VERSION 5.8 ;
BUSBITCHARS "[]" ;
DIVIDERCHAR "/" ;
UNITS
    DATABASE MICRONS 1000 ;
END UNITS

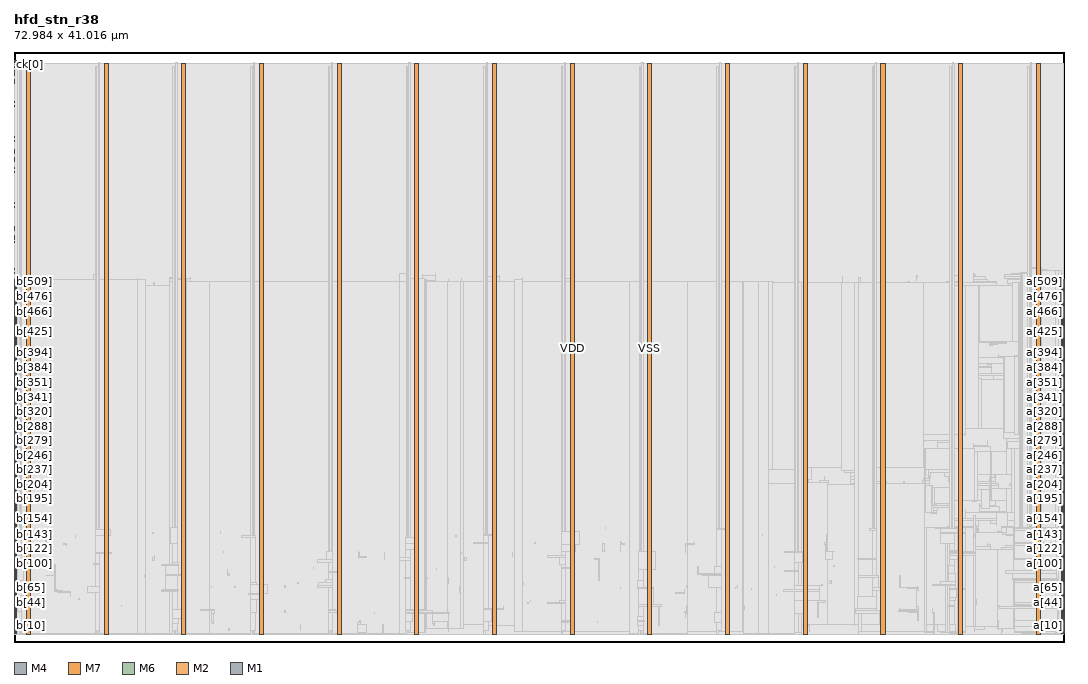
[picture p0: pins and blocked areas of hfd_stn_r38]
MACRO hfd_stn_r38
  FOREIGN hfd_stn_r38 0 0 ;
  CLASS BLOCK ;
  SIZE 72.984 BY 41.016 ;
  PIN a[0]
    DIRECTION INPUT ;
    USE SIGNAL ;
    PORT
      LAYER M4 ;
        RECT  72.792 0.624 72.984 0.648 ;
    END
  END a[0]
  PIN a[100]
    DIRECTION INPUT ;
    USE SIGNAL ;
    PORT
      LAYER M4 ;
        RECT  72.792 5.424 72.984 5.448 ;
    END
  END a[100]
  PIN a[101]
    DIRECTION INPUT ;
    USE SIGNAL ;
    PORT
      LAYER M4 ;
        RECT  72.792 5.472 72.984 5.496 ;
    END
  END a[101]
  PIN a[102]
    DIRECTION INPUT ;
    USE SIGNAL ;
    PORT
      LAYER M4 ;
        RECT  72.792 5.52 72.984 5.544 ;
    END
  END a[102]
  PIN a[103]
    DIRECTION INPUT ;
    USE SIGNAL ;
    PORT
      LAYER M4 ;
        RECT  72.792 5.568 72.984 5.592 ;
    END
  END a[103]
  PIN a[104]
    DIRECTION INPUT ;
    USE SIGNAL ;
    PORT
      LAYER M4 ;
        RECT  72.792 5.616 72.984 5.64 ;
    END
  END a[104]
  PIN a[105]
    DIRECTION INPUT ;
    USE SIGNAL ;
    PORT
      LAYER M4 ;
        RECT  72.792 5.664 72.984 5.688 ;
    END
  END a[105]
  PIN a[106]
    DIRECTION INPUT ;
    USE SIGNAL ;
    PORT
      LAYER M4 ;
        RECT  72.792 5.712 72.984 5.736 ;
    END
  END a[106]
  PIN a[107]
    DIRECTION INPUT ;
    USE SIGNAL ;
    PORT
      LAYER M4 ;
        RECT  72.792 5.76 72.984 5.784 ;
    END
  END a[107]
  PIN a[108]
    DIRECTION INPUT ;
    USE SIGNAL ;
    PORT
      LAYER M4 ;
        RECT  72.792 5.808 72.984 5.832 ;
    END
  END a[108]
  PIN a[109]
    DIRECTION INPUT ;
    USE SIGNAL ;
    PORT
      LAYER M4 ;
        RECT  72.792 5.856 72.984 5.88 ;
    END
  END a[109]
  PIN a[10]
    DIRECTION INPUT ;
    USE SIGNAL ;
    PORT
      LAYER M4 ;
        RECT  72.792 1.104 72.984 1.128 ;
    END
  END a[10]
  PIN a[110]
    DIRECTION INPUT ;
    USE SIGNAL ;
    PORT
      LAYER M4 ;
        RECT  72.792 5.904 72.984 5.928 ;
    END
  END a[110]
  PIN a[111]
    DIRECTION INPUT ;
    USE SIGNAL ;
    PORT
      LAYER M4 ;
        RECT  72.792 5.952 72.984 5.976 ;
    END
  END a[111]
  PIN a[112]
    DIRECTION INPUT ;
    USE SIGNAL ;
    PORT
      LAYER M4 ;
        RECT  72.792 6 72.984 6.024 ;
    END
  END a[112]
  PIN a[113]
    DIRECTION INPUT ;
    USE SIGNAL ;
    PORT
      LAYER M4 ;
        RECT  72.792 6.048 72.984 6.072 ;
    END
  END a[113]
  PIN a[114]
    DIRECTION INPUT ;
    USE SIGNAL ;
    PORT
      LAYER M4 ;
        RECT  72.792 6.096 72.984 6.12 ;
    END
  END a[114]
  PIN a[115]
    DIRECTION INPUT ;
    USE SIGNAL ;
    PORT
      LAYER M4 ;
        RECT  72.792 6.144 72.984 6.168 ;
    END
  END a[115]
  PIN a[116]
    DIRECTION INPUT ;
    USE SIGNAL ;
    PORT
      LAYER M4 ;
        RECT  72.792 6.192 72.984 6.216 ;
    END
  END a[116]
  PIN a[117]
    DIRECTION INPUT ;
    USE SIGNAL ;
    PORT
      LAYER M4 ;
        RECT  72.792 6.24 72.984 6.264 ;
    END
  END a[117]
  PIN a[118]
    DIRECTION INPUT ;
    USE SIGNAL ;
    PORT
      LAYER M4 ;
        RECT  72.792 6.288 72.984 6.312 ;
    END
  END a[118]
  PIN a[119]
    DIRECTION INPUT ;
    USE SIGNAL ;
    PORT
      LAYER M4 ;
        RECT  72.792 6.336 72.984 6.36 ;
    END
  END a[119]
  PIN a[11]
    DIRECTION INPUT ;
    USE SIGNAL ;
    PORT
      LAYER M4 ;
        RECT  72.792 1.152 72.984 1.176 ;
    END
  END a[11]
  PIN a[120]
    DIRECTION INPUT ;
    USE SIGNAL ;
    PORT
      LAYER M4 ;
        RECT  72.792 6.384 72.984 6.408 ;
    END
  END a[120]
  PIN a[121]
    DIRECTION INPUT ;
    USE SIGNAL ;
    PORT
      LAYER M4 ;
        RECT  72.792 6.432 72.984 6.456 ;
    END
  END a[121]
  PIN a[122]
    DIRECTION INPUT ;
    USE SIGNAL ;
    PORT
      LAYER M4 ;
        RECT  72.792 6.48 72.984 6.504 ;
    END
  END a[122]
  PIN a[123]
    DIRECTION INPUT ;
    USE SIGNAL ;
    PORT
      LAYER M4 ;
        RECT  72.792 6.528 72.984 6.552 ;
    END
  END a[123]
  PIN a[124]
    DIRECTION INPUT ;
    USE SIGNAL ;
    PORT
      LAYER M4 ;
        RECT  72.792 6.576 72.984 6.6 ;
    END
  END a[124]
  PIN a[125]
    DIRECTION INPUT ;
    USE SIGNAL ;
    PORT
      LAYER M4 ;
        RECT  72.792 6.624 72.984 6.648 ;
    END
  END a[125]
  PIN a[126]
    DIRECTION INPUT ;
    USE SIGNAL ;
    PORT
      LAYER M4 ;
        RECT  72.792 6.672 72.984 6.696 ;
    END
  END a[126]
  PIN a[127]
    DIRECTION INPUT ;
    USE SIGNAL ;
    PORT
      LAYER M4 ;
        RECT  72.792 6.72 72.984 6.744 ;
    END
  END a[127]
  PIN a[128]
    DIRECTION INPUT ;
    USE SIGNAL ;
    PORT
      LAYER M4 ;
        RECT  72.792 6.768 72.984 6.792 ;
    END
  END a[128]
  PIN a[129]
    DIRECTION INPUT ;
    USE SIGNAL ;
    PORT
      LAYER M4 ;
        RECT  72.792 6.816 72.984 6.84 ;
    END
  END a[129]
  PIN a[12]
    DIRECTION INPUT ;
    USE SIGNAL ;
    PORT
      LAYER M4 ;
        RECT  72.792 1.2 72.984 1.224 ;
    END
  END a[12]
  PIN a[130]
    DIRECTION INPUT ;
    USE SIGNAL ;
    PORT
      LAYER M4 ;
        RECT  72.792 6.864 72.984 6.888 ;
    END
  END a[130]
  PIN a[131]
    DIRECTION INPUT ;
    USE SIGNAL ;
    PORT
      LAYER M4 ;
        RECT  72.792 6.912 72.984 6.936 ;
    END
  END a[131]
  PIN a[132]
    DIRECTION INPUT ;
    USE SIGNAL ;
    PORT
      LAYER M4 ;
        RECT  72.792 6.96 72.984 6.984 ;
    END
  END a[132]
  PIN a[133]
    DIRECTION INPUT ;
    USE SIGNAL ;
    PORT
      LAYER M4 ;
        RECT  72.792 7.008 72.984 7.032 ;
    END
  END a[133]
  PIN a[134]
    DIRECTION INPUT ;
    USE SIGNAL ;
    PORT
      LAYER M4 ;
        RECT  72.792 7.056 72.984 7.08 ;
    END
  END a[134]
  PIN a[135]
    DIRECTION INPUT ;
    USE SIGNAL ;
    PORT
      LAYER M4 ;
        RECT  72.792 7.104 72.984 7.128 ;
    END
  END a[135]
  PIN a[136]
    DIRECTION INPUT ;
    USE SIGNAL ;
    PORT
      LAYER M4 ;
        RECT  72.792 7.152 72.984 7.176 ;
    END
  END a[136]
  PIN a[137]
    DIRECTION INPUT ;
    USE SIGNAL ;
    PORT
      LAYER M4 ;
        RECT  72.792 7.2 72.984 7.224 ;
    END
  END a[137]
  PIN a[138]
    DIRECTION INPUT ;
    USE SIGNAL ;
    PORT
      LAYER M4 ;
        RECT  72.792 7.248 72.984 7.272 ;
    END
  END a[138]
  PIN a[139]
    DIRECTION INPUT ;
    USE SIGNAL ;
    PORT
      LAYER M4 ;
        RECT  72.792 7.296 72.984 7.32 ;
    END
  END a[139]
  PIN a[13]
    DIRECTION INPUT ;
    USE SIGNAL ;
    PORT
      LAYER M4 ;
        RECT  72.792 1.248 72.984 1.272 ;
    END
  END a[13]
  PIN a[140]
    DIRECTION INPUT ;
    USE SIGNAL ;
    PORT
      LAYER M4 ;
        RECT  72.792 7.344 72.984 7.368 ;
    END
  END a[140]
  PIN a[141]
    DIRECTION INPUT ;
    USE SIGNAL ;
    PORT
      LAYER M4 ;
        RECT  72.792 7.392 72.984 7.416 ;
    END
  END a[141]
  PIN a[142]
    DIRECTION INPUT ;
    USE SIGNAL ;
    PORT
      LAYER M4 ;
        RECT  72.792 7.44 72.984 7.464 ;
    END
  END a[142]
  PIN a[143]
    DIRECTION INPUT ;
    USE SIGNAL ;
    PORT
      LAYER M4 ;
        RECT  72.792 7.488 72.984 7.512 ;
    END
  END a[143]
  PIN a[144]
    DIRECTION INPUT ;
    USE SIGNAL ;
    PORT
      LAYER M4 ;
        RECT  72.792 7.536 72.984 7.56 ;
    END
  END a[144]
  PIN a[145]
    DIRECTION INPUT ;
    USE SIGNAL ;
    PORT
      LAYER M4 ;
        RECT  72.792 7.584 72.984 7.608 ;
    END
  END a[145]
  PIN a[146]
    DIRECTION INPUT ;
    USE SIGNAL ;
    PORT
      LAYER M4 ;
        RECT  72.792 7.632 72.984 7.656 ;
    END
  END a[146]
  PIN a[147]
    DIRECTION INPUT ;
    USE SIGNAL ;
    PORT
      LAYER M4 ;
        RECT  72.792 7.68 72.984 7.704 ;
    END
  END a[147]
  PIN a[148]
    DIRECTION INPUT ;
    USE SIGNAL ;
    PORT
      LAYER M4 ;
        RECT  72.792 7.728 72.984 7.752 ;
    END
  END a[148]
  PIN a[149]
    DIRECTION INPUT ;
    USE SIGNAL ;
    PORT
      LAYER M4 ;
        RECT  72.792 7.776 72.984 7.8 ;
    END
  END a[149]
  PIN a[14]
    DIRECTION INPUT ;
    USE SIGNAL ;
    PORT
      LAYER M4 ;
        RECT  72.792 1.296 72.984 1.32 ;
    END
  END a[14]
  PIN a[150]
    DIRECTION INPUT ;
    USE SIGNAL ;
    PORT
      LAYER M4 ;
        RECT  72.792 7.824 72.984 7.848 ;
    END
  END a[150]
  PIN a[151]
    DIRECTION INPUT ;
    USE SIGNAL ;
    PORT
      LAYER M4 ;
        RECT  72.792 7.872 72.984 7.896 ;
    END
  END a[151]
  PIN a[152]
    DIRECTION INPUT ;
    USE SIGNAL ;
    PORT
      LAYER M4 ;
        RECT  72.792 7.92 72.984 7.944 ;
    END
  END a[152]
  PIN a[153]
    DIRECTION INPUT ;
    USE SIGNAL ;
    PORT
      LAYER M4 ;
        RECT  72.792 7.968 72.984 7.992 ;
    END
  END a[153]
  PIN a[154]
    DIRECTION INPUT ;
    USE SIGNAL ;
    PORT
      LAYER M4 ;
        RECT  72.792 8.016 72.984 8.04 ;
    END
  END a[154]
  PIN a[155]
    DIRECTION INPUT ;
    USE SIGNAL ;
    PORT
      LAYER M4 ;
        RECT  72.792 8.064 72.984 8.088 ;
    END
  END a[155]
  PIN a[156]
    DIRECTION INPUT ;
    USE SIGNAL ;
    PORT
      LAYER M4 ;
        RECT  72.792 8.112 72.984 8.136 ;
    END
  END a[156]
  PIN a[157]
    DIRECTION INPUT ;
    USE SIGNAL ;
    PORT
      LAYER M4 ;
        RECT  72.792 8.16 72.984 8.184 ;
    END
  END a[157]
  PIN a[158]
    DIRECTION INPUT ;
    USE SIGNAL ;
    PORT
      LAYER M4 ;
        RECT  72.792 8.208 72.984 8.232 ;
    END
  END a[158]
  PIN a[159]
    DIRECTION INPUT ;
    USE SIGNAL ;
    PORT
      LAYER M4 ;
        RECT  72.792 8.256 72.984 8.28 ;
    END
  END a[159]
  PIN a[15]
    DIRECTION INPUT ;
    USE SIGNAL ;
    PORT
      LAYER M4 ;
        RECT  72.792 1.344 72.984 1.368 ;
    END
  END a[15]
  PIN a[160]
    DIRECTION INPUT ;
    USE SIGNAL ;
    PORT
      LAYER M4 ;
        RECT  72.792 8.304 72.984 8.328 ;
    END
  END a[160]
  PIN a[161]
    DIRECTION INPUT ;
    USE SIGNAL ;
    PORT
      LAYER M4 ;
        RECT  72.792 8.352 72.984 8.376 ;
    END
  END a[161]
  PIN a[162]
    DIRECTION INPUT ;
    USE SIGNAL ;
    PORT
      LAYER M4 ;
        RECT  72.792 8.4 72.984 8.424 ;
    END
  END a[162]
  PIN a[163]
    DIRECTION INPUT ;
    USE SIGNAL ;
    PORT
      LAYER M4 ;
        RECT  72.792 8.448 72.984 8.472 ;
    END
  END a[163]
  PIN a[164]
    DIRECTION INPUT ;
    USE SIGNAL ;
    PORT
      LAYER M4 ;
        RECT  72.792 8.496 72.984 8.52 ;
    END
  END a[164]
  PIN a[165]
    DIRECTION INPUT ;
    USE SIGNAL ;
    PORT
      LAYER M4 ;
        RECT  72.792 8.544 72.984 8.568 ;
    END
  END a[165]
  PIN a[166]
    DIRECTION INPUT ;
    USE SIGNAL ;
    PORT
      LAYER M4 ;
        RECT  72.792 8.592 72.984 8.616 ;
    END
  END a[166]
  PIN a[167]
    DIRECTION INPUT ;
    USE SIGNAL ;
    PORT
      LAYER M4 ;
        RECT  72.792 8.64 72.984 8.664 ;
    END
  END a[167]
  PIN a[168]
    DIRECTION INPUT ;
    USE SIGNAL ;
    PORT
      LAYER M4 ;
        RECT  72.792 8.688 72.984 8.712 ;
    END
  END a[168]
  PIN a[169]
    DIRECTION INPUT ;
    USE SIGNAL ;
    PORT
      LAYER M4 ;
        RECT  72.792 8.736 72.984 8.76 ;
    END
  END a[169]
  PIN a[16]
    DIRECTION INPUT ;
    USE SIGNAL ;
    PORT
      LAYER M4 ;
        RECT  72.792 1.392 72.984 1.416 ;
    END
  END a[16]
  PIN a[170]
    DIRECTION INPUT ;
    USE SIGNAL ;
    PORT
      LAYER M4 ;
        RECT  72.792 8.784 72.984 8.808 ;
    END
  END a[170]
  PIN a[171]
    DIRECTION INPUT ;
    USE SIGNAL ;
    PORT
      LAYER M4 ;
        RECT  72.792 8.832 72.984 8.856 ;
    END
  END a[171]
  PIN a[172]
    DIRECTION INPUT ;
    USE SIGNAL ;
    PORT
      LAYER M4 ;
        RECT  72.792 8.88 72.984 8.904 ;
    END
  END a[172]
  PIN a[173]
    DIRECTION INPUT ;
    USE SIGNAL ;
    PORT
      LAYER M4 ;
        RECT  72.792 8.928 72.984 8.952 ;
    END
  END a[173]
  PIN a[174]
    DIRECTION INPUT ;
    USE SIGNAL ;
    PORT
      LAYER M4 ;
        RECT  72.792 8.976 72.984 9 ;
    END
  END a[174]
  PIN a[175]
    DIRECTION INPUT ;
    USE SIGNAL ;
    PORT
      LAYER M4 ;
        RECT  72.792 9.024 72.984 9.048 ;
    END
  END a[175]
  PIN a[176]
    DIRECTION INPUT ;
    USE SIGNAL ;
    PORT
      LAYER M4 ;
        RECT  72.792 9.072 72.984 9.096 ;
    END
  END a[176]
  PIN a[177]
    DIRECTION INPUT ;
    USE SIGNAL ;
    PORT
      LAYER M4 ;
        RECT  72.792 9.12 72.984 9.144 ;
    END
  END a[177]
  PIN a[178]
    DIRECTION INPUT ;
    USE SIGNAL ;
    PORT
      LAYER M4 ;
        RECT  72.792 9.168 72.984 9.192 ;
    END
  END a[178]
  PIN a[179]
    DIRECTION INPUT ;
    USE SIGNAL ;
    PORT
      LAYER M4 ;
        RECT  72.792 9.216 72.984 9.24 ;
    END
  END a[179]
  PIN a[17]
    DIRECTION INPUT ;
    USE SIGNAL ;
    PORT
      LAYER M4 ;
        RECT  72.792 1.44 72.984 1.464 ;
    END
  END a[17]
  PIN a[180]
    DIRECTION INPUT ;
    USE SIGNAL ;
    PORT
      LAYER M4 ;
        RECT  72.792 9.264 72.984 9.288 ;
    END
  END a[180]
  PIN a[181]
    DIRECTION INPUT ;
    USE SIGNAL ;
    PORT
      LAYER M4 ;
        RECT  72.792 9.312 72.984 9.336 ;
    END
  END a[181]
  PIN a[182]
    DIRECTION INPUT ;
    USE SIGNAL ;
    PORT
      LAYER M4 ;
        RECT  72.792 9.36 72.984 9.384 ;
    END
  END a[182]
  PIN a[183]
    DIRECTION INPUT ;
    USE SIGNAL ;
    PORT
      LAYER M4 ;
        RECT  72.792 9.408 72.984 9.432 ;
    END
  END a[183]
  PIN a[184]
    DIRECTION INPUT ;
    USE SIGNAL ;
    PORT
      LAYER M4 ;
        RECT  72.792 9.456 72.984 9.48 ;
    END
  END a[184]
  PIN a[185]
    DIRECTION INPUT ;
    USE SIGNAL ;
    PORT
      LAYER M4 ;
        RECT  72.792 9.504 72.984 9.528 ;
    END
  END a[185]
  PIN a[186]
    DIRECTION INPUT ;
    USE SIGNAL ;
    PORT
      LAYER M4 ;
        RECT  72.792 9.552 72.984 9.576 ;
    END
  END a[186]
  PIN a[187]
    DIRECTION INPUT ;
    USE SIGNAL ;
    PORT
      LAYER M4 ;
        RECT  72.792 9.6 72.984 9.624 ;
    END
  END a[187]
  PIN a[188]
    DIRECTION INPUT ;
    USE SIGNAL ;
    PORT
      LAYER M4 ;
        RECT  72.792 9.648 72.984 9.672 ;
    END
  END a[188]
  PIN a[189]
    DIRECTION INPUT ;
    USE SIGNAL ;
    PORT
      LAYER M4 ;
        RECT  72.792 9.696 72.984 9.72 ;
    END
  END a[189]
  PIN a[18]
    DIRECTION INPUT ;
    USE SIGNAL ;
    PORT
      LAYER M4 ;
        RECT  72.792 1.488 72.984 1.512 ;
    END
  END a[18]
  PIN a[190]
    DIRECTION INPUT ;
    USE SIGNAL ;
    PORT
      LAYER M4 ;
        RECT  72.792 9.744 72.984 9.768 ;
    END
  END a[190]
  PIN a[191]
    DIRECTION INPUT ;
    USE SIGNAL ;
    PORT
      LAYER M4 ;
        RECT  72.792 9.792 72.984 9.816 ;
    END
  END a[191]
  PIN a[192]
    DIRECTION INPUT ;
    USE SIGNAL ;
    PORT
      LAYER M4 ;
        RECT  72.792 9.84 72.984 9.864 ;
    END
  END a[192]
  PIN a[193]
    DIRECTION INPUT ;
    USE SIGNAL ;
    PORT
      LAYER M4 ;
        RECT  72.792 9.888 72.984 9.912 ;
    END
  END a[193]
  PIN a[194]
    DIRECTION INPUT ;
    USE SIGNAL ;
    PORT
      LAYER M4 ;
        RECT  72.792 9.936 72.984 9.96 ;
    END
  END a[194]
  PIN a[195]
    DIRECTION INPUT ;
    USE SIGNAL ;
    PORT
      LAYER M4 ;
        RECT  72.792 9.984 72.984 10.008 ;
    END
  END a[195]
  PIN a[196]
    DIRECTION INPUT ;
    USE SIGNAL ;
    PORT
      LAYER M4 ;
        RECT  72.792 10.032 72.984 10.056 ;
    END
  END a[196]
  PIN a[197]
    DIRECTION INPUT ;
    USE SIGNAL ;
    PORT
      LAYER M4 ;
        RECT  72.792 10.08 72.984 10.104 ;
    END
  END a[197]
  PIN a[198]
    DIRECTION INPUT ;
    USE SIGNAL ;
    PORT
      LAYER M4 ;
        RECT  72.792 10.128 72.984 10.152 ;
    END
  END a[198]
  PIN a[199]
    DIRECTION INPUT ;
    USE SIGNAL ;
    PORT
      LAYER M4 ;
        RECT  72.792 10.176 72.984 10.2 ;
    END
  END a[199]
  PIN a[19]
    DIRECTION INPUT ;
    USE SIGNAL ;
    PORT
      LAYER M4 ;
        RECT  72.792 1.536 72.984 1.56 ;
    END
  END a[19]
  PIN a[1]
    DIRECTION INPUT ;
    USE SIGNAL ;
    PORT
      LAYER M4 ;
        RECT  72.792 0.672 72.984 0.696 ;
    END
  END a[1]
  PIN a[200]
    DIRECTION INPUT ;
    USE SIGNAL ;
    PORT
      LAYER M4 ;
        RECT  72.792 10.224 72.984 10.248 ;
    END
  END a[200]
  PIN a[201]
    DIRECTION INPUT ;
    USE SIGNAL ;
    PORT
      LAYER M4 ;
        RECT  72.792 10.272 72.984 10.296 ;
    END
  END a[201]
  PIN a[202]
    DIRECTION INPUT ;
    USE SIGNAL ;
    PORT
      LAYER M4 ;
        RECT  72.792 10.32 72.984 10.344 ;
    END
  END a[202]
  PIN a[203]
    DIRECTION INPUT ;
    USE SIGNAL ;
    PORT
      LAYER M4 ;
        RECT  72.792 10.368 72.984 10.392 ;
    END
  END a[203]
  PIN a[204]
    DIRECTION INPUT ;
    USE SIGNAL ;
    PORT
      LAYER M4 ;
        RECT  72.792 10.416 72.984 10.44 ;
    END
  END a[204]
  PIN a[205]
    DIRECTION INPUT ;
    USE SIGNAL ;
    PORT
      LAYER M4 ;
        RECT  72.792 10.464 72.984 10.488 ;
    END
  END a[205]
  PIN a[206]
    DIRECTION INPUT ;
    USE SIGNAL ;
    PORT
      LAYER M4 ;
        RECT  72.792 10.512 72.984 10.536 ;
    END
  END a[206]
  PIN a[207]
    DIRECTION INPUT ;
    USE SIGNAL ;
    PORT
      LAYER M4 ;
        RECT  72.792 10.56 72.984 10.584 ;
    END
  END a[207]
  PIN a[208]
    DIRECTION INPUT ;
    USE SIGNAL ;
    PORT
      LAYER M4 ;
        RECT  72.792 10.608 72.984 10.632 ;
    END
  END a[208]
  PIN a[209]
    DIRECTION INPUT ;
    USE SIGNAL ;
    PORT
      LAYER M4 ;
        RECT  72.792 10.656 72.984 10.68 ;
    END
  END a[209]
  PIN a[20]
    DIRECTION INPUT ;
    USE SIGNAL ;
    PORT
      LAYER M4 ;
        RECT  72.792 1.584 72.984 1.608 ;
    END
  END a[20]
  PIN a[210]
    DIRECTION INPUT ;
    USE SIGNAL ;
    PORT
      LAYER M4 ;
        RECT  72.792 10.704 72.984 10.728 ;
    END
  END a[210]
  PIN a[211]
    DIRECTION INPUT ;
    USE SIGNAL ;
    PORT
      LAYER M4 ;
        RECT  72.792 10.752 72.984 10.776 ;
    END
  END a[211]
  PIN a[212]
    DIRECTION INPUT ;
    USE SIGNAL ;
    PORT
      LAYER M4 ;
        RECT  72.792 10.8 72.984 10.824 ;
    END
  END a[212]
  PIN a[213]
    DIRECTION INPUT ;
    USE SIGNAL ;
    PORT
      LAYER M4 ;
        RECT  72.792 10.848 72.984 10.872 ;
    END
  END a[213]
  PIN a[214]
    DIRECTION INPUT ;
    USE SIGNAL ;
    PORT
      LAYER M4 ;
        RECT  72.792 10.896 72.984 10.92 ;
    END
  END a[214]
  PIN a[215]
    DIRECTION INPUT ;
    USE SIGNAL ;
    PORT
      LAYER M4 ;
        RECT  72.792 10.944 72.984 10.968 ;
    END
  END a[215]
  PIN a[216]
    DIRECTION INPUT ;
    USE SIGNAL ;
    PORT
      LAYER M4 ;
        RECT  72.792 10.992 72.984 11.016 ;
    END
  END a[216]
  PIN a[217]
    DIRECTION INPUT ;
    USE SIGNAL ;
    PORT
      LAYER M4 ;
        RECT  72.792 11.04 72.984 11.064 ;
    END
  END a[217]
  PIN a[218]
    DIRECTION INPUT ;
    USE SIGNAL ;
    PORT
      LAYER M4 ;
        RECT  72.792 11.088 72.984 11.112 ;
    END
  END a[218]
  PIN a[219]
    DIRECTION INPUT ;
    USE SIGNAL ;
    PORT
      LAYER M4 ;
        RECT  72.792 11.136 72.984 11.16 ;
    END
  END a[219]
  PIN a[21]
    DIRECTION INPUT ;
    USE SIGNAL ;
    PORT
      LAYER M4 ;
        RECT  72.792 1.632 72.984 1.656 ;
    END
  END a[21]
  PIN a[220]
    DIRECTION INPUT ;
    USE SIGNAL ;
    PORT
      LAYER M4 ;
        RECT  72.792 11.184 72.984 11.208 ;
    END
  END a[220]
  PIN a[221]
    DIRECTION INPUT ;
    USE SIGNAL ;
    PORT
      LAYER M4 ;
        RECT  72.792 11.232 72.984 11.256 ;
    END
  END a[221]
  PIN a[222]
    DIRECTION INPUT ;
    USE SIGNAL ;
    PORT
      LAYER M4 ;
        RECT  72.792 11.28 72.984 11.304 ;
    END
  END a[222]
  PIN a[223]
    DIRECTION INPUT ;
    USE SIGNAL ;
    PORT
      LAYER M4 ;
        RECT  72.792 11.328 72.984 11.352 ;
    END
  END a[223]
  PIN a[224]
    DIRECTION INPUT ;
    USE SIGNAL ;
    PORT
      LAYER M4 ;
        RECT  72.792 11.376 72.984 11.4 ;
    END
  END a[224]
  PIN a[225]
    DIRECTION INPUT ;
    USE SIGNAL ;
    PORT
      LAYER M4 ;
        RECT  72.792 11.424 72.984 11.448 ;
    END
  END a[225]
  PIN a[226]
    DIRECTION INPUT ;
    USE SIGNAL ;
    PORT
      LAYER M4 ;
        RECT  72.792 11.472 72.984 11.496 ;
    END
  END a[226]
  PIN a[227]
    DIRECTION INPUT ;
    USE SIGNAL ;
    PORT
      LAYER M4 ;
        RECT  72.792 11.52 72.984 11.544 ;
    END
  END a[227]
  PIN a[228]
    DIRECTION INPUT ;
    USE SIGNAL ;
    PORT
      LAYER M4 ;
        RECT  72.792 11.568 72.984 11.592 ;
    END
  END a[228]
  PIN a[229]
    DIRECTION INPUT ;
    USE SIGNAL ;
    PORT
      LAYER M4 ;
        RECT  72.792 11.616 72.984 11.64 ;
    END
  END a[229]
  PIN a[22]
    DIRECTION INPUT ;
    USE SIGNAL ;
    PORT
      LAYER M4 ;
        RECT  72.792 1.68 72.984 1.704 ;
    END
  END a[22]
  PIN a[230]
    DIRECTION INPUT ;
    USE SIGNAL ;
    PORT
      LAYER M4 ;
        RECT  72.792 11.664 72.984 11.688 ;
    END
  END a[230]
  PIN a[231]
    DIRECTION INPUT ;
    USE SIGNAL ;
    PORT
      LAYER M4 ;
        RECT  72.792 11.712 72.984 11.736 ;
    END
  END a[231]
  PIN a[232]
    DIRECTION INPUT ;
    USE SIGNAL ;
    PORT
      LAYER M4 ;
        RECT  72.792 11.76 72.984 11.784 ;
    END
  END a[232]
  PIN a[233]
    DIRECTION INPUT ;
    USE SIGNAL ;
    PORT
      LAYER M4 ;
        RECT  72.792 11.808 72.984 11.832 ;
    END
  END a[233]
  PIN a[234]
    DIRECTION INPUT ;
    USE SIGNAL ;
    PORT
      LAYER M4 ;
        RECT  72.792 11.856 72.984 11.88 ;
    END
  END a[234]
  PIN a[235]
    DIRECTION INPUT ;
    USE SIGNAL ;
    PORT
      LAYER M4 ;
        RECT  72.792 11.904 72.984 11.928 ;
    END
  END a[235]
  PIN a[236]
    DIRECTION INPUT ;
    USE SIGNAL ;
    PORT
      LAYER M4 ;
        RECT  72.792 11.952 72.984 11.976 ;
    END
  END a[236]
  PIN a[237]
    DIRECTION INPUT ;
    USE SIGNAL ;
    PORT
      LAYER M4 ;
        RECT  72.792 12 72.984 12.024 ;
    END
  END a[237]
  PIN a[238]
    DIRECTION INPUT ;
    USE SIGNAL ;
    PORT
      LAYER M4 ;
        RECT  72.792 12.048 72.984 12.072 ;
    END
  END a[238]
  PIN a[239]
    DIRECTION INPUT ;
    USE SIGNAL ;
    PORT
      LAYER M4 ;
        RECT  72.792 12.096 72.984 12.12 ;
    END
  END a[239]
  PIN a[23]
    DIRECTION INPUT ;
    USE SIGNAL ;
    PORT
      LAYER M4 ;
        RECT  72.792 1.728 72.984 1.752 ;
    END
  END a[23]
  PIN a[240]
    DIRECTION INPUT ;
    USE SIGNAL ;
    PORT
      LAYER M4 ;
        RECT  72.792 12.144 72.984 12.168 ;
    END
  END a[240]
  PIN a[241]
    DIRECTION INPUT ;
    USE SIGNAL ;
    PORT
      LAYER M4 ;
        RECT  72.792 12.192 72.984 12.216 ;
    END
  END a[241]
  PIN a[242]
    DIRECTION INPUT ;
    USE SIGNAL ;
    PORT
      LAYER M4 ;
        RECT  72.792 12.24 72.984 12.264 ;
    END
  END a[242]
  PIN a[243]
    DIRECTION INPUT ;
    USE SIGNAL ;
    PORT
      LAYER M4 ;
        RECT  72.792 12.288 72.984 12.312 ;
    END
  END a[243]
  PIN a[244]
    DIRECTION INPUT ;
    USE SIGNAL ;
    PORT
      LAYER M4 ;
        RECT  72.792 12.336 72.984 12.36 ;
    END
  END a[244]
  PIN a[245]
    DIRECTION INPUT ;
    USE SIGNAL ;
    PORT
      LAYER M4 ;
        RECT  72.792 12.384 72.984 12.408 ;
    END
  END a[245]
  PIN a[246]
    DIRECTION INPUT ;
    USE SIGNAL ;
    PORT
      LAYER M4 ;
        RECT  72.792 12.432 72.984 12.456 ;
    END
  END a[246]
  PIN a[247]
    DIRECTION INPUT ;
    USE SIGNAL ;
    PORT
      LAYER M4 ;
        RECT  72.792 12.48 72.984 12.504 ;
    END
  END a[247]
  PIN a[248]
    DIRECTION INPUT ;
    USE SIGNAL ;
    PORT
      LAYER M4 ;
        RECT  72.792 12.528 72.984 12.552 ;
    END
  END a[248]
  PIN a[249]
    DIRECTION INPUT ;
    USE SIGNAL ;
    PORT
      LAYER M4 ;
        RECT  72.792 12.576 72.984 12.6 ;
    END
  END a[249]
  PIN a[24]
    DIRECTION INPUT ;
    USE SIGNAL ;
    PORT
      LAYER M4 ;
        RECT  72.792 1.776 72.984 1.8 ;
    END
  END a[24]
  PIN a[250]
    DIRECTION INPUT ;
    USE SIGNAL ;
    PORT
      LAYER M4 ;
        RECT  72.792 12.624 72.984 12.648 ;
    END
  END a[250]
  PIN a[251]
    DIRECTION INPUT ;
    USE SIGNAL ;
    PORT
      LAYER M4 ;
        RECT  72.792 12.672 72.984 12.696 ;
    END
  END a[251]
  PIN a[252]
    DIRECTION INPUT ;
    USE SIGNAL ;
    PORT
      LAYER M4 ;
        RECT  72.792 12.72 72.984 12.744 ;
    END
  END a[252]
  PIN a[253]
    DIRECTION INPUT ;
    USE SIGNAL ;
    PORT
      LAYER M4 ;
        RECT  72.792 12.768 72.984 12.792 ;
    END
  END a[253]
  PIN a[254]
    DIRECTION INPUT ;
    USE SIGNAL ;
    PORT
      LAYER M4 ;
        RECT  72.792 12.816 72.984 12.84 ;
    END
  END a[254]
  PIN a[255]
    DIRECTION INPUT ;
    USE SIGNAL ;
    PORT
      LAYER M4 ;
        RECT  72.792 12.864 72.984 12.888 ;
    END
  END a[255]
  PIN a[256]
    DIRECTION INPUT ;
    USE SIGNAL ;
    PORT
      LAYER M4 ;
        RECT  72.792 12.912 72.984 12.936 ;
    END
  END a[256]
  PIN a[257]
    DIRECTION INPUT ;
    USE SIGNAL ;
    PORT
      LAYER M4 ;
        RECT  72.792 12.96 72.984 12.984 ;
    END
  END a[257]
  PIN a[258]
    DIRECTION INPUT ;
    USE SIGNAL ;
    PORT
      LAYER M4 ;
        RECT  72.792 13.008 72.984 13.032 ;
    END
  END a[258]
  PIN a[259]
    DIRECTION INPUT ;
    USE SIGNAL ;
    PORT
      LAYER M4 ;
        RECT  72.792 13.056 72.984 13.08 ;
    END
  END a[259]
  PIN a[25]
    DIRECTION INPUT ;
    USE SIGNAL ;
    PORT
      LAYER M4 ;
        RECT  72.792 1.824 72.984 1.848 ;
    END
  END a[25]
  PIN a[260]
    DIRECTION INPUT ;
    USE SIGNAL ;
    PORT
      LAYER M4 ;
        RECT  72.792 13.104 72.984 13.128 ;
    END
  END a[260]
  PIN a[261]
    DIRECTION INPUT ;
    USE SIGNAL ;
    PORT
      LAYER M4 ;
        RECT  72.792 13.152 72.984 13.176 ;
    END
  END a[261]
  PIN a[262]
    DIRECTION INPUT ;
    USE SIGNAL ;
    PORT
      LAYER M4 ;
        RECT  72.792 13.2 72.984 13.224 ;
    END
  END a[262]
  PIN a[263]
    DIRECTION INPUT ;
    USE SIGNAL ;
    PORT
      LAYER M4 ;
        RECT  72.792 13.248 72.984 13.272 ;
    END
  END a[263]
  PIN a[264]
    DIRECTION INPUT ;
    USE SIGNAL ;
    PORT
      LAYER M4 ;
        RECT  72.792 13.296 72.984 13.32 ;
    END
  END a[264]
  PIN a[265]
    DIRECTION INPUT ;
    USE SIGNAL ;
    PORT
      LAYER M4 ;
        RECT  72.792 13.344 72.984 13.368 ;
    END
  END a[265]
  PIN a[266]
    DIRECTION INPUT ;
    USE SIGNAL ;
    PORT
      LAYER M4 ;
        RECT  72.792 13.392 72.984 13.416 ;
    END
  END a[266]
  PIN a[267]
    DIRECTION INPUT ;
    USE SIGNAL ;
    PORT
      LAYER M4 ;
        RECT  72.792 13.44 72.984 13.464 ;
    END
  END a[267]
  PIN a[268]
    DIRECTION INPUT ;
    USE SIGNAL ;
    PORT
      LAYER M4 ;
        RECT  72.792 13.488 72.984 13.512 ;
    END
  END a[268]
  PIN a[269]
    DIRECTION INPUT ;
    USE SIGNAL ;
    PORT
      LAYER M4 ;
        RECT  72.792 13.536 72.984 13.56 ;
    END
  END a[269]
  PIN a[26]
    DIRECTION INPUT ;
    USE SIGNAL ;
    PORT
      LAYER M4 ;
        RECT  72.792 1.872 72.984 1.896 ;
    END
  END a[26]
  PIN a[270]
    DIRECTION INPUT ;
    USE SIGNAL ;
    PORT
      LAYER M4 ;
        RECT  72.792 13.584 72.984 13.608 ;
    END
  END a[270]
  PIN a[271]
    DIRECTION INPUT ;
    USE SIGNAL ;
    PORT
      LAYER M4 ;
        RECT  72.792 13.632 72.984 13.656 ;
    END
  END a[271]
  PIN a[272]
    DIRECTION INPUT ;
    USE SIGNAL ;
    PORT
      LAYER M4 ;
        RECT  72.792 13.68 72.984 13.704 ;
    END
  END a[272]
  PIN a[273]
    DIRECTION INPUT ;
    USE SIGNAL ;
    PORT
      LAYER M4 ;
        RECT  72.792 13.728 72.984 13.752 ;
    END
  END a[273]
  PIN a[274]
    DIRECTION INPUT ;
    USE SIGNAL ;
    PORT
      LAYER M4 ;
        RECT  72.792 13.776 72.984 13.8 ;
    END
  END a[274]
  PIN a[275]
    DIRECTION INPUT ;
    USE SIGNAL ;
    PORT
      LAYER M4 ;
        RECT  72.792 13.824 72.984 13.848 ;
    END
  END a[275]
  PIN a[276]
    DIRECTION INPUT ;
    USE SIGNAL ;
    PORT
      LAYER M4 ;
        RECT  72.792 13.872 72.984 13.896 ;
    END
  END a[276]
  PIN a[277]
    DIRECTION INPUT ;
    USE SIGNAL ;
    PORT
      LAYER M4 ;
        RECT  72.792 13.92 72.984 13.944 ;
    END
  END a[277]
  PIN a[278]
    DIRECTION INPUT ;
    USE SIGNAL ;
    PORT
      LAYER M4 ;
        RECT  72.792 13.968 72.984 13.992 ;
    END
  END a[278]
  PIN a[279]
    DIRECTION INPUT ;
    USE SIGNAL ;
    PORT
      LAYER M4 ;
        RECT  72.792 14.016 72.984 14.04 ;
    END
  END a[279]
  PIN a[27]
    DIRECTION INPUT ;
    USE SIGNAL ;
    PORT
      LAYER M4 ;
        RECT  72.792 1.92 72.984 1.944 ;
    END
  END a[27]
  PIN a[280]
    DIRECTION INPUT ;
    USE SIGNAL ;
    PORT
      LAYER M4 ;
        RECT  72.792 14.064 72.984 14.088 ;
    END
  END a[280]
  PIN a[281]
    DIRECTION INPUT ;
    USE SIGNAL ;
    PORT
      LAYER M4 ;
        RECT  72.792 14.112 72.984 14.136 ;
    END
  END a[281]
  PIN a[282]
    DIRECTION INPUT ;
    USE SIGNAL ;
    PORT
      LAYER M4 ;
        RECT  72.792 14.16 72.984 14.184 ;
    END
  END a[282]
  PIN a[283]
    DIRECTION INPUT ;
    USE SIGNAL ;
    PORT
      LAYER M4 ;
        RECT  72.792 14.208 72.984 14.232 ;
    END
  END a[283]
  PIN a[284]
    DIRECTION INPUT ;
    USE SIGNAL ;
    PORT
      LAYER M4 ;
        RECT  72.792 14.256 72.984 14.28 ;
    END
  END a[284]
  PIN a[285]
    DIRECTION INPUT ;
    USE SIGNAL ;
    PORT
      LAYER M4 ;
        RECT  72.792 14.304 72.984 14.328 ;
    END
  END a[285]
  PIN a[286]
    DIRECTION INPUT ;
    USE SIGNAL ;
    PORT
      LAYER M4 ;
        RECT  72.792 14.352 72.984 14.376 ;
    END
  END a[286]
  PIN a[287]
    DIRECTION INPUT ;
    USE SIGNAL ;
    PORT
      LAYER M4 ;
        RECT  72.792 14.4 72.984 14.424 ;
    END
  END a[287]
  PIN a[288]
    DIRECTION INPUT ;
    USE SIGNAL ;
    PORT
      LAYER M4 ;
        RECT  72.792 14.448 72.984 14.472 ;
    END
  END a[288]
  PIN a[289]
    DIRECTION INPUT ;
    USE SIGNAL ;
    PORT
      LAYER M4 ;
        RECT  72.792 14.496 72.984 14.52 ;
    END
  END a[289]
  PIN a[28]
    DIRECTION INPUT ;
    USE SIGNAL ;
    PORT
      LAYER M4 ;
        RECT  72.792 1.968 72.984 1.992 ;
    END
  END a[28]
  PIN a[290]
    DIRECTION INPUT ;
    USE SIGNAL ;
    PORT
      LAYER M4 ;
        RECT  72.792 14.544 72.984 14.568 ;
    END
  END a[290]
  PIN a[291]
    DIRECTION INPUT ;
    USE SIGNAL ;
    PORT
      LAYER M4 ;
        RECT  72.792 14.592 72.984 14.616 ;
    END
  END a[291]
  PIN a[292]
    DIRECTION INPUT ;
    USE SIGNAL ;
    PORT
      LAYER M4 ;
        RECT  72.792 14.64 72.984 14.664 ;
    END
  END a[292]
  PIN a[293]
    DIRECTION INPUT ;
    USE SIGNAL ;
    PORT
      LAYER M4 ;
        RECT  72.792 14.688 72.984 14.712 ;
    END
  END a[293]
  PIN a[294]
    DIRECTION INPUT ;
    USE SIGNAL ;
    PORT
      LAYER M4 ;
        RECT  72.792 14.736 72.984 14.76 ;
    END
  END a[294]
  PIN a[295]
    DIRECTION INPUT ;
    USE SIGNAL ;
    PORT
      LAYER M4 ;
        RECT  72.792 14.784 72.984 14.808 ;
    END
  END a[295]
  PIN a[296]
    DIRECTION INPUT ;
    USE SIGNAL ;
    PORT
      LAYER M4 ;
        RECT  72.792 14.832 72.984 14.856 ;
    END
  END a[296]
  PIN a[297]
    DIRECTION INPUT ;
    USE SIGNAL ;
    PORT
      LAYER M4 ;
        RECT  72.792 14.88 72.984 14.904 ;
    END
  END a[297]
  PIN a[298]
    DIRECTION INPUT ;
    USE SIGNAL ;
    PORT
      LAYER M4 ;
        RECT  72.792 14.928 72.984 14.952 ;
    END
  END a[298]
  PIN a[299]
    DIRECTION INPUT ;
    USE SIGNAL ;
    PORT
      LAYER M4 ;
        RECT  72.792 14.976 72.984 15 ;
    END
  END a[299]
  PIN a[29]
    DIRECTION INPUT ;
    USE SIGNAL ;
    PORT
      LAYER M4 ;
        RECT  72.792 2.016 72.984 2.04 ;
    END
  END a[29]
  PIN a[2]
    DIRECTION INPUT ;
    USE SIGNAL ;
    PORT
      LAYER M4 ;
        RECT  72.792 0.72 72.984 0.744 ;
    END
  END a[2]
  PIN a[300]
    DIRECTION INPUT ;
    USE SIGNAL ;
    PORT
      LAYER M4 ;
        RECT  72.792 15.024 72.984 15.048 ;
    END
  END a[300]
  PIN a[301]
    DIRECTION INPUT ;
    USE SIGNAL ;
    PORT
      LAYER M4 ;
        RECT  72.792 15.072 72.984 15.096 ;
    END
  END a[301]
  PIN a[302]
    DIRECTION INPUT ;
    USE SIGNAL ;
    PORT
      LAYER M4 ;
        RECT  72.792 15.12 72.984 15.144 ;
    END
  END a[302]
  PIN a[303]
    DIRECTION INPUT ;
    USE SIGNAL ;
    PORT
      LAYER M4 ;
        RECT  72.792 15.168 72.984 15.192 ;
    END
  END a[303]
  PIN a[304]
    DIRECTION INPUT ;
    USE SIGNAL ;
    PORT
      LAYER M4 ;
        RECT  72.792 15.216 72.984 15.24 ;
    END
  END a[304]
  PIN a[305]
    DIRECTION INPUT ;
    USE SIGNAL ;
    PORT
      LAYER M4 ;
        RECT  72.792 15.264 72.984 15.288 ;
    END
  END a[305]
  PIN a[306]
    DIRECTION INPUT ;
    USE SIGNAL ;
    PORT
      LAYER M4 ;
        RECT  72.792 15.312 72.984 15.336 ;
    END
  END a[306]
  PIN a[307]
    DIRECTION INPUT ;
    USE SIGNAL ;
    PORT
      LAYER M4 ;
        RECT  72.792 15.36 72.984 15.384 ;
    END
  END a[307]
  PIN a[308]
    DIRECTION INPUT ;
    USE SIGNAL ;
    PORT
      LAYER M4 ;
        RECT  72.792 15.408 72.984 15.432 ;
    END
  END a[308]
  PIN a[309]
    DIRECTION INPUT ;
    USE SIGNAL ;
    PORT
      LAYER M4 ;
        RECT  72.792 15.456 72.984 15.48 ;
    END
  END a[309]
  PIN a[30]
    DIRECTION INPUT ;
    USE SIGNAL ;
    PORT
      LAYER M4 ;
        RECT  72.792 2.064 72.984 2.088 ;
    END
  END a[30]
  PIN a[310]
    DIRECTION INPUT ;
    USE SIGNAL ;
    PORT
      LAYER M4 ;
        RECT  72.792 15.504 72.984 15.528 ;
    END
  END a[310]
  PIN a[311]
    DIRECTION INPUT ;
    USE SIGNAL ;
    PORT
      LAYER M4 ;
        RECT  72.792 15.552 72.984 15.576 ;
    END
  END a[311]
  PIN a[312]
    DIRECTION INPUT ;
    USE SIGNAL ;
    PORT
      LAYER M4 ;
        RECT  72.792 15.6 72.984 15.624 ;
    END
  END a[312]
  PIN a[313]
    DIRECTION INPUT ;
    USE SIGNAL ;
    PORT
      LAYER M4 ;
        RECT  72.792 15.648 72.984 15.672 ;
    END
  END a[313]
  PIN a[314]
    DIRECTION INPUT ;
    USE SIGNAL ;
    PORT
      LAYER M4 ;
        RECT  72.792 15.696 72.984 15.72 ;
    END
  END a[314]
  PIN a[315]
    DIRECTION INPUT ;
    USE SIGNAL ;
    PORT
      LAYER M4 ;
        RECT  72.792 15.744 72.984 15.768 ;
    END
  END a[315]
  PIN a[316]
    DIRECTION INPUT ;
    USE SIGNAL ;
    PORT
      LAYER M4 ;
        RECT  72.792 15.792 72.984 15.816 ;
    END
  END a[316]
  PIN a[317]
    DIRECTION INPUT ;
    USE SIGNAL ;
    PORT
      LAYER M4 ;
        RECT  72.792 15.84 72.984 15.864 ;
    END
  END a[317]
  PIN a[318]
    DIRECTION INPUT ;
    USE SIGNAL ;
    PORT
      LAYER M4 ;
        RECT  72.792 15.888 72.984 15.912 ;
    END
  END a[318]
  PIN a[319]
    DIRECTION INPUT ;
    USE SIGNAL ;
    PORT
      LAYER M4 ;
        RECT  72.792 15.936 72.984 15.96 ;
    END
  END a[319]
  PIN a[31]
    DIRECTION INPUT ;
    USE SIGNAL ;
    PORT
      LAYER M4 ;
        RECT  72.792 2.112 72.984 2.136 ;
    END
  END a[31]
  PIN a[320]
    DIRECTION INPUT ;
    USE SIGNAL ;
    PORT
      LAYER M4 ;
        RECT  72.792 15.984 72.984 16.008 ;
    END
  END a[320]
  PIN a[321]
    DIRECTION INPUT ;
    USE SIGNAL ;
    PORT
      LAYER M4 ;
        RECT  72.792 16.032 72.984 16.056 ;
    END
  END a[321]
  PIN a[322]
    DIRECTION INPUT ;
    USE SIGNAL ;
    PORT
      LAYER M4 ;
        RECT  72.792 16.08 72.984 16.104 ;
    END
  END a[322]
  PIN a[323]
    DIRECTION INPUT ;
    USE SIGNAL ;
    PORT
      LAYER M4 ;
        RECT  72.792 16.128 72.984 16.152 ;
    END
  END a[323]
  PIN a[324]
    DIRECTION INPUT ;
    USE SIGNAL ;
    PORT
      LAYER M4 ;
        RECT  72.792 16.176 72.984 16.2 ;
    END
  END a[324]
  PIN a[325]
    DIRECTION INPUT ;
    USE SIGNAL ;
    PORT
      LAYER M4 ;
        RECT  72.792 16.224 72.984 16.248 ;
    END
  END a[325]
  PIN a[326]
    DIRECTION INPUT ;
    USE SIGNAL ;
    PORT
      LAYER M4 ;
        RECT  72.792 16.272 72.984 16.296 ;
    END
  END a[326]
  PIN a[327]
    DIRECTION INPUT ;
    USE SIGNAL ;
    PORT
      LAYER M4 ;
        RECT  72.792 16.32 72.984 16.344 ;
    END
  END a[327]
  PIN a[328]
    DIRECTION INPUT ;
    USE SIGNAL ;
    PORT
      LAYER M4 ;
        RECT  72.792 16.368 72.984 16.392 ;
    END
  END a[328]
  PIN a[329]
    DIRECTION INPUT ;
    USE SIGNAL ;
    PORT
      LAYER M4 ;
        RECT  72.792 16.416 72.984 16.44 ;
    END
  END a[329]
  PIN a[32]
    DIRECTION INPUT ;
    USE SIGNAL ;
    PORT
      LAYER M4 ;
        RECT  72.792 2.16 72.984 2.184 ;
    END
  END a[32]
  PIN a[330]
    DIRECTION INPUT ;
    USE SIGNAL ;
    PORT
      LAYER M4 ;
        RECT  72.792 16.464 72.984 16.488 ;
    END
  END a[330]
  PIN a[331]
    DIRECTION INPUT ;
    USE SIGNAL ;
    PORT
      LAYER M4 ;
        RECT  72.792 16.512 72.984 16.536 ;
    END
  END a[331]
  PIN a[332]
    DIRECTION INPUT ;
    USE SIGNAL ;
    PORT
      LAYER M4 ;
        RECT  72.792 16.56 72.984 16.584 ;
    END
  END a[332]
  PIN a[333]
    DIRECTION INPUT ;
    USE SIGNAL ;
    PORT
      LAYER M4 ;
        RECT  72.792 16.608 72.984 16.632 ;
    END
  END a[333]
  PIN a[334]
    DIRECTION INPUT ;
    USE SIGNAL ;
    PORT
      LAYER M4 ;
        RECT  72.792 16.656 72.984 16.68 ;
    END
  END a[334]
  PIN a[335]
    DIRECTION INPUT ;
    USE SIGNAL ;
    PORT
      LAYER M4 ;
        RECT  72.792 16.704 72.984 16.728 ;
    END
  END a[335]
  PIN a[336]
    DIRECTION INPUT ;
    USE SIGNAL ;
    PORT
      LAYER M4 ;
        RECT  72.792 16.752 72.984 16.776 ;
    END
  END a[336]
  PIN a[337]
    DIRECTION INPUT ;
    USE SIGNAL ;
    PORT
      LAYER M4 ;
        RECT  72.792 16.8 72.984 16.824 ;
    END
  END a[337]
  PIN a[338]
    DIRECTION INPUT ;
    USE SIGNAL ;
    PORT
      LAYER M4 ;
        RECT  72.792 16.848 72.984 16.872 ;
    END
  END a[338]
  PIN a[339]
    DIRECTION INPUT ;
    USE SIGNAL ;
    PORT
      LAYER M4 ;
        RECT  72.792 16.896 72.984 16.92 ;
    END
  END a[339]
  PIN a[33]
    DIRECTION INPUT ;
    USE SIGNAL ;
    PORT
      LAYER M4 ;
        RECT  72.792 2.208 72.984 2.232 ;
    END
  END a[33]
  PIN a[340]
    DIRECTION INPUT ;
    USE SIGNAL ;
    PORT
      LAYER M4 ;
        RECT  72.792 16.944 72.984 16.968 ;
    END
  END a[340]
  PIN a[341]
    DIRECTION INPUT ;
    USE SIGNAL ;
    PORT
      LAYER M4 ;
        RECT  72.792 16.992 72.984 17.016 ;
    END
  END a[341]
  PIN a[342]
    DIRECTION INPUT ;
    USE SIGNAL ;
    PORT
      LAYER M4 ;
        RECT  72.792 17.04 72.984 17.064 ;
    END
  END a[342]
  PIN a[343]
    DIRECTION INPUT ;
    USE SIGNAL ;
    PORT
      LAYER M4 ;
        RECT  72.792 17.088 72.984 17.112 ;
    END
  END a[343]
  PIN a[344]
    DIRECTION INPUT ;
    USE SIGNAL ;
    PORT
      LAYER M4 ;
        RECT  72.792 17.136 72.984 17.16 ;
    END
  END a[344]
  PIN a[345]
    DIRECTION INPUT ;
    USE SIGNAL ;
    PORT
      LAYER M4 ;
        RECT  72.792 17.184 72.984 17.208 ;
    END
  END a[345]
  PIN a[346]
    DIRECTION INPUT ;
    USE SIGNAL ;
    PORT
      LAYER M4 ;
        RECT  72.792 17.232 72.984 17.256 ;
    END
  END a[346]
  PIN a[347]
    DIRECTION INPUT ;
    USE SIGNAL ;
    PORT
      LAYER M4 ;
        RECT  72.792 17.28 72.984 17.304 ;
    END
  END a[347]
  PIN a[348]
    DIRECTION INPUT ;
    USE SIGNAL ;
    PORT
      LAYER M4 ;
        RECT  72.792 17.328 72.984 17.352 ;
    END
  END a[348]
  PIN a[349]
    DIRECTION INPUT ;
    USE SIGNAL ;
    PORT
      LAYER M4 ;
        RECT  72.792 17.376 72.984 17.4 ;
    END
  END a[349]
  PIN a[34]
    DIRECTION INPUT ;
    USE SIGNAL ;
    PORT
      LAYER M4 ;
        RECT  72.792 2.256 72.984 2.28 ;
    END
  END a[34]
  PIN a[350]
    DIRECTION INPUT ;
    USE SIGNAL ;
    PORT
      LAYER M4 ;
        RECT  72.792 17.424 72.984 17.448 ;
    END
  END a[350]
  PIN a[351]
    DIRECTION INPUT ;
    USE SIGNAL ;
    PORT
      LAYER M4 ;
        RECT  72.792 17.472 72.984 17.496 ;
    END
  END a[351]
  PIN a[352]
    DIRECTION INPUT ;
    USE SIGNAL ;
    PORT
      LAYER M4 ;
        RECT  72.792 17.52 72.984 17.544 ;
    END
  END a[352]
  PIN a[353]
    DIRECTION INPUT ;
    USE SIGNAL ;
    PORT
      LAYER M4 ;
        RECT  72.792 17.568 72.984 17.592 ;
    END
  END a[353]
  PIN a[354]
    DIRECTION INPUT ;
    USE SIGNAL ;
    PORT
      LAYER M4 ;
        RECT  72.792 17.616 72.984 17.64 ;
    END
  END a[354]
  PIN a[355]
    DIRECTION INPUT ;
    USE SIGNAL ;
    PORT
      LAYER M4 ;
        RECT  72.792 17.664 72.984 17.688 ;
    END
  END a[355]
  PIN a[356]
    DIRECTION INPUT ;
    USE SIGNAL ;
    PORT
      LAYER M4 ;
        RECT  72.792 17.712 72.984 17.736 ;
    END
  END a[356]
  PIN a[357]
    DIRECTION INPUT ;
    USE SIGNAL ;
    PORT
      LAYER M4 ;
        RECT  72.792 17.76 72.984 17.784 ;
    END
  END a[357]
  PIN a[358]
    DIRECTION INPUT ;
    USE SIGNAL ;
    PORT
      LAYER M4 ;
        RECT  72.792 17.808 72.984 17.832 ;
    END
  END a[358]
  PIN a[359]
    DIRECTION INPUT ;
    USE SIGNAL ;
    PORT
      LAYER M4 ;
        RECT  72.792 17.856 72.984 17.88 ;
    END
  END a[359]
  PIN a[35]
    DIRECTION INPUT ;
    USE SIGNAL ;
    PORT
      LAYER M4 ;
        RECT  72.792 2.304 72.984 2.328 ;
    END
  END a[35]
  PIN a[360]
    DIRECTION INPUT ;
    USE SIGNAL ;
    PORT
      LAYER M4 ;
        RECT  72.792 17.904 72.984 17.928 ;
    END
  END a[360]
  PIN a[361]
    DIRECTION INPUT ;
    USE SIGNAL ;
    PORT
      LAYER M4 ;
        RECT  72.792 17.952 72.984 17.976 ;
    END
  END a[361]
  PIN a[362]
    DIRECTION INPUT ;
    USE SIGNAL ;
    PORT
      LAYER M4 ;
        RECT  72.792 18 72.984 18.024 ;
    END
  END a[362]
  PIN a[363]
    DIRECTION INPUT ;
    USE SIGNAL ;
    PORT
      LAYER M4 ;
        RECT  72.792 18.048 72.984 18.072 ;
    END
  END a[363]
  PIN a[364]
    DIRECTION INPUT ;
    USE SIGNAL ;
    PORT
      LAYER M4 ;
        RECT  72.792 18.096 72.984 18.12 ;
    END
  END a[364]
  PIN a[365]
    DIRECTION INPUT ;
    USE SIGNAL ;
    PORT
      LAYER M4 ;
        RECT  72.792 18.144 72.984 18.168 ;
    END
  END a[365]
  PIN a[366]
    DIRECTION INPUT ;
    USE SIGNAL ;
    PORT
      LAYER M4 ;
        RECT  72.792 18.192 72.984 18.216 ;
    END
  END a[366]
  PIN a[367]
    DIRECTION INPUT ;
    USE SIGNAL ;
    PORT
      LAYER M4 ;
        RECT  72.792 18.24 72.984 18.264 ;
    END
  END a[367]
  PIN a[368]
    DIRECTION INPUT ;
    USE SIGNAL ;
    PORT
      LAYER M4 ;
        RECT  72.792 18.288 72.984 18.312 ;
    END
  END a[368]
  PIN a[369]
    DIRECTION INPUT ;
    USE SIGNAL ;
    PORT
      LAYER M4 ;
        RECT  72.792 18.336 72.984 18.36 ;
    END
  END a[369]
  PIN a[36]
    DIRECTION INPUT ;
    USE SIGNAL ;
    PORT
      LAYER M4 ;
        RECT  72.792 2.352 72.984 2.376 ;
    END
  END a[36]
  PIN a[370]
    DIRECTION INPUT ;
    USE SIGNAL ;
    PORT
      LAYER M4 ;
        RECT  72.792 18.384 72.984 18.408 ;
    END
  END a[370]
  PIN a[371]
    DIRECTION INPUT ;
    USE SIGNAL ;
    PORT
      LAYER M4 ;
        RECT  72.792 18.432 72.984 18.456 ;
    END
  END a[371]
  PIN a[372]
    DIRECTION INPUT ;
    USE SIGNAL ;
    PORT
      LAYER M4 ;
        RECT  72.792 18.48 72.984 18.504 ;
    END
  END a[372]
  PIN a[373]
    DIRECTION INPUT ;
    USE SIGNAL ;
    PORT
      LAYER M4 ;
        RECT  72.792 18.528 72.984 18.552 ;
    END
  END a[373]
  PIN a[374]
    DIRECTION INPUT ;
    USE SIGNAL ;
    PORT
      LAYER M4 ;
        RECT  72.792 18.576 72.984 18.6 ;
    END
  END a[374]
  PIN a[375]
    DIRECTION INPUT ;
    USE SIGNAL ;
    PORT
      LAYER M4 ;
        RECT  72.792 18.624 72.984 18.648 ;
    END
  END a[375]
  PIN a[376]
    DIRECTION INPUT ;
    USE SIGNAL ;
    PORT
      LAYER M4 ;
        RECT  72.792 18.672 72.984 18.696 ;
    END
  END a[376]
  PIN a[377]
    DIRECTION INPUT ;
    USE SIGNAL ;
    PORT
      LAYER M4 ;
        RECT  72.792 18.72 72.984 18.744 ;
    END
  END a[377]
  PIN a[378]
    DIRECTION INPUT ;
    USE SIGNAL ;
    PORT
      LAYER M4 ;
        RECT  72.792 18.768 72.984 18.792 ;
    END
  END a[378]
  PIN a[379]
    DIRECTION INPUT ;
    USE SIGNAL ;
    PORT
      LAYER M4 ;
        RECT  72.792 18.816 72.984 18.84 ;
    END
  END a[379]
  PIN a[37]
    DIRECTION INPUT ;
    USE SIGNAL ;
    PORT
      LAYER M4 ;
        RECT  72.792 2.4 72.984 2.424 ;
    END
  END a[37]
  PIN a[380]
    DIRECTION INPUT ;
    USE SIGNAL ;
    PORT
      LAYER M4 ;
        RECT  72.792 18.864 72.984 18.888 ;
    END
  END a[380]
  PIN a[381]
    DIRECTION INPUT ;
    USE SIGNAL ;
    PORT
      LAYER M4 ;
        RECT  72.792 18.912 72.984 18.936 ;
    END
  END a[381]
  PIN a[382]
    DIRECTION INPUT ;
    USE SIGNAL ;
    PORT
      LAYER M4 ;
        RECT  72.792 18.96 72.984 18.984 ;
    END
  END a[382]
  PIN a[383]
    DIRECTION INPUT ;
    USE SIGNAL ;
    PORT
      LAYER M4 ;
        RECT  72.792 19.008 72.984 19.032 ;
    END
  END a[383]
  PIN a[384]
    DIRECTION INPUT ;
    USE SIGNAL ;
    PORT
      LAYER M4 ;
        RECT  72.792 19.056 72.984 19.08 ;
    END
  END a[384]
  PIN a[385]
    DIRECTION INPUT ;
    USE SIGNAL ;
    PORT
      LAYER M4 ;
        RECT  72.792 19.104 72.984 19.128 ;
    END
  END a[385]
  PIN a[386]
    DIRECTION INPUT ;
    USE SIGNAL ;
    PORT
      LAYER M4 ;
        RECT  72.792 19.152 72.984 19.176 ;
    END
  END a[386]
  PIN a[387]
    DIRECTION INPUT ;
    USE SIGNAL ;
    PORT
      LAYER M4 ;
        RECT  72.792 19.2 72.984 19.224 ;
    END
  END a[387]
  PIN a[388]
    DIRECTION INPUT ;
    USE SIGNAL ;
    PORT
      LAYER M4 ;
        RECT  72.792 19.248 72.984 19.272 ;
    END
  END a[388]
  PIN a[389]
    DIRECTION INPUT ;
    USE SIGNAL ;
    PORT
      LAYER M4 ;
        RECT  72.792 19.296 72.984 19.32 ;
    END
  END a[389]
  PIN a[38]
    DIRECTION INPUT ;
    USE SIGNAL ;
    PORT
      LAYER M4 ;
        RECT  72.792 2.448 72.984 2.472 ;
    END
  END a[38]
  PIN a[390]
    DIRECTION INPUT ;
    USE SIGNAL ;
    PORT
      LAYER M4 ;
        RECT  72.792 19.344 72.984 19.368 ;
    END
  END a[390]
  PIN a[391]
    DIRECTION INPUT ;
    USE SIGNAL ;
    PORT
      LAYER M4 ;
        RECT  72.792 19.392 72.984 19.416 ;
    END
  END a[391]
  PIN a[392]
    DIRECTION INPUT ;
    USE SIGNAL ;
    PORT
      LAYER M4 ;
        RECT  72.792 19.44 72.984 19.464 ;
    END
  END a[392]
  PIN a[393]
    DIRECTION INPUT ;
    USE SIGNAL ;
    PORT
      LAYER M4 ;
        RECT  72.792 19.488 72.984 19.512 ;
    END
  END a[393]
  PIN a[394]
    DIRECTION INPUT ;
    USE SIGNAL ;
    PORT
      LAYER M4 ;
        RECT  72.792 19.536 72.984 19.56 ;
    END
  END a[394]
  PIN a[395]
    DIRECTION INPUT ;
    USE SIGNAL ;
    PORT
      LAYER M4 ;
        RECT  72.792 19.584 72.984 19.608 ;
    END
  END a[395]
  PIN a[396]
    DIRECTION INPUT ;
    USE SIGNAL ;
    PORT
      LAYER M4 ;
        RECT  72.792 19.632 72.984 19.656 ;
    END
  END a[396]
  PIN a[397]
    DIRECTION INPUT ;
    USE SIGNAL ;
    PORT
      LAYER M4 ;
        RECT  72.792 19.68 72.984 19.704 ;
    END
  END a[397]
  PIN a[398]
    DIRECTION INPUT ;
    USE SIGNAL ;
    PORT
      LAYER M4 ;
        RECT  72.792 19.728 72.984 19.752 ;
    END
  END a[398]
  PIN a[399]
    DIRECTION INPUT ;
    USE SIGNAL ;
    PORT
      LAYER M4 ;
        RECT  72.792 19.776 72.984 19.8 ;
    END
  END a[399]
  PIN a[39]
    DIRECTION INPUT ;
    USE SIGNAL ;
    PORT
      LAYER M4 ;
        RECT  72.792 2.496 72.984 2.52 ;
    END
  END a[39]
  PIN a[3]
    DIRECTION INPUT ;
    USE SIGNAL ;
    PORT
      LAYER M4 ;
        RECT  72.792 0.768 72.984 0.792 ;
    END
  END a[3]
  PIN a[400]
    DIRECTION INPUT ;
    USE SIGNAL ;
    PORT
      LAYER M4 ;
        RECT  72.792 19.824 72.984 19.848 ;
    END
  END a[400]
  PIN a[401]
    DIRECTION INPUT ;
    USE SIGNAL ;
    PORT
      LAYER M4 ;
        RECT  72.792 19.872 72.984 19.896 ;
    END
  END a[401]
  PIN a[402]
    DIRECTION INPUT ;
    USE SIGNAL ;
    PORT
      LAYER M4 ;
        RECT  72.792 19.92 72.984 19.944 ;
    END
  END a[402]
  PIN a[403]
    DIRECTION INPUT ;
    USE SIGNAL ;
    PORT
      LAYER M4 ;
        RECT  72.792 19.968 72.984 19.992 ;
    END
  END a[403]
  PIN a[404]
    DIRECTION INPUT ;
    USE SIGNAL ;
    PORT
      LAYER M4 ;
        RECT  72.792 20.016 72.984 20.04 ;
    END
  END a[404]
  PIN a[405]
    DIRECTION INPUT ;
    USE SIGNAL ;
    PORT
      LAYER M4 ;
        RECT  72.792 20.064 72.984 20.088 ;
    END
  END a[405]
  PIN a[406]
    DIRECTION INPUT ;
    USE SIGNAL ;
    PORT
      LAYER M4 ;
        RECT  72.792 20.112 72.984 20.136 ;
    END
  END a[406]
  PIN a[407]
    DIRECTION INPUT ;
    USE SIGNAL ;
    PORT
      LAYER M4 ;
        RECT  72.792 20.16 72.984 20.184 ;
    END
  END a[407]
  PIN a[408]
    DIRECTION INPUT ;
    USE SIGNAL ;
    PORT
      LAYER M4 ;
        RECT  72.792 20.208 72.984 20.232 ;
    END
  END a[408]
  PIN a[409]
    DIRECTION INPUT ;
    USE SIGNAL ;
    PORT
      LAYER M4 ;
        RECT  72.792 20.256 72.984 20.28 ;
    END
  END a[409]
  PIN a[40]
    DIRECTION INPUT ;
    USE SIGNAL ;
    PORT
      LAYER M4 ;
        RECT  72.792 2.544 72.984 2.568 ;
    END
  END a[40]
  PIN a[410]
    DIRECTION INPUT ;
    USE SIGNAL ;
    PORT
      LAYER M4 ;
        RECT  72.792 20.304 72.984 20.328 ;
    END
  END a[410]
  PIN a[411]
    DIRECTION INPUT ;
    USE SIGNAL ;
    PORT
      LAYER M4 ;
        RECT  72.792 20.352 72.984 20.376 ;
    END
  END a[411]
  PIN a[412]
    DIRECTION INPUT ;
    USE SIGNAL ;
    PORT
      LAYER M4 ;
        RECT  72.792 20.4 72.984 20.424 ;
    END
  END a[412]
  PIN a[413]
    DIRECTION INPUT ;
    USE SIGNAL ;
    PORT
      LAYER M4 ;
        RECT  72.792 20.448 72.984 20.472 ;
    END
  END a[413]
  PIN a[414]
    DIRECTION INPUT ;
    USE SIGNAL ;
    PORT
      LAYER M4 ;
        RECT  72.792 20.496 72.984 20.52 ;
    END
  END a[414]
  PIN a[415]
    DIRECTION INPUT ;
    USE SIGNAL ;
    PORT
      LAYER M4 ;
        RECT  72.792 20.544 72.984 20.568 ;
    END
  END a[415]
  PIN a[416]
    DIRECTION INPUT ;
    USE SIGNAL ;
    PORT
      LAYER M4 ;
        RECT  72.792 20.592 72.984 20.616 ;
    END
  END a[416]
  PIN a[417]
    DIRECTION INPUT ;
    USE SIGNAL ;
    PORT
      LAYER M4 ;
        RECT  72.792 20.64 72.984 20.664 ;
    END
  END a[417]
  PIN a[418]
    DIRECTION INPUT ;
    USE SIGNAL ;
    PORT
      LAYER M4 ;
        RECT  72.792 20.688 72.984 20.712 ;
    END
  END a[418]
  PIN a[419]
    DIRECTION INPUT ;
    USE SIGNAL ;
    PORT
      LAYER M4 ;
        RECT  72.792 20.736 72.984 20.76 ;
    END
  END a[419]
  PIN a[41]
    DIRECTION INPUT ;
    USE SIGNAL ;
    PORT
      LAYER M4 ;
        RECT  72.792 2.592 72.984 2.616 ;
    END
  END a[41]
  PIN a[420]
    DIRECTION INPUT ;
    USE SIGNAL ;
    PORT
      LAYER M4 ;
        RECT  72.792 20.784 72.984 20.808 ;
    END
  END a[420]
  PIN a[421]
    DIRECTION INPUT ;
    USE SIGNAL ;
    PORT
      LAYER M4 ;
        RECT  72.792 20.832 72.984 20.856 ;
    END
  END a[421]
  PIN a[422]
    DIRECTION INPUT ;
    USE SIGNAL ;
    PORT
      LAYER M4 ;
        RECT  72.792 20.88 72.984 20.904 ;
    END
  END a[422]
  PIN a[423]
    DIRECTION INPUT ;
    USE SIGNAL ;
    PORT
      LAYER M4 ;
        RECT  72.792 20.928 72.984 20.952 ;
    END
  END a[423]
  PIN a[424]
    DIRECTION INPUT ;
    USE SIGNAL ;
    PORT
      LAYER M4 ;
        RECT  72.792 20.976 72.984 21 ;
    END
  END a[424]
  PIN a[425]
    DIRECTION INPUT ;
    USE SIGNAL ;
    PORT
      LAYER M4 ;
        RECT  72.792 21.024 72.984 21.048 ;
    END
  END a[425]
  PIN a[426]
    DIRECTION INPUT ;
    USE SIGNAL ;
    PORT
      LAYER M4 ;
        RECT  72.792 21.072 72.984 21.096 ;
    END
  END a[426]
  PIN a[427]
    DIRECTION INPUT ;
    USE SIGNAL ;
    PORT
      LAYER M4 ;
        RECT  72.792 21.12 72.984 21.144 ;
    END
  END a[427]
  PIN a[428]
    DIRECTION INPUT ;
    USE SIGNAL ;
    PORT
      LAYER M4 ;
        RECT  72.792 21.168 72.984 21.192 ;
    END
  END a[428]
  PIN a[429]
    DIRECTION INPUT ;
    USE SIGNAL ;
    PORT
      LAYER M4 ;
        RECT  72.792 21.216 72.984 21.24 ;
    END
  END a[429]
  PIN a[42]
    DIRECTION INPUT ;
    USE SIGNAL ;
    PORT
      LAYER M4 ;
        RECT  72.792 2.64 72.984 2.664 ;
    END
  END a[42]
  PIN a[430]
    DIRECTION INPUT ;
    USE SIGNAL ;
    PORT
      LAYER M4 ;
        RECT  72.792 21.264 72.984 21.288 ;
    END
  END a[430]
  PIN a[431]
    DIRECTION INPUT ;
    USE SIGNAL ;
    PORT
      LAYER M4 ;
        RECT  72.792 21.312 72.984 21.336 ;
    END
  END a[431]
  PIN a[432]
    DIRECTION INPUT ;
    USE SIGNAL ;
    PORT
      LAYER M4 ;
        RECT  72.792 21.36 72.984 21.384 ;
    END
  END a[432]
  PIN a[433]
    DIRECTION INPUT ;
    USE SIGNAL ;
    PORT
      LAYER M4 ;
        RECT  72.792 21.408 72.984 21.432 ;
    END
  END a[433]
  PIN a[434]
    DIRECTION INPUT ;
    USE SIGNAL ;
    PORT
      LAYER M4 ;
        RECT  72.792 21.456 72.984 21.48 ;
    END
  END a[434]
  PIN a[435]
    DIRECTION INPUT ;
    USE SIGNAL ;
    PORT
      LAYER M4 ;
        RECT  72.792 21.504 72.984 21.528 ;
    END
  END a[435]
  PIN a[436]
    DIRECTION INPUT ;
    USE SIGNAL ;
    PORT
      LAYER M4 ;
        RECT  72.792 21.552 72.984 21.576 ;
    END
  END a[436]
  PIN a[437]
    DIRECTION INPUT ;
    USE SIGNAL ;
    PORT
      LAYER M4 ;
        RECT  72.792 21.6 72.984 21.624 ;
    END
  END a[437]
  PIN a[438]
    DIRECTION INPUT ;
    USE SIGNAL ;
    PORT
      LAYER M4 ;
        RECT  72.792 21.648 72.984 21.672 ;
    END
  END a[438]
  PIN a[439]
    DIRECTION INPUT ;
    USE SIGNAL ;
    PORT
      LAYER M4 ;
        RECT  72.792 21.696 72.984 21.72 ;
    END
  END a[439]
  PIN a[43]
    DIRECTION INPUT ;
    USE SIGNAL ;
    PORT
      LAYER M4 ;
        RECT  72.792 2.688 72.984 2.712 ;
    END
  END a[43]
  PIN a[440]
    DIRECTION INPUT ;
    USE SIGNAL ;
    PORT
      LAYER M4 ;
        RECT  72.792 21.744 72.984 21.768 ;
    END
  END a[440]
  PIN a[441]
    DIRECTION INPUT ;
    USE SIGNAL ;
    PORT
      LAYER M4 ;
        RECT  72.792 21.792 72.984 21.816 ;
    END
  END a[441]
  PIN a[442]
    DIRECTION INPUT ;
    USE SIGNAL ;
    PORT
      LAYER M4 ;
        RECT  72.792 21.84 72.984 21.864 ;
    END
  END a[442]
  PIN a[443]
    DIRECTION INPUT ;
    USE SIGNAL ;
    PORT
      LAYER M4 ;
        RECT  72.792 21.888 72.984 21.912 ;
    END
  END a[443]
  PIN a[444]
    DIRECTION INPUT ;
    USE SIGNAL ;
    PORT
      LAYER M4 ;
        RECT  72.792 21.936 72.984 21.96 ;
    END
  END a[444]
  PIN a[445]
    DIRECTION INPUT ;
    USE SIGNAL ;
    PORT
      LAYER M4 ;
        RECT  72.792 21.984 72.984 22.008 ;
    END
  END a[445]
  PIN a[446]
    DIRECTION INPUT ;
    USE SIGNAL ;
    PORT
      LAYER M4 ;
        RECT  72.792 22.032 72.984 22.056 ;
    END
  END a[446]
  PIN a[447]
    DIRECTION INPUT ;
    USE SIGNAL ;
    PORT
      LAYER M4 ;
        RECT  72.792 22.08 72.984 22.104 ;
    END
  END a[447]
  PIN a[448]
    DIRECTION INPUT ;
    USE SIGNAL ;
    PORT
      LAYER M4 ;
        RECT  72.792 22.128 72.984 22.152 ;
    END
  END a[448]
  PIN a[449]
    DIRECTION INPUT ;
    USE SIGNAL ;
    PORT
      LAYER M4 ;
        RECT  72.792 22.176 72.984 22.2 ;
    END
  END a[449]
  PIN a[44]
    DIRECTION INPUT ;
    USE SIGNAL ;
    PORT
      LAYER M4 ;
        RECT  72.792 2.736 72.984 2.76 ;
    END
  END a[44]
  PIN a[450]
    DIRECTION INPUT ;
    USE SIGNAL ;
    PORT
      LAYER M4 ;
        RECT  72.792 22.224 72.984 22.248 ;
    END
  END a[450]
  PIN a[451]
    DIRECTION INPUT ;
    USE SIGNAL ;
    PORT
      LAYER M4 ;
        RECT  72.792 22.272 72.984 22.296 ;
    END
  END a[451]
  PIN a[452]
    DIRECTION INPUT ;
    USE SIGNAL ;
    PORT
      LAYER M4 ;
        RECT  72.792 22.32 72.984 22.344 ;
    END
  END a[452]
  PIN a[453]
    DIRECTION INPUT ;
    USE SIGNAL ;
    PORT
      LAYER M4 ;
        RECT  72.792 22.368 72.984 22.392 ;
    END
  END a[453]
  PIN a[454]
    DIRECTION INPUT ;
    USE SIGNAL ;
    PORT
      LAYER M4 ;
        RECT  72.792 22.416 72.984 22.44 ;
    END
  END a[454]
  PIN a[455]
    DIRECTION INPUT ;
    USE SIGNAL ;
    PORT
      LAYER M4 ;
        RECT  72.792 22.464 72.984 22.488 ;
    END
  END a[455]
  PIN a[456]
    DIRECTION INPUT ;
    USE SIGNAL ;
    PORT
      LAYER M4 ;
        RECT  72.792 22.512 72.984 22.536 ;
    END
  END a[456]
  PIN a[457]
    DIRECTION INPUT ;
    USE SIGNAL ;
    PORT
      LAYER M4 ;
        RECT  72.792 22.56 72.984 22.584 ;
    END
  END a[457]
  PIN a[458]
    DIRECTION INPUT ;
    USE SIGNAL ;
    PORT
      LAYER M4 ;
        RECT  72.792 22.608 72.984 22.632 ;
    END
  END a[458]
  PIN a[459]
    DIRECTION INPUT ;
    USE SIGNAL ;
    PORT
      LAYER M4 ;
        RECT  72.792 22.656 72.984 22.68 ;
    END
  END a[459]
  PIN a[45]
    DIRECTION INPUT ;
    USE SIGNAL ;
    PORT
      LAYER M4 ;
        RECT  72.792 2.784 72.984 2.808 ;
    END
  END a[45]
  PIN a[460]
    DIRECTION INPUT ;
    USE SIGNAL ;
    PORT
      LAYER M4 ;
        RECT  72.792 22.704 72.984 22.728 ;
    END
  END a[460]
  PIN a[461]
    DIRECTION INPUT ;
    USE SIGNAL ;
    PORT
      LAYER M4 ;
        RECT  72.792 22.752 72.984 22.776 ;
    END
  END a[461]
  PIN a[462]
    DIRECTION INPUT ;
    USE SIGNAL ;
    PORT
      LAYER M4 ;
        RECT  72.792 22.8 72.984 22.824 ;
    END
  END a[462]
  PIN a[463]
    DIRECTION INPUT ;
    USE SIGNAL ;
    PORT
      LAYER M4 ;
        RECT  72.792 22.848 72.984 22.872 ;
    END
  END a[463]
  PIN a[464]
    DIRECTION INPUT ;
    USE SIGNAL ;
    PORT
      LAYER M4 ;
        RECT  72.792 22.896 72.984 22.92 ;
    END
  END a[464]
  PIN a[465]
    DIRECTION INPUT ;
    USE SIGNAL ;
    PORT
      LAYER M4 ;
        RECT  72.792 22.944 72.984 22.968 ;
    END
  END a[465]
  PIN a[466]
    DIRECTION INPUT ;
    USE SIGNAL ;
    PORT
      LAYER M4 ;
        RECT  72.792 22.992 72.984 23.016 ;
    END
  END a[466]
  PIN a[467]
    DIRECTION INPUT ;
    USE SIGNAL ;
    PORT
      LAYER M4 ;
        RECT  72.792 23.04 72.984 23.064 ;
    END
  END a[467]
  PIN a[468]
    DIRECTION INPUT ;
    USE SIGNAL ;
    PORT
      LAYER M4 ;
        RECT  72.792 23.088 72.984 23.112 ;
    END
  END a[468]
  PIN a[469]
    DIRECTION INPUT ;
    USE SIGNAL ;
    PORT
      LAYER M4 ;
        RECT  72.792 23.136 72.984 23.16 ;
    END
  END a[469]
  PIN a[46]
    DIRECTION INPUT ;
    USE SIGNAL ;
    PORT
      LAYER M4 ;
        RECT  72.792 2.832 72.984 2.856 ;
    END
  END a[46]
  PIN a[470]
    DIRECTION INPUT ;
    USE SIGNAL ;
    PORT
      LAYER M4 ;
        RECT  72.792 23.184 72.984 23.208 ;
    END
  END a[470]
  PIN a[471]
    DIRECTION INPUT ;
    USE SIGNAL ;
    PORT
      LAYER M4 ;
        RECT  72.792 23.232 72.984 23.256 ;
    END
  END a[471]
  PIN a[472]
    DIRECTION INPUT ;
    USE SIGNAL ;
    PORT
      LAYER M4 ;
        RECT  72.792 23.28 72.984 23.304 ;
    END
  END a[472]
  PIN a[473]
    DIRECTION INPUT ;
    USE SIGNAL ;
    PORT
      LAYER M4 ;
        RECT  72.792 23.328 72.984 23.352 ;
    END
  END a[473]
  PIN a[474]
    DIRECTION INPUT ;
    USE SIGNAL ;
    PORT
      LAYER M4 ;
        RECT  72.792 23.376 72.984 23.4 ;
    END
  END a[474]
  PIN a[475]
    DIRECTION INPUT ;
    USE SIGNAL ;
    PORT
      LAYER M4 ;
        RECT  72.792 23.424 72.984 23.448 ;
    END
  END a[475]
  PIN a[476]
    DIRECTION INPUT ;
    USE SIGNAL ;
    PORT
      LAYER M4 ;
        RECT  72.792 23.472 72.984 23.496 ;
    END
  END a[476]
  PIN a[477]
    DIRECTION INPUT ;
    USE SIGNAL ;
    PORT
      LAYER M4 ;
        RECT  72.792 23.52 72.984 23.544 ;
    END
  END a[477]
  PIN a[478]
    DIRECTION INPUT ;
    USE SIGNAL ;
    PORT
      LAYER M4 ;
        RECT  72.792 23.568 72.984 23.592 ;
    END
  END a[478]
  PIN a[479]
    DIRECTION INPUT ;
    USE SIGNAL ;
    PORT
      LAYER M4 ;
        RECT  72.792 23.616 72.984 23.64 ;
    END
  END a[479]
  PIN a[47]
    DIRECTION INPUT ;
    USE SIGNAL ;
    PORT
      LAYER M4 ;
        RECT  72.792 2.88 72.984 2.904 ;
    END
  END a[47]
  PIN a[480]
    DIRECTION INPUT ;
    USE SIGNAL ;
    PORT
      LAYER M4 ;
        RECT  72.792 23.664 72.984 23.688 ;
    END
  END a[480]
  PIN a[481]
    DIRECTION INPUT ;
    USE SIGNAL ;
    PORT
      LAYER M4 ;
        RECT  72.792 23.712 72.984 23.736 ;
    END
  END a[481]
  PIN a[482]
    DIRECTION INPUT ;
    USE SIGNAL ;
    PORT
      LAYER M4 ;
        RECT  72.792 23.76 72.984 23.784 ;
    END
  END a[482]
  PIN a[483]
    DIRECTION INPUT ;
    USE SIGNAL ;
    PORT
      LAYER M4 ;
        RECT  72.792 23.808 72.984 23.832 ;
    END
  END a[483]
  PIN a[484]
    DIRECTION INPUT ;
    USE SIGNAL ;
    PORT
      LAYER M4 ;
        RECT  72.792 23.856 72.984 23.88 ;
    END
  END a[484]
  PIN a[485]
    DIRECTION INPUT ;
    USE SIGNAL ;
    PORT
      LAYER M4 ;
        RECT  72.792 23.904 72.984 23.928 ;
    END
  END a[485]
  PIN a[486]
    DIRECTION INPUT ;
    USE SIGNAL ;
    PORT
      LAYER M4 ;
        RECT  72.792 23.952 72.984 23.976 ;
    END
  END a[486]
  PIN a[487]
    DIRECTION INPUT ;
    USE SIGNAL ;
    PORT
      LAYER M4 ;
        RECT  72.792 24 72.984 24.024 ;
    END
  END a[487]
  PIN a[488]
    DIRECTION INPUT ;
    USE SIGNAL ;
    PORT
      LAYER M4 ;
        RECT  72.792 24.048 72.984 24.072 ;
    END
  END a[488]
  PIN a[489]
    DIRECTION INPUT ;
    USE SIGNAL ;
    PORT
      LAYER M4 ;
        RECT  72.792 24.096 72.984 24.12 ;
    END
  END a[489]
  PIN a[48]
    DIRECTION INPUT ;
    USE SIGNAL ;
    PORT
      LAYER M4 ;
        RECT  72.792 2.928 72.984 2.952 ;
    END
  END a[48]
  PIN a[490]
    DIRECTION INPUT ;
    USE SIGNAL ;
    PORT
      LAYER M4 ;
        RECT  72.792 24.144 72.984 24.168 ;
    END
  END a[490]
  PIN a[491]
    DIRECTION INPUT ;
    USE SIGNAL ;
    PORT
      LAYER M4 ;
        RECT  72.792 24.192 72.984 24.216 ;
    END
  END a[491]
  PIN a[492]
    DIRECTION INPUT ;
    USE SIGNAL ;
    PORT
      LAYER M4 ;
        RECT  72.792 24.24 72.984 24.264 ;
    END
  END a[492]
  PIN a[493]
    DIRECTION INPUT ;
    USE SIGNAL ;
    PORT
      LAYER M4 ;
        RECT  72.792 24.288 72.984 24.312 ;
    END
  END a[493]
  PIN a[494]
    DIRECTION INPUT ;
    USE SIGNAL ;
    PORT
      LAYER M4 ;
        RECT  72.792 24.336 72.984 24.36 ;
    END
  END a[494]
  PIN a[495]
    DIRECTION INPUT ;
    USE SIGNAL ;
    PORT
      LAYER M4 ;
        RECT  72.792 24.384 72.984 24.408 ;
    END
  END a[495]
  PIN a[496]
    DIRECTION INPUT ;
    USE SIGNAL ;
    PORT
      LAYER M4 ;
        RECT  72.792 24.432 72.984 24.456 ;
    END
  END a[496]
  PIN a[497]
    DIRECTION INPUT ;
    USE SIGNAL ;
    PORT
      LAYER M4 ;
        RECT  72.792 24.48 72.984 24.504 ;
    END
  END a[497]
  PIN a[498]
    DIRECTION INPUT ;
    USE SIGNAL ;
    PORT
      LAYER M4 ;
        RECT  72.792 24.528 72.984 24.552 ;
    END
  END a[498]
  PIN a[499]
    DIRECTION INPUT ;
    USE SIGNAL ;
    PORT
      LAYER M4 ;
        RECT  72.792 24.576 72.984 24.6 ;
    END
  END a[499]
  PIN a[49]
    DIRECTION INPUT ;
    USE SIGNAL ;
    PORT
      LAYER M4 ;
        RECT  72.792 2.976 72.984 3 ;
    END
  END a[49]
  PIN a[4]
    DIRECTION INPUT ;
    USE SIGNAL ;
    PORT
      LAYER M4 ;
        RECT  72.792 0.816 72.984 0.84 ;
    END
  END a[4]
  PIN a[500]
    DIRECTION INPUT ;
    USE SIGNAL ;
    PORT
      LAYER M4 ;
        RECT  72.792 24.624 72.984 24.648 ;
    END
  END a[500]
  PIN a[501]
    DIRECTION INPUT ;
    USE SIGNAL ;
    PORT
      LAYER M4 ;
        RECT  72.792 24.672 72.984 24.696 ;
    END
  END a[501]
  PIN a[502]
    DIRECTION INPUT ;
    USE SIGNAL ;
    PORT
      LAYER M4 ;
        RECT  72.792 24.72 72.984 24.744 ;
    END
  END a[502]
  PIN a[503]
    DIRECTION INPUT ;
    USE SIGNAL ;
    PORT
      LAYER M4 ;
        RECT  72.792 24.768 72.984 24.792 ;
    END
  END a[503]
  PIN a[504]
    DIRECTION INPUT ;
    USE SIGNAL ;
    PORT
      LAYER M4 ;
        RECT  72.792 24.816 72.984 24.84 ;
    END
  END a[504]
  PIN a[505]
    DIRECTION INPUT ;
    USE SIGNAL ;
    PORT
      LAYER M4 ;
        RECT  72.792 24.864 72.984 24.888 ;
    END
  END a[505]
  PIN a[506]
    DIRECTION INPUT ;
    USE SIGNAL ;
    PORT
      LAYER M4 ;
        RECT  72.792 24.912 72.984 24.936 ;
    END
  END a[506]
  PIN a[507]
    DIRECTION INPUT ;
    USE SIGNAL ;
    PORT
      LAYER M4 ;
        RECT  72.792 24.96 72.984 24.984 ;
    END
  END a[507]
  PIN a[508]
    DIRECTION INPUT ;
    USE SIGNAL ;
    PORT
      LAYER M4 ;
        RECT  72.792 25.008 72.984 25.032 ;
    END
  END a[508]
  PIN a[509]
    DIRECTION INPUT ;
    USE SIGNAL ;
    PORT
      LAYER M4 ;
        RECT  72.792 25.056 72.984 25.08 ;
    END
  END a[509]
  PIN a[50]
    DIRECTION INPUT ;
    USE SIGNAL ;
    PORT
      LAYER M4 ;
        RECT  72.792 3.024 72.984 3.048 ;
    END
  END a[50]
  PIN a[510]
    DIRECTION INPUT ;
    USE SIGNAL ;
    PORT
      LAYER M4 ;
        RECT  72.792 25.104 72.984 25.128 ;
    END
  END a[510]
  PIN a[511]
    DIRECTION INPUT ;
    USE SIGNAL ;
    PORT
      LAYER M4 ;
        RECT  72.792 25.152 72.984 25.176 ;
    END
  END a[511]
  PIN a[51]
    DIRECTION INPUT ;
    USE SIGNAL ;
    PORT
      LAYER M4 ;
        RECT  72.792 3.072 72.984 3.096 ;
    END
  END a[51]
  PIN a[52]
    DIRECTION INPUT ;
    USE SIGNAL ;
    PORT
      LAYER M4 ;
        RECT  72.792 3.12 72.984 3.144 ;
    END
  END a[52]
  PIN a[53]
    DIRECTION INPUT ;
    USE SIGNAL ;
    PORT
      LAYER M4 ;
        RECT  72.792 3.168 72.984 3.192 ;
    END
  END a[53]
  PIN a[54]
    DIRECTION INPUT ;
    USE SIGNAL ;
    PORT
      LAYER M4 ;
        RECT  72.792 3.216 72.984 3.24 ;
    END
  END a[54]
  PIN a[55]
    DIRECTION INPUT ;
    USE SIGNAL ;
    PORT
      LAYER M4 ;
        RECT  72.792 3.264 72.984 3.288 ;
    END
  END a[55]
  PIN a[56]
    DIRECTION INPUT ;
    USE SIGNAL ;
    PORT
      LAYER M4 ;
        RECT  72.792 3.312 72.984 3.336 ;
    END
  END a[56]
  PIN a[57]
    DIRECTION INPUT ;
    USE SIGNAL ;
    PORT
      LAYER M4 ;
        RECT  72.792 3.36 72.984 3.384 ;
    END
  END a[57]
  PIN a[58]
    DIRECTION INPUT ;
    USE SIGNAL ;
    PORT
      LAYER M4 ;
        RECT  72.792 3.408 72.984 3.432 ;
    END
  END a[58]
  PIN a[59]
    DIRECTION INPUT ;
    USE SIGNAL ;
    PORT
      LAYER M4 ;
        RECT  72.792 3.456 72.984 3.48 ;
    END
  END a[59]
  PIN a[5]
    DIRECTION INPUT ;
    USE SIGNAL ;
    PORT
      LAYER M4 ;
        RECT  72.792 0.864 72.984 0.888 ;
    END
  END a[5]
  PIN a[60]
    DIRECTION INPUT ;
    USE SIGNAL ;
    PORT
      LAYER M4 ;
        RECT  72.792 3.504 72.984 3.528 ;
    END
  END a[60]
  PIN a[61]
    DIRECTION INPUT ;
    USE SIGNAL ;
    PORT
      LAYER M4 ;
        RECT  72.792 3.552 72.984 3.576 ;
    END
  END a[61]
  PIN a[62]
    DIRECTION INPUT ;
    USE SIGNAL ;
    PORT
      LAYER M4 ;
        RECT  72.792 3.6 72.984 3.624 ;
    END
  END a[62]
  PIN a[63]
    DIRECTION INPUT ;
    USE SIGNAL ;
    PORT
      LAYER M4 ;
        RECT  72.792 3.648 72.984 3.672 ;
    END
  END a[63]
  PIN a[64]
    DIRECTION INPUT ;
    USE SIGNAL ;
    PORT
      LAYER M4 ;
        RECT  72.792 3.696 72.984 3.72 ;
    END
  END a[64]
  PIN a[65]
    DIRECTION INPUT ;
    USE SIGNAL ;
    PORT
      LAYER M4 ;
        RECT  72.792 3.744 72.984 3.768 ;
    END
  END a[65]
  PIN a[66]
    DIRECTION INPUT ;
    USE SIGNAL ;
    PORT
      LAYER M4 ;
        RECT  72.792 3.792 72.984 3.816 ;
    END
  END a[66]
  PIN a[67]
    DIRECTION INPUT ;
    USE SIGNAL ;
    PORT
      LAYER M4 ;
        RECT  72.792 3.84 72.984 3.864 ;
    END
  END a[67]
  PIN a[68]
    DIRECTION INPUT ;
    USE SIGNAL ;
    PORT
      LAYER M4 ;
        RECT  72.792 3.888 72.984 3.912 ;
    END
  END a[68]
  PIN a[69]
    DIRECTION INPUT ;
    USE SIGNAL ;
    PORT
      LAYER M4 ;
        RECT  72.792 3.936 72.984 3.96 ;
    END
  END a[69]
  PIN a[6]
    DIRECTION INPUT ;
    USE SIGNAL ;
    PORT
      LAYER M4 ;
        RECT  72.792 0.912 72.984 0.936 ;
    END
  END a[6]
  PIN a[70]
    DIRECTION INPUT ;
    USE SIGNAL ;
    PORT
      LAYER M4 ;
        RECT  72.792 3.984 72.984 4.008 ;
    END
  END a[70]
  PIN a[71]
    DIRECTION INPUT ;
    USE SIGNAL ;
    PORT
      LAYER M4 ;
        RECT  72.792 4.032 72.984 4.056 ;
    END
  END a[71]
  PIN a[72]
    DIRECTION INPUT ;
    USE SIGNAL ;
    PORT
      LAYER M4 ;
        RECT  72.792 4.08 72.984 4.104 ;
    END
  END a[72]
  PIN a[73]
    DIRECTION INPUT ;
    USE SIGNAL ;
    PORT
      LAYER M4 ;
        RECT  72.792 4.128 72.984 4.152 ;
    END
  END a[73]
  PIN a[74]
    DIRECTION INPUT ;
    USE SIGNAL ;
    PORT
      LAYER M4 ;
        RECT  72.792 4.176 72.984 4.2 ;
    END
  END a[74]
  PIN a[75]
    DIRECTION INPUT ;
    USE SIGNAL ;
    PORT
      LAYER M4 ;
        RECT  72.792 4.224 72.984 4.248 ;
    END
  END a[75]
  PIN a[76]
    DIRECTION INPUT ;
    USE SIGNAL ;
    PORT
      LAYER M4 ;
        RECT  72.792 4.272 72.984 4.296 ;
    END
  END a[76]
  PIN a[77]
    DIRECTION INPUT ;
    USE SIGNAL ;
    PORT
      LAYER M4 ;
        RECT  72.792 4.32 72.984 4.344 ;
    END
  END a[77]
  PIN a[78]
    DIRECTION INPUT ;
    USE SIGNAL ;
    PORT
      LAYER M4 ;
        RECT  72.792 4.368 72.984 4.392 ;
    END
  END a[78]
  PIN a[79]
    DIRECTION INPUT ;
    USE SIGNAL ;
    PORT
      LAYER M4 ;
        RECT  72.792 4.416 72.984 4.44 ;
    END
  END a[79]
  PIN a[7]
    DIRECTION INPUT ;
    USE SIGNAL ;
    PORT
      LAYER M4 ;
        RECT  72.792 0.96 72.984 0.984 ;
    END
  END a[7]
  PIN a[80]
    DIRECTION INPUT ;
    USE SIGNAL ;
    PORT
      LAYER M4 ;
        RECT  72.792 4.464 72.984 4.488 ;
    END
  END a[80]
  PIN a[81]
    DIRECTION INPUT ;
    USE SIGNAL ;
    PORT
      LAYER M4 ;
        RECT  72.792 4.512 72.984 4.536 ;
    END
  END a[81]
  PIN a[82]
    DIRECTION INPUT ;
    USE SIGNAL ;
    PORT
      LAYER M4 ;
        RECT  72.792 4.56 72.984 4.584 ;
    END
  END a[82]
  PIN a[83]
    DIRECTION INPUT ;
    USE SIGNAL ;
    PORT
      LAYER M4 ;
        RECT  72.792 4.608 72.984 4.632 ;
    END
  END a[83]
  PIN a[84]
    DIRECTION INPUT ;
    USE SIGNAL ;
    PORT
      LAYER M4 ;
        RECT  72.792 4.656 72.984 4.68 ;
    END
  END a[84]
  PIN a[85]
    DIRECTION INPUT ;
    USE SIGNAL ;
    PORT
      LAYER M4 ;
        RECT  72.792 4.704 72.984 4.728 ;
    END
  END a[85]
  PIN a[86]
    DIRECTION INPUT ;
    USE SIGNAL ;
    PORT
      LAYER M4 ;
        RECT  72.792 4.752 72.984 4.776 ;
    END
  END a[86]
  PIN a[87]
    DIRECTION INPUT ;
    USE SIGNAL ;
    PORT
      LAYER M4 ;
        RECT  72.792 4.8 72.984 4.824 ;
    END
  END a[87]
  PIN a[88]
    DIRECTION INPUT ;
    USE SIGNAL ;
    PORT
      LAYER M4 ;
        RECT  72.792 4.848 72.984 4.872 ;
    END
  END a[88]
  PIN a[89]
    DIRECTION INPUT ;
    USE SIGNAL ;
    PORT
      LAYER M4 ;
        RECT  72.792 4.896 72.984 4.92 ;
    END
  END a[89]
  PIN a[8]
    DIRECTION INPUT ;
    USE SIGNAL ;
    PORT
      LAYER M4 ;
        RECT  72.792 1.008 72.984 1.032 ;
    END
  END a[8]
  PIN a[90]
    DIRECTION INPUT ;
    USE SIGNAL ;
    PORT
      LAYER M4 ;
        RECT  72.792 4.944 72.984 4.968 ;
    END
  END a[90]
  PIN a[91]
    DIRECTION INPUT ;
    USE SIGNAL ;
    PORT
      LAYER M4 ;
        RECT  72.792 4.992 72.984 5.016 ;
    END
  END a[91]
  PIN a[92]
    DIRECTION INPUT ;
    USE SIGNAL ;
    PORT
      LAYER M4 ;
        RECT  72.792 5.04 72.984 5.064 ;
    END
  END a[92]
  PIN a[93]
    DIRECTION INPUT ;
    USE SIGNAL ;
    PORT
      LAYER M4 ;
        RECT  72.792 5.088 72.984 5.112 ;
    END
  END a[93]
  PIN a[94]
    DIRECTION INPUT ;
    USE SIGNAL ;
    PORT
      LAYER M4 ;
        RECT  72.792 5.136 72.984 5.16 ;
    END
  END a[94]
  PIN a[95]
    DIRECTION INPUT ;
    USE SIGNAL ;
    PORT
      LAYER M4 ;
        RECT  72.792 5.184 72.984 5.208 ;
    END
  END a[95]
  PIN a[96]
    DIRECTION INPUT ;
    USE SIGNAL ;
    PORT
      LAYER M4 ;
        RECT  72.792 5.232 72.984 5.256 ;
    END
  END a[96]
  PIN a[97]
    DIRECTION INPUT ;
    USE SIGNAL ;
    PORT
      LAYER M4 ;
        RECT  72.792 5.28 72.984 5.304 ;
    END
  END a[97]
  PIN a[98]
    DIRECTION INPUT ;
    USE SIGNAL ;
    PORT
      LAYER M4 ;
        RECT  72.792 5.328 72.984 5.352 ;
    END
  END a[98]
  PIN a[99]
    DIRECTION INPUT ;
    USE SIGNAL ;
    PORT
      LAYER M4 ;
        RECT  72.792 5.376 72.984 5.4 ;
    END
  END a[99]
  PIN a[9]
    DIRECTION INPUT ;
    USE SIGNAL ;
    PORT
      LAYER M4 ;
        RECT  72.792 1.056 72.984 1.08 ;
    END
  END a[9]
  PIN b[0]
    DIRECTION OUTPUT ;
    USE SIGNAL ;
    PORT
      LAYER M4 ;
        RECT  0 0.624 0.192 0.648 ;
    END
  END b[0]
  PIN b[100]
    DIRECTION OUTPUT ;
    USE SIGNAL ;
    PORT
      LAYER M4 ;
        RECT  0 5.424 0.192 5.448 ;
    END
  END b[100]
  PIN b[101]
    DIRECTION OUTPUT ;
    USE SIGNAL ;
    PORT
      LAYER M4 ;
        RECT  0 5.472 0.192 5.496 ;
    END
  END b[101]
  PIN b[102]
    DIRECTION OUTPUT ;
    USE SIGNAL ;
    PORT
      LAYER M4 ;
        RECT  0 5.52 0.192 5.544 ;
    END
  END b[102]
  PIN b[103]
    DIRECTION OUTPUT ;
    USE SIGNAL ;
    PORT
      LAYER M4 ;
        RECT  0 5.568 0.192 5.592 ;
    END
  END b[103]
  PIN b[104]
    DIRECTION OUTPUT ;
    USE SIGNAL ;
    PORT
      LAYER M4 ;
        RECT  0 5.616 0.192 5.64 ;
    END
  END b[104]
  PIN b[105]
    DIRECTION OUTPUT ;
    USE SIGNAL ;
    PORT
      LAYER M4 ;
        RECT  0 5.664 0.192 5.688 ;
    END
  END b[105]
  PIN b[106]
    DIRECTION OUTPUT ;
    USE SIGNAL ;
    PORT
      LAYER M4 ;
        RECT  0 5.712 0.192 5.736 ;
    END
  END b[106]
  PIN b[107]
    DIRECTION OUTPUT ;
    USE SIGNAL ;
    PORT
      LAYER M4 ;
        RECT  0 5.76 0.192 5.784 ;
    END
  END b[107]
  PIN b[108]
    DIRECTION OUTPUT ;
    USE SIGNAL ;
    PORT
      LAYER M4 ;
        RECT  0 5.808 0.192 5.832 ;
    END
  END b[108]
  PIN b[109]
    DIRECTION OUTPUT ;
    USE SIGNAL ;
    PORT
      LAYER M4 ;
        RECT  0 5.856 0.192 5.88 ;
    END
  END b[109]
  PIN b[10]
    DIRECTION OUTPUT ;
    USE SIGNAL ;
    PORT
      LAYER M4 ;
        RECT  0 1.104 0.192 1.128 ;
    END
  END b[10]
  PIN b[110]
    DIRECTION OUTPUT ;
    USE SIGNAL ;
    PORT
      LAYER M4 ;
        RECT  0 5.904 0.192 5.928 ;
    END
  END b[110]
  PIN b[111]
    DIRECTION OUTPUT ;
    USE SIGNAL ;
    PORT
      LAYER M4 ;
        RECT  0 5.952 0.192 5.976 ;
    END
  END b[111]
  PIN b[112]
    DIRECTION OUTPUT ;
    USE SIGNAL ;
    PORT
      LAYER M4 ;
        RECT  0 6 0.192 6.024 ;
    END
  END b[112]
  PIN b[113]
    DIRECTION OUTPUT ;
    USE SIGNAL ;
    PORT
      LAYER M4 ;
        RECT  0 6.048 0.192 6.072 ;
    END
  END b[113]
  PIN b[114]
    DIRECTION OUTPUT ;
    USE SIGNAL ;
    PORT
      LAYER M4 ;
        RECT  0 6.096 0.192 6.12 ;
    END
  END b[114]
  PIN b[115]
    DIRECTION OUTPUT ;
    USE SIGNAL ;
    PORT
      LAYER M4 ;
        RECT  0 6.144 0.192 6.168 ;
    END
  END b[115]
  PIN b[116]
    DIRECTION OUTPUT ;
    USE SIGNAL ;
    PORT
      LAYER M4 ;
        RECT  0 6.192 0.192 6.216 ;
    END
  END b[116]
  PIN b[117]
    DIRECTION OUTPUT ;
    USE SIGNAL ;
    PORT
      LAYER M4 ;
        RECT  0 6.24 0.192 6.264 ;
    END
  END b[117]
  PIN b[118]
    DIRECTION OUTPUT ;
    USE SIGNAL ;
    PORT
      LAYER M4 ;
        RECT  0 6.288 0.192 6.312 ;
    END
  END b[118]
  PIN b[119]
    DIRECTION OUTPUT ;
    USE SIGNAL ;
    PORT
      LAYER M4 ;
        RECT  0 6.336 0.192 6.36 ;
    END
  END b[119]
  PIN b[11]
    DIRECTION OUTPUT ;
    USE SIGNAL ;
    PORT
      LAYER M4 ;
        RECT  0 1.152 0.192 1.176 ;
    END
  END b[11]
  PIN b[120]
    DIRECTION OUTPUT ;
    USE SIGNAL ;
    PORT
      LAYER M4 ;
        RECT  0 6.384 0.192 6.408 ;
    END
  END b[120]
  PIN b[121]
    DIRECTION OUTPUT ;
    USE SIGNAL ;
    PORT
      LAYER M4 ;
        RECT  0 6.432 0.192 6.456 ;
    END
  END b[121]
  PIN b[122]
    DIRECTION OUTPUT ;
    USE SIGNAL ;
    PORT
      LAYER M4 ;
        RECT  0 6.48 0.192 6.504 ;
    END
  END b[122]
  PIN b[123]
    DIRECTION OUTPUT ;
    USE SIGNAL ;
    PORT
      LAYER M4 ;
        RECT  0 6.528 0.192 6.552 ;
    END
  END b[123]
  PIN b[124]
    DIRECTION OUTPUT ;
    USE SIGNAL ;
    PORT
      LAYER M4 ;
        RECT  0 6.576 0.192 6.6 ;
    END
  END b[124]
  PIN b[125]
    DIRECTION OUTPUT ;
    USE SIGNAL ;
    PORT
      LAYER M4 ;
        RECT  0 6.624 0.192 6.648 ;
    END
  END b[125]
  PIN b[126]
    DIRECTION OUTPUT ;
    USE SIGNAL ;
    PORT
      LAYER M4 ;
        RECT  0 6.672 0.192 6.696 ;
    END
  END b[126]
  PIN b[127]
    DIRECTION OUTPUT ;
    USE SIGNAL ;
    PORT
      LAYER M4 ;
        RECT  0 6.72 0.192 6.744 ;
    END
  END b[127]
  PIN b[128]
    DIRECTION OUTPUT ;
    USE SIGNAL ;
    PORT
      LAYER M4 ;
        RECT  0 6.768 0.192 6.792 ;
    END
  END b[128]
  PIN b[129]
    DIRECTION OUTPUT ;
    USE SIGNAL ;
    PORT
      LAYER M4 ;
        RECT  0 6.816 0.192 6.84 ;
    END
  END b[129]
  PIN b[12]
    DIRECTION OUTPUT ;
    USE SIGNAL ;
    PORT
      LAYER M4 ;
        RECT  0 1.2 0.192 1.224 ;
    END
  END b[12]
  PIN b[130]
    DIRECTION OUTPUT ;
    USE SIGNAL ;
    PORT
      LAYER M4 ;
        RECT  0 6.864 0.192 6.888 ;
    END
  END b[130]
  PIN b[131]
    DIRECTION OUTPUT ;
    USE SIGNAL ;
    PORT
      LAYER M4 ;
        RECT  0 6.912 0.192 6.936 ;
    END
  END b[131]
  PIN b[132]
    DIRECTION OUTPUT ;
    USE SIGNAL ;
    PORT
      LAYER M4 ;
        RECT  0 6.96 0.192 6.984 ;
    END
  END b[132]
  PIN b[133]
    DIRECTION OUTPUT ;
    USE SIGNAL ;
    PORT
      LAYER M4 ;
        RECT  0 7.008 0.192 7.032 ;
    END
  END b[133]
  PIN b[134]
    DIRECTION OUTPUT ;
    USE SIGNAL ;
    PORT
      LAYER M4 ;
        RECT  0 7.056 0.192 7.08 ;
    END
  END b[134]
  PIN b[135]
    DIRECTION OUTPUT ;
    USE SIGNAL ;
    PORT
      LAYER M4 ;
        RECT  0 7.104 0.192 7.128 ;
    END
  END b[135]
  PIN b[136]
    DIRECTION OUTPUT ;
    USE SIGNAL ;
    PORT
      LAYER M4 ;
        RECT  0 7.152 0.192 7.176 ;
    END
  END b[136]
  PIN b[137]
    DIRECTION OUTPUT ;
    USE SIGNAL ;
    PORT
      LAYER M4 ;
        RECT  0 7.2 0.192 7.224 ;
    END
  END b[137]
  PIN b[138]
    DIRECTION OUTPUT ;
    USE SIGNAL ;
    PORT
      LAYER M4 ;
        RECT  0 7.248 0.192 7.272 ;
    END
  END b[138]
  PIN b[139]
    DIRECTION OUTPUT ;
    USE SIGNAL ;
    PORT
      LAYER M4 ;
        RECT  0 7.296 0.192 7.32 ;
    END
  END b[139]
  PIN b[13]
    DIRECTION OUTPUT ;
    USE SIGNAL ;
    PORT
      LAYER M4 ;
        RECT  0 1.248 0.192 1.272 ;
    END
  END b[13]
  PIN b[140]
    DIRECTION OUTPUT ;
    USE SIGNAL ;
    PORT
      LAYER M4 ;
        RECT  0 7.344 0.192 7.368 ;
    END
  END b[140]
  PIN b[141]
    DIRECTION OUTPUT ;
    USE SIGNAL ;
    PORT
      LAYER M4 ;
        RECT  0 7.392 0.192 7.416 ;
    END
  END b[141]
  PIN b[142]
    DIRECTION OUTPUT ;
    USE SIGNAL ;
    PORT
      LAYER M4 ;
        RECT  0 7.44 0.192 7.464 ;
    END
  END b[142]
  PIN b[143]
    DIRECTION OUTPUT ;
    USE SIGNAL ;
    PORT
      LAYER M4 ;
        RECT  0 7.488 0.192 7.512 ;
    END
  END b[143]
  PIN b[144]
    DIRECTION OUTPUT ;
    USE SIGNAL ;
    PORT
      LAYER M4 ;
        RECT  0 7.536 0.192 7.56 ;
    END
  END b[144]
  PIN b[145]
    DIRECTION OUTPUT ;
    USE SIGNAL ;
    PORT
      LAYER M4 ;
        RECT  0 7.584 0.192 7.608 ;
    END
  END b[145]
  PIN b[146]
    DIRECTION OUTPUT ;
    USE SIGNAL ;
    PORT
      LAYER M4 ;
        RECT  0 7.632 0.192 7.656 ;
    END
  END b[146]
  PIN b[147]
    DIRECTION OUTPUT ;
    USE SIGNAL ;
    PORT
      LAYER M4 ;
        RECT  0 7.68 0.192 7.704 ;
    END
  END b[147]
  PIN b[148]
    DIRECTION OUTPUT ;
    USE SIGNAL ;
    PORT
      LAYER M4 ;
        RECT  0 7.728 0.192 7.752 ;
    END
  END b[148]
  PIN b[149]
    DIRECTION OUTPUT ;
    USE SIGNAL ;
    PORT
      LAYER M4 ;
        RECT  0 7.776 0.192 7.8 ;
    END
  END b[149]
  PIN b[14]
    DIRECTION OUTPUT ;
    USE SIGNAL ;
    PORT
      LAYER M4 ;
        RECT  0 1.296 0.192 1.32 ;
    END
  END b[14]
  PIN b[150]
    DIRECTION OUTPUT ;
    USE SIGNAL ;
    PORT
      LAYER M4 ;
        RECT  0 7.824 0.192 7.848 ;
    END
  END b[150]
  PIN b[151]
    DIRECTION OUTPUT ;
    USE SIGNAL ;
    PORT
      LAYER M4 ;
        RECT  0 7.872 0.192 7.896 ;
    END
  END b[151]
  PIN b[152]
    DIRECTION OUTPUT ;
    USE SIGNAL ;
    PORT
      LAYER M4 ;
        RECT  0 7.92 0.192 7.944 ;
    END
  END b[152]
  PIN b[153]
    DIRECTION OUTPUT ;
    USE SIGNAL ;
    PORT
      LAYER M4 ;
        RECT  0 7.968 0.192 7.992 ;
    END
  END b[153]
  PIN b[154]
    DIRECTION OUTPUT ;
    USE SIGNAL ;
    PORT
      LAYER M4 ;
        RECT  0 8.016 0.192 8.04 ;
    END
  END b[154]
  PIN b[155]
    DIRECTION OUTPUT ;
    USE SIGNAL ;
    PORT
      LAYER M4 ;
        RECT  0 8.064 0.192 8.088 ;
    END
  END b[155]
  PIN b[156]
    DIRECTION OUTPUT ;
    USE SIGNAL ;
    PORT
      LAYER M4 ;
        RECT  0 8.112 0.192 8.136 ;
    END
  END b[156]
  PIN b[157]
    DIRECTION OUTPUT ;
    USE SIGNAL ;
    PORT
      LAYER M4 ;
        RECT  0 8.16 0.192 8.184 ;
    END
  END b[157]
  PIN b[158]
    DIRECTION OUTPUT ;
    USE SIGNAL ;
    PORT
      LAYER M4 ;
        RECT  0 8.208 0.192 8.232 ;
    END
  END b[158]
  PIN b[159]
    DIRECTION OUTPUT ;
    USE SIGNAL ;
    PORT
      LAYER M4 ;
        RECT  0 8.256 0.192 8.28 ;
    END
  END b[159]
  PIN b[15]
    DIRECTION OUTPUT ;
    USE SIGNAL ;
    PORT
      LAYER M4 ;
        RECT  0 1.344 0.192 1.368 ;
    END
  END b[15]
  PIN b[160]
    DIRECTION OUTPUT ;
    USE SIGNAL ;
    PORT
      LAYER M4 ;
        RECT  0 8.304 0.192 8.328 ;
    END
  END b[160]
  PIN b[161]
    DIRECTION OUTPUT ;
    USE SIGNAL ;
    PORT
      LAYER M4 ;
        RECT  0 8.352 0.192 8.376 ;
    END
  END b[161]
  PIN b[162]
    DIRECTION OUTPUT ;
    USE SIGNAL ;
    PORT
      LAYER M4 ;
        RECT  0 8.4 0.192 8.424 ;
    END
  END b[162]
  PIN b[163]
    DIRECTION OUTPUT ;
    USE SIGNAL ;
    PORT
      LAYER M4 ;
        RECT  0 8.448 0.192 8.472 ;
    END
  END b[163]
  PIN b[164]
    DIRECTION OUTPUT ;
    USE SIGNAL ;
    PORT
      LAYER M4 ;
        RECT  0 8.496 0.192 8.52 ;
    END
  END b[164]
  PIN b[165]
    DIRECTION OUTPUT ;
    USE SIGNAL ;
    PORT
      LAYER M4 ;
        RECT  0 8.544 0.192 8.568 ;
    END
  END b[165]
  PIN b[166]
    DIRECTION OUTPUT ;
    USE SIGNAL ;
    PORT
      LAYER M4 ;
        RECT  0 8.592 0.192 8.616 ;
    END
  END b[166]
  PIN b[167]
    DIRECTION OUTPUT ;
    USE SIGNAL ;
    PORT
      LAYER M4 ;
        RECT  0 8.64 0.192 8.664 ;
    END
  END b[167]
  PIN b[168]
    DIRECTION OUTPUT ;
    USE SIGNAL ;
    PORT
      LAYER M4 ;
        RECT  0 8.688 0.192 8.712 ;
    END
  END b[168]
  PIN b[169]
    DIRECTION OUTPUT ;
    USE SIGNAL ;
    PORT
      LAYER M4 ;
        RECT  0 8.736 0.192 8.76 ;
    END
  END b[169]
  PIN b[16]
    DIRECTION OUTPUT ;
    USE SIGNAL ;
    PORT
      LAYER M4 ;
        RECT  0 1.392 0.192 1.416 ;
    END
  END b[16]
  PIN b[170]
    DIRECTION OUTPUT ;
    USE SIGNAL ;
    PORT
      LAYER M4 ;
        RECT  0 8.784 0.192 8.808 ;
    END
  END b[170]
  PIN b[171]
    DIRECTION OUTPUT ;
    USE SIGNAL ;
    PORT
      LAYER M4 ;
        RECT  0 8.832 0.192 8.856 ;
    END
  END b[171]
  PIN b[172]
    DIRECTION OUTPUT ;
    USE SIGNAL ;
    PORT
      LAYER M4 ;
        RECT  0 8.88 0.192 8.904 ;
    END
  END b[172]
  PIN b[173]
    DIRECTION OUTPUT ;
    USE SIGNAL ;
    PORT
      LAYER M4 ;
        RECT  0 8.928 0.192 8.952 ;
    END
  END b[173]
  PIN b[174]
    DIRECTION OUTPUT ;
    USE SIGNAL ;
    PORT
      LAYER M4 ;
        RECT  0 8.976 0.192 9 ;
    END
  END b[174]
  PIN b[175]
    DIRECTION OUTPUT ;
    USE SIGNAL ;
    PORT
      LAYER M4 ;
        RECT  0 9.024 0.192 9.048 ;
    END
  END b[175]
  PIN b[176]
    DIRECTION OUTPUT ;
    USE SIGNAL ;
    PORT
      LAYER M4 ;
        RECT  0 9.072 0.192 9.096 ;
    END
  END b[176]
  PIN b[177]
    DIRECTION OUTPUT ;
    USE SIGNAL ;
    PORT
      LAYER M4 ;
        RECT  0 9.12 0.192 9.144 ;
    END
  END b[177]
  PIN b[178]
    DIRECTION OUTPUT ;
    USE SIGNAL ;
    PORT
      LAYER M4 ;
        RECT  0 9.168 0.192 9.192 ;
    END
  END b[178]
  PIN b[179]
    DIRECTION OUTPUT ;
    USE SIGNAL ;
    PORT
      LAYER M4 ;
        RECT  0 9.216 0.192 9.24 ;
    END
  END b[179]
  PIN b[17]
    DIRECTION OUTPUT ;
    USE SIGNAL ;
    PORT
      LAYER M4 ;
        RECT  0 1.44 0.192 1.464 ;
    END
  END b[17]
  PIN b[180]
    DIRECTION OUTPUT ;
    USE SIGNAL ;
    PORT
      LAYER M4 ;
        RECT  0 9.264 0.192 9.288 ;
    END
  END b[180]
  PIN b[181]
    DIRECTION OUTPUT ;
    USE SIGNAL ;
    PORT
      LAYER M4 ;
        RECT  0 9.312 0.192 9.336 ;
    END
  END b[181]
  PIN b[182]
    DIRECTION OUTPUT ;
    USE SIGNAL ;
    PORT
      LAYER M4 ;
        RECT  0 9.36 0.192 9.384 ;
    END
  END b[182]
  PIN b[183]
    DIRECTION OUTPUT ;
    USE SIGNAL ;
    PORT
      LAYER M4 ;
        RECT  0 9.408 0.192 9.432 ;
    END
  END b[183]
  PIN b[184]
    DIRECTION OUTPUT ;
    USE SIGNAL ;
    PORT
      LAYER M4 ;
        RECT  0 9.456 0.192 9.48 ;
    END
  END b[184]
  PIN b[185]
    DIRECTION OUTPUT ;
    USE SIGNAL ;
    PORT
      LAYER M4 ;
        RECT  0 9.504 0.192 9.528 ;
    END
  END b[185]
  PIN b[186]
    DIRECTION OUTPUT ;
    USE SIGNAL ;
    PORT
      LAYER M4 ;
        RECT  0 9.552 0.192 9.576 ;
    END
  END b[186]
  PIN b[187]
    DIRECTION OUTPUT ;
    USE SIGNAL ;
    PORT
      LAYER M4 ;
        RECT  0 9.6 0.192 9.624 ;
    END
  END b[187]
  PIN b[188]
    DIRECTION OUTPUT ;
    USE SIGNAL ;
    PORT
      LAYER M4 ;
        RECT  0 9.648 0.192 9.672 ;
    END
  END b[188]
  PIN b[189]
    DIRECTION OUTPUT ;
    USE SIGNAL ;
    PORT
      LAYER M4 ;
        RECT  0 9.696 0.192 9.72 ;
    END
  END b[189]
  PIN b[18]
    DIRECTION OUTPUT ;
    USE SIGNAL ;
    PORT
      LAYER M4 ;
        RECT  0 1.488 0.192 1.512 ;
    END
  END b[18]
  PIN b[190]
    DIRECTION OUTPUT ;
    USE SIGNAL ;
    PORT
      LAYER M4 ;
        RECT  0 9.744 0.192 9.768 ;
    END
  END b[190]
  PIN b[191]
    DIRECTION OUTPUT ;
    USE SIGNAL ;
    PORT
      LAYER M4 ;
        RECT  0 9.792 0.192 9.816 ;
    END
  END b[191]
  PIN b[192]
    DIRECTION OUTPUT ;
    USE SIGNAL ;
    PORT
      LAYER M4 ;
        RECT  0 9.84 0.192 9.864 ;
    END
  END b[192]
  PIN b[193]
    DIRECTION OUTPUT ;
    USE SIGNAL ;
    PORT
      LAYER M4 ;
        RECT  0 9.888 0.192 9.912 ;
    END
  END b[193]
  PIN b[194]
    DIRECTION OUTPUT ;
    USE SIGNAL ;
    PORT
      LAYER M4 ;
        RECT  0 9.936 0.192 9.96 ;
    END
  END b[194]
  PIN b[195]
    DIRECTION OUTPUT ;
    USE SIGNAL ;
    PORT
      LAYER M4 ;
        RECT  0 9.984 0.192 10.008 ;
    END
  END b[195]
  PIN b[196]
    DIRECTION OUTPUT ;
    USE SIGNAL ;
    PORT
      LAYER M4 ;
        RECT  0 10.032 0.192 10.056 ;
    END
  END b[196]
  PIN b[197]
    DIRECTION OUTPUT ;
    USE SIGNAL ;
    PORT
      LAYER M4 ;
        RECT  0 10.08 0.192 10.104 ;
    END
  END b[197]
  PIN b[198]
    DIRECTION OUTPUT ;
    USE SIGNAL ;
    PORT
      LAYER M4 ;
        RECT  0 10.128 0.192 10.152 ;
    END
  END b[198]
  PIN b[199]
    DIRECTION OUTPUT ;
    USE SIGNAL ;
    PORT
      LAYER M4 ;
        RECT  0 10.176 0.192 10.2 ;
    END
  END b[199]
  PIN b[19]
    DIRECTION OUTPUT ;
    USE SIGNAL ;
    PORT
      LAYER M4 ;
        RECT  0 1.536 0.192 1.56 ;
    END
  END b[19]
  PIN b[1]
    DIRECTION OUTPUT ;
    USE SIGNAL ;
    PORT
      LAYER M4 ;
        RECT  0 0.672 0.192 0.696 ;
    END
  END b[1]
  PIN b[200]
    DIRECTION OUTPUT ;
    USE SIGNAL ;
    PORT
      LAYER M4 ;
        RECT  0 10.224 0.192 10.248 ;
    END
  END b[200]
  PIN b[201]
    DIRECTION OUTPUT ;
    USE SIGNAL ;
    PORT
      LAYER M4 ;
        RECT  0 10.272 0.192 10.296 ;
    END
  END b[201]
  PIN b[202]
    DIRECTION OUTPUT ;
    USE SIGNAL ;
    PORT
      LAYER M4 ;
        RECT  0 10.32 0.192 10.344 ;
    END
  END b[202]
  PIN b[203]
    DIRECTION OUTPUT ;
    USE SIGNAL ;
    PORT
      LAYER M4 ;
        RECT  0 10.368 0.192 10.392 ;
    END
  END b[203]
  PIN b[204]
    DIRECTION OUTPUT ;
    USE SIGNAL ;
    PORT
      LAYER M4 ;
        RECT  0 10.416 0.192 10.44 ;
    END
  END b[204]
  PIN b[205]
    DIRECTION OUTPUT ;
    USE SIGNAL ;
    PORT
      LAYER M4 ;
        RECT  0 10.464 0.192 10.488 ;
    END
  END b[205]
  PIN b[206]
    DIRECTION OUTPUT ;
    USE SIGNAL ;
    PORT
      LAYER M4 ;
        RECT  0 10.512 0.192 10.536 ;
    END
  END b[206]
  PIN b[207]
    DIRECTION OUTPUT ;
    USE SIGNAL ;
    PORT
      LAYER M4 ;
        RECT  0 10.56 0.192 10.584 ;
    END
  END b[207]
  PIN b[208]
    DIRECTION OUTPUT ;
    USE SIGNAL ;
    PORT
      LAYER M4 ;
        RECT  0 10.608 0.192 10.632 ;
    END
  END b[208]
  PIN b[209]
    DIRECTION OUTPUT ;
    USE SIGNAL ;
    PORT
      LAYER M4 ;
        RECT  0 10.656 0.192 10.68 ;
    END
  END b[209]
  PIN b[20]
    DIRECTION OUTPUT ;
    USE SIGNAL ;
    PORT
      LAYER M4 ;
        RECT  0 1.584 0.192 1.608 ;
    END
  END b[20]
  PIN b[210]
    DIRECTION OUTPUT ;
    USE SIGNAL ;
    PORT
      LAYER M4 ;
        RECT  0 10.704 0.192 10.728 ;
    END
  END b[210]
  PIN b[211]
    DIRECTION OUTPUT ;
    USE SIGNAL ;
    PORT
      LAYER M4 ;
        RECT  0 10.752 0.192 10.776 ;
    END
  END b[211]
  PIN b[212]
    DIRECTION OUTPUT ;
    USE SIGNAL ;
    PORT
      LAYER M4 ;
        RECT  0 10.8 0.192 10.824 ;
    END
  END b[212]
  PIN b[213]
    DIRECTION OUTPUT ;
    USE SIGNAL ;
    PORT
      LAYER M4 ;
        RECT  0 10.848 0.192 10.872 ;
    END
  END b[213]
  PIN b[214]
    DIRECTION OUTPUT ;
    USE SIGNAL ;
    PORT
      LAYER M4 ;
        RECT  0 10.896 0.192 10.92 ;
    END
  END b[214]
  PIN b[215]
    DIRECTION OUTPUT ;
    USE SIGNAL ;
    PORT
      LAYER M4 ;
        RECT  0 10.944 0.192 10.968 ;
    END
  END b[215]
  PIN b[216]
    DIRECTION OUTPUT ;
    USE SIGNAL ;
    PORT
      LAYER M4 ;
        RECT  0 10.992 0.192 11.016 ;
    END
  END b[216]
  PIN b[217]
    DIRECTION OUTPUT ;
    USE SIGNAL ;
    PORT
      LAYER M4 ;
        RECT  0 11.04 0.192 11.064 ;
    END
  END b[217]
  PIN b[218]
    DIRECTION OUTPUT ;
    USE SIGNAL ;
    PORT
      LAYER M4 ;
        RECT  0 11.088 0.192 11.112 ;
    END
  END b[218]
  PIN b[219]
    DIRECTION OUTPUT ;
    USE SIGNAL ;
    PORT
      LAYER M4 ;
        RECT  0 11.136 0.192 11.16 ;
    END
  END b[219]
  PIN b[21]
    DIRECTION OUTPUT ;
    USE SIGNAL ;
    PORT
      LAYER M4 ;
        RECT  0 1.632 0.192 1.656 ;
    END
  END b[21]
  PIN b[220]
    DIRECTION OUTPUT ;
    USE SIGNAL ;
    PORT
      LAYER M4 ;
        RECT  0 11.184 0.192 11.208 ;
    END
  END b[220]
  PIN b[221]
    DIRECTION OUTPUT ;
    USE SIGNAL ;
    PORT
      LAYER M4 ;
        RECT  0 11.232 0.192 11.256 ;
    END
  END b[221]
  PIN b[222]
    DIRECTION OUTPUT ;
    USE SIGNAL ;
    PORT
      LAYER M4 ;
        RECT  0 11.28 0.192 11.304 ;
    END
  END b[222]
  PIN b[223]
    DIRECTION OUTPUT ;
    USE SIGNAL ;
    PORT
      LAYER M4 ;
        RECT  0 11.328 0.192 11.352 ;
    END
  END b[223]
  PIN b[224]
    DIRECTION OUTPUT ;
    USE SIGNAL ;
    PORT
      LAYER M4 ;
        RECT  0 11.376 0.192 11.4 ;
    END
  END b[224]
  PIN b[225]
    DIRECTION OUTPUT ;
    USE SIGNAL ;
    PORT
      LAYER M4 ;
        RECT  0 11.424 0.192 11.448 ;
    END
  END b[225]
  PIN b[226]
    DIRECTION OUTPUT ;
    USE SIGNAL ;
    PORT
      LAYER M4 ;
        RECT  0 11.472 0.192 11.496 ;
    END
  END b[226]
  PIN b[227]
    DIRECTION OUTPUT ;
    USE SIGNAL ;
    PORT
      LAYER M4 ;
        RECT  0 11.52 0.192 11.544 ;
    END
  END b[227]
  PIN b[228]
    DIRECTION OUTPUT ;
    USE SIGNAL ;
    PORT
      LAYER M4 ;
        RECT  0 11.568 0.192 11.592 ;
    END
  END b[228]
  PIN b[229]
    DIRECTION OUTPUT ;
    USE SIGNAL ;
    PORT
      LAYER M4 ;
        RECT  0 11.616 0.192 11.64 ;
    END
  END b[229]
  PIN b[22]
    DIRECTION OUTPUT ;
    USE SIGNAL ;
    PORT
      LAYER M4 ;
        RECT  0 1.68 0.192 1.704 ;
    END
  END b[22]
  PIN b[230]
    DIRECTION OUTPUT ;
    USE SIGNAL ;
    PORT
      LAYER M4 ;
        RECT  0 11.664 0.192 11.688 ;
    END
  END b[230]
  PIN b[231]
    DIRECTION OUTPUT ;
    USE SIGNAL ;
    PORT
      LAYER M4 ;
        RECT  0 11.712 0.192 11.736 ;
    END
  END b[231]
  PIN b[232]
    DIRECTION OUTPUT ;
    USE SIGNAL ;
    PORT
      LAYER M4 ;
        RECT  0 11.76 0.192 11.784 ;
    END
  END b[232]
  PIN b[233]
    DIRECTION OUTPUT ;
    USE SIGNAL ;
    PORT
      LAYER M4 ;
        RECT  0 11.808 0.192 11.832 ;
    END
  END b[233]
  PIN b[234]
    DIRECTION OUTPUT ;
    USE SIGNAL ;
    PORT
      LAYER M4 ;
        RECT  0 11.856 0.192 11.88 ;
    END
  END b[234]
  PIN b[235]
    DIRECTION OUTPUT ;
    USE SIGNAL ;
    PORT
      LAYER M4 ;
        RECT  0 11.904 0.192 11.928 ;
    END
  END b[235]
  PIN b[236]
    DIRECTION OUTPUT ;
    USE SIGNAL ;
    PORT
      LAYER M4 ;
        RECT  0 11.952 0.192 11.976 ;
    END
  END b[236]
  PIN b[237]
    DIRECTION OUTPUT ;
    USE SIGNAL ;
    PORT
      LAYER M4 ;
        RECT  0 12 0.192 12.024 ;
    END
  END b[237]
  PIN b[238]
    DIRECTION OUTPUT ;
    USE SIGNAL ;
    PORT
      LAYER M4 ;
        RECT  0 12.048 0.192 12.072 ;
    END
  END b[238]
  PIN b[239]
    DIRECTION OUTPUT ;
    USE SIGNAL ;
    PORT
      LAYER M4 ;
        RECT  0 12.096 0.192 12.12 ;
    END
  END b[239]
  PIN b[23]
    DIRECTION OUTPUT ;
    USE SIGNAL ;
    PORT
      LAYER M4 ;
        RECT  0 1.728 0.192 1.752 ;
    END
  END b[23]
  PIN b[240]
    DIRECTION OUTPUT ;
    USE SIGNAL ;
    PORT
      LAYER M4 ;
        RECT  0 12.144 0.192 12.168 ;
    END
  END b[240]
  PIN b[241]
    DIRECTION OUTPUT ;
    USE SIGNAL ;
    PORT
      LAYER M4 ;
        RECT  0 12.192 0.192 12.216 ;
    END
  END b[241]
  PIN b[242]
    DIRECTION OUTPUT ;
    USE SIGNAL ;
    PORT
      LAYER M4 ;
        RECT  0 12.24 0.192 12.264 ;
    END
  END b[242]
  PIN b[243]
    DIRECTION OUTPUT ;
    USE SIGNAL ;
    PORT
      LAYER M4 ;
        RECT  0 12.288 0.192 12.312 ;
    END
  END b[243]
  PIN b[244]
    DIRECTION OUTPUT ;
    USE SIGNAL ;
    PORT
      LAYER M4 ;
        RECT  0 12.336 0.192 12.36 ;
    END
  END b[244]
  PIN b[245]
    DIRECTION OUTPUT ;
    USE SIGNAL ;
    PORT
      LAYER M4 ;
        RECT  0 12.384 0.192 12.408 ;
    END
  END b[245]
  PIN b[246]
    DIRECTION OUTPUT ;
    USE SIGNAL ;
    PORT
      LAYER M4 ;
        RECT  0 12.432 0.192 12.456 ;
    END
  END b[246]
  PIN b[247]
    DIRECTION OUTPUT ;
    USE SIGNAL ;
    PORT
      LAYER M4 ;
        RECT  0 12.48 0.192 12.504 ;
    END
  END b[247]
  PIN b[248]
    DIRECTION OUTPUT ;
    USE SIGNAL ;
    PORT
      LAYER M4 ;
        RECT  0 12.528 0.192 12.552 ;
    END
  END b[248]
  PIN b[249]
    DIRECTION OUTPUT ;
    USE SIGNAL ;
    PORT
      LAYER M4 ;
        RECT  0 12.576 0.192 12.6 ;
    END
  END b[249]
  PIN b[24]
    DIRECTION OUTPUT ;
    USE SIGNAL ;
    PORT
      LAYER M4 ;
        RECT  0 1.776 0.192 1.8 ;
    END
  END b[24]
  PIN b[250]
    DIRECTION OUTPUT ;
    USE SIGNAL ;
    PORT
      LAYER M4 ;
        RECT  0 12.624 0.192 12.648 ;
    END
  END b[250]
  PIN b[251]
    DIRECTION OUTPUT ;
    USE SIGNAL ;
    PORT
      LAYER M4 ;
        RECT  0 12.672 0.192 12.696 ;
    END
  END b[251]
  PIN b[252]
    DIRECTION OUTPUT ;
    USE SIGNAL ;
    PORT
      LAYER M4 ;
        RECT  0 12.72 0.192 12.744 ;
    END
  END b[252]
  PIN b[253]
    DIRECTION OUTPUT ;
    USE SIGNAL ;
    PORT
      LAYER M4 ;
        RECT  0 12.768 0.192 12.792 ;
    END
  END b[253]
  PIN b[254]
    DIRECTION OUTPUT ;
    USE SIGNAL ;
    PORT
      LAYER M4 ;
        RECT  0 12.816 0.192 12.84 ;
    END
  END b[254]
  PIN b[255]
    DIRECTION OUTPUT ;
    USE SIGNAL ;
    PORT
      LAYER M4 ;
        RECT  0 12.864 0.192 12.888 ;
    END
  END b[255]
  PIN b[256]
    DIRECTION OUTPUT ;
    USE SIGNAL ;
    PORT
      LAYER M4 ;
        RECT  0 12.912 0.192 12.936 ;
    END
  END b[256]
  PIN b[257]
    DIRECTION OUTPUT ;
    USE SIGNAL ;
    PORT
      LAYER M4 ;
        RECT  0 12.96 0.192 12.984 ;
    END
  END b[257]
  PIN b[258]
    DIRECTION OUTPUT ;
    USE SIGNAL ;
    PORT
      LAYER M4 ;
        RECT  0 13.008 0.192 13.032 ;
    END
  END b[258]
  PIN b[259]
    DIRECTION OUTPUT ;
    USE SIGNAL ;
    PORT
      LAYER M4 ;
        RECT  0 13.056 0.192 13.08 ;
    END
  END b[259]
  PIN b[25]
    DIRECTION OUTPUT ;
    USE SIGNAL ;
    PORT
      LAYER M4 ;
        RECT  0 1.824 0.192 1.848 ;
    END
  END b[25]
  PIN b[260]
    DIRECTION OUTPUT ;
    USE SIGNAL ;
    PORT
      LAYER M4 ;
        RECT  0 13.104 0.192 13.128 ;
    END
  END b[260]
  PIN b[261]
    DIRECTION OUTPUT ;
    USE SIGNAL ;
    PORT
      LAYER M4 ;
        RECT  0 13.152 0.192 13.176 ;
    END
  END b[261]
  PIN b[262]
    DIRECTION OUTPUT ;
    USE SIGNAL ;
    PORT
      LAYER M4 ;
        RECT  0 13.2 0.192 13.224 ;
    END
  END b[262]
  PIN b[263]
    DIRECTION OUTPUT ;
    USE SIGNAL ;
    PORT
      LAYER M4 ;
        RECT  0 13.248 0.192 13.272 ;
    END
  END b[263]
  PIN b[264]
    DIRECTION OUTPUT ;
    USE SIGNAL ;
    PORT
      LAYER M4 ;
        RECT  0 13.296 0.192 13.32 ;
    END
  END b[264]
  PIN b[265]
    DIRECTION OUTPUT ;
    USE SIGNAL ;
    PORT
      LAYER M4 ;
        RECT  0 13.344 0.192 13.368 ;
    END
  END b[265]
  PIN b[266]
    DIRECTION OUTPUT ;
    USE SIGNAL ;
    PORT
      LAYER M4 ;
        RECT  0 13.392 0.192 13.416 ;
    END
  END b[266]
  PIN b[267]
    DIRECTION OUTPUT ;
    USE SIGNAL ;
    PORT
      LAYER M4 ;
        RECT  0 13.44 0.192 13.464 ;
    END
  END b[267]
  PIN b[268]
    DIRECTION OUTPUT ;
    USE SIGNAL ;
    PORT
      LAYER M4 ;
        RECT  0 13.488 0.192 13.512 ;
    END
  END b[268]
  PIN b[269]
    DIRECTION OUTPUT ;
    USE SIGNAL ;
    PORT
      LAYER M4 ;
        RECT  0 13.536 0.192 13.56 ;
    END
  END b[269]
  PIN b[26]
    DIRECTION OUTPUT ;
    USE SIGNAL ;
    PORT
      LAYER M4 ;
        RECT  0 1.872 0.192 1.896 ;
    END
  END b[26]
  PIN b[270]
    DIRECTION OUTPUT ;
    USE SIGNAL ;
    PORT
      LAYER M4 ;
        RECT  0 13.584 0.192 13.608 ;
    END
  END b[270]
  PIN b[271]
    DIRECTION OUTPUT ;
    USE SIGNAL ;
    PORT
      LAYER M4 ;
        RECT  0 13.632 0.192 13.656 ;
    END
  END b[271]
  PIN b[272]
    DIRECTION OUTPUT ;
    USE SIGNAL ;
    PORT
      LAYER M4 ;
        RECT  0 13.68 0.192 13.704 ;
    END
  END b[272]
  PIN b[273]
    DIRECTION OUTPUT ;
    USE SIGNAL ;
    PORT
      LAYER M4 ;
        RECT  0 13.728 0.192 13.752 ;
    END
  END b[273]
  PIN b[274]
    DIRECTION OUTPUT ;
    USE SIGNAL ;
    PORT
      LAYER M4 ;
        RECT  0 13.776 0.192 13.8 ;
    END
  END b[274]
  PIN b[275]
    DIRECTION OUTPUT ;
    USE SIGNAL ;
    PORT
      LAYER M4 ;
        RECT  0 13.824 0.192 13.848 ;
    END
  END b[275]
  PIN b[276]
    DIRECTION OUTPUT ;
    USE SIGNAL ;
    PORT
      LAYER M4 ;
        RECT  0 13.872 0.192 13.896 ;
    END
  END b[276]
  PIN b[277]
    DIRECTION OUTPUT ;
    USE SIGNAL ;
    PORT
      LAYER M4 ;
        RECT  0 13.92 0.192 13.944 ;
    END
  END b[277]
  PIN b[278]
    DIRECTION OUTPUT ;
    USE SIGNAL ;
    PORT
      LAYER M4 ;
        RECT  0 13.968 0.192 13.992 ;
    END
  END b[278]
  PIN b[279]
    DIRECTION OUTPUT ;
    USE SIGNAL ;
    PORT
      LAYER M4 ;
        RECT  0 14.016 0.192 14.04 ;
    END
  END b[279]
  PIN b[27]
    DIRECTION OUTPUT ;
    USE SIGNAL ;
    PORT
      LAYER M4 ;
        RECT  0 1.92 0.192 1.944 ;
    END
  END b[27]
  PIN b[280]
    DIRECTION OUTPUT ;
    USE SIGNAL ;
    PORT
      LAYER M4 ;
        RECT  0 14.064 0.192 14.088 ;
    END
  END b[280]
  PIN b[281]
    DIRECTION OUTPUT ;
    USE SIGNAL ;
    PORT
      LAYER M4 ;
        RECT  0 14.112 0.192 14.136 ;
    END
  END b[281]
  PIN b[282]
    DIRECTION OUTPUT ;
    USE SIGNAL ;
    PORT
      LAYER M4 ;
        RECT  0 14.16 0.192 14.184 ;
    END
  END b[282]
  PIN b[283]
    DIRECTION OUTPUT ;
    USE SIGNAL ;
    PORT
      LAYER M4 ;
        RECT  0 14.208 0.192 14.232 ;
    END
  END b[283]
  PIN b[284]
    DIRECTION OUTPUT ;
    USE SIGNAL ;
    PORT
      LAYER M4 ;
        RECT  0 14.256 0.192 14.28 ;
    END
  END b[284]
  PIN b[285]
    DIRECTION OUTPUT ;
    USE SIGNAL ;
    PORT
      LAYER M4 ;
        RECT  0 14.304 0.192 14.328 ;
    END
  END b[285]
  PIN b[286]
    DIRECTION OUTPUT ;
    USE SIGNAL ;
    PORT
      LAYER M4 ;
        RECT  0 14.352 0.192 14.376 ;
    END
  END b[286]
  PIN b[287]
    DIRECTION OUTPUT ;
    USE SIGNAL ;
    PORT
      LAYER M4 ;
        RECT  0 14.4 0.192 14.424 ;
    END
  END b[287]
  PIN b[288]
    DIRECTION OUTPUT ;
    USE SIGNAL ;
    PORT
      LAYER M4 ;
        RECT  0 14.448 0.192 14.472 ;
    END
  END b[288]
  PIN b[289]
    DIRECTION OUTPUT ;
    USE SIGNAL ;
    PORT
      LAYER M4 ;
        RECT  0 14.496 0.192 14.52 ;
    END
  END b[289]
  PIN b[28]
    DIRECTION OUTPUT ;
    USE SIGNAL ;
    PORT
      LAYER M4 ;
        RECT  0 1.968 0.192 1.992 ;
    END
  END b[28]
  PIN b[290]
    DIRECTION OUTPUT ;
    USE SIGNAL ;
    PORT
      LAYER M4 ;
        RECT  0 14.544 0.192 14.568 ;
    END
  END b[290]
  PIN b[291]
    DIRECTION OUTPUT ;
    USE SIGNAL ;
    PORT
      LAYER M4 ;
        RECT  0 14.592 0.192 14.616 ;
    END
  END b[291]
  PIN b[292]
    DIRECTION OUTPUT ;
    USE SIGNAL ;
    PORT
      LAYER M4 ;
        RECT  0 14.64 0.192 14.664 ;
    END
  END b[292]
  PIN b[293]
    DIRECTION OUTPUT ;
    USE SIGNAL ;
    PORT
      LAYER M4 ;
        RECT  0 14.688 0.192 14.712 ;
    END
  END b[293]
  PIN b[294]
    DIRECTION OUTPUT ;
    USE SIGNAL ;
    PORT
      LAYER M4 ;
        RECT  0 14.736 0.192 14.76 ;
    END
  END b[294]
  PIN b[295]
    DIRECTION OUTPUT ;
    USE SIGNAL ;
    PORT
      LAYER M4 ;
        RECT  0 14.784 0.192 14.808 ;
    END
  END b[295]
  PIN b[296]
    DIRECTION OUTPUT ;
    USE SIGNAL ;
    PORT
      LAYER M4 ;
        RECT  0 14.832 0.192 14.856 ;
    END
  END b[296]
  PIN b[297]
    DIRECTION OUTPUT ;
    USE SIGNAL ;
    PORT
      LAYER M4 ;
        RECT  0 14.88 0.192 14.904 ;
    END
  END b[297]
  PIN b[298]
    DIRECTION OUTPUT ;
    USE SIGNAL ;
    PORT
      LAYER M4 ;
        RECT  0 14.928 0.192 14.952 ;
    END
  END b[298]
  PIN b[299]
    DIRECTION OUTPUT ;
    USE SIGNAL ;
    PORT
      LAYER M4 ;
        RECT  0 14.976 0.192 15 ;
    END
  END b[299]
  PIN b[29]
    DIRECTION OUTPUT ;
    USE SIGNAL ;
    PORT
      LAYER M4 ;
        RECT  0 2.016 0.192 2.04 ;
    END
  END b[29]
  PIN b[2]
    DIRECTION OUTPUT ;
    USE SIGNAL ;
    PORT
      LAYER M4 ;
        RECT  0 0.72 0.192 0.744 ;
    END
  END b[2]
  PIN b[300]
    DIRECTION OUTPUT ;
    USE SIGNAL ;
    PORT
      LAYER M4 ;
        RECT  0 15.024 0.192 15.048 ;
    END
  END b[300]
  PIN b[301]
    DIRECTION OUTPUT ;
    USE SIGNAL ;
    PORT
      LAYER M4 ;
        RECT  0 15.072 0.192 15.096 ;
    END
  END b[301]
  PIN b[302]
    DIRECTION OUTPUT ;
    USE SIGNAL ;
    PORT
      LAYER M4 ;
        RECT  0 15.12 0.192 15.144 ;
    END
  END b[302]
  PIN b[303]
    DIRECTION OUTPUT ;
    USE SIGNAL ;
    PORT
      LAYER M4 ;
        RECT  0 15.168 0.192 15.192 ;
    END
  END b[303]
  PIN b[304]
    DIRECTION OUTPUT ;
    USE SIGNAL ;
    PORT
      LAYER M4 ;
        RECT  0 15.216 0.192 15.24 ;
    END
  END b[304]
  PIN b[305]
    DIRECTION OUTPUT ;
    USE SIGNAL ;
    PORT
      LAYER M4 ;
        RECT  0 15.264 0.192 15.288 ;
    END
  END b[305]
  PIN b[306]
    DIRECTION OUTPUT ;
    USE SIGNAL ;
    PORT
      LAYER M4 ;
        RECT  0 15.312 0.192 15.336 ;
    END
  END b[306]
  PIN b[307]
    DIRECTION OUTPUT ;
    USE SIGNAL ;
    PORT
      LAYER M4 ;
        RECT  0 15.36 0.192 15.384 ;
    END
  END b[307]
  PIN b[308]
    DIRECTION OUTPUT ;
    USE SIGNAL ;
    PORT
      LAYER M4 ;
        RECT  0 15.408 0.192 15.432 ;
    END
  END b[308]
  PIN b[309]
    DIRECTION OUTPUT ;
    USE SIGNAL ;
    PORT
      LAYER M4 ;
        RECT  0 15.456 0.192 15.48 ;
    END
  END b[309]
  PIN b[30]
    DIRECTION OUTPUT ;
    USE SIGNAL ;
    PORT
      LAYER M4 ;
        RECT  0 2.064 0.192 2.088 ;
    END
  END b[30]
  PIN b[310]
    DIRECTION OUTPUT ;
    USE SIGNAL ;
    PORT
      LAYER M4 ;
        RECT  0 15.504 0.192 15.528 ;
    END
  END b[310]
  PIN b[311]
    DIRECTION OUTPUT ;
    USE SIGNAL ;
    PORT
      LAYER M4 ;
        RECT  0 15.552 0.192 15.576 ;
    END
  END b[311]
  PIN b[312]
    DIRECTION OUTPUT ;
    USE SIGNAL ;
    PORT
      LAYER M4 ;
        RECT  0 15.6 0.192 15.624 ;
    END
  END b[312]
  PIN b[313]
    DIRECTION OUTPUT ;
    USE SIGNAL ;
    PORT
      LAYER M4 ;
        RECT  0 15.648 0.192 15.672 ;
    END
  END b[313]
  PIN b[314]
    DIRECTION OUTPUT ;
    USE SIGNAL ;
    PORT
      LAYER M4 ;
        RECT  0 15.696 0.192 15.72 ;
    END
  END b[314]
  PIN b[315]
    DIRECTION OUTPUT ;
    USE SIGNAL ;
    PORT
      LAYER M4 ;
        RECT  0 15.744 0.192 15.768 ;
    END
  END b[315]
  PIN b[316]
    DIRECTION OUTPUT ;
    USE SIGNAL ;
    PORT
      LAYER M4 ;
        RECT  0 15.792 0.192 15.816 ;
    END
  END b[316]
  PIN b[317]
    DIRECTION OUTPUT ;
    USE SIGNAL ;
    PORT
      LAYER M4 ;
        RECT  0 15.84 0.192 15.864 ;
    END
  END b[317]
  PIN b[318]
    DIRECTION OUTPUT ;
    USE SIGNAL ;
    PORT
      LAYER M4 ;
        RECT  0 15.888 0.192 15.912 ;
    END
  END b[318]
  PIN b[319]
    DIRECTION OUTPUT ;
    USE SIGNAL ;
    PORT
      LAYER M4 ;
        RECT  0 15.936 0.192 15.96 ;
    END
  END b[319]
  PIN b[31]
    DIRECTION OUTPUT ;
    USE SIGNAL ;
    PORT
      LAYER M4 ;
        RECT  0 2.112 0.192 2.136 ;
    END
  END b[31]
  PIN b[320]
    DIRECTION OUTPUT ;
    USE SIGNAL ;
    PORT
      LAYER M4 ;
        RECT  0 15.984 0.192 16.008 ;
    END
  END b[320]
  PIN b[321]
    DIRECTION OUTPUT ;
    USE SIGNAL ;
    PORT
      LAYER M4 ;
        RECT  0 16.032 0.192 16.056 ;
    END
  END b[321]
  PIN b[322]
    DIRECTION OUTPUT ;
    USE SIGNAL ;
    PORT
      LAYER M4 ;
        RECT  0 16.08 0.192 16.104 ;
    END
  END b[322]
  PIN b[323]
    DIRECTION OUTPUT ;
    USE SIGNAL ;
    PORT
      LAYER M4 ;
        RECT  0 16.128 0.192 16.152 ;
    END
  END b[323]
  PIN b[324]
    DIRECTION OUTPUT ;
    USE SIGNAL ;
    PORT
      LAYER M4 ;
        RECT  0 16.176 0.192 16.2 ;
    END
  END b[324]
  PIN b[325]
    DIRECTION OUTPUT ;
    USE SIGNAL ;
    PORT
      LAYER M4 ;
        RECT  0 16.224 0.192 16.248 ;
    END
  END b[325]
  PIN b[326]
    DIRECTION OUTPUT ;
    USE SIGNAL ;
    PORT
      LAYER M4 ;
        RECT  0 16.272 0.192 16.296 ;
    END
  END b[326]
  PIN b[327]
    DIRECTION OUTPUT ;
    USE SIGNAL ;
    PORT
      LAYER M4 ;
        RECT  0 16.32 0.192 16.344 ;
    END
  END b[327]
  PIN b[328]
    DIRECTION OUTPUT ;
    USE SIGNAL ;
    PORT
      LAYER M4 ;
        RECT  0 16.368 0.192 16.392 ;
    END
  END b[328]
  PIN b[329]
    DIRECTION OUTPUT ;
    USE SIGNAL ;
    PORT
      LAYER M4 ;
        RECT  0 16.416 0.192 16.44 ;
    END
  END b[329]
  PIN b[32]
    DIRECTION OUTPUT ;
    USE SIGNAL ;
    PORT
      LAYER M4 ;
        RECT  0 2.16 0.192 2.184 ;
    END
  END b[32]
  PIN b[330]
    DIRECTION OUTPUT ;
    USE SIGNAL ;
    PORT
      LAYER M4 ;
        RECT  0 16.464 0.192 16.488 ;
    END
  END b[330]
  PIN b[331]
    DIRECTION OUTPUT ;
    USE SIGNAL ;
    PORT
      LAYER M4 ;
        RECT  0 16.512 0.192 16.536 ;
    END
  END b[331]
  PIN b[332]
    DIRECTION OUTPUT ;
    USE SIGNAL ;
    PORT
      LAYER M4 ;
        RECT  0 16.56 0.192 16.584 ;
    END
  END b[332]
  PIN b[333]
    DIRECTION OUTPUT ;
    USE SIGNAL ;
    PORT
      LAYER M4 ;
        RECT  0 16.608 0.192 16.632 ;
    END
  END b[333]
  PIN b[334]
    DIRECTION OUTPUT ;
    USE SIGNAL ;
    PORT
      LAYER M4 ;
        RECT  0 16.656 0.192 16.68 ;
    END
  END b[334]
  PIN b[335]
    DIRECTION OUTPUT ;
    USE SIGNAL ;
    PORT
      LAYER M4 ;
        RECT  0 16.704 0.192 16.728 ;
    END
  END b[335]
  PIN b[336]
    DIRECTION OUTPUT ;
    USE SIGNAL ;
    PORT
      LAYER M4 ;
        RECT  0 16.752 0.192 16.776 ;
    END
  END b[336]
  PIN b[337]
    DIRECTION OUTPUT ;
    USE SIGNAL ;
    PORT
      LAYER M4 ;
        RECT  0 16.8 0.192 16.824 ;
    END
  END b[337]
  PIN b[338]
    DIRECTION OUTPUT ;
    USE SIGNAL ;
    PORT
      LAYER M4 ;
        RECT  0 16.848 0.192 16.872 ;
    END
  END b[338]
  PIN b[339]
    DIRECTION OUTPUT ;
    USE SIGNAL ;
    PORT
      LAYER M4 ;
        RECT  0 16.896 0.192 16.92 ;
    END
  END b[339]
  PIN b[33]
    DIRECTION OUTPUT ;
    USE SIGNAL ;
    PORT
      LAYER M4 ;
        RECT  0 2.208 0.192 2.232 ;
    END
  END b[33]
  PIN b[340]
    DIRECTION OUTPUT ;
    USE SIGNAL ;
    PORT
      LAYER M4 ;
        RECT  0 16.944 0.192 16.968 ;
    END
  END b[340]
  PIN b[341]
    DIRECTION OUTPUT ;
    USE SIGNAL ;
    PORT
      LAYER M4 ;
        RECT  0 16.992 0.192 17.016 ;
    END
  END b[341]
  PIN b[342]
    DIRECTION OUTPUT ;
    USE SIGNAL ;
    PORT
      LAYER M4 ;
        RECT  0 17.04 0.192 17.064 ;
    END
  END b[342]
  PIN b[343]
    DIRECTION OUTPUT ;
    USE SIGNAL ;
    PORT
      LAYER M4 ;
        RECT  0 17.088 0.192 17.112 ;
    END
  END b[343]
  PIN b[344]
    DIRECTION OUTPUT ;
    USE SIGNAL ;
    PORT
      LAYER M4 ;
        RECT  0 17.136 0.192 17.16 ;
    END
  END b[344]
  PIN b[345]
    DIRECTION OUTPUT ;
    USE SIGNAL ;
    PORT
      LAYER M4 ;
        RECT  0 17.184 0.192 17.208 ;
    END
  END b[345]
  PIN b[346]
    DIRECTION OUTPUT ;
    USE SIGNAL ;
    PORT
      LAYER M4 ;
        RECT  0 17.232 0.192 17.256 ;
    END
  END b[346]
  PIN b[347]
    DIRECTION OUTPUT ;
    USE SIGNAL ;
    PORT
      LAYER M4 ;
        RECT  0 17.28 0.192 17.304 ;
    END
  END b[347]
  PIN b[348]
    DIRECTION OUTPUT ;
    USE SIGNAL ;
    PORT
      LAYER M4 ;
        RECT  0 17.328 0.192 17.352 ;
    END
  END b[348]
  PIN b[349]
    DIRECTION OUTPUT ;
    USE SIGNAL ;
    PORT
      LAYER M4 ;
        RECT  0 17.376 0.192 17.4 ;
    END
  END b[349]
  PIN b[34]
    DIRECTION OUTPUT ;
    USE SIGNAL ;
    PORT
      LAYER M4 ;
        RECT  0 2.256 0.192 2.28 ;
    END
  END b[34]
  PIN b[350]
    DIRECTION OUTPUT ;
    USE SIGNAL ;
    PORT
      LAYER M4 ;
        RECT  0 17.424 0.192 17.448 ;
    END
  END b[350]
  PIN b[351]
    DIRECTION OUTPUT ;
    USE SIGNAL ;
    PORT
      LAYER M4 ;
        RECT  0 17.472 0.192 17.496 ;
    END
  END b[351]
  PIN b[352]
    DIRECTION OUTPUT ;
    USE SIGNAL ;
    PORT
      LAYER M4 ;
        RECT  0 17.52 0.192 17.544 ;
    END
  END b[352]
  PIN b[353]
    DIRECTION OUTPUT ;
    USE SIGNAL ;
    PORT
      LAYER M4 ;
        RECT  0 17.568 0.192 17.592 ;
    END
  END b[353]
  PIN b[354]
    DIRECTION OUTPUT ;
    USE SIGNAL ;
    PORT
      LAYER M4 ;
        RECT  0 17.616 0.192 17.64 ;
    END
  END b[354]
  PIN b[355]
    DIRECTION OUTPUT ;
    USE SIGNAL ;
    PORT
      LAYER M4 ;
        RECT  0 17.664 0.192 17.688 ;
    END
  END b[355]
  PIN b[356]
    DIRECTION OUTPUT ;
    USE SIGNAL ;
    PORT
      LAYER M4 ;
        RECT  0 17.712 0.192 17.736 ;
    END
  END b[356]
  PIN b[357]
    DIRECTION OUTPUT ;
    USE SIGNAL ;
    PORT
      LAYER M4 ;
        RECT  0 17.76 0.192 17.784 ;
    END
  END b[357]
  PIN b[358]
    DIRECTION OUTPUT ;
    USE SIGNAL ;
    PORT
      LAYER M4 ;
        RECT  0 17.808 0.192 17.832 ;
    END
  END b[358]
  PIN b[359]
    DIRECTION OUTPUT ;
    USE SIGNAL ;
    PORT
      LAYER M4 ;
        RECT  0 17.856 0.192 17.88 ;
    END
  END b[359]
  PIN b[35]
    DIRECTION OUTPUT ;
    USE SIGNAL ;
    PORT
      LAYER M4 ;
        RECT  0 2.304 0.192 2.328 ;
    END
  END b[35]
  PIN b[360]
    DIRECTION OUTPUT ;
    USE SIGNAL ;
    PORT
      LAYER M4 ;
        RECT  0 17.904 0.192 17.928 ;
    END
  END b[360]
  PIN b[361]
    DIRECTION OUTPUT ;
    USE SIGNAL ;
    PORT
      LAYER M4 ;
        RECT  0 17.952 0.192 17.976 ;
    END
  END b[361]
  PIN b[362]
    DIRECTION OUTPUT ;
    USE SIGNAL ;
    PORT
      LAYER M4 ;
        RECT  0 18 0.192 18.024 ;
    END
  END b[362]
  PIN b[363]
    DIRECTION OUTPUT ;
    USE SIGNAL ;
    PORT
      LAYER M4 ;
        RECT  0 18.048 0.192 18.072 ;
    END
  END b[363]
  PIN b[364]
    DIRECTION OUTPUT ;
    USE SIGNAL ;
    PORT
      LAYER M4 ;
        RECT  0 18.096 0.192 18.12 ;
    END
  END b[364]
  PIN b[365]
    DIRECTION OUTPUT ;
    USE SIGNAL ;
    PORT
      LAYER M4 ;
        RECT  0 18.144 0.192 18.168 ;
    END
  END b[365]
  PIN b[366]
    DIRECTION OUTPUT ;
    USE SIGNAL ;
    PORT
      LAYER M4 ;
        RECT  0 18.192 0.192 18.216 ;
    END
  END b[366]
  PIN b[367]
    DIRECTION OUTPUT ;
    USE SIGNAL ;
    PORT
      LAYER M4 ;
        RECT  0 18.24 0.192 18.264 ;
    END
  END b[367]
  PIN b[368]
    DIRECTION OUTPUT ;
    USE SIGNAL ;
    PORT
      LAYER M4 ;
        RECT  0 18.288 0.192 18.312 ;
    END
  END b[368]
  PIN b[369]
    DIRECTION OUTPUT ;
    USE SIGNAL ;
    PORT
      LAYER M4 ;
        RECT  0 18.336 0.192 18.36 ;
    END
  END b[369]
  PIN b[36]
    DIRECTION OUTPUT ;
    USE SIGNAL ;
    PORT
      LAYER M4 ;
        RECT  0 2.352 0.192 2.376 ;
    END
  END b[36]
  PIN b[370]
    DIRECTION OUTPUT ;
    USE SIGNAL ;
    PORT
      LAYER M4 ;
        RECT  0 18.384 0.192 18.408 ;
    END
  END b[370]
  PIN b[371]
    DIRECTION OUTPUT ;
    USE SIGNAL ;
    PORT
      LAYER M4 ;
        RECT  0 18.432 0.192 18.456 ;
    END
  END b[371]
  PIN b[372]
    DIRECTION OUTPUT ;
    USE SIGNAL ;
    PORT
      LAYER M4 ;
        RECT  0 18.48 0.192 18.504 ;
    END
  END b[372]
  PIN b[373]
    DIRECTION OUTPUT ;
    USE SIGNAL ;
    PORT
      LAYER M4 ;
        RECT  0 18.528 0.192 18.552 ;
    END
  END b[373]
  PIN b[374]
    DIRECTION OUTPUT ;
    USE SIGNAL ;
    PORT
      LAYER M4 ;
        RECT  0 18.576 0.192 18.6 ;
    END
  END b[374]
  PIN b[375]
    DIRECTION OUTPUT ;
    USE SIGNAL ;
    PORT
      LAYER M4 ;
        RECT  0 18.624 0.192 18.648 ;
    END
  END b[375]
  PIN b[376]
    DIRECTION OUTPUT ;
    USE SIGNAL ;
    PORT
      LAYER M4 ;
        RECT  0 18.672 0.192 18.696 ;
    END
  END b[376]
  PIN b[377]
    DIRECTION OUTPUT ;
    USE SIGNAL ;
    PORT
      LAYER M4 ;
        RECT  0 18.72 0.192 18.744 ;
    END
  END b[377]
  PIN b[378]
    DIRECTION OUTPUT ;
    USE SIGNAL ;
    PORT
      LAYER M4 ;
        RECT  0 18.768 0.192 18.792 ;
    END
  END b[378]
  PIN b[379]
    DIRECTION OUTPUT ;
    USE SIGNAL ;
    PORT
      LAYER M4 ;
        RECT  0 18.816 0.192 18.84 ;
    END
  END b[379]
  PIN b[37]
    DIRECTION OUTPUT ;
    USE SIGNAL ;
    PORT
      LAYER M4 ;
        RECT  0 2.4 0.192 2.424 ;
    END
  END b[37]
  PIN b[380]
    DIRECTION OUTPUT ;
    USE SIGNAL ;
    PORT
      LAYER M4 ;
        RECT  0 18.864 0.192 18.888 ;
    END
  END b[380]
  PIN b[381]
    DIRECTION OUTPUT ;
    USE SIGNAL ;
    PORT
      LAYER M4 ;
        RECT  0 18.912 0.192 18.936 ;
    END
  END b[381]
  PIN b[382]
    DIRECTION OUTPUT ;
    USE SIGNAL ;
    PORT
      LAYER M4 ;
        RECT  0 18.96 0.192 18.984 ;
    END
  END b[382]
  PIN b[383]
    DIRECTION OUTPUT ;
    USE SIGNAL ;
    PORT
      LAYER M4 ;
        RECT  0 19.008 0.192 19.032 ;
    END
  END b[383]
  PIN b[384]
    DIRECTION OUTPUT ;
    USE SIGNAL ;
    PORT
      LAYER M4 ;
        RECT  0 19.056 0.192 19.08 ;
    END
  END b[384]
  PIN b[385]
    DIRECTION OUTPUT ;
    USE SIGNAL ;
    PORT
      LAYER M4 ;
        RECT  0 19.104 0.192 19.128 ;
    END
  END b[385]
  PIN b[386]
    DIRECTION OUTPUT ;
    USE SIGNAL ;
    PORT
      LAYER M4 ;
        RECT  0 19.152 0.192 19.176 ;
    END
  END b[386]
  PIN b[387]
    DIRECTION OUTPUT ;
    USE SIGNAL ;
    PORT
      LAYER M4 ;
        RECT  0 19.2 0.192 19.224 ;
    END
  END b[387]
  PIN b[388]
    DIRECTION OUTPUT ;
    USE SIGNAL ;
    PORT
      LAYER M4 ;
        RECT  0 19.248 0.192 19.272 ;
    END
  END b[388]
  PIN b[389]
    DIRECTION OUTPUT ;
    USE SIGNAL ;
    PORT
      LAYER M4 ;
        RECT  0 19.296 0.192 19.32 ;
    END
  END b[389]
  PIN b[38]
    DIRECTION OUTPUT ;
    USE SIGNAL ;
    PORT
      LAYER M4 ;
        RECT  0 2.448 0.192 2.472 ;
    END
  END b[38]
  PIN b[390]
    DIRECTION OUTPUT ;
    USE SIGNAL ;
    PORT
      LAYER M4 ;
        RECT  0 19.344 0.192 19.368 ;
    END
  END b[390]
  PIN b[391]
    DIRECTION OUTPUT ;
    USE SIGNAL ;
    PORT
      LAYER M4 ;
        RECT  0 19.392 0.192 19.416 ;
    END
  END b[391]
  PIN b[392]
    DIRECTION OUTPUT ;
    USE SIGNAL ;
    PORT
      LAYER M4 ;
        RECT  0 19.44 0.192 19.464 ;
    END
  END b[392]
  PIN b[393]
    DIRECTION OUTPUT ;
    USE SIGNAL ;
    PORT
      LAYER M4 ;
        RECT  0 19.488 0.192 19.512 ;
    END
  END b[393]
  PIN b[394]
    DIRECTION OUTPUT ;
    USE SIGNAL ;
    PORT
      LAYER M4 ;
        RECT  0 19.536 0.192 19.56 ;
    END
  END b[394]
  PIN b[395]
    DIRECTION OUTPUT ;
    USE SIGNAL ;
    PORT
      LAYER M4 ;
        RECT  0 19.584 0.192 19.608 ;
    END
  END b[395]
  PIN b[396]
    DIRECTION OUTPUT ;
    USE SIGNAL ;
    PORT
      LAYER M4 ;
        RECT  0 19.632 0.192 19.656 ;
    END
  END b[396]
  PIN b[397]
    DIRECTION OUTPUT ;
    USE SIGNAL ;
    PORT
      LAYER M4 ;
        RECT  0 19.68 0.192 19.704 ;
    END
  END b[397]
  PIN b[398]
    DIRECTION OUTPUT ;
    USE SIGNAL ;
    PORT
      LAYER M4 ;
        RECT  0 19.728 0.192 19.752 ;
    END
  END b[398]
  PIN b[399]
    DIRECTION OUTPUT ;
    USE SIGNAL ;
    PORT
      LAYER M4 ;
        RECT  0 19.776 0.192 19.8 ;
    END
  END b[399]
  PIN b[39]
    DIRECTION OUTPUT ;
    USE SIGNAL ;
    PORT
      LAYER M4 ;
        RECT  0 2.496 0.192 2.52 ;
    END
  END b[39]
  PIN b[3]
    DIRECTION OUTPUT ;
    USE SIGNAL ;
    PORT
      LAYER M4 ;
        RECT  0 0.768 0.192 0.792 ;
    END
  END b[3]
  PIN b[400]
    DIRECTION OUTPUT ;
    USE SIGNAL ;
    PORT
      LAYER M4 ;
        RECT  0 19.824 0.192 19.848 ;
    END
  END b[400]
  PIN b[401]
    DIRECTION OUTPUT ;
    USE SIGNAL ;
    PORT
      LAYER M4 ;
        RECT  0 19.872 0.192 19.896 ;
    END
  END b[401]
  PIN b[402]
    DIRECTION OUTPUT ;
    USE SIGNAL ;
    PORT
      LAYER M4 ;
        RECT  0 19.92 0.192 19.944 ;
    END
  END b[402]
  PIN b[403]
    DIRECTION OUTPUT ;
    USE SIGNAL ;
    PORT
      LAYER M4 ;
        RECT  0 19.968 0.192 19.992 ;
    END
  END b[403]
  PIN b[404]
    DIRECTION OUTPUT ;
    USE SIGNAL ;
    PORT
      LAYER M4 ;
        RECT  0 20.016 0.192 20.04 ;
    END
  END b[404]
  PIN b[405]
    DIRECTION OUTPUT ;
    USE SIGNAL ;
    PORT
      LAYER M4 ;
        RECT  0 20.064 0.192 20.088 ;
    END
  END b[405]
  PIN b[406]
    DIRECTION OUTPUT ;
    USE SIGNAL ;
    PORT
      LAYER M4 ;
        RECT  0 20.112 0.192 20.136 ;
    END
  END b[406]
  PIN b[407]
    DIRECTION OUTPUT ;
    USE SIGNAL ;
    PORT
      LAYER M4 ;
        RECT  0 20.16 0.192 20.184 ;
    END
  END b[407]
  PIN b[408]
    DIRECTION OUTPUT ;
    USE SIGNAL ;
    PORT
      LAYER M4 ;
        RECT  0 20.208 0.192 20.232 ;
    END
  END b[408]
  PIN b[409]
    DIRECTION OUTPUT ;
    USE SIGNAL ;
    PORT
      LAYER M4 ;
        RECT  0 20.256 0.192 20.28 ;
    END
  END b[409]
  PIN b[40]
    DIRECTION OUTPUT ;
    USE SIGNAL ;
    PORT
      LAYER M4 ;
        RECT  0 2.544 0.192 2.568 ;
    END
  END b[40]
  PIN b[410]
    DIRECTION OUTPUT ;
    USE SIGNAL ;
    PORT
      LAYER M4 ;
        RECT  0 20.304 0.192 20.328 ;
    END
  END b[410]
  PIN b[411]
    DIRECTION OUTPUT ;
    USE SIGNAL ;
    PORT
      LAYER M4 ;
        RECT  0 20.352 0.192 20.376 ;
    END
  END b[411]
  PIN b[412]
    DIRECTION OUTPUT ;
    USE SIGNAL ;
    PORT
      LAYER M4 ;
        RECT  0 20.4 0.192 20.424 ;
    END
  END b[412]
  PIN b[413]
    DIRECTION OUTPUT ;
    USE SIGNAL ;
    PORT
      LAYER M4 ;
        RECT  0 20.448 0.192 20.472 ;
    END
  END b[413]
  PIN b[414]
    DIRECTION OUTPUT ;
    USE SIGNAL ;
    PORT
      LAYER M4 ;
        RECT  0 20.496 0.192 20.52 ;
    END
  END b[414]
  PIN b[415]
    DIRECTION OUTPUT ;
    USE SIGNAL ;
    PORT
      LAYER M4 ;
        RECT  0 20.544 0.192 20.568 ;
    END
  END b[415]
  PIN b[416]
    DIRECTION OUTPUT ;
    USE SIGNAL ;
    PORT
      LAYER M4 ;
        RECT  0 20.592 0.192 20.616 ;
    END
  END b[416]
  PIN b[417]
    DIRECTION OUTPUT ;
    USE SIGNAL ;
    PORT
      LAYER M4 ;
        RECT  0 20.64 0.192 20.664 ;
    END
  END b[417]
  PIN b[418]
    DIRECTION OUTPUT ;
    USE SIGNAL ;
    PORT
      LAYER M4 ;
        RECT  0 20.688 0.192 20.712 ;
    END
  END b[418]
  PIN b[419]
    DIRECTION OUTPUT ;
    USE SIGNAL ;
    PORT
      LAYER M4 ;
        RECT  0 20.736 0.192 20.76 ;
    END
  END b[419]
  PIN b[41]
    DIRECTION OUTPUT ;
    USE SIGNAL ;
    PORT
      LAYER M4 ;
        RECT  0 2.592 0.192 2.616 ;
    END
  END b[41]
  PIN b[420]
    DIRECTION OUTPUT ;
    USE SIGNAL ;
    PORT
      LAYER M4 ;
        RECT  0 20.784 0.192 20.808 ;
    END
  END b[420]
  PIN b[421]
    DIRECTION OUTPUT ;
    USE SIGNAL ;
    PORT
      LAYER M4 ;
        RECT  0 20.832 0.192 20.856 ;
    END
  END b[421]
  PIN b[422]
    DIRECTION OUTPUT ;
    USE SIGNAL ;
    PORT
      LAYER M4 ;
        RECT  0 20.88 0.192 20.904 ;
    END
  END b[422]
  PIN b[423]
    DIRECTION OUTPUT ;
    USE SIGNAL ;
    PORT
      LAYER M4 ;
        RECT  0 20.928 0.192 20.952 ;
    END
  END b[423]
  PIN b[424]
    DIRECTION OUTPUT ;
    USE SIGNAL ;
    PORT
      LAYER M4 ;
        RECT  0 20.976 0.192 21 ;
    END
  END b[424]
  PIN b[425]
    DIRECTION OUTPUT ;
    USE SIGNAL ;
    PORT
      LAYER M4 ;
        RECT  0 21.024 0.192 21.048 ;
    END
  END b[425]
  PIN b[426]
    DIRECTION OUTPUT ;
    USE SIGNAL ;
    PORT
      LAYER M4 ;
        RECT  0 21.072 0.192 21.096 ;
    END
  END b[426]
  PIN b[427]
    DIRECTION OUTPUT ;
    USE SIGNAL ;
    PORT
      LAYER M4 ;
        RECT  0 21.12 0.192 21.144 ;
    END
  END b[427]
  PIN b[428]
    DIRECTION OUTPUT ;
    USE SIGNAL ;
    PORT
      LAYER M4 ;
        RECT  0 21.168 0.192 21.192 ;
    END
  END b[428]
  PIN b[429]
    DIRECTION OUTPUT ;
    USE SIGNAL ;
    PORT
      LAYER M4 ;
        RECT  0 21.216 0.192 21.24 ;
    END
  END b[429]
  PIN b[42]
    DIRECTION OUTPUT ;
    USE SIGNAL ;
    PORT
      LAYER M4 ;
        RECT  0 2.64 0.192 2.664 ;
    END
  END b[42]
  PIN b[430]
    DIRECTION OUTPUT ;
    USE SIGNAL ;
    PORT
      LAYER M4 ;
        RECT  0 21.264 0.192 21.288 ;
    END
  END b[430]
  PIN b[431]
    DIRECTION OUTPUT ;
    USE SIGNAL ;
    PORT
      LAYER M4 ;
        RECT  0 21.312 0.192 21.336 ;
    END
  END b[431]
  PIN b[432]
    DIRECTION OUTPUT ;
    USE SIGNAL ;
    PORT
      LAYER M4 ;
        RECT  0 21.36 0.192 21.384 ;
    END
  END b[432]
  PIN b[433]
    DIRECTION OUTPUT ;
    USE SIGNAL ;
    PORT
      LAYER M4 ;
        RECT  0 21.408 0.192 21.432 ;
    END
  END b[433]
  PIN b[434]
    DIRECTION OUTPUT ;
    USE SIGNAL ;
    PORT
      LAYER M4 ;
        RECT  0 21.456 0.192 21.48 ;
    END
  END b[434]
  PIN b[435]
    DIRECTION OUTPUT ;
    USE SIGNAL ;
    PORT
      LAYER M4 ;
        RECT  0 21.504 0.192 21.528 ;
    END
  END b[435]
  PIN b[436]
    DIRECTION OUTPUT ;
    USE SIGNAL ;
    PORT
      LAYER M4 ;
        RECT  0 21.552 0.192 21.576 ;
    END
  END b[436]
  PIN b[437]
    DIRECTION OUTPUT ;
    USE SIGNAL ;
    PORT
      LAYER M4 ;
        RECT  0 21.6 0.192 21.624 ;
    END
  END b[437]
  PIN b[438]
    DIRECTION OUTPUT ;
    USE SIGNAL ;
    PORT
      LAYER M4 ;
        RECT  0 21.648 0.192 21.672 ;
    END
  END b[438]
  PIN b[439]
    DIRECTION OUTPUT ;
    USE SIGNAL ;
    PORT
      LAYER M4 ;
        RECT  0 21.696 0.192 21.72 ;
    END
  END b[439]
  PIN b[43]
    DIRECTION OUTPUT ;
    USE SIGNAL ;
    PORT
      LAYER M4 ;
        RECT  0 2.688 0.192 2.712 ;
    END
  END b[43]
  PIN b[440]
    DIRECTION OUTPUT ;
    USE SIGNAL ;
    PORT
      LAYER M4 ;
        RECT  0 21.744 0.192 21.768 ;
    END
  END b[440]
  PIN b[441]
    DIRECTION OUTPUT ;
    USE SIGNAL ;
    PORT
      LAYER M4 ;
        RECT  0 21.792 0.192 21.816 ;
    END
  END b[441]
  PIN b[442]
    DIRECTION OUTPUT ;
    USE SIGNAL ;
    PORT
      LAYER M4 ;
        RECT  0 21.84 0.192 21.864 ;
    END
  END b[442]
  PIN b[443]
    DIRECTION OUTPUT ;
    USE SIGNAL ;
    PORT
      LAYER M4 ;
        RECT  0 21.888 0.192 21.912 ;
    END
  END b[443]
  PIN b[444]
    DIRECTION OUTPUT ;
    USE SIGNAL ;
    PORT
      LAYER M4 ;
        RECT  0 21.936 0.192 21.96 ;
    END
  END b[444]
  PIN b[445]
    DIRECTION OUTPUT ;
    USE SIGNAL ;
    PORT
      LAYER M4 ;
        RECT  0 21.984 0.192 22.008 ;
    END
  END b[445]
  PIN b[446]
    DIRECTION OUTPUT ;
    USE SIGNAL ;
    PORT
      LAYER M4 ;
        RECT  0 22.032 0.192 22.056 ;
    END
  END b[446]
  PIN b[447]
    DIRECTION OUTPUT ;
    USE SIGNAL ;
    PORT
      LAYER M4 ;
        RECT  0 22.08 0.192 22.104 ;
    END
  END b[447]
  PIN b[448]
    DIRECTION OUTPUT ;
    USE SIGNAL ;
    PORT
      LAYER M4 ;
        RECT  0 22.128 0.192 22.152 ;
    END
  END b[448]
  PIN b[449]
    DIRECTION OUTPUT ;
    USE SIGNAL ;
    PORT
      LAYER M4 ;
        RECT  0 22.176 0.192 22.2 ;
    END
  END b[449]
  PIN b[44]
    DIRECTION OUTPUT ;
    USE SIGNAL ;
    PORT
      LAYER M4 ;
        RECT  0 2.736 0.192 2.76 ;
    END
  END b[44]
  PIN b[450]
    DIRECTION OUTPUT ;
    USE SIGNAL ;
    PORT
      LAYER M4 ;
        RECT  0 22.224 0.192 22.248 ;
    END
  END b[450]
  PIN b[451]
    DIRECTION OUTPUT ;
    USE SIGNAL ;
    PORT
      LAYER M4 ;
        RECT  0 22.272 0.192 22.296 ;
    END
  END b[451]
  PIN b[452]
    DIRECTION OUTPUT ;
    USE SIGNAL ;
    PORT
      LAYER M4 ;
        RECT  0 22.32 0.192 22.344 ;
    END
  END b[452]
  PIN b[453]
    DIRECTION OUTPUT ;
    USE SIGNAL ;
    PORT
      LAYER M4 ;
        RECT  0 22.368 0.192 22.392 ;
    END
  END b[453]
  PIN b[454]
    DIRECTION OUTPUT ;
    USE SIGNAL ;
    PORT
      LAYER M4 ;
        RECT  0 22.416 0.192 22.44 ;
    END
  END b[454]
  PIN b[455]
    DIRECTION OUTPUT ;
    USE SIGNAL ;
    PORT
      LAYER M4 ;
        RECT  0 22.464 0.192 22.488 ;
    END
  END b[455]
  PIN b[456]
    DIRECTION OUTPUT ;
    USE SIGNAL ;
    PORT
      LAYER M4 ;
        RECT  0 22.512 0.192 22.536 ;
    END
  END b[456]
  PIN b[457]
    DIRECTION OUTPUT ;
    USE SIGNAL ;
    PORT
      LAYER M4 ;
        RECT  0 22.56 0.192 22.584 ;
    END
  END b[457]
  PIN b[458]
    DIRECTION OUTPUT ;
    USE SIGNAL ;
    PORT
      LAYER M4 ;
        RECT  0 22.608 0.192 22.632 ;
    END
  END b[458]
  PIN b[459]
    DIRECTION OUTPUT ;
    USE SIGNAL ;
    PORT
      LAYER M4 ;
        RECT  0 22.656 0.192 22.68 ;
    END
  END b[459]
  PIN b[45]
    DIRECTION OUTPUT ;
    USE SIGNAL ;
    PORT
      LAYER M4 ;
        RECT  0 2.784 0.192 2.808 ;
    END
  END b[45]
  PIN b[460]
    DIRECTION OUTPUT ;
    USE SIGNAL ;
    PORT
      LAYER M4 ;
        RECT  0 22.704 0.192 22.728 ;
    END
  END b[460]
  PIN b[461]
    DIRECTION OUTPUT ;
    USE SIGNAL ;
    PORT
      LAYER M4 ;
        RECT  0 22.752 0.192 22.776 ;
    END
  END b[461]
  PIN b[462]
    DIRECTION OUTPUT ;
    USE SIGNAL ;
    PORT
      LAYER M4 ;
        RECT  0 22.8 0.192 22.824 ;
    END
  END b[462]
  PIN b[463]
    DIRECTION OUTPUT ;
    USE SIGNAL ;
    PORT
      LAYER M4 ;
        RECT  0 22.848 0.192 22.872 ;
    END
  END b[463]
  PIN b[464]
    DIRECTION OUTPUT ;
    USE SIGNAL ;
    PORT
      LAYER M4 ;
        RECT  0 22.896 0.192 22.92 ;
    END
  END b[464]
  PIN b[465]
    DIRECTION OUTPUT ;
    USE SIGNAL ;
    PORT
      LAYER M4 ;
        RECT  0 22.944 0.192 22.968 ;
    END
  END b[465]
  PIN b[466]
    DIRECTION OUTPUT ;
    USE SIGNAL ;
    PORT
      LAYER M4 ;
        RECT  0 22.992 0.192 23.016 ;
    END
  END b[466]
  PIN b[467]
    DIRECTION OUTPUT ;
    USE SIGNAL ;
    PORT
      LAYER M4 ;
        RECT  0 23.04 0.192 23.064 ;
    END
  END b[467]
  PIN b[468]
    DIRECTION OUTPUT ;
    USE SIGNAL ;
    PORT
      LAYER M4 ;
        RECT  0 23.088 0.192 23.112 ;
    END
  END b[468]
  PIN b[469]
    DIRECTION OUTPUT ;
    USE SIGNAL ;
    PORT
      LAYER M4 ;
        RECT  0 23.136 0.192 23.16 ;
    END
  END b[469]
  PIN b[46]
    DIRECTION OUTPUT ;
    USE SIGNAL ;
    PORT
      LAYER M4 ;
        RECT  0 2.832 0.192 2.856 ;
    END
  END b[46]
  PIN b[470]
    DIRECTION OUTPUT ;
    USE SIGNAL ;
    PORT
      LAYER M4 ;
        RECT  0 23.184 0.192 23.208 ;
    END
  END b[470]
  PIN b[471]
    DIRECTION OUTPUT ;
    USE SIGNAL ;
    PORT
      LAYER M4 ;
        RECT  0 23.232 0.192 23.256 ;
    END
  END b[471]
  PIN b[472]
    DIRECTION OUTPUT ;
    USE SIGNAL ;
    PORT
      LAYER M4 ;
        RECT  0 23.28 0.192 23.304 ;
    END
  END b[472]
  PIN b[473]
    DIRECTION OUTPUT ;
    USE SIGNAL ;
    PORT
      LAYER M4 ;
        RECT  0 23.328 0.192 23.352 ;
    END
  END b[473]
  PIN b[474]
    DIRECTION OUTPUT ;
    USE SIGNAL ;
    PORT
      LAYER M4 ;
        RECT  0 23.376 0.192 23.4 ;
    END
  END b[474]
  PIN b[475]
    DIRECTION OUTPUT ;
    USE SIGNAL ;
    PORT
      LAYER M4 ;
        RECT  0 23.424 0.192 23.448 ;
    END
  END b[475]
  PIN b[476]
    DIRECTION OUTPUT ;
    USE SIGNAL ;
    PORT
      LAYER M4 ;
        RECT  0 23.472 0.192 23.496 ;
    END
  END b[476]
  PIN b[477]
    DIRECTION OUTPUT ;
    USE SIGNAL ;
    PORT
      LAYER M4 ;
        RECT  0 23.52 0.192 23.544 ;
    END
  END b[477]
  PIN b[478]
    DIRECTION OUTPUT ;
    USE SIGNAL ;
    PORT
      LAYER M4 ;
        RECT  0 23.568 0.192 23.592 ;
    END
  END b[478]
  PIN b[479]
    DIRECTION OUTPUT ;
    USE SIGNAL ;
    PORT
      LAYER M4 ;
        RECT  0 23.616 0.192 23.64 ;
    END
  END b[479]
  PIN b[47]
    DIRECTION OUTPUT ;
    USE SIGNAL ;
    PORT
      LAYER M4 ;
        RECT  0 2.88 0.192 2.904 ;
    END
  END b[47]
  PIN b[480]
    DIRECTION OUTPUT ;
    USE SIGNAL ;
    PORT
      LAYER M4 ;
        RECT  0 23.664 0.192 23.688 ;
    END
  END b[480]
  PIN b[481]
    DIRECTION OUTPUT ;
    USE SIGNAL ;
    PORT
      LAYER M4 ;
        RECT  0 23.712 0.192 23.736 ;
    END
  END b[481]
  PIN b[482]
    DIRECTION OUTPUT ;
    USE SIGNAL ;
    PORT
      LAYER M4 ;
        RECT  0 23.76 0.192 23.784 ;
    END
  END b[482]
  PIN b[483]
    DIRECTION OUTPUT ;
    USE SIGNAL ;
    PORT
      LAYER M4 ;
        RECT  0 23.808 0.192 23.832 ;
    END
  END b[483]
  PIN b[484]
    DIRECTION OUTPUT ;
    USE SIGNAL ;
    PORT
      LAYER M4 ;
        RECT  0 23.856 0.192 23.88 ;
    END
  END b[484]
  PIN b[485]
    DIRECTION OUTPUT ;
    USE SIGNAL ;
    PORT
      LAYER M4 ;
        RECT  0 23.904 0.192 23.928 ;
    END
  END b[485]
  PIN b[486]
    DIRECTION OUTPUT ;
    USE SIGNAL ;
    PORT
      LAYER M4 ;
        RECT  0 23.952 0.192 23.976 ;
    END
  END b[486]
  PIN b[487]
    DIRECTION OUTPUT ;
    USE SIGNAL ;
    PORT
      LAYER M4 ;
        RECT  0 24 0.192 24.024 ;
    END
  END b[487]
  PIN b[488]
    DIRECTION OUTPUT ;
    USE SIGNAL ;
    PORT
      LAYER M4 ;
        RECT  0 24.048 0.192 24.072 ;
    END
  END b[488]
  PIN b[489]
    DIRECTION OUTPUT ;
    USE SIGNAL ;
    PORT
      LAYER M4 ;
        RECT  0 24.096 0.192 24.12 ;
    END
  END b[489]
  PIN b[48]
    DIRECTION OUTPUT ;
    USE SIGNAL ;
    PORT
      LAYER M4 ;
        RECT  0 2.928 0.192 2.952 ;
    END
  END b[48]
  PIN b[490]
    DIRECTION OUTPUT ;
    USE SIGNAL ;
    PORT
      LAYER M4 ;
        RECT  0 24.144 0.192 24.168 ;
    END
  END b[490]
  PIN b[491]
    DIRECTION OUTPUT ;
    USE SIGNAL ;
    PORT
      LAYER M4 ;
        RECT  0 24.192 0.192 24.216 ;
    END
  END b[491]
  PIN b[492]
    DIRECTION OUTPUT ;
    USE SIGNAL ;
    PORT
      LAYER M4 ;
        RECT  0 24.24 0.192 24.264 ;
    END
  END b[492]
  PIN b[493]
    DIRECTION OUTPUT ;
    USE SIGNAL ;
    PORT
      LAYER M4 ;
        RECT  0 24.288 0.192 24.312 ;
    END
  END b[493]
  PIN b[494]
    DIRECTION OUTPUT ;
    USE SIGNAL ;
    PORT
      LAYER M4 ;
        RECT  0 24.336 0.192 24.36 ;
    END
  END b[494]
  PIN b[495]
    DIRECTION OUTPUT ;
    USE SIGNAL ;
    PORT
      LAYER M4 ;
        RECT  0 24.384 0.192 24.408 ;
    END
  END b[495]
  PIN b[496]
    DIRECTION OUTPUT ;
    USE SIGNAL ;
    PORT
      LAYER M4 ;
        RECT  0 24.432 0.192 24.456 ;
    END
  END b[496]
  PIN b[497]
    DIRECTION OUTPUT ;
    USE SIGNAL ;
    PORT
      LAYER M4 ;
        RECT  0 24.48 0.192 24.504 ;
    END
  END b[497]
  PIN b[498]
    DIRECTION OUTPUT ;
    USE SIGNAL ;
    PORT
      LAYER M4 ;
        RECT  0 24.528 0.192 24.552 ;
    END
  END b[498]
  PIN b[499]
    DIRECTION OUTPUT ;
    USE SIGNAL ;
    PORT
      LAYER M4 ;
        RECT  0 24.576 0.192 24.6 ;
    END
  END b[499]
  PIN b[49]
    DIRECTION OUTPUT ;
    USE SIGNAL ;
    PORT
      LAYER M4 ;
        RECT  0 2.976 0.192 3 ;
    END
  END b[49]
  PIN b[4]
    DIRECTION OUTPUT ;
    USE SIGNAL ;
    PORT
      LAYER M4 ;
        RECT  0 0.816 0.192 0.84 ;
    END
  END b[4]
  PIN b[500]
    DIRECTION OUTPUT ;
    USE SIGNAL ;
    PORT
      LAYER M4 ;
        RECT  0 24.624 0.192 24.648 ;
    END
  END b[500]
  PIN b[501]
    DIRECTION OUTPUT ;
    USE SIGNAL ;
    PORT
      LAYER M4 ;
        RECT  0 24.672 0.192 24.696 ;
    END
  END b[501]
  PIN b[502]
    DIRECTION OUTPUT ;
    USE SIGNAL ;
    PORT
      LAYER M4 ;
        RECT  0 24.72 0.192 24.744 ;
    END
  END b[502]
  PIN b[503]
    DIRECTION OUTPUT ;
    USE SIGNAL ;
    PORT
      LAYER M4 ;
        RECT  0 24.768 0.192 24.792 ;
    END
  END b[503]
  PIN b[504]
    DIRECTION OUTPUT ;
    USE SIGNAL ;
    PORT
      LAYER M4 ;
        RECT  0 24.816 0.192 24.84 ;
    END
  END b[504]
  PIN b[505]
    DIRECTION OUTPUT ;
    USE SIGNAL ;
    PORT
      LAYER M4 ;
        RECT  0 24.864 0.192 24.888 ;
    END
  END b[505]
  PIN b[506]
    DIRECTION OUTPUT ;
    USE SIGNAL ;
    PORT
      LAYER M4 ;
        RECT  0 24.912 0.192 24.936 ;
    END
  END b[506]
  PIN b[507]
    DIRECTION OUTPUT ;
    USE SIGNAL ;
    PORT
      LAYER M4 ;
        RECT  0 24.96 0.192 24.984 ;
    END
  END b[507]
  PIN b[508]
    DIRECTION OUTPUT ;
    USE SIGNAL ;
    PORT
      LAYER M4 ;
        RECT  0 25.008 0.192 25.032 ;
    END
  END b[508]
  PIN b[509]
    DIRECTION OUTPUT ;
    USE SIGNAL ;
    PORT
      LAYER M4 ;
        RECT  0 25.056 0.192 25.08 ;
    END
  END b[509]
  PIN b[50]
    DIRECTION OUTPUT ;
    USE SIGNAL ;
    PORT
      LAYER M4 ;
        RECT  0 3.024 0.192 3.048 ;
    END
  END b[50]
  PIN b[510]
    DIRECTION OUTPUT ;
    USE SIGNAL ;
    PORT
      LAYER M4 ;
        RECT  0 25.104 0.192 25.128 ;
    END
  END b[510]
  PIN b[511]
    DIRECTION OUTPUT ;
    USE SIGNAL ;
    PORT
      LAYER M4 ;
        RECT  0 25.152 0.192 25.176 ;
    END
  END b[511]
  PIN b[51]
    DIRECTION OUTPUT ;
    USE SIGNAL ;
    PORT
      LAYER M4 ;
        RECT  0 3.072 0.192 3.096 ;
    END
  END b[51]
  PIN b[52]
    DIRECTION OUTPUT ;
    USE SIGNAL ;
    PORT
      LAYER M4 ;
        RECT  0 3.12 0.192 3.144 ;
    END
  END b[52]
  PIN b[53]
    DIRECTION OUTPUT ;
    USE SIGNAL ;
    PORT
      LAYER M4 ;
        RECT  0 3.168 0.192 3.192 ;
    END
  END b[53]
  PIN b[54]
    DIRECTION OUTPUT ;
    USE SIGNAL ;
    PORT
      LAYER M4 ;
        RECT  0 3.216 0.192 3.24 ;
    END
  END b[54]
  PIN b[55]
    DIRECTION OUTPUT ;
    USE SIGNAL ;
    PORT
      LAYER M4 ;
        RECT  0 3.264 0.192 3.288 ;
    END
  END b[55]
  PIN b[56]
    DIRECTION OUTPUT ;
    USE SIGNAL ;
    PORT
      LAYER M4 ;
        RECT  0 3.312 0.192 3.336 ;
    END
  END b[56]
  PIN b[57]
    DIRECTION OUTPUT ;
    USE SIGNAL ;
    PORT
      LAYER M4 ;
        RECT  0 3.36 0.192 3.384 ;
    END
  END b[57]
  PIN b[58]
    DIRECTION OUTPUT ;
    USE SIGNAL ;
    PORT
      LAYER M4 ;
        RECT  0 3.408 0.192 3.432 ;
    END
  END b[58]
  PIN b[59]
    DIRECTION OUTPUT ;
    USE SIGNAL ;
    PORT
      LAYER M4 ;
        RECT  0 3.456 0.192 3.48 ;
    END
  END b[59]
  PIN b[5]
    DIRECTION OUTPUT ;
    USE SIGNAL ;
    PORT
      LAYER M4 ;
        RECT  0 0.864 0.192 0.888 ;
    END
  END b[5]
  PIN b[60]
    DIRECTION OUTPUT ;
    USE SIGNAL ;
    PORT
      LAYER M4 ;
        RECT  0 3.504 0.192 3.528 ;
    END
  END b[60]
  PIN b[61]
    DIRECTION OUTPUT ;
    USE SIGNAL ;
    PORT
      LAYER M4 ;
        RECT  0 3.552 0.192 3.576 ;
    END
  END b[61]
  PIN b[62]
    DIRECTION OUTPUT ;
    USE SIGNAL ;
    PORT
      LAYER M4 ;
        RECT  0 3.6 0.192 3.624 ;
    END
  END b[62]
  PIN b[63]
    DIRECTION OUTPUT ;
    USE SIGNAL ;
    PORT
      LAYER M4 ;
        RECT  0 3.648 0.192 3.672 ;
    END
  END b[63]
  PIN b[64]
    DIRECTION OUTPUT ;
    USE SIGNAL ;
    PORT
      LAYER M4 ;
        RECT  0 3.696 0.192 3.72 ;
    END
  END b[64]
  PIN b[65]
    DIRECTION OUTPUT ;
    USE SIGNAL ;
    PORT
      LAYER M4 ;
        RECT  0 3.744 0.192 3.768 ;
    END
  END b[65]
  PIN b[66]
    DIRECTION OUTPUT ;
    USE SIGNAL ;
    PORT
      LAYER M4 ;
        RECT  0 3.792 0.192 3.816 ;
    END
  END b[66]
  PIN b[67]
    DIRECTION OUTPUT ;
    USE SIGNAL ;
    PORT
      LAYER M4 ;
        RECT  0 3.84 0.192 3.864 ;
    END
  END b[67]
  PIN b[68]
    DIRECTION OUTPUT ;
    USE SIGNAL ;
    PORT
      LAYER M4 ;
        RECT  0 3.888 0.192 3.912 ;
    END
  END b[68]
  PIN b[69]
    DIRECTION OUTPUT ;
    USE SIGNAL ;
    PORT
      LAYER M4 ;
        RECT  0 3.936 0.192 3.96 ;
    END
  END b[69]
  PIN b[6]
    DIRECTION OUTPUT ;
    USE SIGNAL ;
    PORT
      LAYER M4 ;
        RECT  0 0.912 0.192 0.936 ;
    END
  END b[6]
  PIN b[70]
    DIRECTION OUTPUT ;
    USE SIGNAL ;
    PORT
      LAYER M4 ;
        RECT  0 3.984 0.192 4.008 ;
    END
  END b[70]
  PIN b[71]
    DIRECTION OUTPUT ;
    USE SIGNAL ;
    PORT
      LAYER M4 ;
        RECT  0 4.032 0.192 4.056 ;
    END
  END b[71]
  PIN b[72]
    DIRECTION OUTPUT ;
    USE SIGNAL ;
    PORT
      LAYER M4 ;
        RECT  0 4.08 0.192 4.104 ;
    END
  END b[72]
  PIN b[73]
    DIRECTION OUTPUT ;
    USE SIGNAL ;
    PORT
      LAYER M4 ;
        RECT  0 4.128 0.192 4.152 ;
    END
  END b[73]
  PIN b[74]
    DIRECTION OUTPUT ;
    USE SIGNAL ;
    PORT
      LAYER M4 ;
        RECT  0 4.176 0.192 4.2 ;
    END
  END b[74]
  PIN b[75]
    DIRECTION OUTPUT ;
    USE SIGNAL ;
    PORT
      LAYER M4 ;
        RECT  0 4.224 0.192 4.248 ;
    END
  END b[75]
  PIN b[76]
    DIRECTION OUTPUT ;
    USE SIGNAL ;
    PORT
      LAYER M4 ;
        RECT  0 4.272 0.192 4.296 ;
    END
  END b[76]
  PIN b[77]
    DIRECTION OUTPUT ;
    USE SIGNAL ;
    PORT
      LAYER M4 ;
        RECT  0 4.32 0.192 4.344 ;
    END
  END b[77]
  PIN b[78]
    DIRECTION OUTPUT ;
    USE SIGNAL ;
    PORT
      LAYER M4 ;
        RECT  0 4.368 0.192 4.392 ;
    END
  END b[78]
  PIN b[79]
    DIRECTION OUTPUT ;
    USE SIGNAL ;
    PORT
      LAYER M4 ;
        RECT  0 4.416 0.192 4.44 ;
    END
  END b[79]
  PIN b[7]
    DIRECTION OUTPUT ;
    USE SIGNAL ;
    PORT
      LAYER M4 ;
        RECT  0 0.96 0.192 0.984 ;
    END
  END b[7]
  PIN b[80]
    DIRECTION OUTPUT ;
    USE SIGNAL ;
    PORT
      LAYER M4 ;
        RECT  0 4.464 0.192 4.488 ;
    END
  END b[80]
  PIN b[81]
    DIRECTION OUTPUT ;
    USE SIGNAL ;
    PORT
      LAYER M4 ;
        RECT  0 4.512 0.192 4.536 ;
    END
  END b[81]
  PIN b[82]
    DIRECTION OUTPUT ;
    USE SIGNAL ;
    PORT
      LAYER M4 ;
        RECT  0 4.56 0.192 4.584 ;
    END
  END b[82]
  PIN b[83]
    DIRECTION OUTPUT ;
    USE SIGNAL ;
    PORT
      LAYER M4 ;
        RECT  0 4.608 0.192 4.632 ;
    END
  END b[83]
  PIN b[84]
    DIRECTION OUTPUT ;
    USE SIGNAL ;
    PORT
      LAYER M4 ;
        RECT  0 4.656 0.192 4.68 ;
    END
  END b[84]
  PIN b[85]
    DIRECTION OUTPUT ;
    USE SIGNAL ;
    PORT
      LAYER M4 ;
        RECT  0 4.704 0.192 4.728 ;
    END
  END b[85]
  PIN b[86]
    DIRECTION OUTPUT ;
    USE SIGNAL ;
    PORT
      LAYER M4 ;
        RECT  0 4.752 0.192 4.776 ;
    END
  END b[86]
  PIN b[87]
    DIRECTION OUTPUT ;
    USE SIGNAL ;
    PORT
      LAYER M4 ;
        RECT  0 4.8 0.192 4.824 ;
    END
  END b[87]
  PIN b[88]
    DIRECTION OUTPUT ;
    USE SIGNAL ;
    PORT
      LAYER M4 ;
        RECT  0 4.848 0.192 4.872 ;
    END
  END b[88]
  PIN b[89]
    DIRECTION OUTPUT ;
    USE SIGNAL ;
    PORT
      LAYER M4 ;
        RECT  0 4.896 0.192 4.92 ;
    END
  END b[89]
  PIN b[8]
    DIRECTION OUTPUT ;
    USE SIGNAL ;
    PORT
      LAYER M4 ;
        RECT  0 1.008 0.192 1.032 ;
    END
  END b[8]
  PIN b[90]
    DIRECTION OUTPUT ;
    USE SIGNAL ;
    PORT
      LAYER M4 ;
        RECT  0 4.944 0.192 4.968 ;
    END
  END b[90]
  PIN b[91]
    DIRECTION OUTPUT ;
    USE SIGNAL ;
    PORT
      LAYER M4 ;
        RECT  0 4.992 0.192 5.016 ;
    END
  END b[91]
  PIN b[92]
    DIRECTION OUTPUT ;
    USE SIGNAL ;
    PORT
      LAYER M4 ;
        RECT  0 5.04 0.192 5.064 ;
    END
  END b[92]
  PIN b[93]
    DIRECTION OUTPUT ;
    USE SIGNAL ;
    PORT
      LAYER M4 ;
        RECT  0 5.088 0.192 5.112 ;
    END
  END b[93]
  PIN b[94]
    DIRECTION OUTPUT ;
    USE SIGNAL ;
    PORT
      LAYER M4 ;
        RECT  0 5.136 0.192 5.16 ;
    END
  END b[94]
  PIN b[95]
    DIRECTION OUTPUT ;
    USE SIGNAL ;
    PORT
      LAYER M4 ;
        RECT  0 5.184 0.192 5.208 ;
    END
  END b[95]
  PIN b[96]
    DIRECTION OUTPUT ;
    USE SIGNAL ;
    PORT
      LAYER M4 ;
        RECT  0 5.232 0.192 5.256 ;
    END
  END b[96]
  PIN b[97]
    DIRECTION OUTPUT ;
    USE SIGNAL ;
    PORT
      LAYER M4 ;
        RECT  0 5.28 0.192 5.304 ;
    END
  END b[97]
  PIN b[98]
    DIRECTION OUTPUT ;
    USE SIGNAL ;
    PORT
      LAYER M4 ;
        RECT  0 5.328 0.192 5.352 ;
    END
  END b[98]
  PIN b[99]
    DIRECTION OUTPUT ;
    USE SIGNAL ;
    PORT
      LAYER M4 ;
        RECT  0 5.376 0.192 5.4 ;
    END
  END b[99]
  PIN b[9]
    DIRECTION OUTPUT ;
    USE SIGNAL ;
    PORT
      LAYER M4 ;
        RECT  0 1.056 0.192 1.08 ;
    END
  END b[9]
  PIN ck[0]
    DIRECTION INPUT ;
    USE SIGNAL ;
    PORT
      LAYER M4 ;
        RECT  0 40.128 0.192 40.152 ;
    END
  END ck[0]
  PIN rst[0]
    DIRECTION INPUT ;
    USE SIGNAL ;
    PORT
      LAYER M4 ;
        RECT  0 40.368 0.192 40.392 ;
    END
  END rst[0]
  PIN VDD
    DIRECTION INOUT ;
    USE POWER ;
    PORT
      LAYER M7 ;
        RECT  71.056 0.531 71.344 40.239 ;
        RECT  60.256 0.531 60.544 40.239 ;
        RECT  49.456 0.531 49.744 40.239 ;
        RECT  38.656 0.531 38.944 40.239 ;
        RECT  27.856 0.531 28.144 40.239 ;
        RECT  17.056 0.531 17.344 40.239 ;
        RECT  6.256 0.531 6.544 40.239 ;
      LAYER M6 ;
        RECT  0 39.372 0.032 39.66 ;
        RECT  0 33.972 0.032 34.26 ;
        RECT  0 28.572 0.032 28.86 ;
        RECT  0 23.172 0.032 23.46 ;
        RECT  0 17.772 0.032 18.06 ;
        RECT  0 12.372 0.032 12.66 ;
        RECT  0 6.972 0.032 7.26 ;
        RECT  0 1.572 0.032 1.86 ;
      LAYER M2 ;
        RECT  0 40.221 0.018 40.239 ;
        RECT  0 39.681 0.018 39.699 ;
        RECT  0 39.141 0.018 39.159 ;
        RECT  0 38.601 0.018 38.619 ;
        RECT  0 38.061 0.018 38.079 ;
        RECT  0 37.521 0.018 37.539 ;
        RECT  0 36.981 0.018 36.999 ;
        RECT  0 36.441 0.018 36.459 ;
        RECT  0 35.901 0.018 35.919 ;
        RECT  0 35.361 0.018 35.379 ;
        RECT  0 34.821 0.018 34.839 ;
        RECT  0 34.281 0.018 34.299 ;
        RECT  0 33.741 0.018 33.759 ;
        RECT  0 33.201 0.018 33.219 ;
        RECT  0 32.661 0.018 32.679 ;
        RECT  0 32.121 0.018 32.139 ;
        RECT  0 31.581 0.018 31.599 ;
        RECT  0 31.041 0.018 31.059 ;
        RECT  0 30.501 0.018 30.519 ;
        RECT  0 29.961 0.018 29.979 ;
        RECT  0 29.421 0.018 29.439 ;
        RECT  0 28.881 0.018 28.899 ;
        RECT  0 28.341 0.018 28.359 ;
        RECT  0 27.801 0.018 27.819 ;
        RECT  0 27.261 0.018 27.279 ;
        RECT  0 26.721 0.018 26.739 ;
        RECT  0 26.181 0.018 26.199 ;
        RECT  0 25.641 0.018 25.659 ;
        RECT  0 25.101 0.018 25.119 ;
        RECT  0 24.561 0.018 24.579 ;
        RECT  0 24.021 0.018 24.039 ;
        RECT  0 23.481 0.018 23.499 ;
        RECT  0 22.941 0.018 22.959 ;
        RECT  0 22.401 0.018 22.419 ;
        RECT  0 21.861 0.018 21.879 ;
        RECT  0 21.321 0.018 21.339 ;
        RECT  0 20.781 0.018 20.799 ;
        RECT  0 20.241 0.018 20.259 ;
        RECT  0 19.701 0.018 19.719 ;
        RECT  0 19.161 0.018 19.179 ;
        RECT  0 18.621 0.018 18.639 ;
        RECT  0 18.081 0.018 18.099 ;
        RECT  0 17.541 0.018 17.559 ;
        RECT  0 17.001 0.018 17.019 ;
        RECT  0 16.461 0.018 16.479 ;
        RECT  0 15.921 0.018 15.939 ;
        RECT  0 15.381 0.018 15.399 ;
        RECT  0 14.841 0.018 14.859 ;
        RECT  0 14.301 0.018 14.319 ;
        RECT  0 13.761 0.018 13.779 ;
        RECT  0 13.221 0.018 13.239 ;
        RECT  0 12.681 0.018 12.699 ;
        RECT  0 12.141 0.018 12.159 ;
        RECT  0 11.601 0.018 11.619 ;
        RECT  0 11.061 0.018 11.079 ;
        RECT  0 10.521 0.018 10.539 ;
        RECT  0 9.981 0.018 9.999 ;
        RECT  0 9.441 0.018 9.459 ;
        RECT  0 8.901 0.018 8.919 ;
        RECT  0 8.361 0.018 8.379 ;
        RECT  0 7.821 0.018 7.839 ;
        RECT  0 7.281 0.018 7.299 ;
        RECT  0 6.741 0.018 6.759 ;
        RECT  0 6.201 0.018 6.219 ;
        RECT  0 5.661 0.018 5.679 ;
        RECT  0 5.121 0.018 5.139 ;
        RECT  0 4.581 0.018 4.599 ;
        RECT  0 4.041 0.018 4.059 ;
        RECT  0 3.501 0.018 3.519 ;
        RECT  0 2.961 0.018 2.979 ;
        RECT  0 2.421 0.018 2.439 ;
        RECT  0 1.881 0.018 1.899 ;
        RECT  0 1.341 0.018 1.359 ;
        RECT  0 0.801 0.018 0.819 ;
      LAYER M1 ;
        RECT  0 40.221 0.018 40.239 ;
        RECT  0 39.681 0.018 39.699 ;
        RECT  0 39.141 0.018 39.159 ;
        RECT  0 38.601 0.018 38.619 ;
        RECT  0 38.061 0.018 38.079 ;
        RECT  0 37.521 0.018 37.539 ;
        RECT  0 36.981 0.018 36.999 ;
        RECT  0 36.441 0.018 36.459 ;
        RECT  0 35.901 0.018 35.919 ;
        RECT  0 35.361 0.018 35.379 ;
        RECT  0 34.821 0.018 34.839 ;
        RECT  0 34.281 0.018 34.299 ;
        RECT  0 33.741 0.018 33.759 ;
        RECT  0 33.201 0.018 33.219 ;
        RECT  0 32.661 0.018 32.679 ;
        RECT  0 32.121 0.018 32.139 ;
        RECT  0 31.581 0.018 31.599 ;
        RECT  0 31.041 0.018 31.059 ;
        RECT  0 30.501 0.018 30.519 ;
        RECT  0 29.961 0.018 29.979 ;
        RECT  0 29.421 0.018 29.439 ;
        RECT  0 28.881 0.018 28.899 ;
        RECT  0 28.341 0.018 28.359 ;
        RECT  0 27.801 0.018 27.819 ;
        RECT  0 27.261 0.018 27.279 ;
        RECT  0 26.721 0.018 26.739 ;
        RECT  0 26.181 0.018 26.199 ;
        RECT  0 25.641 0.018 25.659 ;
        RECT  0 25.101 0.018 25.119 ;
        RECT  0 24.561 0.018 24.579 ;
        RECT  0 24.021 0.018 24.039 ;
        RECT  0 23.481 0.018 23.499 ;
        RECT  0 22.941 0.018 22.959 ;
        RECT  0 22.401 0.018 22.419 ;
        RECT  0 21.861 0.018 21.879 ;
        RECT  0 21.321 0.018 21.339 ;
        RECT  0 20.781 0.018 20.799 ;
        RECT  0 20.241 0.018 20.259 ;
        RECT  0 19.701 0.018 19.719 ;
        RECT  0 19.161 0.018 19.179 ;
        RECT  0 18.621 0.018 18.639 ;
        RECT  0 18.081 0.018 18.099 ;
        RECT  0 17.541 0.018 17.559 ;
        RECT  0 17.001 0.018 17.019 ;
        RECT  0 16.461 0.018 16.479 ;
        RECT  0 15.921 0.018 15.939 ;
        RECT  0 15.381 0.018 15.399 ;
        RECT  0 14.841 0.018 14.859 ;
        RECT  0 14.301 0.018 14.319 ;
        RECT  0 13.761 0.018 13.779 ;
        RECT  0 13.221 0.018 13.239 ;
        RECT  0 12.681 0.018 12.699 ;
        RECT  0 12.141 0.018 12.159 ;
        RECT  0 11.601 0.018 11.619 ;
        RECT  0 11.061 0.018 11.079 ;
        RECT  0 10.521 0.018 10.539 ;
        RECT  0 9.981 0.018 9.999 ;
        RECT  0 9.441 0.018 9.459 ;
        RECT  0 8.901 0.018 8.919 ;
        RECT  0 8.361 0.018 8.379 ;
        RECT  0 7.821 0.018 7.839 ;
        RECT  0 7.281 0.018 7.299 ;
        RECT  0 6.741 0.018 6.759 ;
        RECT  0 6.201 0.018 6.219 ;
        RECT  0 5.661 0.018 5.679 ;
        RECT  0 5.121 0.018 5.139 ;
        RECT  0 4.581 0.018 4.599 ;
        RECT  0 4.041 0.018 4.059 ;
        RECT  0 3.501 0.018 3.519 ;
        RECT  0 2.961 0.018 2.979 ;
        RECT  0 2.421 0.018 2.439 ;
        RECT  0 1.881 0.018 1.899 ;
        RECT  0 1.341 0.018 1.359 ;
        RECT  0 0.801 0.018 0.819 ;
    END
  END VDD
  PIN VSS
    DIRECTION INOUT ;
    USE GROUND ;
    PORT
      LAYER M7 ;
        RECT  65.656 0.531 65.944 40.239 ;
        RECT  54.856 0.531 55.144 40.239 ;
        RECT  44.056 0.531 44.344 40.239 ;
        RECT  33.256 0.531 33.544 40.239 ;
        RECT  22.456 0.531 22.744 40.239 ;
        RECT  11.656 0.531 11.944 40.239 ;
        RECT  0.856 0.531 1.144 40.239 ;
      LAYER M6 ;
        RECT  0 38.796 0.032 39.084 ;
        RECT  0 33.396 0.032 33.684 ;
        RECT  0 27.996 0.032 28.284 ;
        RECT  0 22.596 0.032 22.884 ;
        RECT  0 17.196 0.032 17.484 ;
        RECT  0 11.796 0.032 12.084 ;
        RECT  0 6.396 0.032 6.684 ;
        RECT  0 0.996 0.032 1.284 ;
      LAYER M2 ;
        RECT  0 39.951 0.018 39.969 ;
        RECT  0 39.411 0.018 39.429 ;
        RECT  0 38.871 0.018 38.889 ;
        RECT  0 38.331 0.018 38.349 ;
        RECT  0 37.791 0.018 37.809 ;
        RECT  0 37.251 0.018 37.269 ;
        RECT  0 36.711 0.018 36.729 ;
        RECT  0 36.171 0.018 36.189 ;
        RECT  0 35.631 0.018 35.649 ;
        RECT  0 35.091 0.018 35.109 ;
        RECT  0 34.551 0.018 34.569 ;
        RECT  0 34.011 0.018 34.029 ;
        RECT  0 33.471 0.018 33.489 ;
        RECT  0 32.931 0.018 32.949 ;
        RECT  0 32.391 0.018 32.409 ;
        RECT  0 31.851 0.018 31.869 ;
        RECT  0 31.311 0.018 31.329 ;
        RECT  0 30.771 0.018 30.789 ;
        RECT  0 30.231 0.018 30.249 ;
        RECT  0 29.691 0.018 29.709 ;
        RECT  0 29.151 0.018 29.169 ;
        RECT  0 28.611 0.018 28.629 ;
        RECT  0 28.071 0.018 28.089 ;
        RECT  0 27.531 0.018 27.549 ;
        RECT  0 26.991 0.018 27.009 ;
        RECT  0 26.451 0.018 26.469 ;
        RECT  0 25.911 0.018 25.929 ;
        RECT  0 25.371 0.018 25.389 ;
        RECT  0 24.831 0.018 24.849 ;
        RECT  0 24.291 0.018 24.309 ;
        RECT  0 23.751 0.018 23.769 ;
        RECT  0 23.211 0.018 23.229 ;
        RECT  0 22.671 0.018 22.689 ;
        RECT  0 22.131 0.018 22.149 ;
        RECT  0 21.591 0.018 21.609 ;
        RECT  0 21.051 0.018 21.069 ;
        RECT  0 20.511 0.018 20.529 ;
        RECT  0 19.971 0.018 19.989 ;
        RECT  0 19.431 0.018 19.449 ;
        RECT  0 18.891 0.018 18.909 ;
        RECT  0 18.351 0.018 18.369 ;
        RECT  0 17.811 0.018 17.829 ;
        RECT  0 17.271 0.018 17.289 ;
        RECT  0 16.731 0.018 16.749 ;
        RECT  0 16.191 0.018 16.209 ;
        RECT  0 15.651 0.018 15.669 ;
        RECT  0 15.111 0.018 15.129 ;
        RECT  0 14.571 0.018 14.589 ;
        RECT  0 14.031 0.018 14.049 ;
        RECT  0 13.491 0.018 13.509 ;
        RECT  0 12.951 0.018 12.969 ;
        RECT  0 12.411 0.018 12.429 ;
        RECT  0 11.871 0.018 11.889 ;
        RECT  0 11.331 0.018 11.349 ;
        RECT  0 10.791 0.018 10.809 ;
        RECT  0 10.251 0.018 10.269 ;
        RECT  0 9.711 0.018 9.729 ;
        RECT  0 9.171 0.018 9.189 ;
        RECT  0 8.631 0.018 8.649 ;
        RECT  0 8.091 0.018 8.109 ;
        RECT  0 7.551 0.018 7.569 ;
        RECT  0 7.011 0.018 7.029 ;
        RECT  0 6.471 0.018 6.489 ;
        RECT  0 5.931 0.018 5.949 ;
        RECT  0 5.391 0.018 5.409 ;
        RECT  0 4.851 0.018 4.869 ;
        RECT  0 4.311 0.018 4.329 ;
        RECT  0 3.771 0.018 3.789 ;
        RECT  0 3.231 0.018 3.249 ;
        RECT  0 2.691 0.018 2.709 ;
        RECT  0 2.151 0.018 2.169 ;
        RECT  0 1.611 0.018 1.629 ;
        RECT  0 1.071 0.018 1.089 ;
        RECT  0 0.531 0.018 0.549 ;
      LAYER M1 ;
        RECT  0 39.951 0.018 39.969 ;
        RECT  0 39.411 0.018 39.429 ;
        RECT  0 38.871 0.018 38.889 ;
        RECT  0 38.331 0.018 38.349 ;
        RECT  0 37.791 0.018 37.809 ;
        RECT  0 37.251 0.018 37.269 ;
        RECT  0 36.711 0.018 36.729 ;
        RECT  0 36.171 0.018 36.189 ;
        RECT  0 35.631 0.018 35.649 ;
        RECT  0 35.091 0.018 35.109 ;
        RECT  0 34.551 0.018 34.569 ;
        RECT  0 34.011 0.018 34.029 ;
        RECT  0 33.471 0.018 33.489 ;
        RECT  0 32.931 0.018 32.949 ;
        RECT  0 32.391 0.018 32.409 ;
        RECT  0 31.851 0.018 31.869 ;
        RECT  0 31.311 0.018 31.329 ;
        RECT  0 30.771 0.018 30.789 ;
        RECT  0 30.231 0.018 30.249 ;
        RECT  0 29.691 0.018 29.709 ;
        RECT  0 29.151 0.018 29.169 ;
        RECT  0 28.611 0.018 28.629 ;
        RECT  0 28.071 0.018 28.089 ;
        RECT  0 27.531 0.018 27.549 ;
        RECT  0 26.991 0.018 27.009 ;
        RECT  0 26.451 0.018 26.469 ;
        RECT  0 25.911 0.018 25.929 ;
        RECT  0 25.371 0.018 25.389 ;
        RECT  0 24.831 0.018 24.849 ;
        RECT  0 24.291 0.018 24.309 ;
        RECT  0 23.751 0.018 23.769 ;
        RECT  0 23.211 0.018 23.229 ;
        RECT  0 22.671 0.018 22.689 ;
        RECT  0 22.131 0.018 22.149 ;
        RECT  0 21.591 0.018 21.609 ;
        RECT  0 21.051 0.018 21.069 ;
        RECT  0 20.511 0.018 20.529 ;
        RECT  0 19.971 0.018 19.989 ;
        RECT  0 19.431 0.018 19.449 ;
        RECT  0 18.891 0.018 18.909 ;
        RECT  0 18.351 0.018 18.369 ;
        RECT  0 17.811 0.018 17.829 ;
        RECT  0 17.271 0.018 17.289 ;
        RECT  0 16.731 0.018 16.749 ;
        RECT  0 16.191 0.018 16.209 ;
        RECT  0 15.651 0.018 15.669 ;
        RECT  0 15.111 0.018 15.129 ;
        RECT  0 14.571 0.018 14.589 ;
        RECT  0 14.031 0.018 14.049 ;
        RECT  0 13.491 0.018 13.509 ;
        RECT  0 12.951 0.018 12.969 ;
        RECT  0 12.411 0.018 12.429 ;
        RECT  0 11.871 0.018 11.889 ;
        RECT  0 11.331 0.018 11.349 ;
        RECT  0 10.791 0.018 10.809 ;
        RECT  0 10.251 0.018 10.269 ;
        RECT  0 9.711 0.018 9.729 ;
        RECT  0 9.171 0.018 9.189 ;
        RECT  0 8.631 0.018 8.649 ;
        RECT  0 8.091 0.018 8.109 ;
        RECT  0 7.551 0.018 7.569 ;
        RECT  0 7.011 0.018 7.029 ;
        RECT  0 6.471 0.018 6.489 ;
        RECT  0 5.931 0.018 5.949 ;
        RECT  0 5.391 0.018 5.409 ;
        RECT  0 4.851 0.018 4.869 ;
        RECT  0 4.311 0.018 4.329 ;
        RECT  0 3.771 0.018 3.789 ;
        RECT  0 3.231 0.018 3.249 ;
        RECT  0 2.691 0.018 2.709 ;
        RECT  0 2.151 0.018 2.169 ;
        RECT  0 1.611 0.018 1.629 ;
        RECT  0 1.071 0.018 1.089 ;
        RECT  0 0.531 0.018 0.549 ;
    END
  END VSS
  OBS
    LAYER RVTN ;
     RECT  0 0.54 72.954 0.675 ;
     RECT  0 0.945 72.954 1.215 ;
     RECT  0 1.485 72.954 1.755 ;
     RECT  0 2.025 72.954 2.295 ;
     RECT  0 2.565 72.954 2.835 ;
     RECT  0 3.105 72.954 3.375 ;
     RECT  0 3.645 72.954 3.915 ;
     RECT  0 4.185 72.954 4.455 ;
     RECT  0 4.725 72.954 4.995 ;
     RECT  0 5.265 72.954 5.535 ;
     RECT  0 5.805 72.954 6.075 ;
     RECT  0 6.345 72.954 6.615 ;
     RECT  0 6.885 72.954 7.155 ;
     RECT  0 7.425 72.954 7.695 ;
     RECT  0 7.965 72.954 8.235 ;
     RECT  0 8.505 72.954 8.775 ;
     RECT  0 9.045 72.954 9.315 ;
     RECT  0 9.585 72.954 9.855 ;
     RECT  0 10.125 72.954 10.395 ;
     RECT  0 10.665 72.954 10.935 ;
     RECT  0 11.205 72.954 11.475 ;
     RECT  0 11.745 72.954 12.015 ;
     RECT  0 12.285 72.954 12.555 ;
     RECT  0 12.825 72.954 13.095 ;
     RECT  0 13.365 72.954 13.635 ;
     RECT  0 13.905 72.954 14.175 ;
     RECT  0 14.445 72.954 14.715 ;
     RECT  0 14.985 72.954 15.255 ;
     RECT  0 15.525 72.954 15.795 ;
     RECT  0 16.065 72.954 16.335 ;
     RECT  0 16.605 72.954 16.875 ;
     RECT  0 17.145 72.954 17.415 ;
     RECT  0 17.685 72.954 17.955 ;
     RECT  0 18.225 72.954 18.495 ;
     RECT  0 18.765 72.954 19.035 ;
     RECT  0 19.305 72.954 19.575 ;
     RECT  0 19.845 72.954 20.115 ;
     RECT  0 20.385 72.954 20.655 ;
     RECT  0 20.925 72.954 21.195 ;
     RECT  0 21.465 72.954 21.735 ;
     RECT  0 22.005 72.954 22.275 ;
     RECT  0 22.545 72.954 22.815 ;
     RECT  0 23.085 72.954 23.355 ;
     RECT  0 23.625 72.954 23.895 ;
     RECT  0 24.165 72.954 24.435 ;
     RECT  0 24.705 72.954 24.975 ;
     RECT  0 25.245 72.954 25.515 ;
     RECT  0 25.785 72.954 26.055 ;
     RECT  0 26.325 72.954 26.595 ;
     RECT  0 26.865 72.954 27.135 ;
     RECT  0 27.405 72.954 27.675 ;
     RECT  0 27.945 72.954 28.215 ;
     RECT  0 28.485 72.954 28.755 ;
     RECT  0 29.025 72.954 29.295 ;
     RECT  0 29.565 72.954 29.835 ;
     RECT  0 30.105 72.954 30.375 ;
     RECT  0 30.645 72.954 30.915 ;
     RECT  0 31.185 72.954 31.455 ;
     RECT  0 31.725 72.954 31.995 ;
     RECT  0 32.265 72.954 32.535 ;
     RECT  0 32.805 72.954 33.075 ;
     RECT  0 33.345 72.954 33.615 ;
     RECT  0 33.885 72.954 34.155 ;
     RECT  0 34.425 72.954 34.695 ;
     RECT  0 34.965 72.954 35.235 ;
     RECT  0 35.505 72.954 35.775 ;
     RECT  0 36.045 72.954 36.315 ;
     RECT  0 36.585 72.954 36.855 ;
     RECT  0 37.125 72.954 37.395 ;
     RECT  0 37.665 72.954 37.935 ;
     RECT  0 38.205 72.954 38.475 ;
     RECT  0 38.745 72.954 39.015 ;
     RECT  0 39.285 72.954 39.555 ;
     RECT  0 39.825 72.954 40.095 ;
    LAYER RVTP ;
     RECT  0 0.675 72.954 0.945 ;
     RECT  0 1.215 72.954 1.485 ;
     RECT  0 1.755 72.954 2.025 ;
     RECT  0 2.295 72.954 2.565 ;
     RECT  0 2.835 72.954 3.105 ;
     RECT  0 3.375 72.954 3.645 ;
     RECT  0 3.915 72.954 4.185 ;
     RECT  0 4.455 72.954 4.725 ;
     RECT  0 4.995 72.954 5.265 ;
     RECT  0 5.535 72.954 5.805 ;
     RECT  0 6.075 72.954 6.345 ;
     RECT  0 6.615 72.954 6.885 ;
     RECT  0 7.155 72.954 7.425 ;
     RECT  0 7.695 72.954 7.965 ;
     RECT  0 8.235 72.954 8.505 ;
     RECT  0 8.775 72.954 9.045 ;
     RECT  0 9.315 72.954 9.585 ;
     RECT  0 9.855 72.954 10.125 ;
     RECT  0 10.395 72.954 10.665 ;
     RECT  0 10.935 72.954 11.205 ;
     RECT  0 11.475 72.954 11.745 ;
     RECT  0 12.015 72.954 12.285 ;
     RECT  0 12.555 72.954 12.825 ;
     RECT  0 13.095 72.954 13.365 ;
     RECT  0 13.635 72.954 13.905 ;
     RECT  0 14.175 72.954 14.445 ;
     RECT  0 14.715 72.954 14.985 ;
     RECT  0 15.255 72.954 15.525 ;
     RECT  0 15.795 72.954 16.065 ;
     RECT  0 16.335 72.954 16.605 ;
     RECT  0 16.875 72.954 17.145 ;
     RECT  0 17.415 72.954 17.685 ;
     RECT  0 17.955 72.954 18.225 ;
     RECT  0 18.495 72.954 18.765 ;
     RECT  0 19.035 72.954 19.305 ;
     RECT  0 19.575 72.954 19.845 ;
     RECT  0 20.115 72.954 20.385 ;
     RECT  0 20.655 72.954 20.925 ;
     RECT  0 21.195 72.954 21.465 ;
     RECT  0 21.735 72.954 22.005 ;
     RECT  0 22.275 72.954 22.545 ;
     RECT  0 22.815 72.954 23.085 ;
     RECT  0 23.355 72.954 23.625 ;
     RECT  0 23.895 72.954 24.165 ;
     RECT  0 24.435 72.954 24.705 ;
     RECT  0 24.975 72.954 25.245 ;
     RECT  0 25.515 72.954 25.785 ;
     RECT  0 26.055 72.954 26.325 ;
     RECT  0 26.595 72.954 26.865 ;
     RECT  0 27.135 72.954 27.405 ;
     RECT  0 27.675 72.954 27.945 ;
     RECT  0 28.215 72.954 28.485 ;
     RECT  0 28.755 72.954 29.025 ;
     RECT  0 29.295 72.954 29.565 ;
     RECT  0 29.835 72.954 30.105 ;
     RECT  0 30.375 72.954 30.645 ;
     RECT  0 30.915 72.954 31.185 ;
     RECT  0 31.455 72.954 31.725 ;
     RECT  0 31.995 72.954 32.265 ;
     RECT  0 32.535 72.954 32.805 ;
     RECT  0 33.075 72.954 33.345 ;
     RECT  0 33.615 72.954 33.885 ;
     RECT  0 34.155 72.954 34.425 ;
     RECT  0 34.695 72.954 34.965 ;
     RECT  0 35.235 72.954 35.505 ;
     RECT  0 35.775 72.954 36.045 ;
     RECT  0 36.315 72.954 36.585 ;
     RECT  0 36.855 72.954 37.125 ;
     RECT  0 37.395 72.954 37.665 ;
     RECT  0 37.935 72.954 38.205 ;
     RECT  0 38.475 72.954 38.745 ;
     RECT  0 39.015 72.954 39.285 ;
     RECT  0 39.555 72.954 39.825 ;
     RECT  0 40.095 72.954 40.23 ;
    LAYER M1 ;
     RECT  0 0.531 72.954 40.239 ;
    LAYER M2 ;
     RECT  0 0.531 72.954 40.239 ;
    LAYER M3 ;
     RECT  0.255 0.523 0.345 0.571 ;
     RECT  21.855 0.523 21.945 0.571 ;
     RECT  70.455 0.523 70.545 0.571 ;
     RECT  70.455 0.571 71.298 0.607 ;
     RECT  72.108 0.571 72.126 0.607 ;
     RECT  43.455 0.523 43.545 0.619 ;
     RECT  0.255 0.571 0.594 0.667 ;
     RECT  65.055 0.523 65.145 0.667 ;
     RECT  64.728 0.667 65.145 0.679 ;
     RECT  64.404 0.679 65.145 0.715 ;
     RECT  68.652 0.607 68.67 0.715 ;
     RECT  70.02 0.607 72.63 0.715 ;
     RECT  42.768 0.619 43.545 0.749 ;
     RECT  21.744 0.571 22.05 0.751 ;
     RECT  59.655 0.523 59.745 0.751 ;
     RECT  5.655 0.523 5.745 0.793 ;
     RECT  11.055 0.523 11.145 0.793 ;
     RECT  16.455 0.523 16.545 0.793 ;
     RECT  21.06 0.751 22.05 0.793 ;
     RECT  27.255 0.523 27.345 0.793 ;
     RECT  32.655 0.523 32.745 0.793 ;
     RECT  38.055 0.523 38.145 0.793 ;
     RECT  38.916 0.679 38.934 0.793 ;
     RECT  42.876 0.749 43.545 0.793 ;
     RECT  48.855 0.523 48.945 0.793 ;
     RECT  54.255 0.523 54.345 0.793 ;
     RECT  59.292 0.751 59.745 0.793 ;
     RECT  69.696 0.715 72.63 0.811 ;
     RECT  26.388 0.571 26.406 0.859 ;
     RECT  15.012 0.715 15.03 0.877 ;
     RECT  18.252 0.619 18.27 0.877 ;
     RECT  38.055 0.793 38.934 0.877 ;
     RECT  48.855 0.793 49.137 0.877 ;
     RECT  63.288 0.667 63.306 0.877 ;
     RECT  66.744 0.751 66.762 0.877 ;
     RECT  69.696 0.811 72.666 0.877 ;
     RECT  38.016 0.877 38.934 0.913 ;
     RECT  42.876 0.793 43.737 0.913 ;
     RECT  21.06 0.793 22.137 0.955 ;
     RECT  0.252 0.667 0.594 0.985 ;
     RECT  68.652 0.715 68.706 0.985 ;
     RECT  16.455 0.793 16.737 1.021 ;
     RECT  37.944 0.913 38.934 1.021 ;
     RECT  14.832 0.877 15.03 1.049 ;
     RECT  18.18 0.877 18.27 1.099 ;
     RECT  23.22 1.021 23.238 1.099 ;
     RECT  20.52 0.955 22.137 1.111 ;
     RECT  42.876 0.913 43.83 1.111 ;
     RECT  62.604 0.877 63.306 1.111 ;
     RECT  37.944 1.021 39.618 1.139 ;
     RECT  44.892 0.949 44.91 1.139 ;
     RECT  66.744 0.877 67.446 1.139 ;
     RECT  68.652 0.985 68.778 1.139 ;
     RECT  20.376 1.111 22.137 1.147 ;
     RECT  23.22 1.099 23.274 1.147 ;
     RECT  26.244 0.859 26.406 1.147 ;
     RECT  27.255 0.793 27.537 1.147 ;
     RECT  32.655 0.793 32.937 1.147 ;
     RECT  34.776 0.715 34.794 1.147 ;
     RECT  45.684 1.111 45.702 1.147 ;
     RECT  48.855 0.877 49.626 1.147 ;
     RECT  54.255 0.793 54.537 1.147 ;
     RECT  55.296 0.751 55.314 1.147 ;
     RECT  59.292 0.793 59.937 1.147 ;
     RECT  44.748 1.147 44.766 1.181 ;
     RECT  68.544 1.147 68.634 1.181 ;
     RECT  45.684 1.147 45.846 1.183 ;
     RECT  50.724 0.619 50.742 1.183 ;
     RECT  54.255 1.147 55.314 1.183 ;
     RECT  58.428 1.147 58.446 1.183 ;
     RECT  2.16 0.913 2.178 1.195 ;
     RECT  18.18 1.099 19.134 1.195 ;
     RECT  20.376 1.147 22.302 1.195 ;
     RECT  58.176 1.183 58.446 1.195 ;
     RECT  59.292 1.147 60.102 1.195 ;
     RECT  2.16 1.195 2.286 1.219 ;
     RECT  18.18 1.195 22.302 1.219 ;
     RECT  24.12 1.147 25.146 1.219 ;
     RECT  28.548 0.667 28.566 1.219 ;
     RECT  50.616 1.183 51.354 1.219 ;
     RECT  5.655 0.793 5.937 1.243 ;
     RECT  16.272 1.021 16.737 1.243 ;
     RECT  23.148 1.147 23.274 1.243 ;
     RECT  24.048 1.219 25.146 1.243 ;
     RECT  11.055 0.793 11.337 1.255 ;
     RECT  23.148 1.243 25.146 1.255 ;
     RECT  31.248 0.907 31.266 1.255 ;
     RECT  54.255 1.183 55.386 1.255 ;
     RECT  68.616 1.181 68.634 1.283 ;
     RECT  16.272 1.243 16.83 1.291 ;
     RECT  26.244 1.147 27.537 1.291 ;
     RECT  28.548 1.219 29.106 1.291 ;
     RECT  48.855 1.147 49.77 1.291 ;
     RECT  58.176 1.195 60.174 1.291 ;
     RECT  34.2 1.147 34.902 1.325 ;
     RECT  30.06 1.147 30.078 1.381 ;
     RECT  30.996 1.255 31.77 1.381 ;
     RECT  34.2 1.325 34.794 1.381 ;
     RECT  46.764 0.619 46.782 1.381 ;
     RECT  58.104 1.291 60.174 1.381 ;
     RECT  0.036 0.985 0.594 1.387 ;
     RECT  26.244 1.291 29.106 1.387 ;
     RECT  30.06 1.381 30.15 1.387 ;
     RECT  40.68 1.147 40.698 1.387 ;
     RECT  30.924 1.381 31.77 1.409 ;
     RECT  37.188 0.841 37.206 1.409 ;
     RECT  48.24 1.291 49.77 1.409 ;
     RECT  57.528 1.381 60.174 1.409 ;
     RECT  64.224 0.715 65.502 1.409 ;
     RECT  45.684 1.183 45.882 1.417 ;
     RECT  46.764 1.381 47.466 1.417 ;
     RECT  48.852 1.409 49.77 1.421 ;
     RECT  13.752 1.339 13.914 1.445 ;
     RECT  40.536 1.387 40.698 1.445 ;
     RECT  50.616 1.219 51.39 1.445 ;
     RECT  18.108 1.219 22.302 1.453 ;
     RECT  23.076 1.255 25.146 1.453 ;
     RECT  66.744 1.139 67.302 1.453 ;
     RECT  42.876 1.111 43.902 1.481 ;
     RECT  16.272 1.291 17.082 1.483 ;
     RECT  69.696 0.877 72.81 1.483 ;
     RECT  11.055 1.255 11.862 1.489 ;
     RECT  14.832 1.049 14.85 1.489 ;
     RECT  61.884 1.111 63.306 1.489 ;
     RECT  38.055 1.139 38.898 1.517 ;
     RECT  2.16 1.219 2.862 1.525 ;
     RECT  16.2 1.483 17.082 1.525 ;
     RECT  18.108 1.453 25.146 1.525 ;
     RECT  57.528 1.409 58.914 1.525 ;
     RECT  66.708 1.453 67.302 1.525 ;
     RECT  57.492 1.525 58.914 1.553 ;
     RECT  18.108 1.525 25.218 1.561 ;
     RECT  26.244 1.387 30.15 1.561 ;
     RECT  30.924 1.409 31.698 1.561 ;
     RECT  32.655 1.147 33.354 1.561 ;
     RECT  41.616 1.021 41.634 1.561 ;
     RECT  42.876 1.481 43.737 1.561 ;
     RECT  56.34 1.525 56.358 1.561 ;
     RECT  69.66 1.483 72.81 1.561 ;
     RECT  54.255 1.255 55.422 1.579 ;
     RECT  56.34 1.561 56.43 1.579 ;
     RECT  18.108 1.561 25.254 1.589 ;
     RECT  38.055 1.517 38.682 1.589 ;
     RECT  16.056 1.525 17.118 1.613 ;
     RECT  34.128 1.381 34.794 1.613 ;
     RECT  2.124 1.525 2.862 1.651 ;
     RECT  12.708 1.525 12.726 1.651 ;
     RECT  5.148 1.243 5.937 1.679 ;
     RECT  10.08 1.561 10.098 1.679 ;
     RECT  10.908 1.489 11.862 1.679 ;
     RECT  26.244 1.561 31.698 1.679 ;
     RECT  41.544 1.561 41.634 1.679 ;
     RECT  48.855 1.421 49.77 1.679 ;
     RECT  52.344 1.525 52.362 1.679 ;
     RECT  53.136 1.255 53.154 1.679 ;
     RECT  18.792 1.589 25.254 1.709 ;
     RECT  16.056 1.613 16.737 1.715 ;
     RECT  18.792 1.709 21.114 1.715 ;
     RECT  21.855 1.709 25.254 1.715 ;
     RECT  45.684 1.417 47.466 1.715 ;
     RECT  50.616 1.445 51.354 1.715 ;
     RECT  54.255 1.579 56.43 1.715 ;
     RECT  2.016 1.651 2.862 1.723 ;
     RECT  6.912 1.561 6.93 1.723 ;
     RECT  35.784 1.183 35.802 1.723 ;
     RECT  26.244 1.679 31.662 1.759 ;
     RECT  12.636 1.651 12.726 1.771 ;
     RECT  10.908 1.679 11.79 1.795 ;
     RECT  12.636 1.771 12.762 1.795 ;
     RECT  59.655 1.409 60.174 1.795 ;
     RECT  60.948 1.489 63.306 1.795 ;
     RECT  64.224 1.409 65.337 1.795 ;
     RECT  32.472 1.561 33.354 1.819 ;
     RECT  34.128 1.613 34.434 1.819 ;
     RECT  26.064 1.759 31.662 1.823 ;
     RECT  1.944 1.723 2.862 1.831 ;
     RECT  3.6 1.561 3.618 1.831 ;
     RECT  6.912 1.723 7.614 1.831 ;
     RECT  66.132 1.525 67.302 1.859 ;
     RECT  42.768 1.561 43.737 1.901 ;
     RECT  5.616 1.679 5.937 1.921 ;
     RECT  6.912 1.831 7.65 1.921 ;
     RECT  21.855 1.715 25.218 1.949 ;
     RECT  32.472 1.819 34.434 1.949 ;
     RECT  40.716 1.723 40.734 1.949 ;
     RECT  57.492 1.553 57.654 1.949 ;
     RECT  59.655 1.795 65.337 1.949 ;
     RECT  14.22 1.489 14.85 1.957 ;
     RECT  9.144 1.723 9.162 1.963 ;
     RECT  45.684 1.715 47.322 1.963 ;
     RECT  69.66 1.561 72.846 1.963 ;
     RECT  54.255 1.715 55.926 1.985 ;
     RECT  57.492 1.949 57.582 1.993 ;
     RECT  1.944 1.831 3.618 1.997 ;
     RECT  21.855 1.949 25.074 1.997 ;
     RECT  66.492 1.859 67.302 2.011 ;
     RECT  17.532 1.795 17.658 2.021 ;
     RECT  32.472 1.949 33.21 2.021 ;
     RECT  53.172 1.759 53.19 2.021 ;
     RECT  45.648 1.963 47.322 2.029 ;
     RECT  41.724 1.921 41.742 2.045 ;
     RECT  1.944 1.997 2.106 2.057 ;
     RECT  17.532 2.021 17.622 2.057 ;
     RECT  59.655 1.949 60.93 2.057 ;
     RECT  35.784 1.723 35.91 2.065 ;
     RECT  18.828 1.715 21.114 2.093 ;
     RECT  21.855 1.997 23.274 2.093 ;
     RECT  26.064 1.823 31.23 2.093 ;
     RECT  68.976 1.963 72.846 2.093 ;
     RECT  1.8 2.065 1.89 2.101 ;
     RECT  2.916 1.997 3.618 2.101 ;
     RECT  37.08 1.417 37.098 2.101 ;
     RECT  45.216 2.029 47.322 2.101 ;
     RECT  26.064 2.093 29.646 2.129 ;
     RECT  12.6 1.795 12.762 2.191 ;
     RECT  54.255 1.985 55.566 2.191 ;
     RECT  66.492 2.011 67.698 2.191 ;
     RECT  10.584 1.795 11.79 2.219 ;
     RECT  12.6 2.191 13.122 2.219 ;
     RECT  24.012 1.997 24.354 2.219 ;
     RECT  26.748 2.129 29.646 2.219 ;
     RECT  34.056 1.949 34.434 2.219 ;
     RECT  61.812 1.949 65.337 2.219 ;
     RECT  9.144 1.963 9.342 2.227 ;
     RECT  35.316 2.065 35.91 2.227 ;
     RECT  57.348 1.993 57.582 2.227 ;
     RECT  20.268 2.093 20.646 2.237 ;
     RECT  21.855 2.093 23.202 2.237 ;
     RECT  32.544 2.021 33.21 2.237 ;
     RECT  52.2 1.687 52.218 2.251 ;
     RECT  16.236 1.715 16.737 2.255 ;
     RECT  56.952 2.227 57.582 2.255 ;
     RECT  61.992 2.219 65.337 2.255 ;
     RECT  9.144 2.227 9.666 2.263 ;
     RECT  14.22 1.957 14.958 2.263 ;
     RECT  16.344 2.255 16.737 2.285 ;
     RECT  1.728 2.101 1.89 2.291 ;
     RECT  10.584 2.219 11.337 2.291 ;
     RECT  12.708 2.219 13.122 2.291 ;
     RECT  14.22 2.263 15.426 2.291 ;
     RECT  17.532 2.057 17.55 2.291 ;
     RECT  26.784 2.219 29.646 2.291 ;
     RECT  52.128 2.251 52.218 2.291 ;
     RECT  60.912 2.057 60.93 2.291 ;
     RECT  48.855 1.679 49.137 2.299 ;
     RECT  50.688 1.715 51.354 2.299 ;
     RECT  58.536 1.553 58.806 2.299 ;
     RECT  2.916 2.101 4.122 2.327 ;
     RECT  5.616 1.921 7.65 2.327 ;
     RECT  30.384 2.093 31.23 2.327 ;
     RECT  5.616 2.327 6.606 2.333 ;
     RECT  54.144 2.191 55.566 2.335 ;
     RECT  58.536 2.299 58.878 2.335 ;
     RECT  66.492 2.191 68.022 2.335 ;
     RECT  68.976 2.093 72.81 2.335 ;
     RECT  10.836 2.291 11.337 2.363 ;
     RECT  14.76 2.291 15.426 2.363 ;
     RECT  20.628 2.237 20.646 2.363 ;
     RECT  23.076 2.237 23.202 2.363 ;
     RECT  66.492 2.335 72.81 2.363 ;
     RECT  0.036 1.387 0.63 2.371 ;
     RECT  7.452 2.327 7.65 2.371 ;
     RECT  38.055 1.589 38.337 2.371 ;
     RECT  48.852 2.299 49.137 2.371 ;
     RECT  35.316 2.227 36.126 2.461 ;
     RECT  37.008 2.101 37.098 2.461 ;
     RECT  44.784 2.101 47.322 2.461 ;
     RECT  7.452 2.371 7.974 2.489 ;
     RECT  9.036 2.263 9.666 2.489 ;
     RECT  13.104 2.291 13.122 2.489 ;
     RECT  15.408 2.363 15.426 2.489 ;
     RECT  50.688 2.299 51.426 2.489 ;
     RECT  66.492 2.363 66.978 2.489 ;
     RECT  35.316 2.461 37.098 2.497 ;
     RECT  38.055 2.371 38.538 2.497 ;
     RECT  58.464 2.335 58.878 2.497 ;
     RECT  62.46 2.255 65.337 2.497 ;
     RECT  34.056 2.219 34.218 2.525 ;
     RECT  50.688 2.489 51.354 2.525 ;
     RECT  44.784 2.461 47.61 2.533 ;
     RECT  58.428 2.497 58.878 2.533 ;
     RECT  59.655 2.057 59.937 2.533 ;
     RECT  13.896 2.371 13.914 2.561 ;
     RECT  56.952 2.255 57.258 2.561 ;
     RECT  44.676 2.533 47.61 2.569 ;
     RECT  48.78 2.371 49.137 2.569 ;
     RECT  62.46 2.497 65.718 2.573 ;
     RECT  63.684 2.573 65.718 2.587 ;
     RECT  66.492 2.489 66.942 2.587 ;
     RECT  28.476 2.291 29.646 2.597 ;
     RECT  54.036 2.335 55.566 2.597 ;
     RECT  58.428 2.533 59.937 2.597 ;
     RECT  35.316 2.497 38.538 2.605 ;
     RECT  44.532 2.569 49.137 2.605 ;
     RECT  58.464 2.597 59.937 2.621 ;
     RECT  62.46 2.573 62.91 2.621 ;
     RECT  63.684 2.587 66.942 2.621 ;
     RECT  9.108 2.489 9.666 2.633 ;
     RECT  67.716 2.363 72.81 2.633 ;
     RECT  21.855 2.237 22.137 2.635 ;
     RECT  42.012 2.635 42.03 2.669 ;
     RECT  56.952 2.561 57.15 2.669 ;
     RECT  58.464 2.621 58.878 2.669 ;
     RECT  67.716 2.633 67.986 2.717 ;
     RECT  54.255 2.597 55.566 2.731 ;
     RECT  25.848 2.569 25.866 2.759 ;
     RECT  32.655 2.237 33.21 2.759 ;
     RECT  35.316 2.605 38.826 2.759 ;
     RECT  44.46 2.605 49.137 2.759 ;
     RECT  67.716 2.717 67.914 2.759 ;
     RECT  30.384 2.327 30.942 2.765 ;
     RECT  54.255 2.731 56.106 2.767 ;
     RECT  56.952 2.669 57.114 2.767 ;
     RECT  2.916 2.327 4.086 2.795 ;
     RECT  34.092 2.525 34.218 2.795 ;
     RECT  35.532 2.759 38.826 2.795 ;
     RECT  62.532 2.621 62.91 2.795 ;
     RECT  2.916 2.795 3.006 2.803 ;
     RECT  42.804 1.901 43.737 2.803 ;
     RECT  44.46 2.759 44.766 2.803 ;
     RECT  28.476 2.597 29.286 2.813 ;
     RECT  54.255 2.767 57.114 2.813 ;
     RECT  34.2 2.795 34.218 2.831 ;
     RECT  35.532 2.795 38.79 2.831 ;
     RECT  58.464 2.669 58.842 2.831 ;
     RECT  63.684 2.621 66.834 2.831 ;
     RECT  64.224 2.831 66.798 2.861 ;
     RECT  67.716 2.759 67.842 2.861 ;
     RECT  64.224 2.861 66.726 2.867 ;
     RECT  67.824 2.861 67.842 2.867 ;
     RECT  30.384 2.765 30.834 2.875 ;
     RECT  68.904 2.633 72.81 2.903 ;
     RECT  42.804 2.803 44.766 2.909 ;
     RECT  23.076 2.363 23.13 2.939 ;
     RECT  36.252 2.831 38.79 2.939 ;
     RECT  16.416 2.285 16.737 2.971 ;
     RECT  17.496 2.371 17.514 2.971 ;
     RECT  18.828 2.093 19.494 3.001 ;
     RECT  30.132 2.875 30.834 3.029 ;
     RECT  36.252 2.939 36.414 3.029 ;
     RECT  45.504 2.759 49.137 3.029 ;
     RECT  54.255 2.813 55.782 3.029 ;
     RECT  56.88 2.813 57.114 3.029 ;
     RECT  69.192 2.903 72.81 3.053 ;
     RECT  28.512 2.813 29.286 3.065 ;
     RECT  36.252 3.029 36.27 3.065 ;
     RECT  56.88 3.029 56.97 3.065 ;
     RECT  53.46 3.001 53.478 3.109 ;
     RECT  29.268 3.065 29.286 3.137 ;
     RECT  34.776 3.001 34.794 3.137 ;
     RECT  20.52 3.067 20.538 3.145 ;
     RECT  21.744 2.635 22.137 3.145 ;
     RECT  24.336 2.219 24.354 3.145 ;
     RECT  28.512 3.065 28.53 3.149 ;
     RECT  4.896 2.911 4.914 3.181 ;
     RECT  5.655 2.333 6.606 3.181 ;
     RECT  26.784 2.291 27.537 3.181 ;
     RECT  53.388 3.109 53.478 3.181 ;
     RECT  66.276 2.867 66.726 3.209 ;
     RECT  5.655 3.181 6.93 3.211 ;
     RECT  7.956 2.489 7.974 3.211 ;
     RECT  0.036 2.371 1.17 3.259 ;
     RECT  52.2 2.291 52.218 3.259 ;
     RECT  23.112 2.939 23.13 3.299 ;
     RECT  24.336 3.145 25.542 3.299 ;
     RECT  64.224 2.867 65.502 3.299 ;
     RECT  66.276 3.209 66.69 3.299 ;
     RECT  37.332 2.939 38.79 3.335 ;
     RECT  66.348 3.299 66.69 3.335 ;
     RECT  0.036 3.259 1.53 3.343 ;
     RECT  2.268 2.803 3.006 3.343 ;
     RECT  3.78 2.795 4.086 3.343 ;
     RECT  4.86 3.181 4.914 3.343 ;
     RECT  5.655 3.211 7.974 3.343 ;
     RECT  9.108 2.633 9.594 3.371 ;
     RECT  24.336 3.299 24.786 3.371 ;
     RECT  58.464 2.831 58.77 3.371 ;
     RECT  3.78 3.343 4.914 3.389 ;
     RECT  5.655 3.343 8.37 3.389 ;
     RECT  45.504 3.029 47.286 3.389 ;
     RECT  11.055 2.363 11.337 3.403 ;
     RECT  52.2 3.259 52.542 3.403 ;
     RECT  53.316 3.181 53.478 3.403 ;
     RECT  11.055 3.403 11.502 3.415 ;
     RECT  14.832 3.181 14.922 3.415 ;
     RECT  18.792 3.001 19.494 3.415 ;
     RECT  46.62 3.389 47.286 3.437 ;
     RECT  52.2 3.403 53.478 3.437 ;
     RECT  64.224 3.299 65.358 3.437 ;
     RECT  14.22 3.415 14.922 3.451 ;
     RECT  24.336 3.371 24.642 3.451 ;
     RECT  42.804 2.909 43.737 3.451 ;
     RECT  24.084 3.451 24.642 3.479 ;
     RECT  0.036 3.343 3.006 3.485 ;
     RECT  48.096 3.029 49.137 3.485 ;
     RECT  4.788 3.389 4.914 3.499 ;
     RECT  5.655 3.389 7.182 3.499 ;
     RECT  13.716 3.451 14.922 3.499 ;
     RECT  2.628 3.485 3.006 3.541 ;
     RECT  9.576 3.371 9.594 3.541 ;
     RECT  10.764 3.415 11.502 3.541 ;
     RECT  16.416 2.971 17.514 3.541 ;
     RECT  18.36 3.415 19.494 3.541 ;
     RECT  24.084 3.479 24.174 3.541 ;
     RECT  50.688 2.525 50.814 3.541 ;
     RECT  52.236 3.437 53.478 3.541 ;
     RECT  54.255 3.029 55.17 3.541 ;
     RECT  62.604 2.795 62.838 3.541 ;
     RECT  4.788 3.499 7.182 3.569 ;
     RECT  9.576 3.541 12.366 3.569 ;
     RECT  13.644 3.499 14.922 3.569 ;
     RECT  42.156 3.451 43.737 3.569 ;
     RECT  46.692 3.437 46.854 3.569 ;
     RECT  9.72 3.569 12.366 3.577 ;
     RECT  24.012 3.541 24.174 3.595 ;
     RECT  25.524 3.299 25.542 3.605 ;
     RECT  30.384 3.029 30.834 3.613 ;
     RECT  31.572 3.451 31.662 3.613 ;
     RECT  40.932 3.451 40.95 3.613 ;
     RECT  59.655 2.621 59.937 3.613 ;
     RECT  7.956 3.389 8.37 3.629 ;
     RECT  9.72 3.577 12.87 3.629 ;
     RECT  23.508 3.595 24.174 3.629 ;
     RECT  8.352 3.629 8.37 3.641 ;
     RECT  52.236 3.541 55.17 3.641 ;
     RECT  13.716 3.569 14.922 3.643 ;
     RECT  38.055 3.335 38.79 3.649 ;
     RECT  10.188 3.629 12.87 3.677 ;
     RECT  40.932 3.613 41.022 3.685 ;
     RECT  48.276 3.485 49.137 3.685 ;
     RECT  50.688 3.541 51.102 3.685 ;
     RECT  26.712 3.181 27.537 3.691 ;
     RECT  4.86 3.569 6.93 3.713 ;
     RECT  42.732 3.569 43.737 3.713 ;
     RECT  20.52 3.145 22.137 3.721 ;
     RECT  26.712 3.691 27.954 3.721 ;
     RECT  58.716 3.371 58.77 3.721 ;
     RECT  62.568 3.541 62.838 3.721 ;
     RECT  41.976 3.649 41.994 3.725 ;
     RECT  50.58 3.685 51.102 3.773 ;
     RECT  13.716 3.643 14.958 3.787 ;
     RECT  15.912 3.541 19.494 3.787 ;
     RECT  61.704 3.739 61.722 3.787 ;
     RECT  30.384 3.613 31.662 3.811 ;
     RECT  32.655 2.759 33.102 3.811 ;
     RECT  62.496 3.721 62.838 3.811 ;
     RECT  4.932 3.713 6.93 3.839 ;
     RECT  12.348 3.677 12.87 3.839 ;
     RECT  13.716 3.787 19.494 3.839 ;
     RECT  48.276 3.685 49.302 3.839 ;
     RECT  50.724 3.773 51.102 3.839 ;
     RECT  61.56 3.787 61.722 3.839 ;
     RECT  66.672 3.335 66.69 3.839 ;
     RECT  67.752 3.721 67.77 3.847 ;
     RECT  20.484 3.721 22.137 3.869 ;
     RECT  62.496 3.811 63.234 3.869 ;
     RECT  0.036 3.485 1.638 3.875 ;
     RECT  48.348 3.839 49.302 3.875 ;
     RECT  52.236 3.641 52.254 3.875 ;
     RECT  67.752 3.847 68.022 3.875 ;
     RECT  56.268 3.541 56.286 3.883 ;
     RECT  12.672 3.839 12.87 3.911 ;
     RECT  13.86 3.839 14.85 3.917 ;
     RECT  23.508 3.629 24.066 3.917 ;
     RECT  56.196 3.883 56.286 3.919 ;
     RECT  12.852 3.911 12.87 3.947 ;
     RECT  13.86 3.917 14.814 3.965 ;
     RECT  64.224 3.437 65.337 3.979 ;
     RECT  29.376 3.811 29.394 3.983 ;
     RECT  52.992 3.641 55.17 3.983 ;
     RECT  30.384 3.811 33.138 3.991 ;
     RECT  34.344 3.847 34.362 3.991 ;
     RECT  35.496 3.811 35.514 3.991 ;
     RECT  40.932 3.685 41.058 3.991 ;
     RECT  45 3.955 45.018 3.991 ;
     RECT  67.86 3.875 68.022 3.991 ;
     RECT  15.768 3.839 19.494 4.075 ;
     RECT  34.344 3.991 35.514 4.075 ;
     RECT  36.36 3.991 36.45 4.075 ;
     RECT  56.124 3.919 56.286 4.075 ;
     RECT  34.344 4.075 36.45 4.081 ;
     RECT  42.768 3.713 43.737 4.081 ;
     RECT  56.124 4.075 56.574 4.081 ;
     RECT  66.708 4.075 66.726 4.081 ;
     RECT  69.732 3.053 72.81 4.081 ;
     RECT  14.256 3.965 14.814 4.109 ;
     RECT  21.024 3.869 22.137 4.109 ;
     RECT  29.664 3.991 33.138 4.109 ;
     RECT  44.856 3.991 45.018 4.117 ;
     RECT  56.124 4.081 56.718 4.117 ;
     RECT  69.588 4.081 72.81 4.117 ;
     RECT  31.86 4.109 33.138 4.123 ;
     RECT  34.344 4.081 36.522 4.123 ;
     RECT  40.788 3.991 41.886 4.123 ;
     RECT  42.768 4.081 43.794 4.123 ;
     RECT  15.768 4.075 19.71 4.145 ;
     RECT  44.784 4.117 45.018 4.145 ;
     RECT  31.86 4.123 36.522 4.153 ;
     RECT  21.096 4.109 22.137 4.171 ;
     RECT  29.664 4.109 30.942 4.181 ;
     RECT  26.604 3.721 27.954 4.189 ;
     RECT  42.768 4.123 43.902 4.189 ;
     RECT  44.784 4.145 44.946 4.189 ;
     RECT  62.496 3.869 62.874 4.189 ;
     RECT  5.616 3.839 6.606 4.217 ;
     RECT  40.572 4.123 41.886 4.217 ;
     RECT  17.676 4.145 19.71 4.219 ;
     RECT  55.908 4.117 56.718 4.225 ;
     RECT  58.716 3.721 58.806 4.225 ;
     RECT  14.652 4.109 14.814 4.253 ;
     RECT  15.768 4.145 16.737 4.253 ;
     RECT  17.676 4.219 19.854 4.253 ;
     RECT  31.86 4.153 37.17 4.253 ;
     RECT  42.768 4.189 44.946 4.253 ;
     RECT  55.908 4.225 57.366 4.253 ;
     RECT  26.604 4.189 28.314 4.261 ;
     RECT  64.044 3.979 65.337 4.261 ;
     RECT  67.86 3.991 68.058 4.261 ;
     RECT  69.048 4.117 72.81 4.261 ;
     RECT  17.676 4.253 19.638 4.289 ;
     RECT  40.68 4.217 40.77 4.301 ;
     RECT  26.136 4.261 28.458 4.315 ;
     RECT  1.62 3.875 1.638 4.351 ;
     RECT  2.628 3.541 3.618 4.351 ;
     RECT  31.932 4.253 37.17 4.351 ;
     RECT  38.055 3.649 38.826 4.351 ;
     RECT  18.36 4.289 19.638 4.379 ;
     RECT  26.136 4.315 28.926 4.379 ;
     RECT  31.932 4.351 37.206 4.379 ;
     RECT  62.352 4.189 62.874 4.379 ;
     RECT  59.655 3.613 60.318 4.387 ;
     RECT  36.036 4.379 37.206 4.397 ;
     RECT  50.724 3.839 50.994 4.397 ;
     RECT  55.908 4.253 56.106 4.397 ;
     RECT  21.096 4.171 22.842 4.415 ;
     RECT  26.712 4.379 28.926 4.415 ;
     RECT  29.664 4.181 30.798 4.415 ;
     RECT  31.932 4.379 35.298 4.415 ;
     RECT  36.036 4.397 37.17 4.415 ;
     RECT  41.688 4.217 41.886 4.415 ;
     RECT  57.348 4.253 57.366 4.415 ;
     RECT  53.964 3.983 55.17 4.423 ;
     RECT  55.908 4.397 55.962 4.423 ;
     RECT  28.296 4.415 28.926 4.445 ;
     RECT  29.664 4.415 29.97 4.445 ;
     RECT  28.296 4.445 28.314 4.451 ;
     RECT  41.688 4.415 41.778 4.451 ;
     RECT  53.964 4.423 55.962 4.451 ;
     RECT  58.68 4.225 58.806 4.451 ;
     RECT  58.716 4.451 58.806 4.459 ;
     RECT  59.655 4.387 60.462 4.459 ;
     RECT  41.688 4.451 41.706 4.487 ;
     RECT  50.724 4.397 50.922 4.487 ;
     RECT  29.664 4.445 29.862 4.493 ;
     RECT  10.224 3.677 11.538 4.495 ;
     RECT  38.055 4.351 38.898 4.523 ;
     RECT  40.752 4.301 40.77 4.523 ;
     RECT  30.708 4.415 30.798 4.541 ;
     RECT  1.62 4.351 1.674 4.555 ;
     RECT  2.628 4.351 3.654 4.555 ;
     RECT  8.568 4.495 8.586 4.555 ;
     RECT  31.932 4.415 34.866 4.559 ;
     RECT  53.964 4.451 55.566 4.559 ;
     RECT  10.188 4.495 11.538 4.621 ;
     RECT  46.764 3.569 46.854 4.621 ;
     RECT  47.628 4.603 47.862 4.621 ;
     RECT  62.712 4.379 62.874 4.621 ;
     RECT  63.864 4.261 65.337 4.621 ;
     RECT  62.712 4.621 65.574 4.649 ;
     RECT  0.036 3.875 0.63 4.651 ;
     RECT  64.548 4.649 65.574 4.657 ;
     RECT  66.708 4.081 66.834 4.657 ;
     RECT  67.86 4.261 72.81 4.693 ;
     RECT  0.036 4.651 0.738 4.699 ;
     RECT  1.62 4.555 3.654 4.699 ;
     RECT  8.568 4.555 8.91 4.721 ;
     RECT  36.468 4.415 37.17 4.721 ;
     RECT  0.036 4.699 3.654 4.729 ;
     RECT  9.72 4.621 11.538 4.729 ;
     RECT  46.764 4.621 47.862 4.729 ;
     RECT  48.855 3.875 49.137 4.729 ;
     RECT  42.768 4.253 43.83 4.733 ;
     RECT  62.712 4.649 63.774 4.733 ;
     RECT  53.964 4.559 54.846 4.765 ;
     RECT  67.68 4.693 72.81 4.781 ;
     RECT  37.044 4.721 37.17 4.793 ;
     RECT  0.036 4.729 3.87 4.801 ;
     RECT  8.892 4.721 8.91 4.801 ;
     RECT  9.72 4.729 11.61 4.801 ;
     RECT  64.548 4.657 66.834 4.801 ;
     RECT  67.68 4.781 68.202 4.801 ;
     RECT  7.956 4.747 8.082 4.877 ;
     RECT  14.832 4.747 15.066 4.877 ;
     RECT  0.036 4.801 4.302 4.919 ;
     RECT  37.116 4.793 37.17 4.919 ;
     RECT  42.768 4.733 43.737 4.919 ;
     RECT  68.94 4.781 72.81 4.919 ;
     RECT  52.992 3.983 53.01 4.927 ;
     RECT  53.748 4.765 54.846 4.927 ;
     RECT  8.892 4.801 11.61 4.955 ;
     RECT  58.716 4.459 60.606 4.955 ;
     RECT  64.548 4.801 68.202 4.955 ;
     RECT  52.884 4.927 54.846 4.973 ;
     RECT  23.904 4.801 23.922 4.987 ;
     RECT  46.764 4.729 49.137 4.991 ;
     RECT  5.616 4.217 5.958 4.999 ;
     RECT  6.732 4.693 7.002 4.999 ;
     RECT  29.664 4.493 29.682 4.999 ;
     RECT  18.828 4.379 19.638 5.021 ;
     RECT  68.94 4.919 72.666 5.021 ;
     RECT  58.788 4.955 60.606 5.027 ;
     RECT  68.184 4.955 68.202 5.027 ;
     RECT  44.568 4.253 44.946 5.035 ;
     RECT  23.904 4.987 24.066 5.063 ;
     RECT  25.056 4.891 25.074 5.063 ;
     RECT  46.764 4.991 47.646 5.063 ;
     RECT  1.62 4.919 4.302 5.069 ;
     RECT  29.34 4.999 29.682 5.069 ;
     RECT  44.46 5.035 44.946 5.069 ;
     RECT  64.548 4.955 66.906 5.069 ;
     RECT  46.764 5.063 47.538 5.071 ;
     RECT  4.284 5.069 4.302 5.099 ;
     RECT  7.92 4.987 7.938 5.099 ;
     RECT  21.096 4.415 21.114 5.131 ;
     RECT  18.828 5.021 18.954 5.161 ;
     RECT  20.772 5.131 21.114 5.161 ;
     RECT  32.436 4.559 34.866 5.161 ;
     RECT  38.055 4.523 38.538 5.161 ;
     RECT  46.728 5.071 47.538 5.161 ;
     RECT  48.492 4.991 49.137 5.161 ;
     RECT  52.884 4.973 52.902 5.161 ;
     RECT  57.06 5.131 57.078 5.161 ;
     RECT  21.855 4.415 22.842 5.179 ;
     RECT  29.664 5.069 29.682 5.189 ;
     RECT  45.9 5.161 47.538 5.189 ;
     RECT  26.712 4.415 27.537 5.197 ;
     RECT  32.436 5.161 34.974 5.197 ;
     RECT  39.42 5.161 39.438 5.197 ;
     RECT  57.06 5.161 57.15 5.197 ;
     RECT  63.612 4.733 63.774 5.213 ;
     RECT  16.455 4.253 16.737 5.227 ;
     RECT  5.616 4.999 7.002 5.233 ;
     RECT  56.952 5.197 57.258 5.233 ;
     RECT  59.655 5.027 60.606 5.233 ;
     RECT  61.56 3.839 61.578 5.233 ;
     RECT  18.432 5.161 18.954 5.261 ;
     RECT  20.7 5.161 21.114 5.269 ;
     RECT  21.855 5.179 23.166 5.269 ;
     RECT  37.62 5.161 38.538 5.275 ;
     RECT  16.455 5.227 17.118 5.297 ;
     RECT  26.676 5.197 27.537 5.297 ;
     RECT  47.232 5.189 47.538 5.297 ;
     RECT  30.708 4.541 30.726 5.305 ;
     RECT  9.072 4.955 11.61 5.341 ;
     RECT  20.7 5.269 23.166 5.341 ;
     RECT  48.492 5.161 49.986 5.341 ;
     RECT  50.724 4.487 50.85 5.341 ;
     RECT  1.62 5.069 3.402 5.369 ;
     RECT  18.864 5.261 18.954 5.369 ;
     RECT  47.232 5.297 47.466 5.369 ;
     RECT  48.492 5.341 50.85 5.371 ;
     RECT  5.616 5.233 7.038 5.419 ;
     RECT  20.7 5.341 23.562 5.431 ;
     RECT  53.748 4.973 54.846 5.431 ;
     RECT  9.072 5.341 11.682 5.459 ;
     RECT  14.832 4.877 14.886 5.459 ;
     RECT  18.936 5.369 18.954 5.459 ;
     RECT  29.844 5.233 29.862 5.459 ;
     RECT  45.036 5.197 45.126 5.459 ;
     RECT  47.232 5.369 47.394 5.459 ;
     RECT  48.492 5.371 50.886 5.459 ;
     RECT  52.344 5.161 52.902 5.459 ;
     RECT  58.788 5.027 58.806 5.459 ;
     RECT  20.664 5.431 23.562 5.467 ;
     RECT  20.556 5.467 23.562 5.495 ;
     RECT  45.9 5.189 46.386 5.495 ;
     RECT  52.884 5.459 52.902 5.495 ;
     RECT  47.232 5.459 47.358 5.531 ;
     RECT  48.492 5.459 50.814 5.531 ;
     RECT  62.712 4.733 62.838 5.531 ;
     RECT  39.42 5.197 39.51 5.539 ;
     RECT  32.436 5.197 35.01 5.567 ;
     RECT  32.436 5.567 34.938 5.597 ;
     RECT  66.708 5.069 66.906 5.597 ;
     RECT  32.436 5.597 33.858 5.603 ;
     RECT  47.34 5.531 47.358 5.603 ;
     RECT  59.655 5.233 61.578 5.603 ;
     RECT  5.436 5.419 7.038 5.611 ;
     RECT  34.668 5.597 34.866 5.639 ;
     RECT  39.42 5.539 39.582 5.639 ;
     RECT  53.748 5.431 54.954 5.639 ;
     RECT  59.655 5.603 60.534 5.639 ;
     RECT  66.708 5.597 66.798 5.639 ;
     RECT  0.036 4.919 0.666 5.659 ;
     RECT  4.932 5.611 7.038 5.701 ;
     RECT  26.712 5.297 27.537 5.701 ;
     RECT  30.708 5.305 30.942 5.701 ;
     RECT  32.436 5.603 33.678 5.701 ;
     RECT  40.536 5.611 40.554 5.701 ;
     RECT  42.804 4.919 43.737 5.701 ;
     RECT  45.9 5.495 46.242 5.701 ;
     RECT  56.952 5.233 57.294 5.701 ;
     RECT  68.94 5.021 72.63 5.701 ;
     RECT  40.428 5.701 40.554 5.707 ;
     RECT  58.32 5.701 58.446 5.707 ;
     RECT  4.932 5.701 7.218 5.729 ;
     RECT  64.548 5.069 65.97 5.737 ;
     RECT  68.832 5.701 72.63 5.755 ;
     RECT  68.832 5.755 72.702 5.773 ;
     RECT  16.455 5.297 17.01 5.789 ;
     RECT  64.116 5.737 65.97 5.789 ;
     RECT  25.2 5.701 25.866 5.809 ;
     RECT  37.62 5.275 38.682 5.809 ;
     RECT  37.116 5.809 38.682 5.845 ;
     RECT  40.356 5.707 40.554 5.845 ;
     RECT  25.056 5.809 25.902 5.851 ;
     RECT  9.072 5.459 11.337 5.873 ;
     RECT  26.712 5.701 27.666 5.873 ;
     RECT  2.124 5.369 3.402 5.881 ;
     RECT  5.616 5.729 7.218 5.881 ;
     RECT  15.66 5.701 15.678 5.881 ;
     RECT  16.455 5.789 16.902 5.881 ;
     RECT  21.855 5.495 23.562 5.881 ;
     RECT  25.056 5.851 25.974 5.881 ;
     RECT  55.872 5.701 57.294 5.881 ;
     RECT  14.832 5.459 14.85 5.885 ;
     RECT  15.66 5.881 16.902 5.885 ;
     RECT  13.104 5.755 13.122 5.909 ;
     RECT  20.556 5.495 21.042 5.909 ;
     RECT  48.492 5.531 49.698 5.909 ;
     RECT  37.116 5.845 39.186 5.933 ;
     RECT  68.76 5.773 72.702 5.971 ;
     RECT  21.855 5.881 25.974 5.981 ;
     RECT  15.66 5.885 16.794 5.999 ;
     RECT  17.82 5.773 17.838 5.999 ;
     RECT  2.124 5.881 3.546 6.035 ;
     RECT  58.248 5.707 58.446 6.035 ;
     RECT  55.872 5.881 57.474 6.043 ;
     RECT  58.248 6.035 58.338 6.071 ;
     RECT  21.855 5.981 25.902 6.077 ;
     RECT  53.748 5.639 54.918 6.079 ;
     RECT  50.724 5.531 50.814 6.107 ;
     RECT  5.616 5.881 7.326 6.115 ;
     RECT  64.404 5.789 65.97 6.115 ;
     RECT  66.708 5.639 66.762 6.115 ;
     RECT  5.616 6.115 7.974 6.143 ;
     RECT  53.712 6.079 54.918 6.143 ;
     RECT  26.712 5.873 27.594 6.151 ;
     RECT  21.855 6.077 25.614 6.179 ;
     RECT  14.724 6.139 14.742 6.235 ;
     RECT  21.855 6.179 22.914 6.235 ;
     RECT  44.748 5.845 44.766 6.235 ;
     RECT  53.712 6.143 54.882 6.235 ;
     RECT  14.58 6.235 14.742 6.241 ;
     RECT  15.66 5.999 16.737 6.241 ;
     RECT  53.568 6.235 54.882 6.241 ;
     RECT  0.036 5.659 1.314 6.269 ;
     RECT  5.616 6.143 6.786 6.269 ;
     RECT  7.56 6.143 7.974 6.269 ;
     RECT  21.636 6.235 22.914 6.269 ;
     RECT  23.904 6.179 25.614 6.269 ;
     RECT  26.64 6.151 27.594 6.269 ;
     RECT  34.668 5.639 34.83 6.269 ;
     RECT  37.8 5.933 39.186 6.269 ;
     RECT  44.604 6.235 44.766 6.269 ;
     RECT  52.848 6.241 54.882 6.269 ;
     RECT  64.404 6.115 66.762 6.269 ;
     RECT  30.42 5.701 33.678 6.277 ;
     RECT  55.728 6.043 57.474 6.277 ;
     RECT  55.728 6.277 57.618 6.305 ;
     RECT  36.324 6.277 36.342 6.313 ;
     RECT  40.356 5.845 40.662 6.313 ;
     RECT  61.344 5.603 61.578 6.349 ;
     RECT  62.712 5.531 62.766 6.349 ;
     RECT  55.872 6.305 57.618 6.377 ;
     RECT  64.404 6.269 65.682 6.377 ;
     RECT  61.344 6.349 61.722 6.379 ;
     RECT  59.655 5.639 59.937 6.385 ;
     RECT  66.6 6.269 66.762 6.385 ;
     RECT  9.072 5.873 10.026 6.413 ;
     RECT  23.904 6.269 25.47 6.413 ;
     RECT  34.668 6.269 34.794 6.421 ;
     RECT  45.54 5.701 46.242 6.421 ;
     RECT  59.508 6.385 59.937 6.421 ;
     RECT  62.712 6.349 62.838 6.421 ;
     RECT  66.6 6.385 67.122 6.421 ;
     RECT  68.76 5.971 72.81 6.421 ;
     RECT  45.036 6.421 46.242 6.449 ;
     RECT  59.508 6.421 59.994 6.511 ;
     RECT  5.616 6.269 6.642 6.539 ;
     RECT  23.904 6.413 24.714 6.539 ;
     RECT  25.452 6.413 25.47 6.539 ;
     RECT  40.032 6.313 40.662 6.539 ;
     RECT  30.06 6.277 33.678 6.547 ;
     RECT  48.492 5.909 49.554 6.547 ;
     RECT  60.876 6.379 61.722 6.547 ;
     RECT  62.496 6.421 62.838 6.547 ;
     RECT  21.636 6.269 22.842 6.557 ;
     RECT  40.032 6.539 40.518 6.575 ;
     RECT  45.036 6.449 45.774 6.575 ;
     RECT  48.312 6.547 49.554 6.575 ;
     RECT  50.724 6.107 50.778 6.575 ;
     RECT  64.404 6.377 65.337 6.575 ;
     RECT  68.652 6.421 72.81 6.575 ;
     RECT  47.268 6.571 47.286 6.583 ;
     RECT  48.312 6.575 49.482 6.583 ;
     RECT  5.616 6.539 5.937 6.605 ;
     RECT  60.876 6.547 62.838 6.605 ;
     RECT  7.56 6.269 7.65 6.611 ;
     RECT  15.516 6.241 16.737 6.611 ;
     RECT  30.06 6.547 33.822 6.611 ;
     RECT  34.596 6.421 34.794 6.611 ;
     RECT  60.876 6.605 61.722 6.611 ;
     RECT  11.016 5.873 11.337 6.619 ;
     RECT  13.896 6.241 14.742 6.619 ;
     RECT  59.328 6.511 59.994 6.619 ;
     RECT  30.708 6.611 33.822 6.647 ;
     RECT  50.724 6.575 50.742 6.647 ;
     RECT  66.6 6.421 67.842 6.647 ;
     RECT  2.124 6.035 3.006 6.655 ;
     RECT  26.784 6.269 27.594 6.655 ;
     RECT  29.088 6.331 29.106 6.667 ;
     RECT  29.916 6.619 29.934 6.667 ;
     RECT  30.78 6.647 33.822 6.683 ;
     RECT  61.416 6.611 61.578 6.683 ;
     RECT  68.94 6.575 72.81 6.683 ;
     RECT  12.564 6.283 12.582 6.719 ;
     RECT  13.608 6.619 14.742 6.719 ;
     RECT  2.088 6.655 3.006 6.781 ;
     RECT  3.852 6.583 3.87 6.781 ;
     RECT  10.908 6.619 11.337 6.781 ;
     RECT  47.268 6.583 49.482 6.781 ;
     RECT  7.632 6.611 7.65 6.809 ;
     RECT  15.66 6.611 16.737 6.809 ;
     RECT  29.088 6.667 29.934 6.809 ;
     RECT  35.64 6.313 36.342 6.809 ;
     RECT  40.032 6.575 40.05 6.809 ;
     RECT  61.56 6.683 61.578 6.809 ;
     RECT  67.68 6.647 67.842 6.809 ;
     RECT  59.292 6.619 60.642 6.811 ;
     RECT  2.088 6.781 3.87 6.845 ;
     RECT  23.904 6.539 23.922 6.845 ;
     RECT  30.78 6.683 31.122 6.845 ;
     RECT  62.496 6.605 62.838 6.845 ;
     RECT  67.68 6.809 67.698 6.845 ;
     RECT  29.088 6.809 29.286 6.853 ;
     RECT  37.8 6.269 39.15 6.853 ;
     RECT  42.768 5.701 43.737 6.853 ;
     RECT  26.784 6.655 27.738 6.859 ;
     RECT  14.256 6.719 14.742 6.889 ;
     RECT  15.732 6.809 16.737 6.889 ;
     RECT  36.18 6.809 36.342 6.889 ;
     RECT  19.692 6.853 19.71 6.907 ;
     RECT  2.088 6.845 2.286 6.941 ;
     RECT  37.224 6.853 39.15 6.953 ;
     RECT  42.084 6.853 43.737 6.955 ;
     RECT  21.744 6.557 22.842 6.989 ;
     RECT  6.732 7.003 6.75 7.051 ;
     RECT  15.732 6.889 16.974 7.051 ;
     RECT  21.855 6.989 22.842 7.051 ;
     RECT  38.055 6.953 39.15 7.051 ;
     RECT  39.96 6.817 40.014 7.051 ;
     RECT  36.18 6.889 36.486 7.079 ;
     RECT  46.62 6.781 49.482 7.085 ;
     RECT  55.872 6.377 57.366 7.087 ;
     RECT  0.036 6.269 1.17 7.099 ;
     RECT  9.072 6.413 9.45 7.133 ;
     RECT  52.848 6.269 52.866 7.147 ;
     RECT  21.855 7.051 22.878 7.159 ;
     RECT  55.764 7.087 57.366 7.159 ;
     RECT  59.004 6.811 60.642 7.159 ;
     RECT  0.036 7.099 1.278 7.187 ;
     RECT  19.692 6.907 19.89 7.187 ;
     RECT  46.728 7.085 49.482 7.187 ;
     RECT  50.616 6.961 50.706 7.187 ;
     RECT  26.784 6.859 28.062 7.195 ;
     RECT  28.944 6.853 29.286 7.195 ;
     RECT  34.632 6.611 34.794 7.195 ;
     RECT  36.468 7.079 36.486 7.195 ;
     RECT  37.224 6.953 37.242 7.195 ;
     RECT  55.764 7.159 57.762 7.195 ;
     RECT  36.468 7.195 37.242 7.223 ;
     RECT  15.732 7.051 17.154 7.229 ;
     RECT  3.348 6.845 3.87 7.231 ;
     RECT  6.732 7.051 6.822 7.231 ;
     RECT  9.072 7.133 9.306 7.231 ;
     RECT  18.828 6.889 18.846 7.231 ;
     RECT  24.66 6.539 24.714 7.231 ;
     RECT  52.272 7.147 52.866 7.231 ;
     RECT  62.712 6.845 62.838 7.231 ;
     RECT  15.732 7.229 17.046 7.259 ;
     RECT  15.84 7.259 17.046 7.277 ;
     RECT  52.272 7.231 53.01 7.321 ;
     RECT  58.716 7.159 60.642 7.321 ;
     RECT  31.896 6.683 33.822 7.325 ;
     RECT  51.912 7.321 53.01 7.339 ;
     RECT  3.348 7.231 4.482 7.349 ;
     RECT  24.66 7.231 24.822 7.349 ;
     RECT  38.055 7.051 40.014 7.349 ;
     RECT  41.616 6.955 43.737 7.349 ;
     RECT  46.728 7.187 47.25 7.349 ;
     RECT  51.768 7.339 53.01 7.349 ;
     RECT  53.784 6.269 54.882 7.349 ;
     RECT  55.692 7.195 57.762 7.349 ;
     RECT  21.096 7.321 21.114 7.373 ;
     RECT  3.348 7.349 4.302 7.385 ;
     RECT  45.756 6.575 45.774 7.385 ;
     RECT  51.768 7.349 51.93 7.385 ;
     RECT  55.692 7.349 57.618 7.385 ;
     RECT  30.78 6.845 30.906 7.387 ;
     RECT  66.6 6.647 66.762 7.393 ;
     RECT  26.784 7.195 29.286 7.421 ;
     RECT  31.932 7.325 33.822 7.421 ;
     RECT  41.328 7.387 41.346 7.421 ;
     RECT  51.912 7.385 51.93 7.421 ;
     RECT  21.855 7.159 23.058 7.429 ;
     RECT  26.784 7.421 28.602 7.429 ;
     RECT  64.26 7.357 64.278 7.435 ;
     RECT  65.055 6.575 65.337 7.435 ;
     RECT  69.624 6.683 72.81 7.435 ;
     RECT  34.632 7.195 34.83 7.465 ;
     RECT  66.492 7.393 66.762 7.465 ;
     RECT  68.976 7.435 72.81 7.465 ;
     RECT  26.64 7.429 28.602 7.469 ;
     RECT  10.224 6.781 11.337 7.493 ;
     RECT  36.468 7.223 37.17 7.493 ;
     RECT  5.655 6.605 5.937 7.501 ;
     RECT  6.732 7.231 6.858 7.501 ;
     RECT  10.296 7.493 11.337 7.501 ;
     RECT  34.632 7.465 34.938 7.501 ;
     RECT  31.932 7.421 33.03 7.529 ;
     RECT  6.732 7.501 7.542 7.531 ;
     RECT  5.256 7.501 5.937 7.579 ;
     RECT  6.66 7.531 7.542 7.579 ;
     RECT  18.828 7.231 18.918 7.579 ;
     RECT  64.26 7.435 65.337 7.579 ;
     RECT  66.492 7.465 66.798 7.579 ;
     RECT  5.256 7.579 7.542 7.591 ;
     RECT  30.636 7.387 30.906 7.591 ;
     RECT  48.348 7.187 49.482 7.591 ;
     RECT  64.26 7.579 66.798 7.591 ;
     RECT  3.348 7.385 3.978 7.619 ;
     RECT  9 7.231 9.306 7.619 ;
     RECT  10.296 7.501 11.43 7.619 ;
     RECT  26.784 7.469 28.602 7.619 ;
     RECT  34.128 7.501 34.938 7.619 ;
     RECT  38.055 7.349 39.69 7.619 ;
     RECT  34.272 7.619 34.938 7.627 ;
     RECT  58.536 7.321 60.642 7.627 ;
     RECT  62.712 7.231 62.874 7.627 ;
     RECT  64.26 7.591 66.834 7.627 ;
     RECT  26.784 7.619 28.35 7.655 ;
     RECT  34.272 7.627 35.406 7.655 ;
     RECT  14.256 6.889 14.922 7.661 ;
     RECT  31.932 7.529 32.937 7.661 ;
     RECT  58.536 7.627 60.678 7.661 ;
     RECT  62.532 7.627 62.874 7.661 ;
     RECT  2.124 6.941 2.286 7.663 ;
     RECT  3.348 7.619 3.438 7.663 ;
     RECT  14.832 7.661 14.922 7.675 ;
     RECT  9 7.619 9.27 7.699 ;
     RECT  14.832 7.675 14.958 7.709 ;
     RECT  10.332 7.619 11.43 7.727 ;
     RECT  32.004 7.661 32.937 7.727 ;
     RECT  55.692 7.385 57.474 7.727 ;
     RECT  62.604 7.661 62.874 7.727 ;
     RECT  21.855 7.429 23.634 7.735 ;
     RECT  54.255 7.349 54.882 7.735 ;
     RECT  55.692 7.727 55.71 7.735 ;
     RECT  68.724 7.465 72.81 7.735 ;
     RECT  34.488 7.655 35.406 7.763 ;
     RECT  58.536 7.661 60.462 7.763 ;
     RECT  30.636 7.591 30.978 7.771 ;
     RECT  5.256 7.591 7.578 7.799 ;
     RECT  64.26 7.627 66.942 7.819 ;
     RECT  2.124 7.663 3.438 7.861 ;
     RECT  18.828 7.579 19.494 7.861 ;
     RECT  21.672 7.735 23.634 7.861 ;
     RECT  8.712 7.699 9.27 7.889 ;
     RECT  34.488 7.763 34.938 7.889 ;
     RECT  38.055 7.619 39.51 7.889 ;
     RECT  54.255 7.735 55.71 7.889 ;
     RECT  58.536 7.763 58.59 7.889 ;
     RECT  14.94 7.709 14.958 7.901 ;
     RECT  63.864 7.819 67.014 7.901 ;
     RECT  36.468 7.493 36.954 7.915 ;
     RECT  30.204 7.771 30.978 7.925 ;
     RECT  34.488 7.889 34.866 7.925 ;
     RECT  59.328 7.763 60.462 7.925 ;
     RECT  41.112 7.465 41.13 7.949 ;
     RECT  63.864 7.901 63.918 7.949 ;
     RECT  34.524 7.925 34.866 7.961 ;
     RECT  38.055 7.889 39.15 7.961 ;
     RECT  10.368 7.727 11.43 7.963 ;
     RECT  46.728 7.349 46.746 7.969 ;
     RECT  50.724 7.735 50.742 7.969 ;
     RECT  61.596 7.933 61.614 7.969 ;
     RECT  62.712 7.727 62.874 7.969 ;
     RECT  5.544 7.799 7.578 7.997 ;
     RECT  10.368 7.963 11.862 7.997 ;
     RECT  52.776 7.349 52.938 7.997 ;
     RECT  64.908 7.901 67.014 7.997 ;
     RECT  68.652 7.735 72.81 7.997 ;
     RECT  21.672 7.861 23.67 8.005 ;
     RECT  58.536 7.889 58.554 8.005 ;
     RECT  16.344 7.277 17.046 8.041 ;
     RECT  48.348 7.591 49.986 8.041 ;
     RECT  61.596 7.969 61.758 8.041 ;
     RECT  0.036 7.187 0.63 8.059 ;
     RECT  26.784 7.655 28.242 8.069 ;
     RECT  59.328 7.925 59.937 8.069 ;
     RECT  16.344 8.041 17.334 8.107 ;
     RECT  20.484 7.435 20.646 8.107 ;
     RECT  15.948 8.107 17.334 8.131 ;
     RECT  20.484 8.107 20.682 8.159 ;
     RECT  21.672 8.005 23.886 8.159 ;
     RECT  34.776 7.961 34.866 8.159 ;
     RECT  45.036 7.591 45.522 8.159 ;
     RECT  48.168 8.041 49.986 8.159 ;
     RECT  52.776 7.997 52.866 8.159 ;
     RECT  54.255 7.889 55.134 8.159 ;
     RECT  20.484 8.159 20.538 8.167 ;
     RECT  15.948 8.131 17.406 8.203 ;
     RECT  18.468 7.861 19.494 8.203 ;
     RECT  46.368 7.969 46.746 8.203 ;
     RECT  15.948 8.203 19.494 8.231 ;
     RECT  23.796 8.159 23.886 8.231 ;
     RECT  34.848 8.159 34.866 8.231 ;
     RECT  46.188 8.203 46.746 8.231 ;
     RECT  42.084 7.349 43.737 8.237 ;
     RECT  23.868 8.231 23.886 8.239 ;
     RECT  68.292 8.131 68.31 8.239 ;
     RECT  50.724 7.969 50.814 8.275 ;
     RECT  10.44 7.997 11.862 8.303 ;
     RECT  23.868 8.239 24.462 8.303 ;
     RECT  21.672 8.159 22.878 8.311 ;
     RECT  30.78 7.925 30.978 8.311 ;
     RECT  32.076 7.727 32.937 8.311 ;
     RECT  36.396 7.915 36.954 8.311 ;
     RECT  38.055 7.961 38.394 8.311 ;
     RECT  48.6 8.159 49.986 8.311 ;
     RECT  50.724 8.275 51.462 8.311 ;
     RECT  52.74 8.167 52.758 8.311 ;
     RECT  57.024 7.727 57.474 8.311 ;
     RECT  58.392 8.005 58.554 8.311 ;
     RECT  62.712 7.969 63.126 8.311 ;
     RECT  15.948 8.231 16.737 8.339 ;
     RECT  23.94 8.303 24.462 8.339 ;
     RECT  39.132 7.961 39.15 8.339 ;
     RECT  52.38 8.311 52.758 8.339 ;
     RECT  32.076 8.311 33.03 8.381 ;
     RECT  1.764 7.861 3.438 8.395 ;
     RECT  1.764 8.395 3.798 8.401 ;
     RECT  17.676 8.231 19.494 8.401 ;
     RECT  20.268 8.167 20.538 8.401 ;
     RECT  32.22 8.381 33.03 8.401 ;
     RECT  61.56 8.041 61.758 8.401 ;
     RECT  13.392 8.311 13.41 8.429 ;
     RECT  24.264 8.339 24.462 8.429 ;
     RECT  36.396 8.311 38.394 8.429 ;
     RECT  62.712 8.311 63.306 8.429 ;
     RECT  48.6 8.311 51.462 8.437 ;
     RECT  52.38 8.339 52.47 8.437 ;
     RECT  30.78 8.311 31.158 8.465 ;
     RECT  48.6 8.437 52.47 8.465 ;
     RECT  57.024 8.311 58.554 8.465 ;
     RECT  65.055 7.997 67.014 8.473 ;
     RECT  67.896 8.239 68.31 8.473 ;
     RECT  69.048 7.997 72.81 8.473 ;
     RECT  14.292 8.437 14.31 8.477 ;
     RECT  0.036 8.059 0.666 8.491 ;
     RECT  60.948 8.401 61.758 8.491 ;
     RECT  62.712 8.429 62.838 8.491 ;
     RECT  60.948 8.491 62.838 8.501 ;
     RECT  6.84 7.997 7.578 8.525 ;
     RECT  30.78 8.465 30.87 8.525 ;
     RECT  1.764 8.401 3.942 8.537 ;
     RECT  17.676 8.401 20.538 8.537 ;
     RECT  24.444 8.429 24.462 8.537 ;
     RECT  38.016 8.429 38.394 8.537 ;
     RECT  42.768 8.237 43.737 8.537 ;
     RECT  45.036 8.159 45.306 8.537 ;
     RECT  48.6 8.465 49.518 8.537 ;
     RECT  50.364 8.465 52.47 8.537 ;
     RECT  47.052 8.311 47.25 8.539 ;
     RECT  65.055 8.473 68.31 8.573 ;
     RECT  2.088 8.537 3.942 8.581 ;
     RECT  4.716 8.275 4.734 8.581 ;
     RECT  6.912 8.525 7.578 8.581 ;
     RECT  11.055 8.303 11.862 8.581 ;
     RECT  5.544 7.997 5.937 8.621 ;
     RECT  9.036 7.889 9.162 8.635 ;
     RECT  11.055 8.581 12.654 8.671 ;
     RECT  11.055 8.671 12.726 8.699 ;
     RECT  14.148 8.509 14.166 8.699 ;
     RECT  18.504 8.537 20.538 8.699 ;
     RECT  42.012 8.581 42.03 8.699 ;
     RECT  57.024 8.465 57.618 8.699 ;
     RECT  61.56 8.501 62.838 8.699 ;
     RECT  26.784 8.069 28.134 8.707 ;
     RECT  42.84 8.537 43.737 8.707 ;
     RECT  38.055 8.537 38.394 8.743 ;
     RECT  42.84 8.707 43.794 8.743 ;
     RECT  58.464 8.465 58.554 8.743 ;
     RECT  2.088 8.581 4.734 8.771 ;
     RECT  6.912 8.581 8.046 8.771 ;
     RECT  12.636 8.699 12.726 8.771 ;
     RECT  21.456 8.311 22.878 8.771 ;
     RECT  17.676 8.537 17.694 8.807 ;
     RECT  3.708 8.771 4.734 8.813 ;
     RECT  54.255 8.159 55.062 8.813 ;
     RECT  2.088 8.771 2.934 8.843 ;
     RECT  8.028 8.771 8.046 8.851 ;
     RECT  8.892 8.635 9.162 8.851 ;
     RECT  18.72 8.699 20.538 8.861 ;
     RECT  21.456 8.771 22.842 8.941 ;
     RECT  64.116 8.851 64.134 8.941 ;
     RECT  8.028 8.851 9.918 8.969 ;
     RECT  25.884 8.743 25.902 8.969 ;
     RECT  47.052 8.539 47.682 8.969 ;
     RECT  48.6 8.537 49.137 8.969 ;
     RECT  59.4 8.069 59.937 8.969 ;
     RECT  66.132 8.573 68.31 8.969 ;
     RECT  67.104 8.969 68.31 8.971 ;
     RECT  69.048 8.473 72.846 8.971 ;
     RECT  3.78 8.813 4.734 9.005 ;
     RECT  63.72 8.941 64.134 9.005 ;
     RECT  20.412 8.861 20.538 9.013 ;
     RECT  21.312 8.941 22.842 9.013 ;
     RECT  26.712 8.707 28.134 9.013 ;
     RECT  6.912 8.771 7.074 9.041 ;
     RECT  42.84 8.743 44.514 9.041 ;
     RECT  51.876 8.537 52.47 9.053 ;
     RECT  0.036 8.491 1.026 9.067 ;
     RECT  9.108 8.969 9.918 9.067 ;
     RECT  44.496 9.041 44.514 9.077 ;
     RECT  52.452 9.053 52.47 9.077 ;
     RECT  54.255 8.813 54.882 9.077 ;
     RECT  67.104 8.971 72.846 9.077 ;
     RECT  9.108 9.067 9.954 9.113 ;
     RECT  26.064 9.013 28.602 9.113 ;
     RECT  58.464 8.743 58.626 9.115 ;
     RECT  3.852 9.005 4.734 9.121 ;
     RECT  32.22 8.401 33.102 9.121 ;
     RECT  46.188 8.231 46.278 9.121 ;
     RECT  54.255 9.077 54.846 9.121 ;
     RECT  63.936 9.005 64.134 9.121 ;
     RECT  36.396 8.429 37.134 9.211 ;
     RECT  2.088 8.843 2.862 9.239 ;
     RECT  3.852 9.121 4.77 9.239 ;
     RECT  32.04 9.121 33.102 9.239 ;
     RECT  62.028 8.699 62.838 9.239 ;
     RECT  66.132 8.969 66.15 9.239 ;
     RECT  2.088 9.239 2.286 9.245 ;
     RECT  36.36 9.211 37.134 9.245 ;
     RECT  46.116 9.121 46.278 9.247 ;
     RECT  47.664 8.969 47.682 9.247 ;
     RECT  47.664 9.247 47.79 9.275 ;
     RECT  50.616 8.537 50.886 9.275 ;
     RECT  57.42 8.699 57.618 9.275 ;
     RECT  34.74 9.211 34.758 9.283 ;
     RECT  38.055 8.743 38.898 9.283 ;
     RECT  42.84 9.041 43.737 9.283 ;
     RECT  26.064 9.113 27.63 9.293 ;
     RECT  32.58 9.239 33.102 9.293 ;
     RECT  4.536 9.239 4.77 9.311 ;
     RECT  62.1 9.239 62.838 9.311 ;
     RECT  32.58 9.293 32.937 9.341 ;
     RECT  28.476 9.113 28.602 9.355 ;
     RECT  33.912 9.319 33.93 9.355 ;
     RECT  34.74 9.283 34.866 9.355 ;
     RECT  54.216 9.121 54.846 9.355 ;
     RECT  62.352 9.311 62.838 9.355 ;
     RECT  63.936 9.121 64.206 9.355 ;
     RECT  65.055 8.573 65.337 9.355 ;
     RECT  4.536 9.311 4.554 9.383 ;
     RECT  2.124 9.245 2.286 9.389 ;
     RECT  15.228 8.581 15.246 9.391 ;
     RECT  36.432 9.245 37.134 9.391 ;
     RECT  38.052 9.283 38.898 9.391 ;
     RECT  58.464 9.115 58.806 9.391 ;
     RECT  34.74 9.355 35.37 9.419 ;
     RECT  67.104 9.077 68.49 9.419 ;
     RECT  57.744 9.391 58.806 9.437 ;
     RECT  62.352 9.355 62.874 9.481 ;
     RECT  20.412 9.013 22.842 9.509 ;
     RECT  33.84 9.355 33.93 9.509 ;
     RECT  48.708 8.969 49.137 9.509 ;
     RECT  60.732 9.355 60.75 9.509 ;
     RECT  63.936 9.355 65.337 9.509 ;
     RECT  67.104 9.419 68.238 9.509 ;
     RECT  16.455 8.339 16.737 9.517 ;
     RECT  42.768 9.283 43.737 9.517 ;
     RECT  46.116 9.247 46.854 9.517 ;
     RECT  52.524 9.319 52.65 9.517 ;
     RECT  18.72 8.861 19.386 9.533 ;
     RECT  33.912 9.509 33.93 9.545 ;
     RECT  59.616 8.969 59.937 9.545 ;
     RECT  69.624 9.077 72.846 9.545 ;
     RECT  30.852 8.525 30.87 9.547 ;
     RECT  14.796 9.391 15.246 9.553 ;
     RECT  36.432 9.391 38.934 9.581 ;
     RECT  42.696 9.517 43.737 9.581 ;
     RECT  28.476 9.355 29.214 9.589 ;
     RECT  52.524 9.517 52.722 9.589 ;
     RECT  30.852 9.547 31.374 9.617 ;
     RECT  36.432 9.581 37.278 9.617 ;
     RECT  42.804 9.581 43.737 9.617 ;
     RECT  67.104 9.509 67.122 9.617 ;
     RECT  14.796 9.553 15.318 9.629 ;
     RECT  28.476 9.589 29.25 9.629 ;
     RECT  64.872 9.509 65.337 9.653 ;
     RECT  69.696 9.545 72.846 9.653 ;
     RECT  11.055 8.699 11.337 9.661 ;
     RECT  45.72 9.517 46.854 9.677 ;
     RECT  62.352 9.481 63.018 9.677 ;
     RECT  29.088 9.629 29.25 9.689 ;
     RECT  38.016 9.581 38.934 9.689 ;
     RECT  48.744 9.509 49.137 9.689 ;
     RECT  64.08 9.509 64.098 9.689 ;
     RECT  26.064 9.293 27.537 9.739 ;
     RECT  11.055 9.661 11.394 9.751 ;
     RECT  18.72 9.533 18.846 9.751 ;
     RECT  30.852 9.617 31.158 9.751 ;
     RECT  20.736 9.509 22.842 9.779 ;
     RECT  18.36 9.751 18.846 9.787 ;
     RECT  25.632 9.739 27.537 9.787 ;
     RECT  9.108 9.113 9.162 9.815 ;
     RECT  14.832 9.629 15.318 9.823 ;
     RECT  16.344 9.517 16.737 9.823 ;
     RECT  56.556 9.751 56.574 9.823 ;
     RECT  7.056 9.041 7.074 9.859 ;
     RECT  6.84 9.859 7.074 9.883 ;
     RECT  9.144 9.815 9.162 9.883 ;
     RECT  54.036 9.355 54.846 9.895 ;
     RECT  6.84 9.883 7.614 9.931 ;
     RECT  10.584 9.751 11.394 9.931 ;
     RECT  25.164 9.787 27.537 9.931 ;
     RECT  47.772 9.275 47.79 9.931 ;
     RECT  54.036 9.895 55.566 9.965 ;
     RECT  30.564 9.751 31.158 10.013 ;
     RECT  6.732 9.931 7.614 10.021 ;
     RECT  34.92 9.419 35.37 10.021 ;
     RECT  9.144 9.883 9.702 10.049 ;
     RECT  69.732 9.653 72.846 10.049 ;
     RECT  25.02 9.931 27.537 10.061 ;
     RECT  18 9.787 18.846 10.085 ;
     RECT  56.34 9.823 56.574 10.085 ;
     RECT  57.996 9.437 58.806 10.085 ;
     RECT  54.036 9.965 54.882 10.093 ;
     RECT  65.055 9.653 65.337 10.093 ;
     RECT  10.476 9.931 11.394 10.121 ;
     RECT  19.656 9.787 19.746 10.121 ;
     RECT  52.524 9.589 52.794 10.121 ;
     RECT  56.556 10.085 56.574 10.121 ;
     RECT  21.312 9.779 22.842 10.129 ;
     RECT  0.036 9.067 1.206 10.157 ;
     RECT  58.032 10.085 58.806 10.157 ;
     RECT  46.728 9.677 46.854 10.165 ;
     RECT  47.772 9.931 47.826 10.165 ;
     RECT  21.312 10.129 22.878 10.171 ;
     RECT  14.832 9.823 16.737 10.193 ;
     RECT  21.312 10.171 23.13 10.193 ;
     RECT  34.92 10.021 36.054 10.193 ;
     RECT  38.016 9.689 38.646 10.193 ;
     RECT  46.728 10.165 47.826 10.193 ;
     RECT  58.068 10.157 58.806 10.193 ;
     RECT  39.888 9.739 39.906 10.201 ;
     RECT  42.912 9.617 43.737 10.201 ;
     RECT  44.532 9.979 44.55 10.201 ;
     RECT  52.668 10.121 52.794 10.201 ;
     RECT  53.568 10.093 54.882 10.201 ;
     RECT  52.668 10.201 54.882 10.229 ;
     RECT  56.952 10.123 57.258 10.229 ;
     RECT  42.912 10.201 44.55 10.253 ;
     RECT  57.024 10.229 57.042 10.253 ;
     RECT  34.056 9.823 34.074 10.291 ;
     RECT  34.92 10.193 35.406 10.291 ;
     RECT  50.688 9.275 50.886 10.291 ;
     RECT  58.464 10.193 58.806 10.291 ;
     RECT  60.984 9.553 61.002 10.291 ;
     RECT  68.22 9.509 68.238 10.291 ;
     RECT  32.655 9.341 32.937 10.315 ;
     RECT  21.672 10.193 23.13 10.319 ;
     RECT  33.696 10.291 35.406 10.319 ;
     RECT  32.22 10.315 32.937 10.327 ;
     RECT  33.696 10.319 35.37 10.327 ;
     RECT  39.888 10.201 39.978 10.327 ;
     RECT  60.984 10.291 61.074 10.327 ;
     RECT  62.352 9.677 62.946 10.327 ;
     RECT  39.816 10.327 39.978 10.355 ;
     RECT  52.74 10.229 54.882 10.355 ;
     RECT  6.732 10.021 7.902 10.363 ;
     RECT  29.088 9.689 29.178 10.363 ;
     RECT  36.792 9.617 37.278 10.363 ;
     RECT  38.016 10.193 38.337 10.363 ;
     RECT  45.324 9.931 45.666 10.399 ;
     RECT  61.992 10.327 62.946 10.399 ;
     RECT  58.464 10.291 58.842 10.411 ;
     RECT  23.904 9.751 23.922 10.427 ;
     RECT  40.824 10.201 40.842 10.427 ;
     RECT  58.464 10.411 58.914 10.435 ;
     RECT  59.655 9.545 59.937 10.435 ;
     RECT  60.984 10.327 61.254 10.435 ;
     RECT  61.992 10.399 63.774 10.435 ;
     RECT  52.776 10.355 54.882 10.445 ;
     RECT  14.832 10.193 15.318 10.463 ;
     RECT  46.728 10.193 47.322 10.463 ;
     RECT  53.892 10.445 54.882 10.463 ;
     RECT  10.836 10.121 11.394 10.471 ;
     RECT  18.288 10.085 18.846 10.471 ;
     RECT  19.656 10.121 19.71 10.471 ;
     RECT  30.78 10.013 31.158 10.471 ;
     RECT  32.22 10.327 35.37 10.471 ;
     RECT  58.464 10.435 59.937 10.471 ;
     RECT  60.984 10.435 63.774 10.471 ;
     RECT  18.288 10.471 19.71 10.499 ;
     RECT  5.655 8.621 5.937 10.507 ;
     RECT  6.732 10.363 8.082 10.507 ;
     RECT  16.2 10.193 16.737 10.507 ;
     RECT  2.232 9.389 2.286 10.555 ;
     RECT  3.096 10.315 3.114 10.555 ;
     RECT  5.655 10.507 8.082 10.555 ;
     RECT  68.22 10.291 68.634 10.555 ;
     RECT  2.232 10.555 3.114 10.561 ;
     RECT  10.836 10.471 11.862 10.561 ;
     RECT  13.068 10.327 13.086 10.561 ;
     RECT  25.02 10.061 25.866 10.561 ;
     RECT  39.816 10.355 39.834 10.561 ;
     RECT  42.912 10.253 43.974 10.561 ;
     RECT  18.288 10.499 19.674 10.589 ;
     RECT  30.78 10.471 35.37 10.589 ;
     RECT  39.384 10.561 39.834 10.589 ;
     RECT  2.232 10.561 3.186 10.597 ;
     RECT  5.544 10.555 8.082 10.597 ;
     RECT  8.892 10.561 8.91 10.597 ;
     RECT  16.2 10.507 16.83 10.597 ;
     RECT  42.84 10.561 43.974 10.597 ;
     RECT  69.732 10.049 72.81 10.603 ;
     RECT  18.288 10.589 19.494 10.625 ;
     RECT  28.512 10.363 29.178 10.633 ;
     RECT  39.384 10.589 39.474 10.637 ;
     RECT  65.055 10.093 65.79 10.651 ;
     RECT  66.6 9.751 66.906 10.651 ;
     RECT  31.716 10.589 35.37 10.661 ;
     RECT  39.384 10.637 39.402 10.661 ;
     RECT  10.836 10.561 12.258 10.685 ;
     RECT  36.792 10.363 38.337 10.685 ;
     RECT  58.464 10.471 63.774 10.685 ;
     RECT  67.788 10.555 68.634 10.685 ;
     RECT  37.116 10.685 38.337 10.697 ;
     RECT  54.036 10.463 54.882 10.697 ;
     RECT  58.464 10.685 63.63 10.697 ;
     RECT  4.176 10.633 4.194 10.705 ;
     RECT  0.036 10.157 1.17 10.733 ;
     RECT  10.836 10.685 12.186 10.733 ;
     RECT  28.512 10.633 29.25 10.733 ;
     RECT  32.076 10.661 35.37 10.733 ;
     RECT  54.072 10.697 54.882 10.733 ;
     RECT  37.296 10.697 38.337 10.781 ;
     RECT  52.776 10.445 53.046 10.781 ;
     RECT  50.688 10.291 51.174 10.795 ;
     RECT  58.464 10.697 61.074 10.829 ;
     RECT  24.696 10.561 25.866 10.831 ;
     RECT  26.64 10.061 27.537 10.831 ;
     RECT  28.512 10.733 29.142 10.831 ;
     RECT  30.78 10.589 30.87 10.831 ;
     RECT  45.036 10.399 45.666 10.831 ;
     RECT  50.544 10.795 51.174 10.831 ;
     RECT  54.255 10.733 54.882 10.831 ;
     RECT  5.544 10.597 8.91 10.843 ;
     RECT  50.544 10.831 51.354 10.843 ;
     RECT  61.848 10.697 63.63 10.859 ;
     RECT  13.032 10.561 13.086 10.867 ;
     RECT  18.288 10.625 18.882 10.867 ;
     RECT  24.696 10.831 27.537 10.867 ;
     RECT  50.544 10.843 51.462 10.867 ;
     RECT  65.055 10.651 66.906 10.867 ;
     RECT  67.788 10.685 68.454 10.867 ;
     RECT  10.836 10.733 11.337 10.891 ;
     RECT  5.508 10.843 8.91 10.903 ;
     RECT  69.372 10.603 72.81 10.903 ;
     RECT  13.032 10.867 13.698 10.931 ;
     RECT  45.036 10.831 46.242 10.931 ;
     RECT  2.088 10.597 3.186 10.939 ;
     RECT  16.2 10.597 16.902 10.939 ;
     RECT  61.848 10.859 61.938 10.967 ;
     RECT  38.055 10.781 38.337 10.975 ;
     RECT  42.768 10.597 43.974 10.975 ;
     RECT  58.464 10.829 60.642 10.975 ;
     RECT  13.104 10.931 13.698 11.003 ;
     RECT  1.44 10.939 3.294 11.011 ;
     RECT  4.104 10.705 4.194 11.011 ;
     RECT  13.176 11.003 13.698 11.011 ;
     RECT  14.832 10.463 15.102 11.011 ;
     RECT  42.768 10.975 44.01 11.011 ;
     RECT  47.304 10.463 47.322 11.011 ;
     RECT  9.864 10.471 9.882 11.035 ;
     RECT  10.692 10.891 11.337 11.035 ;
     RECT  18.216 10.867 18.882 11.039 ;
     RECT  58.14 10.975 60.642 11.039 ;
     RECT  62.712 10.859 63.63 11.039 ;
     RECT  65.055 10.867 68.454 11.039 ;
     RECT  69.192 10.903 72.81 11.039 ;
     RECT  47.304 11.011 47.79 11.069 ;
     RECT  5.328 10.903 8.91 11.083 ;
     RECT  55.98 10.831 55.998 11.083 ;
     RECT  1.44 11.011 4.194 11.101 ;
     RECT  16.2 10.939 17.262 11.101 ;
     RECT  18.216 11.039 18.846 11.101 ;
     RECT  42.156 11.011 44.01 11.101 ;
     RECT  55.98 11.083 56.502 11.101 ;
     RECT  1.44 11.101 4.23 11.117 ;
     RECT  13.176 11.011 15.102 11.129 ;
     RECT  15.876 11.101 17.262 11.129 ;
     RECT  38.055 10.975 38.934 11.129 ;
     RECT  59.655 11.039 60.642 11.129 ;
     RECT  61.848 10.967 61.866 11.129 ;
     RECT  65.055 11.039 68.202 11.129 ;
     RECT  50.544 10.867 51.894 11.137 ;
     RECT  24.588 10.867 27.537 11.165 ;
     RECT  5.184 11.083 8.91 11.173 ;
     RECT  21.672 10.319 22.914 11.173 ;
     RECT  42.156 11.101 44.082 11.173 ;
     RECT  65.055 11.129 66.798 11.173 ;
     RECT  5.04 11.173 8.91 11.179 ;
     RECT  47.772 11.069 47.79 11.201 ;
     RECT  55.98 11.101 56.646 11.201 ;
     RECT  63.144 11.039 63.63 11.201 ;
     RECT  5.04 11.179 8.946 11.213 ;
     RECT  25.236 11.165 27.537 11.237 ;
     RECT  56.34 11.201 56.646 11.237 ;
     RECT  9.864 11.035 11.337 11.245 ;
     RECT  50.508 11.137 51.894 11.245 ;
     RECT  5.04 11.213 7.074 11.261 ;
     RECT  36.36 10.831 36.378 11.273 ;
     RECT  7.956 11.213 8.946 11.281 ;
     RECT  9.792 11.245 11.337 11.281 ;
     RECT  21.672 11.173 22.95 11.281 ;
     RECT  54.255 10.831 55.206 11.281 ;
     RECT  5.04 11.261 6.966 11.309 ;
     RECT  25.308 11.237 27.537 11.309 ;
     RECT  32.544 10.733 35.298 11.309 ;
     RECT  45.036 10.931 45.198 11.309 ;
     RECT  50.508 11.245 52.434 11.309 ;
     RECT  58.14 11.039 58.878 11.309 ;
     RECT  64.944 11.173 66.798 11.309 ;
     RECT  21.528 11.281 22.95 11.323 ;
     RECT  7.956 11.281 11.337 11.357 ;
     RECT  50.508 11.309 51.966 11.357 ;
     RECT  46.116 10.931 46.242 11.371 ;
     RECT  46.98 11.245 46.998 11.371 ;
     RECT  2.016 11.117 4.23 11.399 ;
     RECT  7.956 11.357 8.55 11.399 ;
     RECT  9.432 11.357 11.337 11.399 ;
     RECT  12.168 10.733 12.186 11.399 ;
     RECT  13.68 11.129 14.958 11.399 ;
     RECT  21.528 11.323 22.986 11.399 ;
     RECT  23.76 11.137 23.778 11.399 ;
     RECT  25.308 11.309 25.47 11.399 ;
     RECT  32.616 11.309 35.298 11.399 ;
     RECT  50.508 11.357 51.138 11.399 ;
     RECT  63.216 11.201 63.63 11.399 ;
     RECT  69.768 11.039 72.81 11.405 ;
     RECT  30.132 10.831 30.87 11.407 ;
     RECT  63.576 11.399 63.63 11.407 ;
     RECT  67.824 11.129 68.202 11.435 ;
     RECT  40.392 11.371 40.41 11.443 ;
     RECT  41.148 11.323 41.166 11.443 ;
     RECT  42.012 11.173 44.082 11.443 ;
     RECT  0.036 10.733 0.63 11.467 ;
     RECT  9.72 11.399 11.337 11.471 ;
     RECT  40.392 11.443 44.082 11.471 ;
     RECT  56.34 11.237 56.358 11.471 ;
     RECT  26.208 11.309 27.537 11.479 ;
     RECT  28.332 10.831 29.142 11.479 ;
     RECT  63.576 11.407 63.702 11.479 ;
     RECT  64.944 11.309 65.538 11.479 ;
     RECT  0.036 11.467 0.918 11.507 ;
     RECT  58.14 11.309 58.806 11.507 ;
     RECT  34.344 11.399 35.298 11.515 ;
     RECT  15.876 11.129 17.118 11.543 ;
     RECT  18.036 11.101 18.846 11.543 ;
     RECT  26.208 11.479 29.286 11.543 ;
     RECT  5.04 11.309 5.937 11.551 ;
     RECT  7.956 11.399 7.974 11.579 ;
     RECT  34.344 11.515 35.478 11.579 ;
     RECT  21.855 11.399 22.842 11.597 ;
     RECT  40.392 11.471 41.634 11.597 ;
     RECT  19.728 11.407 19.746 11.641 ;
     RECT  40.392 11.597 41.454 11.641 ;
     RECT  42.408 11.471 44.082 11.641 ;
     RECT  10.548 11.471 11.337 11.669 ;
     RECT  26.676 11.543 29.286 11.669 ;
     RECT  30.06 11.407 30.87 11.669 ;
     RECT  38.055 11.129 38.898 11.669 ;
     RECT  39.96 11.641 41.454 11.669 ;
     RECT  2.016 11.399 2.862 11.705 ;
     RECT  18.144 11.543 18.846 11.705 ;
     RECT  32.616 11.399 33.606 11.705 ;
     RECT  41.148 11.669 41.454 11.705 ;
     RECT  30.06 11.669 30.438 11.741 ;
     RECT  25.308 11.399 25.398 11.777 ;
     RECT  34.38 11.579 35.478 11.777 ;
     RECT  18.432 11.705 18.846 11.785 ;
     RECT  45.18 11.309 45.198 11.785 ;
     RECT  46.116 11.371 46.998 11.785 ;
     RECT  58.14 11.507 58.734 11.785 ;
     RECT  63.576 11.479 63.738 11.785 ;
     RECT  64.656 11.479 65.538 11.785 ;
     RECT  4.932 11.551 5.937 11.813 ;
     RECT  45.18 11.785 46.998 11.821 ;
     RECT  19.656 11.641 19.746 11.849 ;
     RECT  32.616 11.705 32.994 11.849 ;
     RECT  38.055 11.669 38.862 11.849 ;
     RECT  41.148 11.705 41.382 11.849 ;
     RECT  50.508 11.399 50.85 11.851 ;
     RECT  48.855 9.689 49.137 11.899 ;
     RECT  49.968 11.851 50.85 11.899 ;
     RECT  57.708 11.785 58.734 11.911 ;
     RECT  25.38 11.777 25.398 11.939 ;
     RECT  34.38 11.777 35.154 11.939 ;
     RECT  35.928 11.821 35.982 11.939 ;
     RECT  41.148 11.849 41.166 11.939 ;
     RECT  42.408 11.641 44.406 11.939 ;
     RECT  45.18 11.821 47.502 11.939 ;
     RECT  18.432 11.785 18.918 11.975 ;
     RECT  26.784 11.669 29.286 11.981 ;
     RECT  57.564 11.911 58.734 11.981 ;
     RECT  10.836 11.669 11.337 11.983 ;
     RECT  14.832 11.399 14.958 11.983 ;
     RECT  68.184 11.435 68.202 11.983 ;
     RECT  28.8 11.981 29.286 11.995 ;
     RECT  30.06 11.741 30.222 11.995 ;
     RECT  16.308 11.543 17.118 12.011 ;
     RECT  46.152 11.939 47.358 12.011 ;
     RECT  18.576 11.975 18.918 12.029 ;
     RECT  51.876 11.357 51.966 12.043 ;
     RECT  66.276 11.309 66.798 12.043 ;
     RECT  35.964 11.939 35.982 12.055 ;
     RECT  2.016 11.705 2.25 12.091 ;
     RECT  12.312 11.821 12.33 12.091 ;
     RECT  13.68 11.399 13.77 12.091 ;
     RECT  45.18 11.939 45.342 12.091 ;
     RECT  51.876 12.043 52.29 12.091 ;
     RECT  0.036 11.507 0.846 12.119 ;
     RECT  28.8 11.995 30.222 12.119 ;
     RECT  42.408 11.939 44.226 12.119 ;
     RECT  46.476 12.011 47.358 12.119 ;
     RECT  66.276 12.043 66.906 12.119 ;
     RECT  3.96 11.399 4.014 12.181 ;
     RECT  14.832 11.983 14.994 12.181 ;
     RECT  59.655 11.129 60.534 12.181 ;
     RECT  38.055 11.849 38.79 12.209 ;
     RECT  59.655 12.181 60.858 12.209 ;
     RECT  60.732 12.209 60.858 12.221 ;
     RECT  18.756 12.029 18.918 12.235 ;
     RECT  1.656 12.091 2.25 12.245 ;
     RECT  34.596 11.939 35.082 12.245 ;
     RECT  42.768 12.119 44.226 12.245 ;
     RECT  66.276 12.119 66.834 12.245 ;
     RECT  10.836 11.983 11.538 12.253 ;
     RECT  12.312 12.091 12.474 12.253 ;
     RECT  14.832 12.181 15.03 12.253 ;
     RECT  20.952 12.091 20.97 12.253 ;
     RECT  54.255 11.281 55.458 12.253 ;
     RECT  62.748 12.139 62.766 12.253 ;
     RECT  63.576 11.785 65.538 12.253 ;
     RECT  69.84 11.405 72.81 12.253 ;
     RECT  42.768 12.245 43.83 12.269 ;
     RECT  48.855 11.899 50.85 12.269 ;
     RECT  49.896 12.269 50.85 12.317 ;
     RECT  3.96 12.181 4.086 12.325 ;
     RECT  14.832 12.253 15.39 12.325 ;
     RECT  16.308 12.011 16.737 12.325 ;
     RECT  20.952 12.253 21.006 12.325 ;
     RECT  50.472 12.317 50.85 12.325 ;
     RECT  51.876 12.091 52.974 12.325 ;
     RECT  38.055 12.209 38.682 12.353 ;
     RECT  3.6 12.325 4.086 12.361 ;
     RECT  9.54 12.253 9.558 12.361 ;
     RECT  13.392 12.091 13.77 12.361 ;
     RECT  62.712 12.253 65.538 12.361 ;
     RECT  66.276 12.245 66.798 12.361 ;
     RECT  50.472 12.325 52.974 12.389 ;
     RECT  62.712 12.361 66.798 12.389 ;
     RECT  45.036 12.091 45.342 12.413 ;
     RECT  9.54 12.361 9.846 12.451 ;
     RECT  32.616 11.849 32.937 12.451 ;
     RECT  51.552 12.389 52.974 12.451 ;
     RECT  54.072 12.253 55.458 12.451 ;
     RECT  3.42 12.361 4.554 12.479 ;
     RECT  46.836 12.119 47.358 12.479 ;
     RECT  51.552 12.451 55.458 12.479 ;
     RECT  60.732 12.221 60.75 12.479 ;
     RECT  62.712 12.389 65.934 12.479 ;
     RECT  9.54 12.451 9.918 12.487 ;
     RECT  10.836 12.253 12.474 12.487 ;
     RECT  13.248 12.361 14.022 12.487 ;
     RECT  68.184 11.983 68.742 12.487 ;
     RECT  45.036 12.413 45.306 12.509 ;
     RECT  53.424 12.479 55.458 12.509 ;
     RECT  20.232 12.325 21.006 12.515 ;
     RECT  45.036 12.509 45.27 12.515 ;
     RECT  54.072 12.509 55.458 12.515 ;
     RECT  56.232 12.361 56.61 12.515 ;
     RECT  32.04 12.451 32.937 12.523 ;
     RECT  54.255 12.515 55.458 12.523 ;
     RECT  10.836 12.487 14.022 12.551 ;
     RECT  45.036 12.515 45.126 12.551 ;
     RECT  47.232 12.479 47.358 12.551 ;
     RECT  50.472 12.389 50.562 12.551 ;
     RECT  51.588 12.479 52.254 12.551 ;
     RECT  21.855 11.597 22.806 12.559 ;
     RECT  68.076 12.487 68.742 12.559 ;
     RECT  69.48 12.253 72.81 12.559 ;
     RECT  31.968 12.523 32.937 12.595 ;
     RECT  18.756 12.235 19.386 12.631 ;
     RECT  20.232 12.515 20.502 12.631 ;
     RECT  21.855 12.559 22.95 12.631 ;
     RECT  25.596 12.559 25.614 12.631 ;
     RECT  29.016 12.119 30.222 12.631 ;
     RECT  31.068 12.559 31.086 12.631 ;
     RECT  31.968 12.595 32.994 12.631 ;
     RECT  58.14 11.981 58.734 12.631 ;
     RECT  59.655 12.209 59.937 12.631 ;
     RECT  9.468 12.487 9.918 12.659 ;
     RECT  21.855 12.631 23.13 12.721 ;
     RECT  25.596 12.631 25.65 12.721 ;
     RECT  29.016 12.631 32.994 12.721 ;
     RECT  35.964 12.055 36.054 12.721 ;
     RECT  1.764 12.245 2.25 12.749 ;
     RECT  12.636 12.551 14.022 12.749 ;
     RECT  29.016 12.721 33.426 12.749 ;
     RECT  26.784 11.981 27.63 12.757 ;
     RECT  12.636 12.749 13.086 12.785 ;
     RECT  58.14 12.631 59.937 12.785 ;
     RECT  3.6 12.479 4.554 12.829 ;
     RECT  21.42 12.721 23.166 12.829 ;
     RECT  31.788 12.749 33.426 12.829 ;
     RECT  29.016 12.749 30.87 12.857 ;
     RECT  21.42 12.829 23.418 12.859 ;
     RECT  24.516 12.829 24.534 12.859 ;
     RECT  31.788 12.829 33.462 12.859 ;
     RECT  39.96 11.669 39.978 12.865 ;
     RECT  54.255 12.523 55.89 12.893 ;
     RECT  68.076 12.559 72.81 12.893 ;
     RECT  14.832 12.325 16.737 12.901 ;
     RECT  21.42 12.859 24.534 12.901 ;
     RECT  25.524 12.721 25.65 12.901 ;
     RECT  29.016 12.857 30.798 12.929 ;
     RECT  42.768 12.269 43.737 12.929 ;
     RECT  21.42 12.901 25.65 12.941 ;
     RECT  58.284 12.785 59.937 12.941 ;
     RECT  1.872 12.749 2.25 12.955 ;
     RECT  6.84 11.309 6.858 12.955 ;
     RECT  26.784 12.757 27.81 12.991 ;
     RECT  29.016 12.929 29.826 12.991 ;
     RECT  35.712 12.721 36.054 12.991 ;
     RECT  48.855 12.269 49.137 12.991 ;
     RECT  21.42 12.941 22.41 13.019 ;
     RECT  23.4 12.941 25.65 13.019 ;
     RECT  26.784 12.991 29.826 13.019 ;
     RECT  30.564 12.929 30.798 13.019 ;
     RECT  56.736 12.865 56.754 13.019 ;
     RECT  58.68 12.941 59.937 13.019 ;
     RECT  68.076 12.893 69.102 13.019 ;
     RECT  5.544 11.813 5.937 13.027 ;
     RECT  31.788 12.859 33.714 13.027 ;
     RECT  34.596 12.245 34.794 13.027 ;
     RECT  35.604 12.991 36.054 13.027 ;
     RECT  14.22 12.901 16.737 13.037 ;
     RECT  21.42 13.019 22.266 13.037 ;
     RECT  62.712 12.479 65.337 13.037 ;
     RECT  39.96 12.865 40.338 13.051 ;
     RECT  47.772 12.991 47.934 13.051 ;
     RECT  48.708 12.991 49.137 13.051 ;
     RECT  62.712 13.037 63.27 13.051 ;
     RECT  14.832 13.037 16.737 13.055 ;
     RECT  18.756 12.631 20.502 13.055 ;
     RECT  25.416 13.019 25.65 13.055 ;
     RECT  30.564 13.019 30.654 13.055 ;
     RECT  31.788 13.027 36.054 13.055 ;
     RECT  47.772 13.051 49.137 13.055 ;
     RECT  12.636 12.785 12.762 13.085 ;
     RECT  18.756 13.055 20.034 13.091 ;
     RECT  23.94 13.019 24.534 13.091 ;
     RECT  39.78 13.051 40.338 13.091 ;
     RECT  55.872 12.893 55.89 13.091 ;
     RECT  59.256 13.019 59.937 13.091 ;
     RECT  62.424 13.051 63.27 13.091 ;
     RECT  10.836 12.551 11.337 13.099 ;
     RECT  26.784 13.019 29.358 13.099 ;
     RECT  66.708 12.389 66.798 13.099 ;
     RECT  5.544 13.027 5.958 13.135 ;
     RECT  6.84 12.955 7.002 13.135 ;
     RECT  36.9 13.099 36.918 13.135 ;
     RECT  62.424 13.091 63.162 13.135 ;
     RECT  36.828 13.135 37.278 13.147 ;
     RECT  38.055 12.353 38.337 13.147 ;
     RECT  0.036 12.119 0.774 13.171 ;
     RECT  3.6 12.829 4.662 13.171 ;
     RECT  5.544 13.135 7.002 13.171 ;
     RECT  10.692 13.099 11.337 13.171 ;
     RECT  32.472 13.055 36.054 13.171 ;
     RECT  36.828 13.147 38.337 13.171 ;
     RECT  40.212 13.091 40.338 13.171 ;
     RECT  66.708 13.099 66.834 13.171 ;
     RECT  48.384 13.055 49.137 13.181 ;
     RECT  68.976 13.019 69.102 13.199 ;
     RECT  66.708 13.171 66.906 13.261 ;
     RECT  14.832 13.055 15.174 13.289 ;
     RECT  25.776 13.099 29.358 13.289 ;
     RECT  39.456 13.099 39.474 13.289 ;
     RECT  45.036 12.551 45.054 13.289 ;
     RECT  48.744 13.181 49.137 13.289 ;
     RECT  21.42 13.037 22.137 13.297 ;
     RECT  24.48 13.091 24.534 13.325 ;
     RECT  32.472 13.171 38.337 13.325 ;
     RECT  52.236 12.551 52.254 13.325 ;
     RECT  62.352 13.135 63.162 13.325 ;
     RECT  1.872 12.955 2.862 13.333 ;
     RECT  3.6 13.171 7.038 13.333 ;
     RECT  40.212 13.171 41.022 13.361 ;
     RECT  59.328 13.091 59.937 13.373 ;
     RECT  1.872 13.333 7.038 13.387 ;
     RECT  17.892 13.261 17.91 13.405 ;
     RECT  18.756 13.091 19.89 13.405 ;
     RECT  21.348 13.297 22.137 13.405 ;
     RECT  60.984 13.135 61.002 13.469 ;
     RECT  8.064 13.441 8.082 13.517 ;
     RECT  0.036 13.171 1.026 13.531 ;
     RECT  1.872 13.387 7.29 13.531 ;
     RECT  0.036 13.531 7.29 13.559 ;
     RECT  17.892 13.405 19.89 13.559 ;
     RECT  34.2 13.325 38.337 13.559 ;
     RECT  40.284 13.361 41.022 13.559 ;
     RECT  57.024 13.135 57.546 13.559 ;
     RECT  17.892 13.559 19.638 13.565 ;
     RECT  3.6 13.559 7.29 13.595 ;
     RECT  9.108 13.441 9.126 13.595 ;
     RECT  17.892 13.565 18.27 13.595 ;
     RECT  19.008 13.565 19.638 13.595 ;
     RECT  66.708 13.261 67.842 13.595 ;
     RECT  3.6 13.595 4.59 13.613 ;
     RECT  5.328 13.595 7.29 13.613 ;
     RECT  14.832 13.289 14.994 13.613 ;
     RECT  18.252 13.595 18.27 13.613 ;
     RECT  15.984 13.055 16.737 13.631 ;
     RECT  35.928 13.559 38.337 13.631 ;
     RECT  40.392 13.559 41.022 13.631 ;
     RECT  57.096 13.559 57.114 13.631 ;
     RECT  9.972 13.171 11.337 13.639 ;
     RECT  25.776 13.289 27.537 13.661 ;
     RECT  26.784 13.661 27.537 13.667 ;
     RECT  36.612 13.631 38.337 13.667 ;
     RECT  66.708 13.595 67.662 13.667 ;
     RECT  5.328 13.613 5.937 13.709 ;
     RECT  6.84 13.613 7.29 13.711 ;
     RECT  20.772 13.405 22.137 13.801 ;
     RECT  9.468 13.639 11.337 13.829 ;
     RECT  14.868 13.613 14.994 13.829 ;
     RECT  34.2 13.559 35.154 13.829 ;
     RECT  39.24 13.291 39.258 13.829 ;
     RECT  66.708 13.667 66.726 13.829 ;
     RECT  54.255 12.893 55.062 13.837 ;
     RECT  64.188 13.037 65.337 13.837 ;
     RECT  40.392 13.631 40.41 13.853 ;
     RECT  9.54 13.829 11.337 13.865 ;
     RECT  36.792 13.667 38.337 13.865 ;
     RECT  28.296 13.289 29.358 13.873 ;
     RECT  48.855 13.289 49.137 13.873 ;
     RECT  6.84 13.711 7.47 13.901 ;
     RECT  32.472 13.325 32.994 13.901 ;
     RECT  58.032 13.675 58.158 13.909 ;
     RECT  62.712 13.325 63.162 13.909 ;
     RECT  10.224 13.865 11.337 13.937 ;
     RECT  34.38 13.829 35.154 13.937 ;
     RECT  46.188 13.909 46.206 13.945 ;
     RECT  61.884 13.837 61.974 13.945 ;
     RECT  68.976 13.199 69.03 13.945 ;
     RECT  69.876 12.893 72.81 13.945 ;
     RECT  3.888 13.613 4.59 13.973 ;
     RECT  67.644 13.667 67.662 13.973 ;
     RECT  20.664 13.801 22.137 13.981 ;
     RECT  62.712 13.909 63.27 13.981 ;
     RECT  64.188 13.837 65.358 13.981 ;
     RECT  0.036 13.559 2.862 13.997 ;
     RECT  24.516 13.325 24.534 14.009 ;
     RECT  62.712 13.981 65.358 14.009 ;
     RECT  26.928 13.667 27.537 14.011 ;
     RECT  28.296 13.873 29.574 14.011 ;
     RECT  6.84 13.901 7.002 14.099 ;
     RECT  25.776 13.661 25.794 14.099 ;
     RECT  26.928 14.011 29.574 14.099 ;
     RECT  34.38 13.937 34.794 14.099 ;
     RECT  36.792 13.865 37.062 14.099 ;
     RECT  41.364 13.675 41.454 14.099 ;
     RECT  44.496 13.711 44.586 14.099 ;
     RECT  45.576 13.945 46.206 14.099 ;
     RECT  47.088 14.059 47.106 14.099 ;
     RECT  55.944 13.945 55.962 14.099 ;
     RECT  61.56 13.945 61.974 14.099 ;
     RECT  48.855 13.873 49.734 14.107 ;
     RECT  14.868 13.829 14.958 14.135 ;
     RECT  26.928 14.099 29.106 14.135 ;
     RECT  58.032 13.909 58.194 14.135 ;
     RECT  44.64 14.107 44.658 14.141 ;
     RECT  32.472 13.901 32.937 14.143 ;
     RECT  54.255 13.837 55.17 14.143 ;
     RECT  3.888 13.973 4.554 14.171 ;
     RECT  41.364 14.099 41.382 14.171 ;
     RECT  48.744 14.107 50.238 14.171 ;
     RECT  68.976 13.945 72.81 14.179 ;
     RECT  54.255 14.143 55.71 14.203 ;
     RECT  61.56 14.099 61.902 14.203 ;
     RECT  2.232 13.997 2.862 14.207 ;
     RECT  10.26 13.937 11.337 14.215 ;
     RECT  48.744 14.171 49.194 14.215 ;
     RECT  44.784 14.143 44.802 14.237 ;
     RECT  36.792 14.099 37.026 14.243 ;
     RECT  54.144 14.203 55.71 14.243 ;
     RECT  58.032 14.135 58.158 14.243 ;
     RECT  20.376 13.981 22.137 14.251 ;
     RECT  30.312 13.873 30.33 14.251 ;
     RECT  43.344 12.929 43.737 14.251 ;
     RECT  50.04 14.171 50.238 14.251 ;
     RECT  59.655 13.373 59.937 14.251 ;
     RECT  25.056 14.203 25.686 14.279 ;
     RECT  14.004 13.981 14.022 14.341 ;
     RECT  48.528 14.215 49.194 14.341 ;
     RECT  60.948 14.203 61.902 14.341 ;
     RECT  25.38 14.279 25.686 14.369 ;
     RECT  28.296 14.135 29.106 14.369 ;
     RECT  30.312 14.251 30.402 14.369 ;
     RECT  42.768 14.251 43.737 14.369 ;
     RECT  50.04 14.251 50.85 14.369 ;
     RECT  10.26 14.215 11.43 14.381 ;
     RECT  54.255 14.243 55.71 14.405 ;
     RECT  32.256 14.143 32.937 14.413 ;
     RECT  60.912 14.341 61.902 14.441 ;
     RECT  25.668 14.369 25.686 14.477 ;
     RECT  48.456 14.341 49.194 14.477 ;
     RECT  13.968 14.341 14.022 14.485 ;
     RECT  46.188 14.099 46.206 14.485 ;
     RECT  28.728 14.369 29.106 14.513 ;
     RECT  48.456 14.477 49.137 14.513 ;
     RECT  5.655 13.709 5.937 14.521 ;
     RECT  16.455 13.631 16.737 14.521 ;
     RECT  30.312 14.369 30.33 14.521 ;
     RECT  50.184 14.369 50.85 14.521 ;
     RECT  59.04 14.251 59.937 14.521 ;
     RECT  58.032 14.243 58.05 14.525 ;
     RECT  19.008 13.595 19.458 14.539 ;
     RECT  50.184 14.521 51.282 14.587 ;
     RECT  26.928 14.135 27.537 14.611 ;
     RECT  16.344 14.521 16.737 14.635 ;
     RECT  44.856 14.443 45.45 14.639 ;
     RECT  50.184 14.587 51.75 14.639 ;
     RECT  54.255 14.405 55.314 14.639 ;
     RECT  13.968 14.485 14.13 14.647 ;
     RECT  31.752 14.413 32.937 14.647 ;
     RECT  52.524 14.521 52.542 14.647 ;
     RECT  23.904 14.251 23.922 14.669 ;
     RECT  48.492 14.513 49.137 14.669 ;
     RECT  54.255 14.639 55.242 14.669 ;
     RECT  18.828 14.539 19.458 14.683 ;
     RECT  30.204 14.521 30.33 14.711 ;
     RECT  45.036 14.639 45.45 14.711 ;
     RECT  57.276 14.449 57.294 14.711 ;
     RECT  60.948 14.441 61.902 14.711 ;
     RECT  50.184 14.639 51.678 14.717 ;
     RECT  3.888 14.171 4.086 14.719 ;
     RECT  46.188 14.485 46.314 14.747 ;
     RECT  48.708 14.669 49.137 14.765 ;
     RECT  30.204 14.711 30.222 14.783 ;
     RECT  52.452 14.647 52.542 14.783 ;
     RECT  58.968 14.521 59.937 14.783 ;
     RECT  62.712 14.009 65.337 14.783 ;
     RECT  13.644 14.647 14.13 14.791 ;
     RECT  18.54 14.683 19.458 14.791 ;
     RECT  20.376 14.251 22.842 14.791 ;
     RECT  6.876 14.099 7.002 14.827 ;
     RECT  66.132 14.341 66.15 14.827 ;
     RECT  5.544 14.521 5.937 14.875 ;
     RECT  0.036 13.997 1.458 14.881 ;
     RECT  6.876 14.827 7.182 14.881 ;
     RECT  8.568 14.683 8.586 14.881 ;
     RECT  13.104 14.791 14.13 14.881 ;
     RECT  14.868 14.135 14.922 14.881 ;
     RECT  31.68 14.647 32.937 14.881 ;
     RECT  64.188 14.783 65.337 14.881 ;
     RECT  66.132 14.827 66.726 14.881 ;
     RECT  68.796 14.179 72.81 14.881 ;
     RECT  54.255 14.669 55.134 14.909 ;
     RECT  56.052 14.875 56.07 14.909 ;
     RECT  8.46 14.881 8.586 14.917 ;
     RECT  10.26 14.381 11.394 14.917 ;
     RECT  13.104 14.881 14.922 14.917 ;
     RECT  18.54 14.791 22.842 14.917 ;
     RECT  37.8 13.865 38.337 14.917 ;
     RECT  64.188 14.881 67.59 14.917 ;
     RECT  2.628 14.207 2.862 14.923 ;
     RECT  3.636 14.719 4.086 14.923 ;
     RECT  29.088 14.513 29.106 14.953 ;
     RECT  31.68 14.881 33.39 14.953 ;
     RECT  10.008 14.917 11.394 14.957 ;
     RECT  6.876 14.881 7.542 14.971 ;
     RECT  16.344 14.635 16.794 14.971 ;
     RECT  34.524 14.099 34.794 14.971 ;
     RECT  37.8 14.917 38.394 14.971 ;
     RECT  2.628 14.923 4.086 14.989 ;
     RECT  8.46 14.917 8.91 14.989 ;
     RECT  18.144 14.917 22.842 14.989 ;
     RECT  29.088 14.953 29.142 14.989 ;
     RECT  31.68 14.953 33.426 14.989 ;
     RECT  0.036 14.881 1.71 15.019 ;
     RECT  18.072 14.989 22.842 15.025 ;
     RECT  31.68 14.989 33.498 15.025 ;
     RECT  68.76 14.881 72.81 15.025 ;
     RECT  57.204 14.719 57.222 15.053 ;
     RECT  64.188 14.917 67.626 15.053 ;
     RECT  6.84 14.971 7.542 15.061 ;
     RECT  8.46 14.989 9.09 15.061 ;
     RECT  16.344 14.971 17.226 15.061 ;
     RECT  36.864 14.243 37.026 15.061 ;
     RECT  37.8 14.971 38.646 15.061 ;
     RECT  52.452 14.783 52.47 15.089 ;
     RECT  6.84 15.061 9.09 15.101 ;
     RECT  13.104 14.917 15.498 15.115 ;
     RECT  16.236 15.061 17.226 15.115 ;
     RECT  26.784 14.611 27.537 15.115 ;
     RECT  2.628 14.989 4.374 15.151 ;
     RECT  5.544 14.875 6.03 15.151 ;
     RECT  10.944 14.957 11.394 15.151 ;
     RECT  18.072 15.025 22.95 15.151 ;
     RECT  23.76 15.025 23.778 15.151 ;
     RECT  26.676 15.115 27.537 15.151 ;
     RECT  54.255 14.909 54.846 15.163 ;
     RECT  66.744 15.053 67.626 15.163 ;
     RECT  0.036 15.019 1.89 15.179 ;
     RECT  7.524 15.101 9.09 15.179 ;
     RECT  18.072 15.151 23.778 15.179 ;
     RECT  26.676 15.151 27.63 15.179 ;
     RECT  2.628 15.151 6.03 15.187 ;
     RECT  26.784 15.179 27.63 15.187 ;
     RECT  2.16 15.187 6.03 15.197 ;
     RECT  10.944 15.151 11.826 15.197 ;
     RECT  9.036 15.179 9.09 15.215 ;
     RECT  10.944 15.197 11.502 15.215 ;
     RECT  13.104 15.115 17.226 15.215 ;
     RECT  64.188 15.053 65.646 15.215 ;
     RECT  14.688 15.215 17.226 15.245 ;
     RECT  21.096 15.179 23.778 15.245 ;
     RECT  26.784 15.187 27.846 15.245 ;
     RECT  36.864 15.061 38.646 15.245 ;
     RECT  43.455 14.369 43.737 15.259 ;
     RECT  7.956 15.179 8.046 15.287 ;
     RECT  10.98 15.215 11.502 15.287 ;
     RECT  53.28 14.647 53.298 15.287 ;
     RECT  27.255 15.245 27.846 15.293 ;
     RECT  36.864 15.245 38.538 15.293 ;
     RECT  57.024 15.163 57.15 15.293 ;
     RECT  66.744 15.163 67.734 15.293 ;
     RECT  2.16 15.197 4.59 15.323 ;
     RECT  9.108 15.223 9.126 15.323 ;
     RECT  14.688 15.245 16.83 15.323 ;
     RECT  21.204 15.245 23.778 15.323 ;
     RECT  68.508 15.025 72.81 15.323 ;
     RECT  10.188 14.957 10.206 15.341 ;
     RECT  4.572 15.323 4.59 15.359 ;
     RECT  66.744 15.293 67.482 15.359 ;
     RECT  14.832 15.323 16.83 15.389 ;
     RECT  27.255 15.293 27.738 15.389 ;
     RECT  36.864 15.293 38.43 15.389 ;
     RECT  31.68 15.025 33.534 15.403 ;
     RECT  42.804 15.259 43.938 15.403 ;
     RECT  21.348 15.323 23.778 15.421 ;
     RECT  34.524 14.971 34.938 15.421 ;
     RECT  62.712 14.783 63.162 15.421 ;
     RECT  5.655 15.197 6.03 15.449 ;
     RECT  8.028 15.287 8.046 15.449 ;
     RECT  45.036 14.711 45.162 15.457 ;
     RECT  42.768 15.403 43.938 15.493 ;
     RECT  60.948 14.711 61.254 15.493 ;
     RECT  62.28 15.421 63.162 15.493 ;
     RECT  13.104 15.215 13.77 15.499 ;
     RECT  42.588 15.493 44.082 15.499 ;
     RECT  9.18 15.331 9.198 15.521 ;
     RECT  36.864 15.389 38.337 15.529 ;
     RECT  50.184 14.717 51.606 15.533 ;
     RECT  36.684 15.529 38.337 15.565 ;
     RECT  50.472 15.533 51.606 15.581 ;
     RECT  21.348 15.421 23.85 15.593 ;
     RECT  40.932 15.565 40.95 15.601 ;
     RECT  42.588 15.499 44.226 15.601 ;
     RECT  50.724 15.581 51.606 15.601 ;
     RECT  59.148 14.783 59.937 15.601 ;
     RECT  60.948 15.493 63.162 15.601 ;
     RECT  64.188 15.215 65.337 15.601 ;
     RECT  42.3 15.601 44.226 15.629 ;
     RECT  31.464 15.403 33.534 15.691 ;
     RECT  54.144 15.163 54.846 15.691 ;
     RECT  68.508 15.323 69.102 15.691 ;
     RECT  2.16 15.323 3.654 15.719 ;
     RECT  18.216 15.179 19.71 15.719 ;
     RECT  50.724 15.601 51.93 15.719 ;
     RECT  69.84 15.323 72.81 15.719 ;
     RECT  31.248 15.691 33.534 15.725 ;
     RECT  18.216 15.719 19.062 15.755 ;
     RECT  42.3 15.629 44.154 15.755 ;
     RECT  48.855 14.765 49.137 15.763 ;
     RECT  59.148 15.601 65.337 15.791 ;
     RECT  46.764 15.403 46.962 15.799 ;
     RECT  18.252 15.755 19.062 15.827 ;
     RECT  42.588 15.755 44.154 15.827 ;
     RECT  34.524 15.421 35.658 15.835 ;
     RECT  23.724 15.593 23.85 15.863 ;
     RECT  50.724 15.719 51.858 15.863 ;
     RECT  31.536 15.725 33.534 15.871 ;
     RECT  14.832 15.389 16.794 15.899 ;
     RECT  18.252 15.827 18.99 15.899 ;
     RECT  29.088 14.989 29.754 15.899 ;
     RECT  50.724 15.863 51.462 15.899 ;
     RECT  59.22 15.791 65.337 15.899 ;
     RECT  50.976 15.899 50.994 15.917 ;
     RECT  0.036 15.179 1.242 15.961 ;
     RECT  12.564 15.499 13.77 15.961 ;
     RECT  34.488 15.835 35.658 15.961 ;
     RECT  36.504 15.565 38.337 15.961 ;
     RECT  48.816 15.763 49.137 15.961 ;
     RECT  54.036 15.691 54.846 15.961 ;
     RECT  11.055 15.287 11.502 15.979 ;
     RECT  12.492 15.961 13.77 15.979 ;
     RECT  27.255 15.389 27.537 15.979 ;
     RECT  46.764 15.799 47.358 15.979 ;
     RECT  29.088 15.899 29.25 15.989 ;
     RECT  31.536 15.871 33.642 15.989 ;
     RECT  45.036 15.457 45.63 15.989 ;
     RECT  59.256 15.899 65.337 15.989 ;
     RECT  40.608 15.601 40.95 15.997 ;
     RECT  48.816 15.961 49.194 15.997 ;
     RECT  66.744 15.359 67.374 15.997 ;
     RECT  31.536 15.989 33.282 16.025 ;
     RECT  46.764 15.979 47.826 16.025 ;
     RECT  48.816 15.997 49.266 16.025 ;
     RECT  26.784 15.979 27.537 16.033 ;
     RECT  40.608 15.997 40.986 16.033 ;
     RECT  54.036 15.961 55.602 16.033 ;
     RECT  0.036 15.961 1.35 16.061 ;
     RECT  11.055 15.979 13.77 16.061 ;
     RECT  57.132 15.293 57.15 16.061 ;
     RECT  29.088 15.989 29.178 16.069 ;
     RECT  30.024 15.961 30.042 16.069 ;
     RECT  40.608 16.033 41.022 16.069 ;
     RECT  40.608 16.069 41.274 16.075 ;
     RECT  11.055 16.061 11.934 16.097 ;
     RECT  5.655 15.449 5.937 16.105 ;
     RECT  13.032 16.061 13.77 16.105 ;
     RECT  14.832 15.899 14.85 16.105 ;
     RECT  30.024 16.069 30.078 16.105 ;
     RECT  66.348 15.997 67.374 16.105 ;
     RECT  68.328 15.691 69.102 16.105 ;
     RECT  2.16 15.719 3.438 16.123 ;
     RECT  5.508 16.105 5.937 16.141 ;
     RECT  24.012 16.033 24.03 16.141 ;
     RECT  26.46 16.033 27.537 16.141 ;
     RECT  66.348 16.105 69.102 16.141 ;
     RECT  69.84 15.719 72.774 16.141 ;
     RECT  34.488 15.961 38.337 16.157 ;
     RECT  1.872 16.123 3.438 16.169 ;
     RECT  40.356 16.075 41.274 16.169 ;
     RECT  54.036 16.033 55.638 16.169 ;
     RECT  54.036 16.169 55.458 16.219 ;
     RECT  19.908 15.979 20.142 16.259 ;
     RECT  45.036 15.989 45.126 16.259 ;
     RECT  61.452 15.989 65.337 16.259 ;
     RECT  66.348 16.141 72.774 16.267 ;
     RECT  2.088 16.169 3.438 16.295 ;
     RECT  5.472 16.141 5.937 16.295 ;
     RECT  52.92 15.961 52.938 16.295 ;
     RECT  28.584 16.069 29.178 16.303 ;
     RECT  48.855 16.025 49.266 16.303 ;
     RECT  21.348 15.593 22.986 16.315 ;
     RECT  28.512 16.303 29.178 16.315 ;
     RECT  13.032 16.105 14.85 16.331 ;
     RECT  34.488 16.157 36.306 16.363 ;
     RECT  40.356 16.169 41.202 16.363 ;
     RECT  9.756 16.141 10.242 16.367 ;
     RECT  28.332 16.315 29.178 16.367 ;
     RECT  40.248 16.363 41.202 16.375 ;
     RECT  9.756 16.367 9.774 16.397 ;
     RECT  48.855 16.303 49.338 16.403 ;
     RECT  11.055 16.097 11.394 16.411 ;
     RECT  20.988 16.315 22.986 16.411 ;
     RECT  13.14 16.331 14.85 16.439 ;
     RECT  30.024 16.105 30.762 16.439 ;
     RECT  66.312 16.267 72.774 16.439 ;
     RECT  13.176 16.439 13.194 16.445 ;
     RECT  19.908 16.259 19.998 16.445 ;
     RECT  26.388 16.141 27.537 16.459 ;
     RECT  28.332 16.367 29.106 16.459 ;
     RECT  4.284 16.141 4.302 16.501 ;
     RECT  31.536 16.025 31.554 16.501 ;
     RECT  26.388 16.459 29.106 16.529 ;
     RECT  30.024 16.439 30.654 16.529 ;
     RECT  48.855 16.403 49.194 16.529 ;
     RECT  61.452 16.259 61.614 16.529 ;
     RECT  62.388 16.259 65.337 16.529 ;
     RECT  26.388 16.529 27.537 16.537 ;
     RECT  39.24 16.141 39.258 16.537 ;
     RECT  40.14 16.375 41.202 16.537 ;
     RECT  62.676 16.529 65.337 16.537 ;
     RECT  30.024 16.529 30.402 16.541 ;
     RECT  34.056 16.363 36.306 16.541 ;
     RECT  37.044 16.157 38.337 16.541 ;
     RECT  39.24 16.537 41.202 16.541 ;
     RECT  18.864 15.899 18.99 16.555 ;
     RECT  42.768 15.827 43.902 16.555 ;
     RECT  19.908 16.445 19.926 16.565 ;
     RECT  15.912 15.899 16.794 16.573 ;
     RECT  20.916 16.411 22.986 16.573 ;
     RECT  0.036 16.061 0.738 16.601 ;
     RECT  20.916 16.573 23.13 16.601 ;
     RECT  28.26 16.529 29.106 16.601 ;
     RECT  24.012 16.141 24.534 16.603 ;
     RECT  62.676 16.537 65.502 16.603 ;
     RECT  66.312 16.439 66.906 16.603 ;
     RECT  21.456 16.601 23.13 16.645 ;
     RECT  23.904 16.603 24.534 16.645 ;
     RECT  59.256 15.989 60.534 16.645 ;
     RECT  15.912 16.573 17.19 16.651 ;
     RECT  42.768 16.555 44.01 16.651 ;
     RECT  39.24 16.541 39.942 16.673 ;
     RECT  15.912 16.651 17.694 16.681 ;
     RECT  39.24 16.673 39.906 16.681 ;
     RECT  67.788 16.439 72.774 16.681 ;
     RECT  18.864 16.555 19.062 16.685 ;
     RECT  58.284 16.645 60.534 16.685 ;
     RECT  5.544 16.295 5.937 16.733 ;
     RECT  67.788 16.681 72.81 16.733 ;
     RECT  21.456 16.645 24.534 16.747 ;
     RECT  15.804 16.681 17.694 16.771 ;
     RECT  18.864 16.685 18.99 16.795 ;
     RECT  37.224 16.541 38.337 16.795 ;
     RECT  39.06 16.681 39.906 16.795 ;
     RECT  21.456 16.747 25.11 16.799 ;
     RECT  26.064 16.537 27.537 16.799 ;
     RECT  58.896 16.685 60.534 16.799 ;
     RECT  32.655 16.025 33.282 16.807 ;
     RECT  42.3 16.651 44.118 16.807 ;
     RECT  10.836 16.411 11.394 16.843 ;
     RECT  46.764 16.025 47.538 16.843 ;
     RECT  62.676 16.603 66.906 16.871 ;
     RECT  42.156 16.807 44.118 16.877 ;
     RECT  58.896 16.799 58.914 16.877 ;
     RECT  62.82 16.871 66.906 16.877 ;
     RECT  57.06 16.069 57.078 16.879 ;
     RECT  53.676 16.219 55.458 16.891 ;
     RECT  14.256 16.439 14.85 16.907 ;
     RECT  62.82 16.877 65.337 16.907 ;
     RECT  9.252 16.843 9.666 16.915 ;
     RECT  14.76 16.907 14.85 16.915 ;
     RECT  15.588 16.771 17.694 16.915 ;
     RECT  34.488 16.541 36.306 16.915 ;
     RECT  62.856 16.907 65.337 16.943 ;
     RECT  40.968 16.541 41.202 16.951 ;
     RECT  42.156 16.877 43.737 16.951 ;
     RECT  50.688 16.939 50.706 16.951 ;
     RECT  53.676 16.891 55.962 16.951 ;
     RECT  57.06 16.879 57.114 16.951 ;
     RECT  29.088 16.601 29.106 16.973 ;
     RECT  45.036 16.259 45.054 16.973 ;
     RECT  37.224 16.795 39.906 16.979 ;
     RECT  66.312 16.877 66.906 16.979 ;
     RECT  7.812 16.915 7.83 16.987 ;
     RECT  52.092 16.939 52.11 17.035 ;
     RECT  2.088 16.295 2.934 17.041 ;
     RECT  5.655 16.733 5.937 17.041 ;
     RECT  6.84 16.843 6.858 17.041 ;
     RECT  10.836 16.843 11.538 17.041 ;
     RECT  53.676 16.951 56.106 17.041 ;
     RECT  7.812 16.987 8.37 17.069 ;
     RECT  26.28 16.799 27.537 17.069 ;
     RECT  34.488 16.915 36.45 17.069 ;
     RECT  40.968 16.951 43.737 17.069 ;
     RECT  46.764 16.843 47.682 17.069 ;
     RECT  50.688 16.951 51.066 17.069 ;
     RECT  51.948 17.035 52.11 17.069 ;
     RECT  52.884 16.609 52.902 17.069 ;
     RECT  53.676 17.041 56.142 17.069 ;
     RECT  57.024 16.951 57.114 17.069 ;
     RECT  66.312 16.979 66.87 17.069 ;
     RECT  53.676 17.069 55.278 17.083 ;
     RECT  26.316 17.069 27.537 17.105 ;
     RECT  28.26 16.601 28.35 17.105 ;
     RECT  34.488 17.069 35.91 17.105 ;
     RECT  41.688 17.069 43.737 17.105 ;
     RECT  53.028 17.083 55.278 17.105 ;
     RECT  56.088 17.069 56.142 17.105 ;
     RECT  56.124 17.105 56.142 17.113 ;
     RECT  14.76 16.915 17.694 17.117 ;
     RECT  15.624 17.117 17.694 17.131 ;
     RECT  18.828 16.795 18.99 17.131 ;
     RECT  46.764 17.069 47.07 17.141 ;
     RECT  10.836 17.041 11.682 17.149 ;
     RECT  56.124 17.113 56.214 17.149 ;
     RECT  15.624 17.131 18.99 17.177 ;
     RECT  34.488 17.105 35.082 17.177 ;
     RECT  2.088 17.041 3.186 17.185 ;
     RECT  3.96 16.501 4.302 17.185 ;
     RECT  59.655 16.799 60.534 17.185 ;
     RECT  56.124 17.149 56.286 17.213 ;
     RECT  2.088 17.185 4.302 17.221 ;
     RECT  5.655 17.041 6.858 17.221 ;
     RECT  9.18 16.915 9.666 17.221 ;
     RECT  53.028 17.105 55.17 17.249 ;
     RECT  30.384 16.541 30.402 17.275 ;
     RECT  10.836 17.149 12.402 17.311 ;
     RECT  30.24 17.275 30.402 17.311 ;
     RECT  31.464 16.501 31.554 17.311 ;
     RECT  37.224 16.979 39.294 17.311 ;
     RECT  5.655 17.221 7.434 17.339 ;
     RECT  30.24 17.311 31.554 17.339 ;
     RECT  35.892 17.105 35.91 17.339 ;
     RECT  53.892 17.249 55.17 17.339 ;
     RECT  56.268 17.213 56.286 17.339 ;
     RECT  2.088 17.221 4.662 17.375 ;
     RECT  10.836 17.311 12.546 17.375 ;
     RECT  26.784 17.105 27.537 17.383 ;
     RECT  28.26 17.105 28.314 17.383 ;
     RECT  12.528 17.375 12.546 17.405 ;
     RECT  21.456 16.799 25.038 17.411 ;
     RECT  2.088 17.375 4.626 17.419 ;
     RECT  5.655 17.339 6.966 17.453 ;
     RECT  9.144 17.221 9.666 17.455 ;
     RECT  20.664 17.221 20.682 17.455 ;
     RECT  21.456 17.411 23.346 17.455 ;
     RECT  30.708 17.339 31.554 17.467 ;
     RECT  1.764 17.419 4.626 17.519 ;
     RECT  67.824 16.733 72.81 17.563 ;
     RECT  32.655 16.807 33.714 17.581 ;
     RECT  34.488 17.177 34.83 17.581 ;
     RECT  6.732 17.453 6.966 17.609 ;
     RECT  15.876 17.177 18.99 17.609 ;
     RECT  24.444 17.411 25.038 17.609 ;
     RECT  30.708 17.467 31.842 17.611 ;
     RECT  32.616 17.581 34.83 17.611 ;
     RECT  0.036 16.601 0.702 17.617 ;
     RECT  6.84 17.609 6.966 17.645 ;
     RECT  30.708 17.611 34.83 17.645 ;
     RECT  62.928 16.943 65.337 17.645 ;
     RECT  48.024 17.221 48.042 17.653 ;
     RECT  48.855 16.529 49.137 17.653 ;
     RECT  9.144 17.455 9.702 17.681 ;
     RECT  30.708 17.645 31.05 17.681 ;
     RECT  47.052 17.141 47.07 17.681 ;
     RECT  67.716 17.563 72.81 17.693 ;
     RECT  37.044 17.311 39.294 17.707 ;
     RECT  48.024 17.653 49.137 17.707 ;
     RECT  20.664 17.455 23.346 17.717 ;
     RECT  18.72 17.609 18.99 17.725 ;
     RECT  58.716 17.581 58.734 17.725 ;
     RECT  59.655 17.185 61.218 17.725 ;
     RECT  15.876 17.609 17.73 17.789 ;
     RECT  41.688 17.105 41.814 17.837 ;
     RECT  40.644 17.803 40.662 17.851 ;
     RECT  48.024 17.707 49.338 17.851 ;
     RECT  53.028 17.249 53.046 17.851 ;
     RECT  54.255 17.339 55.17 17.851 ;
     RECT  30.78 17.681 31.05 17.879 ;
     RECT  26.784 17.383 28.314 17.887 ;
     RECT  48.024 17.851 49.878 17.887 ;
     RECT  52.092 17.851 52.182 17.887 ;
     RECT  52.956 17.851 53.046 17.887 ;
     RECT  48.024 17.887 49.95 17.923 ;
     RECT  58.716 17.725 61.398 17.923 ;
     RECT  16.344 17.789 17.73 17.933 ;
     RECT  0.036 17.617 0.81 17.951 ;
     RECT  37.044 17.707 39.366 17.951 ;
     RECT  41.688 17.837 41.778 17.951 ;
     RECT  52.092 17.887 53.046 17.951 ;
     RECT  54.255 17.851 55.242 17.951 ;
     RECT  10.836 17.375 11.646 17.959 ;
     RECT  26.064 17.887 28.314 17.959 ;
     RECT  9.144 17.681 9.162 17.987 ;
     RECT  16.344 17.933 16.866 17.987 ;
     RECT  20.664 17.717 22.914 17.987 ;
     RECT  25.848 17.959 28.314 17.987 ;
     RECT  14.76 17.117 14.85 17.995 ;
     RECT  31.86 17.645 34.83 17.995 ;
     RECT  37.62 17.951 39.366 17.995 ;
     RECT  42.84 17.105 43.737 17.995 ;
     RECT  66.924 17.851 66.942 17.995 ;
     RECT  41.688 17.951 41.706 18.023 ;
     RECT  24.516 17.609 25.038 18.029 ;
     RECT  25.848 17.987 28.242 18.029 ;
     RECT  30.78 17.879 31.014 18.029 ;
     RECT  14.76 17.995 15.57 18.031 ;
     RECT  66.708 17.995 66.942 18.031 ;
     RECT  0.036 17.951 0.774 18.059 ;
     RECT  6.84 17.645 6.93 18.059 ;
     RECT  16.344 17.987 16.794 18.059 ;
     RECT  51.912 17.995 51.93 18.077 ;
     RECT  36.072 17.959 36.09 18.121 ;
     RECT  54.255 17.951 55.206 18.121 ;
     RECT  58.32 17.923 61.398 18.121 ;
     RECT  62.28 17.995 62.298 18.121 ;
     RECT  25.848 18.029 25.938 18.149 ;
     RECT  30.78 18.029 30.906 18.149 ;
     RECT  31.86 17.995 34.866 18.149 ;
     RECT  37.62 17.995 39.438 18.149 ;
     RECT  47.88 17.923 49.95 18.149 ;
     RECT  52.884 17.951 52.974 18.149 ;
     RECT  58.32 18.121 62.298 18.149 ;
     RECT  40.644 17.851 40.95 18.173 ;
     RECT  2.088 17.519 4.626 18.185 ;
     RECT  17.712 17.933 17.73 18.185 ;
     RECT  20.664 17.987 22.842 18.185 ;
     RECT  30.78 18.149 30.834 18.185 ;
     RECT  31.86 18.149 33.93 18.185 ;
     RECT  37.62 18.149 39.114 18.185 ;
     RECT  24.552 18.029 25.038 18.221 ;
     RECT  26.712 18.029 28.242 18.221 ;
     RECT  32.148 18.185 33.93 18.221 ;
     RECT  47.88 18.149 49.137 18.221 ;
     RECT  52.956 18.149 52.974 18.221 ;
     RECT  54 18.121 55.206 18.221 ;
     RECT  58.32 18.149 58.806 18.221 ;
     RECT  5.655 17.453 5.937 18.229 ;
     RECT  9.972 17.959 11.646 18.229 ;
     RECT  35.928 18.121 36.09 18.229 ;
     RECT  46.116 18.193 46.134 18.229 ;
     RECT  8.208 17.069 8.226 18.235 ;
     RECT  5.544 18.229 5.937 18.265 ;
     RECT  7.956 18.235 8.226 18.265 ;
     RECT  14.724 18.031 15.57 18.265 ;
     RECT  42.804 17.995 43.737 18.265 ;
     RECT  47.88 18.221 48.078 18.265 ;
     RECT  51.804 18.193 51.822 18.269 ;
     RECT  21.744 18.185 22.842 18.317 ;
     RECT  7.956 18.265 9.018 18.329 ;
     RECT  54.255 18.221 55.206 18.329 ;
     RECT  2.088 18.185 2.286 18.331 ;
     RECT  66.708 18.031 66.978 18.331 ;
     RECT  9.972 18.229 12.114 18.391 ;
     RECT  42.768 18.265 43.737 18.391 ;
     RECT  30.78 18.185 30.798 18.419 ;
     RECT  32.655 18.221 33.93 18.419 ;
     RECT  35.928 18.229 36.162 18.419 ;
     RECT  37.836 18.185 39.114 18.419 ;
     RECT  49.896 18.149 49.914 18.419 ;
     RECT  45.144 18.121 45.234 18.427 ;
     RECT  46.116 18.229 46.602 18.427 ;
     RECT  47.376 18.265 48.078 18.427 ;
     RECT  1.944 18.331 2.286 18.455 ;
     RECT  46.116 18.427 48.078 18.461 ;
     RECT  14.256 18.265 15.57 18.491 ;
     RECT  34.848 18.149 34.866 18.491 ;
     RECT  38.055 18.419 39.042 18.491 ;
     RECT  66.708 18.331 67.014 18.499 ;
     RECT  68.076 17.693 72.81 18.499 ;
     RECT  3.024 18.185 4.626 18.509 ;
     RECT  59.655 18.149 61.902 18.509 ;
     RECT  7.992 18.329 9.018 18.527 ;
     RECT  42.732 18.391 43.737 18.535 ;
     RECT  62.892 18.391 63.018 18.557 ;
     RECT  63.792 17.645 65.337 18.563 ;
     RECT  5.436 18.265 5.937 18.571 ;
     RECT  9.972 18.391 12.186 18.571 ;
     RECT  13.428 18.229 13.446 18.571 ;
     RECT  14.256 18.491 14.994 18.571 ;
     RECT  42.732 18.535 44.118 18.571 ;
     RECT  45.144 18.427 45.378 18.571 ;
     RECT  46.116 18.461 46.314 18.571 ;
     RECT  3.78 18.509 4.626 18.599 ;
     RECT  7.992 18.527 8.478 18.599 ;
     RECT  62.892 18.557 62.91 18.599 ;
     RECT  45.144 18.571 46.314 18.661 ;
     RECT  3.78 18.599 4.41 18.689 ;
     RECT  33.84 18.419 33.93 18.689 ;
     RECT  36.072 18.419 36.162 18.689 ;
     RECT  66.708 18.499 72.81 18.689 ;
     RECT  42.732 18.571 44.154 18.697 ;
     RECT  2.16 18.455 2.286 18.701 ;
     RECT  3.024 18.509 3.042 18.725 ;
     RECT  3.78 18.689 4.122 18.725 ;
     RECT  47.088 18.461 48.078 18.725 ;
     RECT  9.972 18.571 12.438 18.733 ;
     RECT  13.284 18.571 13.446 18.733 ;
     RECT  9.972 18.733 13.446 18.749 ;
     RECT  35.136 18.697 35.154 18.749 ;
     RECT  42.732 18.697 44.19 18.749 ;
     RECT  45.108 18.661 46.314 18.749 ;
     RECT  0.036 18.059 0.702 18.761 ;
     RECT  5.4 18.571 5.937 18.761 ;
     RECT  9.972 18.749 11.394 18.761 ;
     RECT  14.22 18.571 14.994 18.761 ;
     RECT  45.108 18.749 45.522 18.761 ;
     RECT  47.664 18.725 48.078 18.761 ;
     RECT  18.72 17.725 19.422 18.769 ;
     RECT  20.34 18.235 20.502 18.769 ;
     RECT  7.992 18.599 8.37 18.797 ;
     RECT  12.348 18.749 13.446 18.797 ;
     RECT  40.104 18.571 40.122 18.797 ;
     RECT  42.732 18.749 44.118 18.797 ;
     RECT  48.06 18.761 48.078 18.797 ;
     RECT  68.796 18.689 72.774 18.797 ;
     RECT  12.924 18.797 13.446 18.841 ;
     RECT  41.328 18.229 41.346 18.841 ;
     RECT  3.78 18.725 4.05 18.893 ;
     RECT  12.924 18.841 13.518 18.893 ;
     RECT  18.72 18.769 20.502 18.931 ;
     RECT  41.328 18.841 41.526 18.931 ;
     RECT  58.716 18.221 58.806 18.931 ;
     RECT  59.655 18.509 61.398 18.931 ;
     RECT  21.855 18.317 22.842 18.955 ;
     RECT  50.832 18.805 50.85 18.955 ;
     RECT  58.716 18.931 61.398 18.955 ;
     RECT  12.924 18.893 13.41 18.959 ;
     RECT  14.544 18.761 14.994 18.959 ;
     RECT  17.856 18.931 20.718 18.959 ;
     RECT  45.36 18.761 45.522 18.959 ;
     RECT  46.296 18.749 46.314 18.959 ;
     RECT  50.688 18.955 50.85 18.959 ;
     RECT  17.856 18.959 19.71 18.989 ;
     RECT  20.448 18.959 20.718 18.995 ;
     RECT  50.688 18.959 50.706 18.995 ;
     RECT  51.624 18.931 51.642 19.003 ;
     RECT  17.856 18.989 17.874 19.037 ;
     RECT  6.84 18.059 6.858 19.039 ;
     RECT  30.06 18.967 30.762 19.039 ;
     RECT  9.972 18.761 11.337 19.075 ;
     RECT  64.548 18.563 65.337 19.075 ;
     RECT  66.708 18.689 67.914 19.075 ;
     RECT  26.712 18.221 27.738 19.111 ;
     RECT  29.088 18.841 29.106 19.111 ;
     RECT  9.576 19.075 11.337 19.133 ;
     RECT  7.992 18.797 8.226 19.139 ;
     RECT  10.044 19.133 11.337 19.139 ;
     RECT  64.548 19.075 67.914 19.139 ;
     RECT  20.52 18.995 20.718 19.147 ;
     RECT  63.792 18.563 63.81 19.147 ;
     RECT  16.455 18.059 16.737 19.195 ;
     RECT  32.655 18.419 32.937 19.201 ;
     RECT  8.208 19.139 8.226 19.229 ;
     RECT  18.828 18.989 19.71 19.229 ;
     RECT  45.504 18.959 45.522 19.229 ;
     RECT  51.624 19.003 51.678 19.229 ;
     RECT  58.248 18.955 61.398 19.229 ;
     RECT  25.2 18.535 25.218 19.237 ;
     RECT  21.855 18.955 23.382 19.291 ;
     RECT  10.116 19.139 11.337 19.301 ;
     RECT  51.624 19.229 51.642 19.301 ;
     RECT  67.68 19.139 67.914 19.301 ;
     RECT  26.712 19.111 29.106 19.309 ;
     RECT  25.2 19.237 25.29 19.339 ;
     RECT  41.328 18.931 41.598 19.339 ;
     RECT  62.46 19.075 62.586 19.345 ;
     RECT  63.756 19.147 63.81 19.345 ;
     RECT  17.64 19.309 17.658 19.373 ;
     RECT  20.52 19.147 20.826 19.373 ;
     RECT  25.2 19.339 25.362 19.373 ;
     RECT  58.248 19.229 58.806 19.373 ;
     RECT  59.655 19.229 61.398 19.373 ;
     RECT  62.46 19.345 63.81 19.373 ;
     RECT  3.78 18.893 3.906 19.381 ;
     RECT  21.855 19.291 23.418 19.381 ;
     RECT  25.2 19.373 25.254 19.381 ;
     RECT  26.64 19.309 29.106 19.381 ;
     RECT  30.024 19.039 30.762 19.381 ;
     RECT  31.572 19.075 31.59 19.381 ;
     RECT  32.655 19.201 33.642 19.381 ;
     RECT  41.328 19.339 41.67 19.381 ;
     RECT  54.255 18.329 54.81 19.381 ;
     RECT  48.855 18.221 49.137 19.387 ;
     RECT  56.628 19.381 56.718 19.387 ;
     RECT  6.84 19.039 6.93 19.435 ;
     RECT  14.724 18.959 14.994 19.435 ;
     RECT  30.024 19.381 33.642 19.435 ;
     RECT  54.255 19.381 54.846 19.435 ;
     RECT  2.16 18.701 2.25 19.471 ;
     RECT  20.808 19.373 20.826 19.471 ;
     RECT  21.855 19.381 25.254 19.471 ;
     RECT  38.055 18.491 39.006 19.471 ;
     RECT  39.96 19.381 39.978 19.471 ;
     RECT  41.004 19.381 41.67 19.471 ;
     RECT  56.628 19.387 56.79 19.471 ;
     RECT  56.484 19.471 56.79 19.483 ;
     RECT  29.88 19.435 33.642 19.499 ;
     RECT  67.788 19.301 67.914 19.499 ;
     RECT  10.764 19.301 11.337 19.507 ;
     RECT  56.484 19.483 56.898 19.507 ;
     RECT  60.66 19.373 61.398 19.507 ;
     RECT  32.184 19.499 33.642 19.517 ;
     RECT  1.44 19.471 2.25 19.531 ;
     RECT  5.436 18.761 5.937 19.531 ;
     RECT  21.744 19.471 25.254 19.535 ;
     RECT  67.824 19.499 67.914 19.535 ;
     RECT  5.436 19.531 5.994 19.543 ;
     RECT  6.84 19.435 7.002 19.543 ;
     RECT  26.208 19.381 29.106 19.543 ;
     RECT  29.88 19.499 31.41 19.543 ;
     RECT  35.388 19.507 35.406 19.543 ;
     RECT  5.436 19.543 7.002 19.565 ;
     RECT  21.744 19.535 24.21 19.571 ;
     RECT  35.28 19.543 35.406 19.579 ;
     RECT  54.255 19.435 55.278 19.579 ;
     RECT  56.304 19.507 56.898 19.579 ;
     RECT  20.808 19.471 20.934 19.607 ;
     RECT  67.896 19.535 67.914 19.607 ;
     RECT  0.036 18.761 0.63 19.615 ;
     RECT  1.44 19.531 2.97 19.615 ;
     RECT  3.744 19.381 3.906 19.615 ;
     RECT  37.044 19.381 37.062 19.615 ;
     RECT  53.676 19.579 56.898 19.615 ;
     RECT  62.964 19.373 63.81 19.615 ;
     RECT  64.548 19.139 66.762 19.615 ;
     RECT  69.12 18.797 72.774 19.615 ;
     RECT  0.036 19.615 3.906 19.627 ;
     RECT  32.184 19.517 33.138 19.643 ;
     RECT  48.855 19.387 49.23 19.643 ;
     RECT  0.036 19.627 3.942 19.651 ;
     RECT  5.436 19.565 6.966 19.651 ;
     RECT  36.9 19.615 37.062 19.651 ;
     RECT  68.832 19.615 72.774 19.651 ;
     RECT  34.776 19.579 35.406 19.675 ;
     RECT  26.208 19.543 31.41 19.679 ;
     RECT  47.88 19.507 47.898 19.679 ;
     RECT  53.676 19.615 56.934 19.679 ;
     RECT  36.684 19.651 37.062 19.723 ;
     RECT  12.924 18.959 13.374 19.741 ;
     RECT  16.455 19.195 16.83 19.741 ;
     RECT  0.036 19.651 6.966 19.769 ;
     RECT  20.808 19.607 20.898 19.769 ;
     RECT  28.8 19.679 31.41 19.769 ;
     RECT  34.776 19.675 35.478 19.769 ;
     RECT  51.48 19.723 51.498 19.769 ;
     RECT  53.676 19.679 55.818 19.769 ;
     RECT  56.88 19.679 56.934 19.769 ;
     RECT  57.78 19.627 57.798 19.769 ;
     RECT  10.764 19.507 11.394 19.771 ;
     RECT  14.724 19.435 15.066 19.771 ;
     RECT  12.924 19.741 13.662 19.805 ;
     RECT  25.236 19.535 25.254 19.805 ;
     RECT  26.208 19.679 27.954 19.805 ;
     RECT  32.328 19.643 33.138 19.805 ;
     RECT  36.684 19.723 37.278 19.813 ;
     RECT  56.916 19.769 56.934 19.813 ;
     RECT  68.76 19.651 72.774 19.813 ;
     RECT  36.504 19.813 37.278 19.819 ;
     RECT  38.055 19.471 39.978 19.819 ;
     RECT  6.732 19.769 6.822 19.841 ;
     RECT  28.98 19.769 31.41 19.841 ;
     RECT  52.812 19.741 52.83 19.849 ;
     RECT  53.676 19.769 55.314 19.849 ;
     RECT  0.036 19.769 5.994 19.853 ;
     RECT  6.732 19.841 6.75 19.853 ;
     RECT  32.544 19.805 33.138 19.853 ;
     RECT  52.668 19.849 55.314 19.853 ;
     RECT  10.764 19.771 11.97 19.877 ;
     RECT  48.855 19.643 49.194 19.877 ;
     RECT  56.916 19.813 57.654 19.877 ;
     RECT  68.4 19.813 72.774 19.877 ;
     RECT  13.644 19.805 13.662 19.885 ;
     RECT  14.544 19.771 15.066 19.885 ;
     RECT  0.036 19.853 5.937 19.901 ;
     RECT  13.644 19.885 15.066 19.901 ;
     RECT  36.504 19.819 39.978 19.901 ;
     RECT  53.532 19.853 55.314 19.901 ;
     RECT  34.776 19.769 35.442 19.913 ;
     RECT  69.552 19.877 72.774 19.913 ;
     RECT  13.86 19.901 15.066 19.921 ;
     RECT  69.912 19.913 72.774 19.921 ;
     RECT  60.66 19.507 62.082 19.949 ;
     RECT  62.964 19.615 66.762 19.949 ;
     RECT  68.4 19.877 68.418 19.949 ;
     RECT  16.455 19.741 17.118 20.011 ;
     RECT  18.828 19.229 19.494 20.011 ;
     RECT  48.855 19.877 49.137 20.011 ;
     RECT  2.16 19.901 5.937 20.039 ;
     RECT  21.744 19.571 23.706 20.045 ;
     RECT  32.544 19.853 32.937 20.045 ;
     RECT  13.86 19.921 15.534 20.047 ;
     RECT  16.344 20.011 17.118 20.047 ;
     RECT  18.828 20.011 19.926 20.047 ;
     RECT  63 19.949 66.762 20.047 ;
     RECT  41.004 19.471 41.778 20.083 ;
     RECT  42.732 18.797 43.737 20.083 ;
     RECT  41.004 20.083 43.737 20.093 ;
     RECT  28.98 19.841 31.338 20.111 ;
     RECT  53.532 19.901 55.278 20.111 ;
     RECT  57.636 19.877 57.654 20.147 ;
     RECT  30.24 20.111 31.338 20.183 ;
     RECT  39.132 19.901 39.978 20.183 ;
     RECT  17.964 20.047 19.926 20.203 ;
     RECT  63 20.047 66.978 20.203 ;
     RECT  39.456 20.183 39.978 20.251 ;
     RECT  13.86 20.047 17.118 20.299 ;
     RECT  17.892 20.203 19.926 20.299 ;
     RECT  42.192 20.093 43.737 20.299 ;
     RECT  21.852 20.045 23.706 20.309 ;
     RECT  30.24 20.183 31.302 20.309 ;
     RECT  42.192 20.299 43.902 20.309 ;
     RECT  48.348 20.011 49.137 20.309 ;
     RECT  30.24 20.309 30.258 20.345 ;
     RECT  36.504 19.901 38.394 20.345 ;
     RECT  13.86 20.299 19.926 20.381 ;
     RECT  42.48 20.309 43.902 20.381 ;
     RECT  36.936 20.345 38.394 20.429 ;
     RECT  37.584 20.429 38.394 20.453 ;
     RECT  2.16 20.039 4.698 20.477 ;
     RECT  41.004 20.093 41.418 20.477 ;
     RECT  14.832 20.381 19.926 20.539 ;
     RECT  26.244 19.805 27.954 20.551 ;
     RECT  5.544 20.039 5.937 20.579 ;
     RECT  10.764 19.877 11.337 20.587 ;
     RECT  23.904 20.551 24.174 20.587 ;
     RECT  26.244 20.551 28.134 20.587 ;
     RECT  34.776 19.913 35.154 20.587 ;
     RECT  56.304 20.551 56.322 20.587 ;
     RECT  39.456 20.251 40.194 20.615 ;
     RECT  25.884 20.587 28.134 20.623 ;
     RECT  28.98 20.111 29.43 20.623 ;
     RECT  58.608 19.373 58.806 20.623 ;
     RECT  67.968 20.587 67.986 20.623 ;
     RECT  54.255 20.111 55.278 20.635 ;
     RECT  42.66 20.381 43.902 20.651 ;
     RECT  0.036 19.901 1.35 20.659 ;
     RECT  2.16 20.477 4.626 20.659 ;
     RECT  58.608 20.623 58.878 20.659 ;
     RECT  59.655 19.373 59.937 20.659 ;
     RECT  60.66 19.949 61.398 20.659 ;
     RECT  69.912 19.921 72.882 20.659 ;
     RECT  10.116 20.587 11.337 20.683 ;
     RECT  52.668 19.853 52.686 20.683 ;
     RECT  58.212 20.659 58.878 20.683 ;
     RECT  59.655 20.659 61.398 20.683 ;
     RECT  63 20.203 67.014 20.695 ;
     RECT  67.824 20.623 67.986 20.695 ;
     RECT  23.904 20.587 24.606 20.717 ;
     RECT  69.84 20.659 72.882 20.717 ;
     RECT  25.884 20.623 29.43 20.731 ;
     RECT  32.655 20.045 32.937 20.731 ;
     RECT  33.732 20.659 33.75 20.731 ;
     RECT  34.632 20.587 35.154 20.731 ;
     RECT  38.055 20.453 38.394 20.731 ;
     RECT  40.176 20.615 40.194 20.731 ;
     RECT  41.004 20.477 41.166 20.731 ;
     RECT  42.696 20.651 43.902 20.731 ;
     RECT  48.855 20.309 49.137 20.731 ;
     RECT  52.668 20.683 53.046 20.731 ;
     RECT  54.255 20.635 55.35 20.731 ;
     RECT  67.824 20.695 68.382 20.731 ;
     RECT  32.655 20.731 33.75 20.759 ;
     RECT  32.655 20.759 33.03 20.765 ;
     RECT  48.855 20.731 49.23 20.765 ;
     RECT  5.58 20.579 5.937 20.779 ;
     RECT  23.904 20.717 24.498 20.813 ;
     RECT  51.336 19.777 51.354 20.813 ;
     RECT  10.116 20.683 11.574 20.821 ;
     RECT  13.86 20.381 13.878 20.821 ;
     RECT  25.596 20.731 29.43 20.821 ;
     RECT  45.252 20.731 45.27 20.821 ;
     RECT  10.008 20.821 11.574 20.827 ;
     RECT  62.784 20.695 67.014 20.827 ;
     RECT  67.824 20.731 68.994 20.827 ;
     RECT  0.036 20.659 4.626 20.849 ;
     RECT  54.255 20.731 55.422 20.849 ;
     RECT  59.655 20.683 61.902 20.849 ;
     RECT  62.784 20.827 68.994 20.849 ;
     RECT  70.056 20.717 72.882 20.849 ;
     RECT  13.68 20.821 13.878 20.857 ;
     RECT  21.852 20.309 23.022 20.857 ;
     RECT  56.196 20.587 56.322 20.857 ;
     RECT  10.008 20.827 12.294 20.885 ;
     RECT  34.632 20.731 35.298 20.885 ;
     RECT  40.176 20.731 41.166 20.885 ;
     RECT  25.524 20.821 29.43 20.893 ;
     RECT  58.212 20.683 58.914 20.893 ;
     RECT  23.904 20.813 24.174 20.921 ;
     RECT  60.984 20.849 61.83 20.921 ;
     RECT  14.832 20.539 20.07 20.923 ;
     RECT  45.252 20.821 45.342 20.929 ;
     RECT  68.364 20.849 68.994 20.929 ;
     RECT  23.904 20.921 23.922 20.957 ;
     RECT  62.784 20.849 67.302 20.957 ;
     RECT  5.58 20.779 6.498 20.965 ;
     RECT  7.272 20.929 7.29 20.965 ;
     RECT  10.008 20.885 11.79 20.993 ;
     RECT  5.58 20.965 7.29 21.001 ;
     RECT  13.176 20.857 13.878 21.001 ;
     RECT  0.036 20.849 3.762 21.029 ;
     RECT  14.832 20.923 20.286 21.029 ;
     RECT  62.82 20.957 67.302 21.029 ;
     RECT  14.832 21.029 19.386 21.053 ;
     RECT  20.268 21.029 20.286 21.053 ;
     RECT  25.488 20.893 29.43 21.067 ;
     RECT  31.176 20.309 31.194 21.091 ;
     RECT  45.252 20.929 45.414 21.091 ;
     RECT  52.272 20.731 53.046 21.091 ;
     RECT  56.196 20.857 56.394 21.091 ;
     RECT  56.052 21.091 56.394 21.115 ;
     RECT  12.852 21.001 13.878 21.119 ;
     RECT  34.632 20.885 34.866 21.119 ;
     RECT  40.176 20.885 40.338 21.119 ;
     RECT  60.984 20.921 61.758 21.119 ;
     RECT  36.072 20.731 36.09 21.127 ;
     RECT  38.055 20.731 38.43 21.127 ;
     RECT  39.42 21.091 39.438 21.127 ;
     RECT  42.696 20.731 44.478 21.127 ;
     RECT  45.252 21.091 45.81 21.127 ;
     RECT  52.272 21.091 53.334 21.127 ;
     RECT  54.255 20.849 55.242 21.127 ;
     RECT  58.14 20.893 58.914 21.127 ;
     RECT  68.364 20.929 69.066 21.127 ;
     RECT  10.116 20.993 11.79 21.149 ;
     RECT  38.055 21.127 39.438 21.149 ;
     RECT  56.052 21.115 56.502 21.149 ;
     RECT  14.832 21.053 16.974 21.155 ;
     RECT  70.128 20.849 72.882 21.155 ;
     RECT  47.34 21.091 47.358 21.163 ;
     RECT  52.272 21.127 55.242 21.191 ;
     RECT  57.564 21.127 58.914 21.191 ;
     RECT  56.124 21.149 56.502 21.197 ;
     RECT  25.488 21.067 29.466 21.199 ;
     RECT  4.5 20.849 4.626 21.211 ;
     RECT  12.924 21.119 13.878 21.227 ;
     RECT  25.38 21.199 29.466 21.227 ;
     RECT  34.704 21.119 34.866 21.227 ;
     RECT  35.604 21.127 36.09 21.227 ;
     RECT  59.655 20.849 60.246 21.227 ;
     RECT  13.248 21.227 13.878 21.235 ;
     RECT  50.796 21.127 51.03 21.235 ;
     RECT  52.272 21.191 52.434 21.235 ;
     RECT  5.58 21.001 7.434 21.263 ;
     RECT  13.248 21.235 14.094 21.263 ;
     RECT  14.832 21.155 16.902 21.263 ;
     RECT  36.072 21.227 36.09 21.263 ;
     RECT  41.076 20.885 41.166 21.271 ;
     RECT  13.32 21.263 14.094 21.293 ;
     RECT  52.236 21.235 52.434 21.293 ;
     RECT  4.5 21.211 4.806 21.299 ;
     RECT  14.832 21.263 16.758 21.299 ;
     RECT  40.32 21.119 40.338 21.299 ;
     RECT  53.208 21.191 55.242 21.299 ;
     RECT  42.696 21.127 46.494 21.355 ;
     RECT  47.232 21.163 47.358 21.355 ;
     RECT  58.716 21.191 58.914 21.355 ;
     RECT  59.655 21.227 59.994 21.355 ;
     RECT  21.564 20.857 23.022 21.361 ;
     RECT  30.816 21.091 31.59 21.361 ;
     RECT  36.144 21.271 36.162 21.361 ;
     RECT  14.832 21.299 15.102 21.389 ;
     RECT  36.144 21.361 36.234 21.389 ;
     RECT  42.696 21.355 47.358 21.389 ;
     RECT  53.208 21.299 54.99 21.389 ;
     RECT  68.364 21.127 69.282 21.389 ;
     RECT  13.32 21.293 13.482 21.425 ;
     RECT  15.84 21.299 16.758 21.425 ;
     RECT  34.776 21.227 34.83 21.425 ;
     RECT  45.684 21.389 47.358 21.425 ;
     RECT  52.416 21.293 52.434 21.425 ;
     RECT  41.076 21.271 41.202 21.433 ;
     RECT  42.696 21.389 44.874 21.437 ;
     RECT  60.984 21.119 61.29 21.437 ;
     RECT  41.076 21.433 41.274 21.451 ;
     RECT  0.036 21.029 3.726 21.461 ;
     RECT  14.832 21.389 15.03 21.461 ;
     RECT  25.38 21.227 29.43 21.461 ;
     RECT  42.696 21.437 44.586 21.461 ;
     RECT  45.684 21.425 47.178 21.461 ;
     RECT  68.76 21.389 69.282 21.461 ;
     RECT  41.076 21.451 41.346 21.485 ;
     RECT  41.112 21.485 41.346 21.497 ;
     RECT  53.28 21.389 54.918 21.497 ;
     RECT  42.696 21.461 44.406 21.499 ;
     RECT  0.036 21.461 2.286 21.533 ;
     RECT  3.528 21.461 3.726 21.533 ;
     RECT  5.58 21.263 6.93 21.533 ;
     RECT  41.256 21.497 41.346 21.533 ;
     RECT  42.624 21.499 44.406 21.533 ;
     RECT  56.196 21.197 56.502 21.533 ;
     RECT  60.984 21.437 61.218 21.533 ;
     RECT  62.82 21.029 67.05 21.533 ;
     RECT  69.084 21.461 69.282 21.533 ;
     RECT  62.82 21.533 65.394 21.569 ;
     RECT  66.528 21.533 67.05 21.569 ;
     RECT  69.084 21.533 69.174 21.569 ;
     RECT  34.776 21.425 34.794 21.581 ;
     RECT  50.724 21.235 51.03 21.581 ;
     RECT  58.716 21.355 59.994 21.581 ;
     RECT  17.928 21.053 19.386 21.629 ;
     RECT  50.724 21.581 50.958 21.629 ;
     RECT  18 21.629 19.386 21.659 ;
     RECT  25.524 21.461 29.43 21.659 ;
     RECT  36.216 21.389 36.234 21.659 ;
     RECT  38.055 21.149 39.294 21.659 ;
     RECT  56.34 21.533 56.502 21.659 ;
     RECT  58.752 21.581 59.994 21.659 ;
     RECT  62.82 21.569 63.774 21.659 ;
     RECT  46.26 21.461 47.178 21.677 ;
     RECT  14.832 21.461 14.958 21.691 ;
     RECT  57.564 21.191 57.978 21.695 ;
     RECT  20.376 21.361 23.022 21.703 ;
     RECT  30.78 21.361 31.59 21.703 ;
     RECT  62.82 21.659 62.838 21.725 ;
     RECT  25.524 21.659 29.286 21.731 ;
     RECT  70.128 21.155 72.846 21.739 ;
     RECT  69.948 21.739 72.846 21.767 ;
     RECT  7.704 21.739 7.866 21.775 ;
     RECT  18.612 21.659 19.386 21.775 ;
     RECT  20.376 21.703 23.31 21.775 ;
     RECT  38.055 21.659 38.79 21.775 ;
     RECT  56.448 21.659 56.502 21.787 ;
     RECT  7.704 21.775 8.082 21.811 ;
     RECT  56.448 21.787 56.61 21.811 ;
     RECT  18.612 21.775 23.31 21.839 ;
     RECT  25.524 21.731 29.178 21.839 ;
     RECT  18.612 21.839 20.25 21.869 ;
     RECT  3.672 21.533 3.726 21.883 ;
     RECT  4.5 21.299 4.518 21.883 ;
     RECT  50.724 21.629 50.814 21.901 ;
     RECT  1.548 21.533 2.286 21.929 ;
     RECT  56.448 21.811 57.51 21.929 ;
     RECT  28.368 21.839 29.178 21.965 ;
     RECT  69.948 21.767 72.81 21.965 ;
     RECT  10.116 21.149 11.574 21.973 ;
     RECT  50.688 21.901 50.814 21.973 ;
     RECT  16.455 21.425 16.758 22.009 ;
     RECT  30.564 21.703 31.59 22.009 ;
     RECT  50.616 21.973 50.814 22.009 ;
     RECT  3.672 21.883 4.518 22.037 ;
     RECT  28.368 21.965 29.142 22.037 ;
     RECT  64.872 21.569 65.394 22.037 ;
     RECT  10.116 21.973 11.61 22.045 ;
     RECT  60.984 21.533 61.074 22.045 ;
     RECT  13.32 21.425 13.338 22.075 ;
     RECT  32.655 20.765 32.937 22.075 ;
     RECT  5.655 21.533 6.93 22.081 ;
     RECT  7.704 21.811 8.226 22.081 ;
     RECT  59.655 21.659 59.994 22.081 ;
     RECT  30.528 22.009 31.662 22.109 ;
     RECT  66.708 21.569 67.05 22.109 ;
     RECT  10.116 22.045 11.79 22.123 ;
     RECT  21.096 21.839 23.31 22.123 ;
     RECT  48.855 20.765 49.137 22.123 ;
     RECT  49.932 22.009 50.814 22.123 ;
     RECT  30.528 22.109 31.626 22.157 ;
     RECT  10.08 22.123 11.79 22.199 ;
     RECT  25.524 21.839 27.594 22.199 ;
     RECT  29.124 22.037 29.142 22.199 ;
     RECT  30.636 22.157 31.626 22.199 ;
     RECT  34.74 22.081 34.758 22.199 ;
     RECT  37.98 21.775 38.79 22.199 ;
     RECT  47.952 22.009 47.97 22.199 ;
     RECT  48.855 22.123 50.814 22.199 ;
     RECT  60.912 22.045 61.074 22.199 ;
     RECT  37.044 22.171 37.206 22.205 ;
     RECT  51.984 22.081 52.002 22.207 ;
     RECT  70.056 21.965 72.81 22.253 ;
     RECT  62.676 22.243 62.694 22.267 ;
     RECT  5.655 22.081 8.658 22.271 ;
     RECT  56.448 21.929 57.042 22.271 ;
     RECT  25.524 22.199 27.537 22.279 ;
     RECT  7.956 22.271 8.658 22.301 ;
     RECT  3.672 22.037 3.69 22.315 ;
     RECT  13.068 22.075 13.338 22.315 ;
     RECT  14.256 21.691 14.958 22.315 ;
     RECT  43.056 21.533 43.737 22.315 ;
     RECT  60.948 22.199 61.074 22.315 ;
     RECT  64.872 22.037 65.337 22.315 ;
     RECT  4.536 22.081 4.554 22.343 ;
     RECT  12.924 22.315 13.338 22.351 ;
     RECT  14.256 22.315 15.426 22.351 ;
     RECT  12.888 22.351 15.426 22.363 ;
     RECT  16.455 22.009 17.046 22.363 ;
     RECT  51.876 22.207 52.002 22.379 ;
     RECT  21.096 22.123 23.958 22.411 ;
     RECT  12.888 22.363 17.046 22.441 ;
     RECT  21.096 22.411 24.426 22.441 ;
     RECT  25.452 22.279 27.537 22.441 ;
     RECT  8.496 22.301 8.658 22.469 ;
     RECT  30.96 22.199 31.626 22.469 ;
     RECT  38.016 22.199 38.79 22.469 ;
     RECT  51.912 22.379 52.002 22.469 ;
     RECT  60.948 22.315 61.11 22.469 ;
     RECT  62.136 22.267 62.694 22.469 ;
     RECT  1.62 21.929 2.286 22.477 ;
     RECT  3.42 22.315 3.69 22.477 ;
     RECT  54.255 21.497 54.537 22.477 ;
     RECT  58.752 21.659 58.806 22.477 ;
     RECT  60.984 22.469 61.11 22.477 ;
     RECT  30.96 22.469 31.446 22.505 ;
     RECT  10.08 22.199 11.718 22.513 ;
     RECT  38.055 22.469 38.79 22.513 ;
     RECT  46.764 21.677 47.178 22.513 ;
     RECT  12.564 22.441 17.046 22.541 ;
     RECT  14.256 22.541 17.046 22.585 ;
     RECT  46.728 22.513 47.178 22.585 ;
     RECT  59.655 22.081 60.138 22.585 ;
     RECT  55.692 22.513 55.926 22.589 ;
     RECT  54.255 22.477 54.81 22.603 ;
     RECT  21.096 22.441 27.537 22.613 ;
     RECT  46.728 22.585 47.286 22.613 ;
     RECT  64.188 22.315 65.337 22.621 ;
     RECT  67.464 22.351 67.482 22.621 ;
     RECT  12.564 22.541 13.446 22.649 ;
     RECT  38.055 22.513 38.826 22.649 ;
     RECT  5.655 22.271 7.182 22.699 ;
     RECT  66.708 22.109 66.726 22.711 ;
     RECT  4.752 22.699 7.182 22.739 ;
     RECT  12.636 22.649 13.446 22.739 ;
     RECT  14.256 22.585 17.334 22.739 ;
     RECT  44.46 22.621 44.478 22.739 ;
     RECT  50.04 22.199 50.166 22.739 ;
     RECT  54.144 22.603 54.81 22.739 ;
     RECT  59.655 22.585 60.21 22.739 ;
     RECT  60.984 22.477 61.938 22.739 ;
     RECT  0.036 21.533 0.702 22.747 ;
     RECT  1.62 22.477 3.69 22.747 ;
     RECT  46.764 22.613 47.286 22.775 ;
     RECT  50.04 22.739 50.13 22.775 ;
     RECT  55.908 22.589 55.926 22.781 ;
     RECT  0.036 22.747 3.69 22.783 ;
     RECT  67.464 22.621 68.058 22.795 ;
     RECT  12.708 22.739 13.446 22.811 ;
     RECT  21.42 22.613 27.537 22.811 ;
     RECT  50.112 22.775 50.13 22.811 ;
     RECT  51.984 22.469 52.002 22.811 ;
     RECT  54.255 22.739 54.81 22.811 ;
     RECT  63.9 22.621 65.337 22.819 ;
     RECT  14.508 22.739 17.334 22.843 ;
     RECT  18.612 21.869 19.89 22.843 ;
     RECT  23.58 22.811 23.85 22.847 ;
     RECT  28.368 22.037 28.386 22.847 ;
     RECT  8.568 22.469 8.658 22.855 ;
     RECT  9.612 22.513 11.718 22.855 ;
     RECT  14.508 22.843 19.89 22.855 ;
     RECT  58.716 22.477 58.806 22.855 ;
     RECT  59.655 22.739 59.937 22.855 ;
     RECT  66.384 22.711 66.726 22.855 ;
     RECT  67.464 22.795 68.778 22.855 ;
     RECT  24.624 22.811 27.537 22.883 ;
     RECT  0.036 22.783 3.762 22.891 ;
     RECT  63.684 22.819 65.337 22.891 ;
     RECT  25.92 22.883 27.537 22.919 ;
     RECT  60.984 22.739 61.83 22.919 ;
     RECT  58.716 22.855 59.937 22.981 ;
     RECT  57.024 22.271 57.042 22.987 ;
     RECT  8.568 22.855 11.718 23.009 ;
     RECT  66.384 22.855 68.778 23.009 ;
     RECT  63.612 22.891 65.337 23.017 ;
     RECT  66.384 23.009 67.662 23.017 ;
     RECT  68.616 23.009 68.778 23.017 ;
     RECT  70.344 22.253 72.81 23.017 ;
     RECT  58.14 22.981 59.937 23.035 ;
     RECT  44.532 22.987 44.55 23.045 ;
     RECT  57.024 22.987 57.078 23.045 ;
     RECT  62.712 22.555 62.73 23.045 ;
     RECT  40.644 22.981 40.662 23.053 ;
     RECT  23.58 22.847 23.706 23.069 ;
     RECT  63.612 23.017 67.662 23.081 ;
     RECT  42.768 22.315 43.737 23.083 ;
     RECT  70.308 23.017 72.81 23.083 ;
     RECT  63.648 23.081 67.662 23.117 ;
     RECT  40.608 23.053 40.662 23.125 ;
     RECT  42.372 23.083 43.737 23.125 ;
     RECT  9.36 23.009 11.718 23.153 ;
     RECT  46.764 22.775 46.89 23.153 ;
     RECT  58.032 23.035 59.937 23.153 ;
     RECT  4.752 22.739 7.002 23.161 ;
     RECT  32.544 22.075 32.937 23.161 ;
     RECT  34.776 22.315 34.794 23.161 ;
     RECT  45.504 22.513 45.522 23.161 ;
     RECT  52.416 22.891 52.47 23.161 ;
     RECT  58.032 23.153 58.734 23.161 ;
     RECT  14.508 22.855 20.538 23.189 ;
     RECT  23.688 23.069 23.706 23.189 ;
     RECT  57.852 23.161 58.734 23.189 ;
     RECT  60.984 22.919 61.218 23.189 ;
     RECT  63.648 23.117 67.374 23.189 ;
     RECT  52.416 23.161 52.614 23.213 ;
     RECT  54.255 22.811 54.738 23.213 ;
     RECT  45.468 23.161 45.522 23.251 ;
     RECT  69.804 23.083 72.81 23.251 ;
     RECT  57.852 23.189 58.158 23.275 ;
     RECT  4.644 23.161 7.002 23.279 ;
     RECT  14.652 23.189 20.538 23.279 ;
     RECT  39.708 23.083 39.726 23.279 ;
     RECT  40.5 23.125 40.662 23.279 ;
     RECT  53.388 22.981 53.406 23.279 ;
     RECT  63.648 23.189 66.834 23.279 ;
     RECT  61.02 23.189 61.218 23.309 ;
     RECT  66.708 23.279 66.834 23.309 ;
     RECT  9.36 23.153 9.81 23.315 ;
     RECT  57.78 23.275 58.158 23.315 ;
     RECT  63.684 23.279 65.826 23.315 ;
     RECT  45.468 23.251 45.558 23.351 ;
     RECT  30.96 22.505 31.23 23.359 ;
     RECT  32.472 23.161 32.937 23.359 ;
     RECT  34.776 23.161 34.866 23.359 ;
     RECT  38.055 22.649 38.79 23.359 ;
     RECT  40.536 23.279 40.662 23.371 ;
     RECT  37.476 23.359 38.79 23.395 ;
     RECT  39.636 23.287 39.654 23.405 ;
     RECT  0.036 22.891 3.906 23.423 ;
     RECT  8.568 23.009 8.586 23.431 ;
     RECT  10.584 23.153 11.718 23.431 ;
     RECT  18.036 23.279 20.538 23.431 ;
     RECT  32.4 23.359 32.937 23.431 ;
     RECT  40.536 23.371 40.95 23.431 ;
     RECT  68.616 23.017 68.994 23.431 ;
     RECT  69.768 23.251 72.81 23.431 ;
     RECT  0.036 23.423 0.63 23.549 ;
     RECT  40.536 23.431 41.094 23.549 ;
     RECT  64.836 23.315 65.826 23.549 ;
     RECT  66.708 23.309 66.762 23.549 ;
     RECT  35.964 23.521 35.982 23.557 ;
     RECT  36.936 23.395 38.79 23.557 ;
     RECT  13.356 22.811 13.374 23.593 ;
     RECT  5.148 23.279 7.002 23.611 ;
     RECT  13.356 23.593 13.518 23.621 ;
     RECT  32.364 23.431 32.937 23.621 ;
     RECT  5.148 23.611 7.398 23.629 ;
     RECT  8.172 23.431 8.586 23.629 ;
     RECT  46.368 23.557 46.53 23.645 ;
     RECT  35.964 23.557 38.79 23.657 ;
     RECT  46.512 23.645 46.53 23.657 ;
     RECT  30.78 23.359 31.23 23.665 ;
     RECT  42.192 23.125 43.737 23.665 ;
     RECT  13.5 23.621 13.518 23.693 ;
     RECT  35.964 23.657 36.81 23.701 ;
     RECT  29.844 23.431 29.862 23.729 ;
     RECT  18.036 23.431 20.646 23.819 ;
     RECT  41.94 23.665 43.737 23.819 ;
     RECT  68.616 23.431 72.81 23.819 ;
     RECT  21.42 22.811 22.338 23.827 ;
     RECT  35.892 23.701 36.81 23.855 ;
     RECT  30.78 23.665 31.806 23.885 ;
     RECT  35.892 23.855 36.666 23.885 ;
     RECT  5.148 23.629 8.586 23.891 ;
     RECT  14.652 23.279 17.046 23.891 ;
     RECT  35.892 23.885 36.054 23.891 ;
     RECT  9.684 23.315 9.81 23.899 ;
     RECT  10.584 23.431 11.754 23.899 ;
     RECT  18.18 23.819 20.646 23.933 ;
     RECT  21.42 23.827 22.554 23.935 ;
     RECT  24.624 22.883 24.642 23.935 ;
     RECT  52.416 23.213 52.434 23.935 ;
     RECT  54.255 23.213 54.537 23.935 ;
     RECT  61.056 23.309 61.218 23.935 ;
     RECT  68.616 23.819 72.774 23.935 ;
     RECT  9.684 23.899 11.754 23.947 ;
     RECT  59.655 23.153 59.937 23.947 ;
     RECT  18.432 23.933 20.646 23.971 ;
     RECT  21.42 23.935 22.77 23.971 ;
     RECT  26.28 22.919 27.537 23.971 ;
     RECT  30.78 23.885 31.014 23.971 ;
     RECT  37.62 23.657 38.79 23.971 ;
     RECT  58.896 23.935 58.914 23.971 ;
     RECT  62.784 23.947 62.91 23.971 ;
     RECT  37.62 23.971 38.862 23.995 ;
     RECT  58.68 23.971 58.914 23.995 ;
     RECT  59.655 23.947 60.03 23.995 ;
     RECT  18.432 23.971 22.95 23.999 ;
     RECT  54.255 23.935 54.738 24.043 ;
     RECT  1.548 23.423 3.906 24.061 ;
     RECT  5.148 23.891 7.794 24.061 ;
     RECT  26.28 23.971 27.594 24.061 ;
     RECT  34.776 23.359 34.938 24.061 ;
     RECT  35.676 23.935 35.766 24.061 ;
     RECT  48.855 22.199 49.137 24.061 ;
     RECT  50.436 23.971 50.526 24.061 ;
     RECT  56.952 23.935 56.97 24.061 ;
     RECT  63.684 23.315 63.738 24.061 ;
     RECT  68.364 23.935 72.774 24.061 ;
     RECT  8.568 23.891 8.586 24.089 ;
     RECT  37.62 23.995 38.97 24.089 ;
     RECT  54.255 24.043 55.098 24.089 ;
     RECT  61.056 23.935 61.794 24.091 ;
     RECT  24.624 23.935 24.858 24.097 ;
     RECT  25.812 24.061 27.594 24.097 ;
     RECT  44.928 23.971 45.054 24.097 ;
     RECT  50.292 24.061 50.526 24.097 ;
     RECT  56.088 23.971 56.106 24.097 ;
     RECT  56.916 24.061 56.97 24.097 ;
     RECT  34.776 24.061 35.766 24.125 ;
     RECT  52.416 23.935 53.046 24.125 ;
     RECT  67.788 24.061 72.774 24.125 ;
     RECT  18.828 23.999 22.95 24.133 ;
     RECT  62.568 23.971 62.91 24.133 ;
     RECT  63.684 24.061 63.774 24.133 ;
     RECT  1.548 24.061 7.794 24.161 ;
     RECT  9.684 23.947 11.97 24.161 ;
     RECT  52.416 24.125 52.83 24.169 ;
     RECT  62.568 24.133 63.774 24.197 ;
     RECT  14.832 23.891 17.046 24.205 ;
     RECT  24.624 24.097 27.594 24.205 ;
     RECT  34.776 24.125 35.658 24.205 ;
     RECT  42.012 23.819 43.737 24.205 ;
     RECT  58.68 23.995 60.03 24.205 ;
     RECT  61.02 24.091 61.794 24.205 ;
     RECT  56.088 24.097 56.97 24.233 ;
     RECT  18.828 24.133 23.382 24.235 ;
     RECT  24.552 24.205 27.594 24.241 ;
     RECT  5.364 24.161 7.794 24.269 ;
     RECT  56.088 24.233 56.106 24.269 ;
     RECT  46.764 23.971 46.89 24.283 ;
     RECT  47.664 24.061 49.374 24.283 ;
     RECT  64.836 23.549 65.358 24.283 ;
     RECT  64.764 24.283 65.358 24.331 ;
     RECT  1.548 24.161 4.518 24.359 ;
     RECT  13.716 24.097 14.022 24.359 ;
     RECT  18.828 24.235 23.634 24.359 ;
     RECT  24.444 24.241 27.594 24.359 ;
     RECT  56.88 24.233 56.934 24.359 ;
     RECT  63.288 24.197 63.774 24.359 ;
     RECT  67.788 24.125 68.382 24.359 ;
     RECT  0.036 23.549 0.594 24.367 ;
     RECT  18.828 24.359 22.986 24.395 ;
     RECT  24.444 24.359 24.462 24.395 ;
     RECT  58.68 24.205 60.102 24.395 ;
     RECT  64.764 24.331 65.394 24.395 ;
     RECT  42.012 24.205 43.794 24.403 ;
     RECT  61.02 24.205 62.154 24.413 ;
     RECT  63.288 24.359 63.306 24.413 ;
     RECT  66.708 23.549 66.726 24.427 ;
     RECT  1.692 24.359 4.518 24.431 ;
     RECT  20.592 24.395 22.986 24.431 ;
     RECT  56.916 24.359 56.934 24.431 ;
     RECT  66.132 24.427 66.726 24.439 ;
     RECT  67.788 24.359 68.31 24.439 ;
     RECT  18.828 24.395 19.818 24.461 ;
     RECT  20.592 24.431 20.61 24.461 ;
     RECT  25.308 24.359 27.594 24.461 ;
     RECT  54.255 24.089 54.954 24.461 ;
     RECT  1.692 24.431 3.978 24.467 ;
     RECT  5.364 24.269 7.758 24.467 ;
     RECT  54.255 24.461 54.882 24.467 ;
     RECT  40.68 23.549 40.95 24.475 ;
     RECT  58.68 24.395 59.937 24.475 ;
     RECT  5.364 24.467 7.362 24.503 ;
     RECT  23.868 24.403 24.066 24.503 ;
     RECT  46.764 24.283 49.374 24.503 ;
     RECT  14.832 24.205 17.154 24.509 ;
     RECT  40.536 24.475 40.95 24.509 ;
     RECT  46.764 24.503 47.574 24.509 ;
     RECT  25.812 24.461 27.594 24.511 ;
     RECT  31.788 23.885 31.806 24.511 ;
     RECT  32.544 23.621 32.937 24.511 ;
     RECT  42.012 24.403 43.902 24.511 ;
     RECT  44.64 24.097 45.054 24.511 ;
     RECT  48.384 24.503 49.374 24.511 ;
     RECT  51.984 24.169 52.83 24.511 ;
     RECT  31.788 24.511 33.066 24.523 ;
     RECT  51.696 24.511 52.83 24.539 ;
     RECT  10.8 24.161 11.97 24.601 ;
     RECT  40.932 24.509 40.95 24.601 ;
     RECT  42.012 24.511 45.054 24.601 ;
     RECT  2.16 24.467 3.978 24.629 ;
     RECT  25.812 24.511 28.566 24.629 ;
     RECT  48.384 24.511 49.482 24.653 ;
     RECT  3.816 24.629 3.834 24.665 ;
     RECT  5.364 24.503 6.966 24.665 ;
     RECT  40.932 24.601 45.054 24.665 ;
     RECT  50.292 24.097 50.886 24.667 ;
     RECT  51.696 24.539 51.714 24.667 ;
     RECT  13.716 24.359 13.842 24.673 ;
     RECT  29.484 24.601 29.574 24.673 ;
     RECT  31.788 24.523 33.57 24.673 ;
     RECT  21.672 24.431 22.986 24.701 ;
     RECT  26.46 24.629 28.566 24.701 ;
     RECT  40.068 24.673 40.086 24.709 ;
     RECT  40.968 24.665 45.054 24.709 ;
     RECT  46.764 24.509 47.034 24.709 ;
     RECT  61.02 24.413 61.254 24.709 ;
     RECT  64.836 24.395 65.394 24.709 ;
     RECT  66.132 24.439 68.31 24.709 ;
     RECT  13.428 24.673 13.842 24.715 ;
     RECT  24.048 24.503 24.066 24.737 ;
     RECT  40.968 24.709 45.378 24.737 ;
     RECT  28.368 24.701 28.566 24.745 ;
     RECT  50.292 24.667 51.714 24.745 ;
     RECT  18.828 24.461 19.422 24.749 ;
     RECT  41.94 24.737 45.378 24.749 ;
     RECT  29.376 24.673 29.574 24.763 ;
     RECT  10.8 24.601 12.186 24.773 ;
     RECT  30.744 23.971 31.014 24.781 ;
     RECT  31.752 24.673 33.57 24.781 ;
     RECT  34.632 24.205 35.658 24.781 ;
     RECT  45.36 24.749 45.378 24.781 ;
     RECT  2.16 24.629 2.934 24.797 ;
     RECT  18.828 24.749 19.386 24.809 ;
     RECT  41.94 24.749 44.262 24.809 ;
     RECT  52.668 24.539 52.83 24.809 ;
     RECT  58.14 24.475 59.937 24.809 ;
     RECT  29.376 24.763 29.682 24.859 ;
     RECT  30.708 24.781 31.014 24.859 ;
     RECT  31.752 24.781 33.606 24.859 ;
     RECT  38.055 24.089 38.97 24.859 ;
     RECT  39.924 24.709 40.086 24.859 ;
     RECT  45.36 24.781 45.414 24.859 ;
     RECT  46.224 24.709 47.034 24.859 ;
     RECT  10.836 24.773 12.186 24.871 ;
     RECT  12.96 24.715 13.842 24.871 ;
     RECT  5.508 24.665 6.966 24.899 ;
     RECT  10.836 24.871 13.842 24.899 ;
     RECT  14.832 24.509 16.737 24.899 ;
     RECT  18.828 24.809 18.882 24.899 ;
     RECT  21.672 24.701 22.137 24.899 ;
     RECT  26.532 24.701 27.537 24.899 ;
     RECT  31.752 24.859 33.822 24.899 ;
     RECT  34.596 24.781 35.658 24.899 ;
     RECT  38.055 24.859 40.086 24.899 ;
     RECT  41.112 24.737 41.13 24.899 ;
     RECT  48.384 24.653 49.23 24.899 ;
     RECT  50.004 24.745 51.714 24.899 ;
     RECT  58.716 24.809 59.937 24.899 ;
     RECT  60.984 24.709 61.254 24.899 ;
     RECT  34.668 24.899 35.658 24.907 ;
     RECT  38.055 24.899 39.15 24.907 ;
     RECT  69.156 24.125 72.774 24.907 ;
     RECT  0.036 24.367 0.63 24.935 ;
     RECT  2.268 24.797 2.934 24.935 ;
     RECT  41.976 24.809 44.262 24.935 ;
     RECT  45.36 24.859 47.034 24.935 ;
     RECT  48.384 24.899 49.137 24.935 ;
     RECT  54.255 24.467 54.81 24.935 ;
     RECT  10.836 24.899 12.33 24.941 ;
     RECT  34.668 24.907 35.91 24.941 ;
     RECT  37.548 24.907 39.15 24.941 ;
     RECT  45.864 24.935 47.034 24.941 ;
     RECT  29.376 24.859 31.014 24.943 ;
     RECT  62.136 24.413 62.154 24.943 ;
     RECT  13.068 24.899 13.842 24.971 ;
     RECT  22.896 24.701 22.986 24.971 ;
     RECT  26.604 24.899 27.537 24.971 ;
     RECT  39.924 24.899 39.978 24.971 ;
     RECT  46.8 24.941 47.034 24.971 ;
     RECT  61.056 24.899 61.218 24.971 ;
     RECT  64.836 24.709 68.31 24.971 ;
     RECT  13.068 24.971 13.77 24.989 ;
     RECT  17.676 24.601 17.694 24.989 ;
     RECT  2.844 24.935 2.934 25.007 ;
     RECT  9.684 24.161 9.774 25.007 ;
     RECT  45.864 24.941 45.882 25.007 ;
     RECT  54.255 24.935 54.738 25.007 ;
     RECT  61.2 24.971 61.218 25.007 ;
     RECT  29.376 24.943 31.698 25.037 ;
     RECT  5.508 24.899 6.894 25.043 ;
     RECT  13.536 24.989 13.77 25.043 ;
     RECT  14.868 24.899 16.737 25.043 ;
     RECT  18.864 24.899 18.882 25.043 ;
     RECT  22.896 24.971 22.914 25.043 ;
     RECT  26.676 24.971 27.537 25.043 ;
     RECT  30.996 25.037 31.698 25.043 ;
     RECT  39.96 24.971 39.978 25.043 ;
     RECT  42.084 24.935 44.262 25.043 ;
     RECT  52.668 24.809 52.758 25.043 ;
     RECT  64.836 24.971 65.862 25.043 ;
     RECT  2.844 25.007 2.862 25.079 ;
     RECT  5.508 25.043 6.858 25.079 ;
     RECT  14.868 25.043 14.886 25.079 ;
     RECT  15.804 25.043 16.737 25.079 ;
     RECT  29.376 25.037 30.186 25.079 ;
     RECT  42.768 25.043 44.262 25.079 ;
     RECT  47.016 24.971 47.034 25.079 ;
     RECT  50.616 24.899 50.886 25.079 ;
     RECT  52.668 25.043 52.686 25.079 ;
     RECT  54.255 25.007 54.63 25.079 ;
     RECT  62.136 24.943 62.226 25.079 ;
     RECT  66.708 24.971 68.31 25.079 ;
     RECT  13.536 25.043 13.554 25.085 ;
     RECT  30.132 25.079 30.186 25.085 ;
     RECT  30.996 25.043 31.122 25.085 ;
     RECT  50.616 25.079 50.634 25.085 ;
     RECT  51.696 24.899 51.714 25.085 ;
     RECT  28.368 24.745 28.602 25.147 ;
     RECT  30.168 25.085 30.186 25.169 ;
     RECT  66.708 25.079 67.662 25.169 ;
     RECT  69.084 24.907 72.774 25.177 ;
     RECT  0.252 24.935 0.63 25.181 ;
     RECT  9.108 25.141 9.126 25.181 ;
     RECT  35.028 24.941 35.334 25.205 ;
     RECT  0.252 25.181 0.537 25.229 ;
     RECT  10.836 24.941 12.258 25.241 ;
     RECT  31.104 25.085 31.122 25.241 ;
     RECT  8.568 25.195 8.586 25.277 ;
     RECT  38.055 24.941 38.682 25.277 ;
     RECT  69.084 25.177 72.81 25.285 ;
     RECT  58.716 24.899 58.806 25.313 ;
     RECT  62.712 25.141 62.73 25.321 ;
     RECT  10.836 25.241 11.337 25.349 ;
     RECT  12.24 25.241 12.258 25.349 ;
     RECT  35.316 25.205 35.334 25.349 ;
     RECT  58.788 25.313 58.806 25.349 ;
     RECT  32.655 24.899 33.75 25.439 ;
     RECT  57.564 25.051 57.582 25.439 ;
     RECT  66.708 25.169 67.554 25.439 ;
     RECT  68.868 25.285 72.81 25.439 ;
     RECT  28.368 25.147 29.322 25.475 ;
     RECT  33.732 25.439 33.75 25.475 ;
     RECT  62.712 25.321 62.802 25.475 ;
     RECT  65.055 25.043 65.862 25.475 ;
     RECT  66.708 25.439 66.834 25.475 ;
     RECT  5.508 25.079 5.937 25.511 ;
     RECT  28.368 25.475 28.386 25.547 ;
     RECT  68.868 25.439 72.774 25.547 ;
     RECT  66.708 25.475 66.762 25.583 ;
     RECT  69.336 25.547 72.774 25.583 ;
     RECT  69.948 25.583 72.774 25.613 ;
     RECT  26.784 25.043 27.537 25.619 ;
     RECT  29.304 25.475 29.322 25.619 ;
     RECT  66.708 25.583 66.726 25.619 ;
     RECT  69.984 25.613 72.774 25.709 ;
     RECT  70.455 25.709 72.774 25.817 ;
     RECT  72.756 25.817 72.774 25.853 ;
     RECT  70.455 25.817 71.802 25.889 ;
     RECT  70.455 25.889 71.406 25.997 ;
     RECT  0.255 25.229 0.537 39.977 ;
     RECT  5.655 25.511 5.937 39.977 ;
     RECT  11.055 25.349 11.337 39.977 ;
     RECT  16.455 25.079 16.737 39.977 ;
     RECT  21.855 24.899 22.137 39.977 ;
     RECT  27.255 25.619 27.537 39.977 ;
     RECT  32.655 25.439 32.937 39.977 ;
     RECT  38.055 25.277 38.337 39.977 ;
     RECT  43.455 25.079 43.737 39.977 ;
     RECT  48.855 24.935 49.137 39.977 ;
     RECT  54.255 25.079 54.537 39.977 ;
     RECT  59.655 24.899 59.937 39.977 ;
     RECT  65.055 25.475 65.337 39.977 ;
     RECT  70.455 25.997 70.737 39.977 ;
     RECT  0.447 39.977 0.537 40.247 ;
     RECT  5.847 39.977 5.937 40.247 ;
     RECT  11.247 39.977 11.337 40.247 ;
     RECT  16.647 39.977 16.737 40.247 ;
     RECT  22.047 39.977 22.137 40.247 ;
     RECT  27.447 39.977 27.537 40.247 ;
     RECT  32.847 39.977 32.937 40.247 ;
     RECT  38.247 39.977 38.337 40.247 ;
     RECT  43.647 39.977 43.737 40.247 ;
     RECT  49.047 39.977 49.137 40.247 ;
     RECT  54.447 39.977 54.537 40.247 ;
     RECT  59.847 39.977 59.937 40.247 ;
     RECT  65.247 39.977 65.337 40.247 ;
     RECT  70.647 39.977 70.737 40.247 ;
    LAYER M4 ;
     RECT  0.025 1.104 0.133 24.888 ;
     RECT  0.133 1.056 0.156 24.888 ;
     RECT  0.156 0.624 0.241 25.176 ;
     RECT  0.241 0.624 0.248 25.224 ;
     RECT  0.156 40.128 0.248 40.152 ;
     RECT  0.248 0.528 0.352 40.152 ;
     RECT  0.352 0.576 0.44 40.152 ;
     RECT  0.44 0.576 0.544 40.242 ;
     RECT  0.544 0.576 5.648 25.224 ;
     RECT  5.648 0.528 5.752 39.972 ;
     RECT  5.752 0.576 5.84 39.972 ;
     RECT  5.84 0.576 5.944 40.242 ;
     RECT  5.944 0.576 8.597 25.224 ;
     RECT  8.597 0.576 9.137 25.176 ;
     RECT  9.137 0.576 10.825 24.792 ;
     RECT  10.825 0.576 10.837 25.032 ;
     RECT  10.837 0.576 11.048 25.08 ;
     RECT  11.048 0.528 11.152 39.972 ;
     RECT  11.152 0.576 11.24 39.972 ;
     RECT  11.24 0.576 11.344 40.242 ;
     RECT  11.344 0.576 11.987 25.224 ;
     RECT  11.987 0.576 13.565 25.08 ;
     RECT  13.565 0.576 16.448 25.032 ;
     RECT  16.448 0.528 16.552 39.972 ;
     RECT  16.552 0.576 16.64 39.972 ;
     RECT  16.64 0.576 16.744 40.242 ;
     RECT  16.744 0.576 21.848 25.032 ;
     RECT  21.848 0.528 21.952 39.972 ;
     RECT  21.952 0.576 22.04 39.972 ;
     RECT  22.04 0.576 22.144 40.242 ;
     RECT  22.144 0.576 26.809 25.032 ;
     RECT  26.809 0.576 27.248 25.08 ;
     RECT  27.248 0.528 27.352 39.972 ;
     RECT  27.352 0.672 27.44 39.972 ;
     RECT  27.44 0.672 27.544 40.242 ;
     RECT  27.544 0.672 28.505 25.272 ;
     RECT  28.505 0.672 28.577 25.176 ;
     RECT  28.577 0.912 28.691 25.176 ;
     RECT  28.691 0.912 30.121 25.032 ;
     RECT  30.121 0.912 31.025 25.08 ;
     RECT  31.025 0.912 31.277 25.032 ;
     RECT  31.277 1.2 32.648 25.032 ;
     RECT  32.648 0.528 32.752 39.972 ;
     RECT  32.752 0.798 32.84 39.972 ;
     RECT  32.84 0.798 32.944 40.242 ;
     RECT  32.944 1.152 34.765 25.032 ;
     RECT  34.765 0.72 34.789 25.032 ;
     RECT  34.789 0.72 35.363 25.176 ;
     RECT  35.363 0.72 38.048 25.032 ;
     RECT  38.048 0.528 38.152 39.972 ;
     RECT  38.152 0.72 38.24 39.972 ;
     RECT  38.24 0.72 38.344 40.242 ;
     RECT  38.344 0.72 42.757 25.032 ;
     RECT  42.757 0.624 43.448 25.032 ;
     RECT  43.448 0.528 43.552 39.972 ;
     RECT  43.552 0.624 43.64 39.972 ;
     RECT  43.64 0.624 43.744 40.242 ;
     RECT  43.744 0.624 46.793 25.032 ;
     RECT  46.793 0.72 48.848 25.032 ;
     RECT  48.848 0.528 48.952 39.972 ;
     RECT  48.952 0.72 49.04 39.972 ;
     RECT  49.04 0.72 49.144 40.242 ;
     RECT  49.144 0.72 50.605 25.032 ;
     RECT  50.605 0.72 50.713 25.08 ;
     RECT  50.713 0.624 51.725 25.08 ;
     RECT  51.725 0.624 52.445 25.032 ;
     RECT  52.445 12 52.697 25.032 ;
     RECT  52.445 0.624 54.248 11.016 ;
     RECT  52.697 12 54.248 24.984 ;
     RECT  54.248 0.528 54.352 39.972 ;
     RECT  54.352 0.624 54.44 39.972 ;
     RECT  54.44 0.624 54.544 40.242 ;
     RECT  54.544 0.624 54.755 24.984 ;
     RECT  54.755 1.152 54.851 24.984 ;
     RECT  54.851 1.152 54.929 11.112 ;
     RECT  54.929 1.248 56.513 11.112 ;
     RECT  54.851 12.096 57.553 24.984 ;
     RECT  56.513 1.248 58.453 10.968 ;
     RECT  57.553 11.952 58.453 24.984 ;
     RECT  58.453 1.248 58.693 24.984 ;
     RECT  58.693 0.72 59.648 24.984 ;
     RECT  59.648 0.528 59.752 39.972 ;
     RECT  59.752 0.72 59.84 39.972 ;
     RECT  59.84 0.72 59.944 40.242 ;
     RECT  59.944 12.096 63.251 24.984 ;
     RECT  59.944 0.72 63.253 11.016 ;
     RECT  63.251 12.096 63.253 13.416 ;
     RECT  63.253 0.672 63.317 13.416 ;
     RECT  63.317 8.976 63.389 13.416 ;
     RECT  63.317 0.72 63.395 7.944 ;
     RECT  63.389 8.976 63.749 10.872 ;
     RECT  63.749 9.456 63.827 10.872 ;
     RECT  63.827 9.456 63.971 10.728 ;
     RECT  63.395 1.248 64.717 7.944 ;
     RECT  64.717 0.672 64.897 7.944 ;
     RECT  64.897 0.672 65.048 7.992 ;
     RECT  63.971 9.6 65.048 10.728 ;
     RECT  63.389 12 65.048 13.416 ;
     RECT  63.251 14.448 65.048 24.984 ;
     RECT  65.048 0.528 65.152 39.972 ;
     RECT  65.152 0.624 65.24 39.972 ;
     RECT  65.24 0.624 65.344 40.242 ;
     RECT  65.344 0.624 65.603 7.992 ;
     RECT  65.603 0.672 66.131 7.992 ;
     RECT  65.344 14.448 66.161 24.792 ;
     RECT  66.131 1.104 66.697 7.992 ;
     RECT  65.344 9.84 66.737 13.416 ;
     RECT  66.697 1.104 66.845 8.808 ;
     RECT  66.845 1.104 66.851 8.088 ;
     RECT  66.851 7.584 66.881 8.088 ;
     RECT  66.737 9.84 66.947 13.224 ;
     RECT  66.881 7.584 66.953 7.896 ;
     RECT  66.953 7.584 67.025 7.848 ;
     RECT  66.161 14.832 67.025 24.792 ;
     RECT  67.025 20.832 67.133 24.792 ;
     RECT  66.947 9.84 67.237 10.584 ;
     RECT  67.025 14.832 67.283 18.312 ;
     RECT  67.237 9.312 67.781 10.584 ;
     RECT  67.781 9.84 67.909 10.584 ;
     RECT  66.947 11.664 67.909 13.224 ;
     RECT  67.909 9.84 67.961 13.224 ;
     RECT  66.851 1.104 68.389 6.408 ;
     RECT  67.025 7.584 68.389 7.608 ;
     RECT  68.389 7.584 68.641 7.704 ;
     RECT  67.283 14.832 68.785 18.264 ;
     RECT  67.025 19.392 68.785 19.8 ;
     RECT  68.785 14.832 68.821 19.8 ;
     RECT  68.821 14.832 68.857 19.848 ;
     RECT  68.641 7.584 68.965 7.992 ;
     RECT  67.961 9.84 68.965 10.68 ;
     RECT  67.961 11.664 68.965 13.224 ;
     RECT  68.965 8.976 69.301 10.68 ;
     RECT  68.965 11.664 69.301 13.416 ;
     RECT  67.133 20.88 69.397 24.792 ;
     RECT  68.389 0.912 69.493 6.408 ;
     RECT  68.965 7.44 69.493 7.992 ;
     RECT  69.493 0.912 69.541 7.992 ;
     RECT  69.301 8.976 69.541 13.416 ;
     RECT  68.857 14.544 69.541 19.848 ;
     RECT  69.541 14.4 69.829 19.848 ;
     RECT  69.397 20.88 69.829 24.984 ;
     RECT  69.541 0.72 69.865 13.416 ;
     RECT  69.829 14.4 69.865 24.984 ;
     RECT  69.865 0.72 69.937 24.984 ;
     RECT  69.937 0.72 70.009 25.608 ;
     RECT  70.009 0.672 70.117 25.608 ;
     RECT  70.117 0.624 70.448 25.608 ;
     RECT  70.448 0.528 70.552 39.972 ;
     RECT  70.552 0.624 70.64 39.972 ;
     RECT  70.64 0.624 70.661 40.242 ;
     RECT  70.661 0.672 70.744 40.242 ;
     RECT  70.744 0.672 71.237 25.992 ;
     RECT  71.237 0.768 71.417 25.992 ;
     RECT  71.417 0.768 72.421 25.848 ;
     RECT  72.421 0.672 72.601 25.848 ;
     RECT  72.601 0.624 72.785 25.848 ;
     RECT  72.785 0.624 72.828 25.176 ;
    LAYER M5 ;
     RECT  54.72 0.501 54.744 0.517 ;
     RECT  58.704 0.501 58.728 0.517 ;
     RECT  60.384 0.501 60.408 0.517 ;
     RECT  65.04 0.517 65.16 0.565 ;
     RECT  65.04 0.565 65.448 0.613 ;
     RECT  70.44 0.517 70.56 0.613 ;
     RECT  63.936 0.501 63.96 0.629 ;
     RECT  65.04 0.613 65.592 0.629 ;
     RECT  54.24 0.517 54.744 0.659 ;
     RECT  23.904 0.629 23.928 0.693 ;
     RECT  70.128 0.613 70.56 0.693 ;
     RECT  65.04 0.629 66.12 0.707 ;
     RECT  69.552 0.693 70.56 0.709 ;
     RECT  65.04 0.707 65.592 0.747 ;
     RECT  58.704 0.517 60.408 0.755 ;
     RECT  63.264 0.629 63.96 0.755 ;
     RECT  65.04 0.747 65.496 0.755 ;
     RECT  69.552 0.709 71.16 0.757 ;
     RECT  0.24 0.517 0.36 0.787 ;
     RECT  5.64 0.517 5.76 0.787 ;
     RECT  11.04 0.517 11.16 0.787 ;
     RECT  16.44 0.517 16.56 0.787 ;
     RECT  21.84 0.517 21.96 0.787 ;
     RECT  27.24 0.517 27.36 0.787 ;
     RECT  32.64 0.517 32.76 0.787 ;
     RECT  38.04 0.517 38.16 0.787 ;
     RECT  43.44 0.517 43.56 0.787 ;
     RECT  48.84 0.517 48.96 0.787 ;
     RECT  0.24 0.787 0.552 0.821 ;
     RECT  14.928 0.821 14.952 0.947 ;
     RECT  69.552 0.757 72.408 1.045 ;
     RECT  43.44 0.787 43.752 1.141 ;
     RECT  23.904 0.693 24.504 1.187 ;
     RECT  25.632 0.565 25.656 1.187 ;
     RECT  58.896 0.755 60.408 1.187 ;
     RECT  65.04 0.755 65.448 1.187 ;
     RECT  19.92 0.821 19.944 1.235 ;
     RECT  11.04 0.787 11.352 1.285 ;
     RECT  29.184 1.141 29.208 1.285 ;
     RECT  23.904 1.187 24.072 1.331 ;
     RECT  13.824 1.285 13.848 1.333 ;
     RECT  38.04 0.787 38.352 1.333 ;
     RECT  48.84 0.787 49.152 1.381 ;
     RECT  27.24 0.787 27.552 1.397 ;
     RECT  38.04 1.333 38.568 1.397 ;
     RECT  43.344 1.141 43.752 1.397 ;
     RECT  29.088 1.285 29.208 1.429 ;
     RECT  30.192 0.757 30.216 1.429 ;
     RECT  32.64 0.787 32.952 1.429 ;
     RECT  40.56 1.381 40.584 1.451 ;
     RECT  24.048 1.331 24.072 1.475 ;
     RECT  38.04 1.397 38.664 1.475 ;
     RECT  43.344 1.397 43.848 1.475 ;
     RECT  68.4 0.901 68.424 1.523 ;
     RECT  69.552 1.045 72.456 1.525 ;
     RECT  11.04 1.285 11.448 1.621 ;
     RECT  43.344 1.475 43.752 1.763 ;
     RECT  13.728 1.333 13.848 1.957 ;
     RECT  29.088 1.429 30.216 1.957 ;
     RECT  27.24 1.397 27.672 1.973 ;
     RECT  29.088 1.957 30.264 1.973 ;
     RECT  46.656 1.669 46.68 1.973 ;
     RECT  54.24 0.659 54.552 1.973 ;
     RECT  58.896 1.187 60.168 1.973 ;
     RECT  63.936 0.755 63.96 1.973 ;
     RECT  25.056 1.957 25.08 2.027 ;
     RECT  27.24 1.973 30.264 2.027 ;
     RECT  48.72 1.381 49.152 2.027 ;
     RECT  63.84 1.973 63.96 2.027 ;
     RECT  16.44 0.787 16.752 2.037 ;
     RECT  21.84 0.787 22.152 2.037 ;
     RECT  46.656 1.973 46.776 2.037 ;
     RECT  62.832 1.525 62.856 2.037 ;
     RECT  62.208 2.037 62.856 2.101 ;
     RECT  0.144 0.821 0.552 2.147 ;
     RECT  46.608 2.037 46.776 2.147 ;
     RECT  58.464 1.973 60.168 2.155 ;
     RECT  27.24 2.027 29.064 2.195 ;
     RECT  13.728 1.957 13.944 2.197 ;
     RECT  18.816 2.037 18.84 2.219 ;
     RECT  21.84 2.037 22.488 2.219 ;
     RECT  61.488 2.101 62.856 2.219 ;
     RECT  12.96 2.197 13.944 2.243 ;
     RECT  27.24 2.195 28.44 2.243 ;
     RECT  11.04 1.621 11.736 2.283 ;
     RECT  12.96 2.243 12.984 2.283 ;
     RECT  21.84 2.219 22.344 2.283 ;
     RECT  52.416 2.229 52.44 2.291 ;
     RECT  61.536 2.219 62.856 2.291 ;
     RECT  32.64 1.429 33.192 2.293 ;
     RECT  61.536 2.291 61.56 2.339 ;
     RECT  63.84 2.027 63.864 2.339 ;
     RECT  32.64 2.293 34.056 2.347 ;
     RECT  58.464 2.155 59.952 2.347 ;
     RECT  69.552 1.525 72.552 2.357 ;
     RECT  62.736 2.291 62.856 2.475 ;
     RECT  34.032 2.347 34.056 2.483 ;
     RECT  68.496 2.357 72.6 2.483 ;
     RECT  0.24 2.147 0.552 2.485 ;
     RECT  43.44 1.763 43.752 2.485 ;
     RECT  44.832 1.141 44.856 2.485 ;
     RECT  65.04 1.187 65.352 2.485 ;
     RECT  68.496 2.483 68.52 2.485 ;
     RECT  7.44 2.437 7.464 2.539 ;
     RECT  46.752 2.147 46.776 2.539 ;
     RECT  50.736 2.293 50.76 2.539 ;
     RECT  64.944 2.485 65.352 2.539 ;
     RECT  68.4 2.485 68.52 2.539 ;
     RECT  69.552 2.483 72.6 2.549 ;
     RECT  43.44 2.485 45 2.627 ;
     RECT  69.552 2.549 72.696 2.627 ;
     RECT  38.04 1.475 38.352 2.677 ;
     RECT  69.552 2.627 72.6 2.723 ;
     RECT  55.872 1.669 55.896 2.725 ;
     RECT  35.712 2.677 35.736 2.731 ;
     RECT  69.552 2.723 72.456 2.731 ;
     RECT  37.056 2.677 38.352 2.771 ;
     RECT  37.92 2.771 38.352 2.859 ;
     RECT  54.24 1.973 54.888 2.869 ;
     RECT  55.872 2.725 56.424 2.869 ;
     RECT  65.04 2.539 65.352 2.869 ;
     RECT  35.904 2.805 35.928 2.915 ;
     RECT  54.24 2.869 56.424 2.915 ;
     RECT  66.912 2.581 66.936 2.923 ;
     RECT  16.44 2.037 16.872 2.965 ;
     RECT  4.512 2.933 4.536 3.011 ;
     RECT  65.04 2.869 65.448 3.125 ;
     RECT  58.656 2.347 59.952 3.155 ;
     RECT  0.24 2.485 0.648 3.253 ;
     RECT  16.44 2.965 17.112 3.301 ;
     RECT  52.992 3.253 53.016 3.307 ;
     RECT  16.32 3.301 17.112 3.371 ;
     RECT  16.44 3.371 17.112 3.397 ;
     RECT  45.984 3.349 46.632 3.435 ;
     RECT  3.936 3.157 3.96 3.445 ;
     RECT  5.64 0.787 5.952 3.445 ;
     RECT  3.024 3.445 3.96 3.493 ;
     RECT  2.832 3.493 3.96 3.499 ;
     RECT  11.04 2.283 11.352 3.509 ;
     RECT  54.24 2.915 55.992 3.541 ;
     RECT  10.224 3.509 11.352 3.573 ;
     RECT  59.64 3.155 59.952 3.573 ;
     RECT  62.736 2.475 62.76 3.573 ;
     RECT  2.832 3.499 3.384 3.587 ;
     RECT  10.224 3.573 11.448 3.587 ;
     RECT  46.608 3.435 46.632 3.627 ;
     RECT  53.472 3.541 55.992 3.627 ;
     RECT  10.32 3.587 11.448 3.635 ;
     RECT  65.04 3.125 65.544 3.637 ;
     RECT  2.832 3.587 3.048 3.683 ;
     RECT  43.44 2.627 44.472 3.701 ;
     RECT  62.736 3.573 62.904 3.701 ;
     RECT  51.264 3.637 51.288 3.731 ;
     RECT  65.04 3.637 66.168 3.731 ;
     RECT  42.144 3.685 42.168 3.755 ;
     RECT  43.344 3.701 44.472 3.755 ;
     RECT  21.84 2.283 22.152 3.765 ;
     RECT  48.84 2.027 49.152 3.765 ;
     RECT  50.16 3.733 50.184 3.765 ;
     RECT  62.112 3.701 62.904 3.765 ;
     RECT  61.584 3.765 62.904 3.779 ;
     RECT  50.16 3.765 50.28 3.819 ;
     RECT  59.64 3.573 60.456 3.819 ;
     RECT  62.784 3.779 62.904 3.819 ;
     RECT  13.728 3.765 13.752 3.827 ;
     RECT  15.36 3.765 15.384 3.827 ;
     RECT  5.088 3.445 5.952 3.883 ;
     RECT  23.568 3.829 23.592 3.883 ;
     RECT  30.96 3.445 30.984 3.883 ;
     RECT  62.784 3.819 62.808 3.883 ;
     RECT  54.24 3.627 55.992 3.925 ;
     RECT  18.816 3.765 18.84 3.947 ;
     RECT  21.12 3.765 22.152 3.947 ;
     RECT  46.752 3.765 46.776 3.947 ;
     RECT  50.256 3.819 50.28 3.947 ;
     RECT  54.24 3.925 56.184 3.947 ;
     RECT  63.84 3.893 63.864 3.957 ;
     RECT  65.04 3.731 65.448 3.957 ;
     RECT  16.44 3.397 17.64 4.011 ;
     RECT  56.16 3.947 56.184 4.011 ;
     RECT  63.84 3.957 65.448 4.019 ;
     RECT  35.376 4.021 35.4 4.115 ;
     RECT  16.44 4.011 16.872 4.139 ;
     RECT  19.728 4.069 19.752 4.139 ;
     RECT  21.168 3.947 22.152 4.139 ;
     RECT  69.552 2.731 72.408 4.149 ;
     RECT  56.688 4.069 56.808 4.203 ;
     RECT  64.416 4.019 65.448 4.211 ;
     RECT  43.344 3.755 43.752 4.259 ;
     RECT  56.784 4.203 56.808 4.267 ;
     RECT  69.552 4.149 72.456 4.277 ;
     RECT  0.144 3.253 0.648 4.307 ;
     RECT  21.648 4.139 22.152 4.331 ;
     RECT  69.552 4.277 72.504 4.341 ;
     RECT  69.408 4.341 72.504 4.403 ;
     RECT  27.24 2.243 27.552 4.405 ;
     RECT  30.192 4.085 30.216 4.451 ;
     RECT  27.12 4.405 27.552 4.459 ;
     RECT  28.752 4.405 28.776 4.459 ;
     RECT  59.64 3.819 60.072 4.469 ;
     RECT  9.072 4.533 9.096 4.595 ;
     RECT  58.704 4.469 60.072 4.595 ;
     RECT  2.832 3.683 2.904 4.597 ;
     RECT  48.288 3.765 49.152 4.597 ;
     RECT  10.56 3.635 11.352 4.645 ;
     RECT  2.256 4.597 2.904 4.651 ;
     RECT  59.64 4.595 60.072 4.651 ;
     RECT  61.584 3.779 61.608 4.651 ;
     RECT  47.856 4.597 49.152 4.693 ;
     RECT  10.56 4.645 11.64 4.715 ;
     RECT  69.408 4.403 72.456 4.741 ;
     RECT  47.52 4.693 49.152 4.779 ;
     RECT  14.832 4.645 14.952 4.787 ;
     RECT  64.944 4.211 65.448 4.787 ;
     RECT  21.84 4.331 22.152 4.853 ;
     RECT  54.24 3.947 54.552 4.917 ;
     RECT  21.84 4.853 22.44 4.931 ;
     RECT  53.568 4.917 54.552 4.979 ;
     RECT  68.928 4.741 72.456 4.979 ;
     RECT  14.832 4.787 14.856 5.027 ;
     RECT  43.44 4.259 43.752 5.029 ;
     RECT  29.376 5.029 29.4 5.099 ;
     RECT  38.04 2.859 38.352 5.109 ;
     RECT  2.832 4.651 2.904 5.123 ;
     RECT  20.784 5.109 20.808 5.171 ;
     RECT  38.04 5.109 38.76 5.171 ;
     RECT  47.52 4.779 47.544 5.227 ;
     RECT  48.72 4.779 49.152 5.227 ;
     RECT  52.848 5.173 52.872 5.227 ;
     RECT  56.976 5.221 57 5.291 ;
     RECT  64.944 4.787 65.352 5.291 ;
     RECT  10.56 4.715 11.448 5.301 ;
     RECT  5.64 3.883 5.952 5.365 ;
     RECT  10.224 5.301 11.448 5.411 ;
     RECT  0.24 4.307 0.648 5.413 ;
     RECT  38.04 5.171 38.352 5.413 ;
     RECT  2.832 5.123 2.856 5.419 ;
     RECT  5.52 5.365 5.952 5.459 ;
     RECT  11.04 5.411 11.448 5.547 ;
     RECT  21.84 4.931 22.152 5.557 ;
     RECT  54.24 4.979 54.552 5.557 ;
     RECT  27.24 4.459 27.552 5.685 ;
     RECT  40.656 4.261 40.68 5.701 ;
     RECT  59.64 4.651 59.952 5.701 ;
     RECT  21.072 5.557 22.152 5.747 ;
     RECT  69.504 4.979 72.456 5.747 ;
     RECT  65.04 5.291 65.352 5.749 ;
     RECT  69.552 5.747 72.456 5.749 ;
     RECT  2.256 5.653 2.28 5.795 ;
     RECT  40.368 5.701 40.68 5.803 ;
     RECT  58.656 5.701 59.952 5.803 ;
     RECT  69.552 5.749 72.504 5.803 ;
     RECT  26.784 5.685 27.552 5.867 ;
     RECT  31.344 5.685 31.464 5.867 ;
     RECT  23.952 5.813 23.976 5.877 ;
     RECT  9.648 5.685 9.768 5.891 ;
     RECT  0.144 5.413 0.648 5.893 ;
     RECT  37.92 5.413 38.352 5.893 ;
     RECT  23.952 5.877 24.504 5.939 ;
     RECT  9.744 5.891 9.768 5.987 ;
     RECT  0.144 5.893 0.744 5.995 ;
     RECT  37.104 5.893 38.352 5.995 ;
     RECT  65.04 5.749 65.592 6.005 ;
     RECT  66.816 5.685 66.84 6.005 ;
     RECT  65.04 6.005 66.84 6.123 ;
     RECT  5.64 5.459 5.952 6.133 ;
     RECT  54.24 5.557 54.792 6.197 ;
     RECT  5.64 6.133 6.744 6.227 ;
     RECT  34.656 5.941 34.68 6.227 ;
     RECT  23.952 5.939 24.024 6.251 ;
     RECT  25.728 5.749 25.752 6.251 ;
     RECT  31.104 6.133 31.128 6.251 ;
     RECT  65.04 6.123 66.744 6.251 ;
     RECT  38.04 5.995 38.352 6.261 ;
     RECT  56.4 5.701 56.904 6.261 ;
     RECT  14.544 6.197 14.568 6.275 ;
     RECT  21.744 5.747 22.152 6.275 ;
     RECT  43.44 5.029 44.616 6.275 ;
     RECT  53.568 6.197 54.84 6.275 ;
     RECT  23.952 6.251 23.976 6.323 ;
     RECT  56.4 6.261 57 6.323 ;
     RECT  65.04 6.251 66.696 6.323 ;
     RECT  65.04 6.323 65.592 6.371 ;
     RECT  27.24 5.867 27.552 6.421 ;
     RECT  0.144 5.995 0.552 6.467 ;
     RECT  69.552 5.803 72.456 6.707 ;
     RECT  3.648 6.709 3.672 6.757 ;
     RECT  42.144 6.261 42.168 6.757 ;
     RECT  56.4 6.323 56.472 6.757 ;
     RECT  38.04 6.261 39.048 6.805 ;
     RECT  46.656 6.197 46.68 6.805 ;
     RECT  3.408 6.757 3.672 6.827 ;
     RECT  40.896 6.277 41.016 6.827 ;
     RECT  42.144 6.757 42.408 6.827 ;
     RECT  11.04 5.547 11.352 6.837 ;
     RECT  27.24 6.421 27.912 6.837 ;
     RECT  32.64 2.347 32.952 6.837 ;
     RECT  65.04 6.371 65.352 6.837 ;
     RECT  69.552 6.707 72.408 6.837 ;
     RECT  46.656 6.805 47.304 6.851 ;
     RECT  10.944 6.837 11.352 6.853 ;
     RECT  47.28 6.851 47.304 6.891 ;
     RECT  56.304 6.757 56.472 6.891 ;
     RECT  31.92 6.837 32.952 6.899 ;
     RECT  42.144 6.827 42.216 6.899 ;
     RECT  69.504 6.837 72.408 6.899 ;
     RECT  36.192 6.837 36.216 6.947 ;
     RECT  56.4 6.891 56.472 6.947 ;
     RECT  42.144 6.899 42.168 6.995 ;
     RECT  2.208 6.901 2.232 7.139 ;
     RECT  16.44 4.139 16.752 7.237 ;
     RECT  27.24 6.837 28.008 7.283 ;
     RECT  66.672 6.323 66.696 7.333 ;
     RECT  32.64 6.899 32.952 7.381 ;
     RECT  4.272 7.285 4.296 7.403 ;
     RECT  15.792 7.237 16.752 7.403 ;
     RECT  66.672 7.333 66.84 7.403 ;
     RECT  5.64 6.227 6.552 7.413 ;
     RECT  30.72 7.349 30.744 7.427 ;
     RECT  32.64 7.381 33.192 7.467 ;
     RECT  52.032 7.381 52.056 7.467 ;
     RECT  56.448 6.947 56.472 7.467 ;
     RECT  66.672 7.403 66.744 7.475 ;
     RECT  0.24 6.467 0.552 7.525 ;
     RECT  64.416 6.837 65.352 7.541 ;
     RECT  2.256 7.477 2.28 7.619 ;
     RECT  9.648 7.541 9.672 7.619 ;
     RECT  64.416 7.541 66.12 7.619 ;
     RECT  38.04 6.805 39.336 7.659 ;
     RECT  14.352 7.525 14.376 7.667 ;
     RECT  69.552 6.899 72.408 7.717 ;
     RECT  68.4 7.669 68.424 7.723 ;
     RECT  59.64 5.803 59.952 7.733 ;
     RECT  5.64 7.413 6.696 7.797 ;
     RECT  48.84 5.227 49.152 7.797 ;
     RECT  48.84 7.797 49.56 7.859 ;
     RECT  59.472 7.733 59.952 7.859 ;
     RECT  64.416 7.619 65.592 7.861 ;
     RECT  69.552 7.717 72.456 7.861 ;
     RECT  48.84 7.859 49.152 7.909 ;
     RECT  18.768 7.861 18.792 7.915 ;
     RECT  64.08 7.861 65.592 7.915 ;
     RECT  69.552 7.861 72.552 7.955 ;
     RECT  10.848 6.853 11.352 7.957 ;
     RECT  41.088 7.909 41.112 7.979 ;
     RECT  20.592 7.429 20.616 7.989 ;
     RECT  48.72 7.909 49.152 7.989 ;
     RECT  5.64 7.797 6.888 8.003 ;
     RECT  69.552 7.955 72.456 8.051 ;
     RECT  20.544 7.989 20.616 8.099 ;
     RECT  0.144 7.525 0.552 8.101 ;
     RECT  21.84 6.275 22.152 8.101 ;
     RECT  69.552 8.051 72.36 8.117 ;
     RECT  38.04 7.659 38.664 8.147 ;
     RECT  21.072 8.101 22.152 8.171 ;
     RECT  38.04 8.147 38.472 8.293 ;
     RECT  68.976 8.117 72.36 8.299 ;
     RECT  32.64 7.467 32.952 8.341 ;
     RECT  36.432 8.309 36.456 8.387 ;
     RECT  32.112 8.341 32.952 8.427 ;
     RECT  3.744 8.373 3.768 8.435 ;
     RECT  10.8 7.957 11.352 8.437 ;
     RECT  10.8 8.437 11.688 8.491 ;
     RECT  14.256 8.437 14.28 8.491 ;
     RECT  43.44 6.275 43.752 8.533 ;
     RECT  32.448 8.427 32.952 8.555 ;
     RECT  37.92 8.293 38.472 8.555 ;
     RECT  47.856 7.989 49.152 8.579 ;
     RECT  8.88 8.565 8.904 8.581 ;
     RECT  0.144 8.101 0.648 8.619 ;
     RECT  7.392 8.485 7.416 8.619 ;
     RECT  43.344 8.533 43.848 8.619 ;
     RECT  46.176 8.437 46.2 8.619 ;
     RECT  0.144 8.619 0.552 8.627 ;
     RECT  27.24 7.283 27.552 8.629 ;
     RECT  8.88 8.581 9.096 8.675 ;
     RECT  9.072 8.675 9.096 8.683 ;
     RECT  18.672 8.629 18.696 8.747 ;
     RECT  19.968 8.485 19.992 8.747 ;
     RECT  26.784 8.629 28.392 8.811 ;
     RECT  27.072 8.811 27.912 8.875 ;
     RECT  27.12 8.875 27.912 9.003 ;
     RECT  69.744 8.299 72.36 9.061 ;
     RECT  51.888 9.013 51.912 9.067 ;
     RECT  43.344 8.619 43.752 9.077 ;
     RECT  46.704 9.061 46.728 9.131 ;
     RECT  62.112 8.677 62.136 9.155 ;
     RECT  38.04 8.555 38.472 9.203 ;
     RECT  32.544 8.555 32.952 9.301 ;
     RECT  27.24 9.003 27.912 9.323 ;
     RECT  67.248 9.269 67.272 9.347 ;
     RECT  32.544 9.301 33.048 9.387 ;
     RECT  34.656 9.205 34.68 9.451 ;
     RECT  63.936 9.205 63.96 9.491 ;
     RECT  32.64 9.387 33.048 9.515 ;
     RECT  42.72 9.077 43.752 9.541 ;
     RECT  42.192 9.541 43.752 9.587 ;
     RECT  16.44 7.403 16.752 9.589 ;
     RECT  65.04 7.915 65.352 9.637 ;
     RECT  16.32 9.589 16.872 9.643 ;
     RECT  64.368 9.637 65.352 9.707 ;
     RECT  62.64 9.589 63.384 9.731 ;
     RECT  0.24 8.627 0.552 9.733 ;
     RECT  42.192 9.587 42.216 9.771 ;
     RECT  25.632 9.717 25.656 9.779 ;
     RECT  39.888 9.717 39.912 9.779 ;
     RECT  57.744 9.397 57.768 9.835 ;
     RECT  11.04 8.491 11.352 9.845 ;
     RECT  69.744 9.061 72.408 9.845 ;
     RECT  10.224 9.845 11.352 9.923 ;
     RECT  27.24 9.323 27.672 10.027 ;
     RECT  44.976 9.973 45 10.027 ;
     RECT  0.144 9.733 0.552 10.069 ;
     RECT  57.648 10.021 57.672 10.101 ;
     RECT  57.552 10.101 57.672 10.163 ;
     RECT  0.144 10.069 1.272 10.211 ;
     RECT  43.44 9.587 43.752 10.213 ;
     RECT  69.552 9.845 72.408 10.261 ;
     RECT  43.44 10.213 44.424 10.283 ;
     RECT  55.584 9.925 55.608 10.283 ;
     RECT  57.024 10.213 57.048 10.283 ;
     RECT  33.936 10.293 34.2 10.355 ;
     RECT  69.552 10.261 72.456 10.405 ;
     RECT  34.176 10.355 34.2 10.411 ;
     RECT  36.816 10.357 36.84 10.411 ;
     RECT  19.344 10.421 19.368 10.453 ;
     RECT  31.296 10.293 31.32 10.485 ;
     RECT  18.672 10.453 19.368 10.499 ;
     RECT  31.2 10.485 31.32 10.499 ;
     RECT  31.2 10.499 31.224 10.547 ;
     RECT  62.16 10.405 62.184 10.597 ;
     RECT  69.552 10.405 72.504 10.597 ;
     RECT  18.672 10.499 18.696 10.603 ;
     RECT  69.552 10.597 72.696 10.613 ;
     RECT  65.04 9.707 65.352 10.645 ;
     RECT  68.352 10.597 68.376 10.645 ;
     RECT  2.976 10.597 3 10.677 ;
     RECT  48.84 8.579 49.152 10.677 ;
     RECT  61.824 10.597 62.184 10.691 ;
     RECT  65.04 10.645 66.12 10.731 ;
     RECT  69.552 10.613 72.792 10.739 ;
     RECT  8.88 10.549 8.904 10.741 ;
     RECT  54.24 6.275 54.552 10.741 ;
     RECT  68.352 10.645 68.52 10.741 ;
     RECT  53.04 10.741 53.064 10.795 ;
     RECT  61.824 10.691 61.848 10.795 ;
     RECT  2.256 10.677 3 10.805 ;
     RECT  51.264 10.613 51.288 10.805 ;
     RECT  63.744 10.613 63.768 10.805 ;
     RECT  5.64 8.003 5.952 10.837 ;
     RECT  43.44 10.283 43.752 10.837 ;
     RECT  67.92 10.741 68.52 10.859 ;
     RECT  2.256 10.805 3.432 10.869 ;
     RECT  5.64 10.837 6.744 10.869 ;
     RECT  46.128 10.837 46.152 10.869 ;
     RECT  63.744 10.805 63.816 10.869 ;
     RECT  58.416 10.805 58.44 10.883 ;
     RECT  63.216 10.869 63.816 10.883 ;
     RECT  5.184 10.869 6.744 10.923 ;
     RECT  43.008 10.837 43.752 10.923 ;
     RECT  67.92 10.859 67.944 10.923 ;
     RECT  63.216 10.883 63.288 10.931 ;
     RECT  2.256 10.869 3.96 10.933 ;
     RECT  59.64 7.859 59.952 10.933 ;
     RECT  11.04 9.923 11.352 10.981 ;
     RECT  50.832 10.805 51.288 10.981 ;
     RECT  2.208 10.933 3.96 10.987 ;
     RECT  25.632 10.837 25.656 10.987 ;
     RECT  46.032 10.869 46.152 10.997 ;
     RECT  54.24 10.741 55.032 11.027 ;
     RECT  10.8 10.981 11.352 11.029 ;
     RECT  15.408 10.117 15.432 11.061 ;
     RECT  16.44 9.643 16.752 11.061 ;
     RECT  21.84 8.171 22.152 11.061 ;
     RECT  23.136 10.213 23.16 11.061 ;
     RECT  3.408 10.987 3.96 11.075 ;
     RECT  10.224 11.029 11.352 11.115 ;
     RECT  25.44 11.029 25.56 11.115 ;
     RECT  5.184 10.923 5.952 11.123 ;
     RECT  8.736 10.741 8.904 11.123 ;
     RECT  14.832 11.061 16.752 11.123 ;
     RECT  43.2 10.923 43.752 11.179 ;
     RECT  52.56 10.805 52.584 11.179 ;
     RECT  54.24 11.027 54.84 11.179 ;
     RECT  63.264 10.931 63.288 11.179 ;
     RECT  10.8 11.115 11.352 11.219 ;
     RECT  14.832 11.123 14.856 11.243 ;
     RECT  16.128 11.123 16.752 11.243 ;
     RECT  25.536 11.115 25.56 11.243 ;
     RECT  21.84 11.061 23.16 11.253 ;
     RECT  66.72 10.933 66.84 11.269 ;
     RECT  58.512 10.933 59.952 11.307 ;
     RECT  58.608 11.307 58.632 11.315 ;
     RECT  69.552 10.739 72.312 11.317 ;
     RECT  21.84 11.253 23.352 11.363 ;
     RECT  30.768 11.189 30.792 11.363 ;
     RECT  41.184 10.869 41.208 11.363 ;
     RECT  50.736 10.981 51.288 11.435 ;
     RECT  45.12 10.997 46.152 11.445 ;
     RECT  3.936 11.075 3.96 11.459 ;
     RECT  9.696 11.381 9.72 11.459 ;
     RECT  69.312 11.317 72.312 11.555 ;
     RECT  48.84 10.677 49.272 11.557 ;
     RECT  66.72 11.269 66.936 11.563 ;
     RECT  0.144 10.211 0.648 11.573 ;
     RECT  45.024 11.445 46.152 11.573 ;
     RECT  21.84 11.363 22.872 11.603 ;
     RECT  35.328 11.509 35.352 11.603 ;
     RECT  50.736 11.435 50.904 11.627 ;
     RECT  0.144 11.573 0.744 11.637 ;
     RECT  43.344 11.179 43.752 11.637 ;
     RECT  45.024 11.573 46.728 11.637 ;
     RECT  48.84 11.557 49.752 11.637 ;
     RECT  50.736 11.627 50.856 11.637 ;
     RECT  41.04 11.573 41.064 11.651 ;
     RECT  43.344 11.637 46.728 11.691 ;
     RECT  47.712 11.029 47.736 11.691 ;
     RECT  48.84 11.637 50.856 11.691 ;
     RECT  43.344 11.691 45.048 11.699 ;
     RECT  69.36 11.555 72.312 11.701 ;
     RECT  2.256 10.987 2.28 11.747 ;
     RECT  69.36 11.701 72.408 11.765 ;
     RECT  0.144 11.637 0.792 11.891 ;
     RECT  48.84 11.691 49.992 11.891 ;
     RECT  48.84 11.891 49.8 11.939 ;
     RECT  0.144 11.891 0.744 12.035 ;
     RECT  29.616 11.445 29.64 12.035 ;
     RECT  46.128 11.691 46.728 12.085 ;
     RECT  59.64 11.307 59.952 12.149 ;
     RECT  66.72 11.563 66.84 12.149 ;
     RECT  46.128 12.085 47.208 12.179 ;
     RECT  69.36 11.765 72.456 12.213 ;
     RECT  12.336 12.181 12.36 12.267 ;
     RECT  16.32 11.243 16.752 12.267 ;
     RECT  46.752 12.179 47.208 12.267 ;
     RECT  35.136 12.213 35.16 12.275 ;
     RECT  46.752 12.267 46.776 12.275 ;
     RECT  65.04 10.731 65.352 12.325 ;
     RECT  45.024 11.699 45.048 12.371 ;
     RECT  59.64 12.149 60.552 12.371 ;
     RECT  66.576 12.149 66.84 12.371 ;
     RECT  10.944 11.219 11.352 12.467 ;
     RECT  13.68 12.213 13.704 12.467 ;
     RECT  19.008 11.509 19.032 12.467 ;
     RECT  32.64 9.515 32.952 12.725 ;
     RECT  69.36 12.213 72.504 12.757 ;
     RECT  0.144 12.035 0.648 12.779 ;
     RECT  29.184 12.325 29.208 12.779 ;
     RECT  66.72 12.371 66.744 12.779 ;
     RECT  31.776 12.725 32.952 12.803 ;
     RECT  63.072 12.725 63.096 12.803 ;
     RECT  64.464 12.325 65.352 12.843 ;
     RECT  68.4 12.757 72.504 12.843 ;
     RECT  32.64 12.803 32.952 12.853 ;
     RECT  21.84 11.603 22.152 12.901 ;
     RECT  32.64 12.853 33.624 12.949 ;
     RECT  0.144 12.779 0.552 12.971 ;
     RECT  68.928 12.843 72.504 12.971 ;
     RECT  21.84 12.901 22.248 12.981 ;
     RECT  48.84 11.939 49.152 12.981 ;
     RECT  21.84 12.981 22.728 13.043 ;
     RECT  23.952 12.981 23.976 13.043 ;
     RECT  47.76 12.981 49.152 13.043 ;
     RECT  27.24 10.027 27.552 13.045 ;
     RECT  35.616 12.997 35.64 13.045 ;
     RECT  32.64 12.949 33.816 13.091 ;
     RECT  25.632 12.997 25.656 13.099 ;
     RECT  35.616 13.045 35.88 13.099 ;
     RECT  39.888 13.045 39.912 13.099 ;
     RECT  27.24 13.045 27.816 13.109 ;
     RECT  48.48 13.043 49.152 13.163 ;
     RECT  58.32 12.901 58.344 13.163 ;
     RECT  27.24 13.109 27.912 13.187 ;
     RECT  15.36 13.173 15.384 13.235 ;
     RECT  38.04 9.203 38.352 13.285 ;
     RECT  59.64 12.371 59.952 13.285 ;
     RECT  35.616 13.099 35.64 13.291 ;
     RECT  24.48 13.237 24.504 13.331 ;
     RECT  59.52 13.285 59.952 13.333 ;
     RECT  32.64 13.091 33.672 13.355 ;
     RECT  37.584 13.285 39.24 13.355 ;
     RECT  68.976 12.971 72.504 13.419 ;
     RECT  20.736 13.237 20.76 13.475 ;
     RECT  9.984 13.333 10.008 13.493 ;
     RECT  21.84 13.043 22.152 13.525 ;
     RECT  8.064 13.477 8.088 13.547 ;
     RECT  68.976 13.419 69.096 13.547 ;
     RECT  5.64 11.123 5.952 13.573 ;
     RECT  9.744 13.493 10.008 13.573 ;
     RECT  11.04 12.467 11.352 13.573 ;
     RECT  35.136 13.477 35.16 13.611 ;
     RECT  2.256 13.285 2.28 13.619 ;
     RECT  5.64 13.573 6.648 13.675 ;
     RECT  68.976 13.547 69 13.675 ;
     RECT  9.744 13.573 11.352 13.685 ;
     RECT  9.648 13.685 11.352 13.739 ;
     RECT  26.064 13.477 26.088 13.739 ;
     RECT  9.648 13.739 10.008 13.763 ;
     RECT  16.44 12.267 16.752 13.765 ;
     RECT  43.44 11.699 43.752 13.813 ;
     RECT  40.416 13.813 40.44 13.867 ;
     RECT  0.24 12.971 0.552 13.941 ;
     RECT  16.44 13.765 16.872 13.995 ;
     RECT  29.184 14.005 29.208 14.059 ;
     RECT  0.144 13.941 0.552 14.069 ;
     RECT  48.72 13.163 49.152 14.069 ;
     RECT  43.344 13.813 43.752 14.101 ;
     RECT  46.752 14.053 46.776 14.123 ;
     RECT  70.128 13.419 72.504 14.149 ;
     RECT  27.24 13.187 27.816 14.187 ;
     RECT  43.344 14.101 44.664 14.187 ;
     RECT  48.72 14.069 49.272 14.187 ;
     RECT  32.64 13.355 32.952 14.197 ;
     RECT  54.24 11.179 54.552 14.197 ;
     RECT  59.28 13.333 59.952 14.197 ;
     RECT  63.024 13.941 63.048 14.197 ;
     RECT  43.344 14.187 43.752 14.251 ;
     RECT  44.976 14.197 45 14.251 ;
     RECT  54.144 14.197 54.552 14.251 ;
     RECT  57.024 13.941 57.048 14.251 ;
     RECT  59.28 14.197 60.936 14.251 ;
     RECT  62.88 14.197 63.24 14.261 ;
     RECT  32.496 14.197 32.952 14.291 ;
     RECT  61.92 14.261 63.24 14.339 ;
     RECT  0.144 14.069 0.696 14.387 ;
     RECT  65.04 12.843 65.352 14.453 ;
     RECT  62.112 14.339 63.24 14.483 ;
     RECT  57.12 14.389 57.144 14.485 ;
     RECT  57.12 14.485 58.008 14.571 ;
     RECT  68.928 14.517 68.952 14.579 ;
     RECT  62.736 14.483 63.24 14.581 ;
     RECT  62.736 14.581 63.288 14.709 ;
     RECT  70.128 14.149 72.6 14.709 ;
     RECT  51.84 14.677 51.864 14.763 ;
     RECT  65.04 14.453 65.736 14.763 ;
     RECT  62.736 14.709 63.72 14.771 ;
     RECT  21.072 13.525 22.152 14.773 ;
     RECT  37.008 14.389 37.032 14.773 ;
     RECT  20.496 14.773 22.152 14.891 ;
     RECT  11.04 13.739 11.352 14.901 ;
     RECT  66.48 14.837 66.6 14.915 ;
     RECT  70.08 14.709 72.6 14.915 ;
     RECT  56.016 14.869 56.04 14.955 ;
     RECT  57.984 14.571 58.008 14.955 ;
     RECT  3.888 14.821 3.912 14.963 ;
     RECT  6.96 14.901 6.984 14.963 ;
     RECT  8.88 14.901 8.904 14.963 ;
     RECT  9.984 13.763 10.008 14.963 ;
     RECT  32.544 14.291 32.952 14.965 ;
     RECT  62.736 14.771 62.76 15.019 ;
     RECT  66.576 14.915 66.6 15.019 ;
     RECT  2.208 14.917 2.232 15.061 ;
     RECT  2.208 15.061 2.28 15.083 ;
     RECT  48.84 14.187 49.272 15.083 ;
     RECT  11.04 14.901 11.448 15.093 ;
     RECT  27.24 14.187 27.552 15.093 ;
     RECT  0.144 14.387 0.648 15.107 ;
     RECT  19.392 15.029 19.416 15.107 ;
     RECT  26.688 15.093 27.552 15.155 ;
     RECT  59.28 14.251 59.952 15.155 ;
     RECT  27.24 15.155 27.552 15.157 ;
     RECT  11.04 15.093 11.88 15.203 ;
     RECT  16.44 13.995 16.752 15.205 ;
     RECT  21.12 14.891 22.152 15.205 ;
     RECT  11.04 15.203 11.784 15.211 ;
     RECT  32.544 14.965 33.24 15.251 ;
     RECT  15.936 15.205 16.752 15.275 ;
     RECT  23.28 15.093 23.304 15.275 ;
     RECT  70.128 14.915 72.6 15.301 ;
     RECT  21.12 15.205 22.248 15.339 ;
     RECT  27.24 15.157 27.672 15.339 ;
     RECT  36.864 14.773 37.032 15.349 ;
     RECT  38.04 13.355 38.352 15.349 ;
     RECT  51.264 14.773 51.528 15.349 ;
     RECT  43.44 14.251 43.752 15.397 ;
     RECT  18.24 15.157 18.264 15.403 ;
     RECT  70.128 15.301 72.696 15.403 ;
     RECT  46.704 14.133 46.728 15.443 ;
     RECT  42.768 15.397 43.752 15.467 ;
     RECT  59.328 15.155 59.952 15.467 ;
     RECT  21.648 15.339 22.248 15.491 ;
     RECT  43.44 15.467 43.752 15.541 ;
     RECT  51.168 15.349 51.528 15.541 ;
     RECT  50.688 15.541 51.528 15.595 ;
     RECT  43.44 15.541 43.944 15.635 ;
     RECT  51.264 15.595 51.528 15.635 ;
     RECT  0.24 15.107 0.648 15.669 ;
     RECT  54.24 14.251 54.552 15.669 ;
     RECT  53.568 15.669 54.552 15.731 ;
     RECT  0.24 15.669 0.84 15.779 ;
     RECT  2.256 15.083 2.28 15.787 ;
     RECT  46.944 15.605 46.968 15.787 ;
     RECT  32.544 15.251 32.952 15.797 ;
     RECT  31.872 15.797 32.952 15.875 ;
     RECT  31.344 15.925 31.368 15.979 ;
     RECT  51.264 15.635 51.288 15.979 ;
     RECT  13.056 15.989 13.08 16.021 ;
     RECT  14.688 15.989 14.712 16.053 ;
     RECT  30.384 15.989 30.792 16.053 ;
     RECT  13.056 16.021 13.176 16.067 ;
     RECT  11.04 15.211 11.448 16.069 ;
     RECT  30.336 16.053 30.792 16.069 ;
     RECT  62.784 16.021 62.808 16.069 ;
     RECT  62.448 16.069 62.808 16.107 ;
     RECT  5.64 13.675 5.952 16.117 ;
     RECT  13.152 16.067 13.176 16.117 ;
     RECT  14.688 16.053 14.808 16.117 ;
     RECT  27.24 15.339 27.552 16.117 ;
     RECT  29.088 16.053 29.208 16.117 ;
     RECT  30.24 16.069 30.792 16.117 ;
     RECT  36.864 15.349 38.352 16.117 ;
     RECT  13.152 16.117 14.808 16.163 ;
     RECT  21.744 15.491 22.248 16.163 ;
     RECT  0.24 15.779 0.792 16.165 ;
     RECT  3.312 16.117 4.152 16.171 ;
     RECT  5.136 16.117 5.952 16.171 ;
     RECT  10.944 16.069 11.448 16.171 ;
     RECT  13.776 16.163 14.712 16.171 ;
     RECT  36.432 16.117 38.352 16.171 ;
     RECT  48.84 15.083 49.152 16.181 ;
     RECT  70.128 15.403 72.6 16.213 ;
     RECT  11.04 16.171 11.448 16.245 ;
     RECT  35.856 16.181 35.88 16.259 ;
     RECT  53.712 15.731 54.552 16.259 ;
     RECT  29.088 16.117 30.792 16.299 ;
     RECT  54.096 16.259 54.552 16.299 ;
     RECT  70.08 16.213 72.6 16.309 ;
     RECT  70.032 16.309 72.6 16.363 ;
     RECT  40.08 16.245 40.104 16.373 ;
     RECT  37.056 16.171 38.352 16.403 ;
     RECT  54.24 16.299 54.552 16.405 ;
     RECT  37.152 16.403 38.352 16.427 ;
     RECT  39.984 16.373 40.104 16.427 ;
     RECT  62.448 16.107 62.472 16.427 ;
     RECT  68.352 16.357 68.376 16.427 ;
     RECT  35.328 16.261 35.352 16.437 ;
     RECT  11.04 16.245 11.496 16.451 ;
     RECT  34.656 16.437 35.352 16.491 ;
     RECT  48.84 16.181 49.272 16.491 ;
     RECT  32.64 15.875 32.952 16.501 ;
     RECT  37.536 16.427 38.352 16.501 ;
     RECT  39.984 16.427 40.008 16.501 ;
     RECT  29.664 16.299 30.792 16.547 ;
     RECT  21.744 16.163 22.152 16.549 ;
     RECT  19.968 16.405 19.992 16.555 ;
     RECT  27.12 16.117 27.552 16.555 ;
     RECT  32.64 16.501 33.672 16.555 ;
     RECT  37.536 16.501 40.008 16.555 ;
     RECT  43.44 15.635 43.752 16.565 ;
     RECT  21.648 16.549 22.152 16.619 ;
     RECT  29.664 16.547 30.264 16.619 ;
     RECT  0.144 16.165 0.792 16.747 ;
     RECT  47.28 16.693 47.304 16.787 ;
     RECT  25.632 16.741 25.656 16.811 ;
     RECT  65.04 14.763 65.352 16.821 ;
     RECT  66.768 16.757 66.792 16.821 ;
     RECT  38.04 16.555 38.952 16.835 ;
     RECT  34.656 16.491 34.92 16.837 ;
     RECT  59.64 15.467 59.952 16.837 ;
     RECT  65.04 16.821 66.792 16.883 ;
     RECT  70.128 16.363 72.6 16.939 ;
     RECT  50.16 16.885 50.184 16.979 ;
     RECT  52.416 16.885 52.44 16.979 ;
     RECT  16.44 15.275 16.752 17.013 ;
     RECT  58.608 16.837 59.952 17.013 ;
     RECT  0.144 16.747 0.744 17.027 ;
     RECT  8.496 16.949 8.52 17.027 ;
     RECT  71.76 16.939 72.6 17.027 ;
     RECT  32.64 16.555 32.952 17.029 ;
     RECT  16.44 17.013 17.544 17.075 ;
     RECT  51.984 17.013 52.008 17.075 ;
     RECT  58.512 17.013 60.264 17.075 ;
     RECT  42.72 16.565 43.752 17.077 ;
     RECT  71.808 17.027 72.6 17.077 ;
     RECT  52.992 17.013 53.016 17.123 ;
     RECT  63.84 15.989 63.864 17.171 ;
     RECT  71.808 17.077 72.696 17.259 ;
     RECT  0.144 17.027 0.552 17.267 ;
     RECT  11.04 16.451 11.448 17.267 ;
     RECT  30.24 16.619 30.264 17.315 ;
     RECT  21.84 16.619 22.152 17.461 ;
     RECT  65.04 16.883 65.352 17.557 ;
     RECT  21.84 17.461 22.392 17.589 ;
     RECT  31.632 17.029 32.952 17.589 ;
     RECT  67.92 17.173 67.944 17.589 ;
     RECT  70.128 16.939 70.752 17.589 ;
     RECT  4.128 16.171 4.152 17.603 ;
     RECT  24 17.077 24.024 17.643 ;
     RECT  34.464 16.837 34.92 17.643 ;
     RECT  42.624 17.077 43.752 17.643 ;
     RECT  50.592 17.029 50.904 17.643 ;
     RECT  64.272 17.557 65.352 17.643 ;
     RECT  67.824 17.589 67.944 17.643 ;
     RECT  31.632 17.589 33.192 17.651 ;
     RECT  34.8 17.643 34.824 17.651 ;
     RECT  42.72 17.643 43.752 17.651 ;
     RECT  59.64 17.075 60.264 17.651 ;
     RECT  64.368 17.643 65.352 17.651 ;
     RECT  48.84 16.491 49.152 17.653 ;
     RECT  67.824 17.643 67.848 17.653 ;
     RECT  67.296 17.653 67.848 17.699 ;
     RECT  54.24 16.405 55.272 17.701 ;
     RECT  48.84 17.653 49.56 17.747 ;
     RECT  20.88 17.589 22.488 17.891 ;
     RECT  67.296 17.699 67.32 17.989 ;
     RECT  54.24 17.701 55.368 18.133 ;
     RECT  58.512 17.075 58.632 18.133 ;
     RECT  59.64 17.651 59.952 18.133 ;
     RECT  70.032 17.589 70.752 18.133 ;
     RECT  71.808 17.259 72.552 18.133 ;
     RECT  38.04 16.835 38.352 18.165 ;
     RECT  40.464 18.133 40.488 18.165 ;
     RECT  48.84 17.747 49.152 18.165 ;
     RECT  51.888 18.037 51.912 18.165 ;
     RECT  2.256 17.653 2.28 18.179 ;
     RECT  58.512 18.133 59.952 18.181 ;
     RECT  70.032 18.133 72.552 18.181 ;
     RECT  32.448 17.651 32.952 18.219 ;
     RECT  40.464 18.165 40.584 18.219 ;
     RECT  51.888 18.165 52.008 18.219 ;
     RECT  54 18.133 55.368 18.219 ;
     RECT  67.152 17.989 67.32 18.219 ;
     RECT  54.096 18.219 54.744 18.227 ;
     RECT  27.24 16.555 27.552 18.229 ;
     RECT  21.84 17.891 22.488 18.275 ;
     RECT  37.824 18.165 39.144 18.275 ;
     RECT  40.56 18.219 40.584 18.275 ;
     RECT  69.552 18.181 72.552 18.283 ;
     RECT  67.152 18.219 67.272 18.293 ;
     RECT  66.72 18.293 67.272 18.323 ;
     RECT  48.624 18.165 49.152 18.347 ;
     RECT  51.984 18.219 52.008 18.347 ;
     RECT  54.24 18.227 54.744 18.347 ;
     RECT  60.96 18.181 61.56 18.347 ;
     RECT  0.24 17.267 0.552 18.357 ;
     RECT  11.04 17.267 11.352 18.357 ;
     RECT  66.72 18.323 66.744 18.371 ;
     RECT  61.104 18.347 61.56 18.411 ;
     RECT  38.04 18.275 39.144 18.419 ;
     RECT  69.072 18.357 69.096 18.469 ;
     RECT  46.704 18.421 46.728 18.539 ;
     RECT  68.976 18.469 69.096 18.539 ;
     RECT  70.128 18.283 71.304 18.539 ;
     RECT  11.04 18.357 11.448 18.613 ;
     RECT  43.44 17.651 43.752 18.613 ;
     RECT  10.944 18.613 11.448 18.667 ;
     RECT  45.12 18.613 45.144 18.667 ;
     RECT  43.152 18.613 43.752 18.707 ;
     RECT  11.04 18.667 11.448 18.709 ;
     RECT  20.496 18.661 20.52 18.731 ;
     RECT  13.248 18.565 13.272 18.741 ;
     RECT  43.44 18.707 43.752 18.757 ;
     RECT  11.04 18.709 11.976 18.795 ;
     RECT  35.136 18.709 35.16 18.795 ;
     RECT  0.144 18.357 0.552 18.853 ;
     RECT  13.104 18.741 13.272 18.869 ;
     RECT  13.104 18.869 13.656 18.899 ;
     RECT  8.208 18.853 8.232 18.901 ;
     RECT  0.144 18.853 0.648 18.923 ;
     RECT  43.44 18.757 43.944 18.923 ;
     RECT  13.248 18.899 13.656 18.947 ;
     RECT  8.064 18.901 8.232 18.987 ;
     RECT  18.192 18.933 18.216 18.995 ;
     RECT  50.64 18.869 50.664 18.995 ;
     RECT  58.224 18.181 59.952 18.995 ;
     RECT  21.84 18.275 22.152 19.125 ;
     RECT  9.6 19.061 9.624 19.139 ;
     RECT  21.072 19.125 22.152 19.187 ;
     RECT  63.792 19.125 63.816 19.187 ;
     RECT  8.208 18.987 8.232 19.243 ;
     RECT  23.328 19.189 23.352 19.253 ;
     RECT  70.128 18.539 70.92 19.285 ;
     RECT  26.736 18.229 27.552 19.317 ;
     RECT  23.328 19.253 23.448 19.331 ;
     RECT  16.44 17.075 16.752 19.333 ;
     RECT  69.888 19.285 70.92 19.371 ;
     RECT  72.384 18.283 72.552 19.371 ;
     RECT  4.032 18.613 4.056 19.381 ;
     RECT  5.64 16.171 5.952 19.381 ;
     RECT  54.24 18.347 54.552 19.381 ;
     RECT  3.888 19.381 4.056 19.475 ;
     RECT  26.304 19.317 27.552 19.475 ;
     RECT  54.24 19.381 55.272 19.475 ;
     RECT  3.936 19.475 4.056 19.573 ;
     RECT  5.52 19.381 5.952 19.573 ;
     RECT  65.04 17.651 65.352 19.573 ;
     RECT  70.128 19.371 70.92 19.619 ;
     RECT  32.64 18.219 32.952 19.621 ;
     RECT  56.4 19.573 56.424 19.627 ;
     RECT  2.784 19.573 2.808 19.667 ;
     RECT  3.936 19.573 5.952 19.669 ;
     RECT  41.616 19.621 41.736 19.691 ;
     RECT  38.04 18.419 38.352 19.701 ;
     RECT  39.36 19.621 39.384 19.701 ;
     RECT  72.384 19.371 72.408 19.717 ;
     RECT  3.936 19.669 6.456 19.763 ;
     RECT  37.056 19.701 39.384 19.763 ;
     RECT  51.84 19.701 51.864 19.763 ;
     RECT  32.64 19.621 33.24 19.765 ;
     RECT  70.32 19.619 70.92 19.765 ;
     RECT  72 19.717 72.408 19.765 ;
     RECT  13.248 18.947 13.272 19.811 ;
     RECT  26.784 19.475 27.552 19.811 ;
     RECT  31.92 19.765 33.24 19.811 ;
     RECT  29.184 19.765 29.64 19.819 ;
     RECT  31.92 19.811 32.952 19.819 ;
     RECT  30.768 19.621 30.792 19.859 ;
     RECT  39.36 19.763 39.384 19.859 ;
     RECT  23.328 19.331 23.352 19.883 ;
     RECT  34.8 19.701 34.824 19.883 ;
     RECT  37.056 19.763 38.352 19.883 ;
     RECT  54.24 19.475 55.224 19.947 ;
     RECT  41.712 19.691 41.736 19.955 ;
     RECT  4.56 19.763 6.456 20.003 ;
     RECT  5.088 20.003 6.456 20.051 ;
     RECT  68.832 19.813 68.856 20.213 ;
     RECT  29.568 19.819 29.64 20.277 ;
     RECT  29.568 20.277 30.264 20.339 ;
     RECT  36.528 20.277 36.552 20.339 ;
     RECT  43.44 18.923 43.752 20.341 ;
     RECT  64.416 19.573 65.352 20.389 ;
     RECT  42.72 20.341 43.752 20.395 ;
     RECT  70.32 19.765 72.408 20.469 ;
     RECT  70.32 20.469 72.6 20.531 ;
     RECT  0.144 18.923 0.552 20.533 ;
     RECT  35.136 20.533 35.16 20.627 ;
     RECT  0.144 20.533 0.648 20.629 ;
     RECT  16.44 19.333 17.64 20.677 ;
     RECT  21.84 19.187 22.152 20.677 ;
     RECT  68.832 20.213 69 20.677 ;
     RECT  70.32 20.531 72.504 20.677 ;
     RECT  24.48 20.661 24.504 20.723 ;
     RECT  5.64 20.051 6.456 20.725 ;
     RECT  43.44 20.395 43.752 20.725 ;
     RECT  68.832 20.677 72.504 20.789 ;
     RECT  5.64 20.725 6.504 20.819 ;
     RECT  21.84 20.677 22.248 20.819 ;
     RECT  43.44 20.725 44.52 20.819 ;
     RECT  0.144 20.629 1.368 20.821 ;
     RECT  11.04 18.795 11.352 20.821 ;
     RECT  61.104 18.411 61.128 20.843 ;
     RECT  10.272 20.821 12.264 20.907 ;
     RECT  27.24 19.811 27.552 20.965 ;
     RECT  63.792 20.389 65.352 20.965 ;
     RECT  3.408 20.821 3.432 20.971 ;
     RECT  0.144 20.821 1.656 21.011 ;
     RECT  15.024 20.821 15.048 21.035 ;
     RECT  63.792 20.965 66.072 21.035 ;
     RECT  26.832 20.965 27.552 21.045 ;
     RECT  16.44 20.677 17.688 21.059 ;
     RECT  16.44 21.059 17.592 21.099 ;
     RECT  26.832 21.045 28.536 21.109 ;
     RECT  29.568 20.339 29.64 21.109 ;
     RECT  39.36 20.917 39.384 21.155 ;
     RECT  68.4 20.789 72.504 21.155 ;
     RECT  3.792 21.109 4.584 21.203 ;
     RECT  58.128 21.157 58.152 21.227 ;
     RECT  64.416 21.035 65.448 21.251 ;
     RECT  2.736 21.013 2.76 21.253 ;
     RECT  14.112 21.253 14.136 21.355 ;
     RECT  64.416 21.251 65.352 21.355 ;
     RECT  43.44 20.819 43.752 21.429 ;
     RECT  46.752 21.301 46.776 21.429 ;
     RECT  26.832 21.109 29.64 21.443 ;
     RECT  21.84 20.819 22.152 21.445 ;
     RECT  44.976 21.397 45 21.483 ;
     RECT  46.752 21.429 46.872 21.483 ;
     RECT  66.72 21.301 66.744 21.483 ;
     RECT  69.36 21.155 72.504 21.491 ;
     RECT  69.36 21.491 71.352 21.539 ;
     RECT  11.04 20.907 11.688 21.547 ;
     RECT  41.424 21.445 41.448 21.587 ;
     RECT  42.768 21.429 43.752 21.611 ;
     RECT  46.848 21.483 46.872 21.611 ;
     RECT  31.296 21.429 31.32 21.683 ;
     RECT  29.136 21.443 29.64 21.779 ;
     RECT  21.744 21.445 22.152 21.877 ;
     RECT  3.792 21.203 3.864 21.923 ;
     RECT  29.616 21.779 29.64 21.925 ;
     RECT  20.208 21.829 20.232 21.931 ;
     RECT  21.744 21.877 22.248 21.931 ;
     RECT  48.84 18.347 49.152 21.941 ;
     RECT  29.616 21.925 30.168 21.971 ;
     RECT  26.832 21.443 27.912 21.973 ;
     RECT  51.84 20.773 51.864 21.995 ;
     RECT  5.64 20.819 5.952 22.005 ;
     RECT  2.256 21.253 2.76 22.021 ;
     RECT  26.736 21.973 27.912 22.059 ;
     RECT  5.64 22.005 6.6 22.067 ;
     RECT  11.04 21.547 11.352 22.117 ;
     RECT  38.04 19.883 38.352 22.133 ;
     RECT  27.24 22.059 27.912 22.163 ;
     RECT  48.84 21.941 49.848 22.163 ;
     RECT  37.584 22.133 38.352 22.165 ;
     RECT  72.384 21.491 72.504 22.165 ;
     RECT  66.768 21.877 66.792 22.187 ;
     RECT  2.064 22.021 2.76 22.251 ;
     RECT  10.224 22.117 11.352 22.251 ;
     RECT  13.056 22.069 13.08 22.251 ;
     RECT  30.144 21.971 30.168 22.251 ;
     RECT  37.056 22.165 38.352 22.251 ;
     RECT  47.04 21.637 47.064 22.251 ;
     RECT  7.968 22.197 7.992 22.259 ;
     RECT  72.384 22.165 72.792 22.315 ;
     RECT  65.04 21.355 65.352 22.325 ;
     RECT  16.44 21.099 16.752 22.389 ;
     RECT  18.912 21.925 18.936 22.389 ;
     RECT  18.672 22.389 18.936 22.451 ;
     RECT  24.432 22.389 24.456 22.451 ;
     RECT  15.504 22.389 16.752 22.453 ;
     RECT  15.408 22.453 16.752 22.499 ;
     RECT  14.352 22.197 14.376 22.507 ;
     RECT  15.408 22.499 15.432 22.507 ;
     RECT  2.736 22.251 2.76 22.645 ;
     RECT  43.44 21.611 43.752 22.741 ;
     RECT  68.4 22.325 68.424 22.835 ;
     RECT  70.32 21.539 71.352 22.837 ;
     RECT  72.384 22.315 72.648 22.837 ;
     RECT  3.84 21.923 3.864 22.931 ;
     RECT  18.72 22.451 18.936 22.965 ;
     RECT  20.352 22.933 20.376 22.965 ;
     RECT  43.344 22.741 43.752 22.965 ;
     RECT  54.24 19.947 54.552 22.965 ;
     RECT  55.776 22.549 55.8 22.965 ;
     RECT  70.32 22.837 72.648 22.965 ;
     RECT  43.248 22.965 44.664 22.981 ;
     RECT  20.256 22.965 20.376 23.019 ;
     RECT  64.368 22.325 65.352 23.019 ;
     RECT  18.72 22.965 19.08 23.027 ;
     RECT  20.256 23.019 20.28 23.027 ;
     RECT  57.072 22.965 57.096 23.027 ;
     RECT  0.144 21.011 0.648 23.029 ;
     RECT  5.64 22.067 6.12 23.029 ;
     RECT  43.152 22.981 44.664 23.029 ;
     RECT  54.24 22.965 55.8 23.029 ;
     RECT  42.624 23.029 44.664 23.075 ;
     RECT  0.144 23.029 1.224 23.083 ;
     RECT  5.64 23.029 6.744 23.083 ;
     RECT  9.312 22.885 9.336 23.083 ;
     RECT  53.568 23.029 55.8 23.083 ;
     RECT  64.512 23.019 65.352 23.083 ;
     RECT  68.544 22.885 68.568 23.083 ;
     RECT  39.84 23.029 39.864 23.123 ;
     RECT  42.624 23.075 43.752 23.123 ;
     RECT  64.944 23.083 65.352 23.123 ;
     RECT  52.416 23.029 52.44 23.173 ;
     RECT  42.72 23.123 43.752 23.219 ;
     RECT  52.416 23.173 52.584 23.219 ;
     RECT  19.056 23.027 19.08 23.315 ;
     RECT  70.224 22.965 72.648 23.339 ;
     RECT  21.84 21.931 22.152 23.541 ;
     RECT  27.24 22.163 27.552 23.541 ;
     RECT  2.736 22.645 2.856 23.557 ;
     RECT  52.56 23.219 52.584 23.595 ;
     RECT  54.24 23.083 55.8 23.595 ;
     RECT  2.64 23.557 2.856 23.603 ;
     RECT  26.208 23.541 27.552 23.603 ;
     RECT  70.224 23.339 72.456 23.653 ;
     RECT  46.368 23.605 46.728 23.659 ;
     RECT  18.048 23.605 18.072 23.699 ;
     RECT  2.64 23.603 2.664 23.723 ;
     RECT  21.84 23.541 22.92 23.723 ;
     RECT  26.304 23.603 27.552 23.723 ;
     RECT  0.144 23.083 0.648 23.747 ;
     RECT  7.392 23.733 7.416 23.795 ;
     RECT  21.84 23.723 22.824 23.797 ;
     RECT  31.44 23.701 31.464 23.845 ;
     RECT  32.64 19.819 32.952 23.845 ;
     RECT  21.744 23.797 22.824 23.851 ;
     RECT  31.44 23.845 32.952 23.851 ;
     RECT  21.84 23.851 22.824 23.915 ;
     RECT  26.4 23.723 27.552 23.915 ;
     RECT  31.872 23.851 32.952 23.915 ;
     RECT  36.672 23.845 36.696 23.915 ;
     RECT  66.768 23.669 66.792 23.915 ;
     RECT  16.44 22.499 16.752 23.925 ;
     RECT  15.936 23.925 16.752 23.987 ;
     RECT  62.688 23.925 62.712 23.987 ;
     RECT  20.16 23.925 20.184 23.989 ;
     RECT  20.016 23.989 20.184 24.083 ;
     RECT  54.24 23.595 55.128 24.083 ;
     RECT  20.16 24.083 20.184 24.107 ;
     RECT  68.928 24.053 68.952 24.131 ;
     RECT  70.08 23.653 72.456 24.181 ;
     RECT  69.936 24.181 72.456 24.235 ;
     RECT  59.64 18.995 59.952 24.373 ;
     RECT  58.8 24.373 59.952 24.427 ;
     RECT  70.44 24.235 72.456 24.491 ;
     RECT  32.64 23.915 32.952 24.501 ;
     RECT  2.256 24.181 2.28 24.515 ;
     RECT  14.832 24.181 14.856 24.515 ;
     RECT  3.936 24.437 3.96 24.563 ;
     RECT  32.64 24.501 33.096 24.563 ;
     RECT  41.712 24.501 41.736 24.563 ;
     RECT  5.64 23.083 5.952 24.565 ;
     RECT  43.44 23.219 43.752 24.613 ;
     RECT  3.84 24.565 3.864 24.619 ;
     RECT  5.136 24.565 5.952 24.619 ;
     RECT  11.04 22.251 11.352 24.661 ;
     RECT  43.44 24.613 44.424 24.683 ;
     RECT  47.424 24.277 47.448 24.683 ;
     RECT  27.24 23.915 27.552 24.757 ;
     RECT  0.24 23.747 0.552 24.805 ;
     RECT  10.848 24.661 11.352 24.821 ;
     RECT  46.032 24.629 46.056 24.821 ;
     RECT  0.144 24.805 0.552 24.875 ;
     RECT  46.032 24.821 46.152 24.899 ;
     RECT  34.8 24.469 34.824 24.901 ;
     RECT  38.04 22.251 38.352 24.901 ;
     RECT  51.264 24.853 51.288 24.939 ;
     RECT  34.8 24.901 35.88 25.003 ;
     RECT  37.584 24.901 39.144 25.003 ;
     RECT  40.512 24.469 40.536 25.003 ;
     RECT  69.408 24.949 69.432 25.003 ;
     RECT  27.24 24.757 28.392 25.013 ;
     RECT  30.144 24.501 30.168 25.067 ;
     RECT  10.848 24.821 11.448 25.091 ;
     RECT  27.24 25.013 28.68 25.187 ;
     RECT  34.8 25.003 35.352 25.187 ;
     RECT  11.04 25.091 11.448 25.189 ;
     RECT  11.04 25.189 11.976 25.259 ;
     RECT  27.24 25.187 27.96 25.283 ;
     RECT  70.44 24.491 72.408 25.573 ;
     RECT  69.984 25.573 72.408 25.643 ;
     RECT  70.44 25.643 72.408 25.653 ;
     RECT  70.44 25.653 72.6 25.715 ;
     RECT  72.384 25.715 72.408 25.859 ;
     RECT  70.44 25.715 71.304 26.027 ;
     RECT  5.64 24.619 5.952 39.983 ;
     RECT  11.04 25.259 11.352 39.983 ;
     RECT  16.44 23.987 16.752 39.983 ;
     RECT  21.84 23.915 22.152 39.983 ;
     RECT  27.24 25.283 27.552 39.983 ;
     RECT  32.64 24.563 32.952 39.983 ;
     RECT  38.04 25.003 38.352 39.983 ;
     RECT  43.44 24.683 43.752 39.983 ;
     RECT  48.84 22.163 49.152 39.983 ;
     RECT  54.24 24.083 54.552 39.983 ;
     RECT  59.64 24.427 59.952 39.983 ;
     RECT  65.04 23.123 65.352 39.983 ;
     RECT  70.44 26.027 70.752 39.983 ;
     RECT  0.24 24.875 0.552 40.053 ;
     RECT  0.192 40.053 0.552 40.163 ;
     RECT  0.432 40.163 0.552 40.253 ;
     RECT  5.832 39.983 5.952 40.253 ;
     RECT  11.232 39.983 11.352 40.253 ;
     RECT  16.632 39.983 16.752 40.253 ;
     RECT  22.032 39.983 22.152 40.253 ;
     RECT  27.432 39.983 27.552 40.253 ;
     RECT  32.832 39.983 32.952 40.253 ;
     RECT  38.232 39.983 38.352 40.253 ;
     RECT  43.632 39.983 43.752 40.253 ;
     RECT  49.032 39.983 49.152 40.253 ;
     RECT  54.432 39.983 54.552 40.253 ;
     RECT  59.832 39.983 59.952 40.253 ;
     RECT  65.232 39.983 65.352 40.253 ;
     RECT  70.632 39.983 70.752 40.253 ;
    LAYER M6 ;
     RECT  0 11.796 0.053 12.66 ;
     RECT  0 38.796 0.053 39.66 ;
     RECT  0 0.996 0.133 1.86 ;
     RECT  0 6.396 0.133 7.26 ;
     RECT  0.053 11.796 0.133 13.344 ;
     RECT  0 17.196 0.133 18.06 ;
     RECT  0 22.596 0.133 23.46 ;
     RECT  0.053 38.796 0.227 40.096 ;
     RECT  0.133 0.832 0.613 4.128 ;
     RECT  0.133 5.504 0.613 8.608 ;
     RECT  0.613 0.832 0.659 8.608 ;
     RECT  0.133 9.984 0.659 24.864 ;
     RECT  0.659 21.248 2.629 23.46 ;
     RECT  0.659 24.832 2.629 24.864 ;
     RECT  2.629 21.248 2.725 24.864 ;
     RECT  0.659 9.984 2.773 18.4 ;
     RECT  0.659 19.712 2.773 19.744 ;
     RECT  2.773 9.984 3.397 19.744 ;
     RECT  2.725 21.12 3.397 24.864 ;
     RECT  0.659 0.832 3.509 7.712 ;
     RECT  3.509 0.832 3.779 8.416 ;
     RECT  3.779 0.832 6.517 7.712 ;
     RECT  6.517 0.832 7.381 7.84 ;
     RECT  7.381 0.832 9.061 8.608 ;
     RECT  9.061 0.832 10.213 8.672 ;
     RECT  3.397 9.984 10.213 24.864 ;
     RECT  10.213 0.832 11.941 24.864 ;
     RECT  11.941 0.832 14.387 25.248 ;
     RECT  14.387 0.832 14.963 21.024 ;
     RECT  14.963 0.996 15.059 21.024 ;
     RECT  15.059 0.996 17.557 20.96 ;
     RECT  17.557 0.996 17.643 21.088 ;
     RECT  17.643 0.996 17.651 20.96 ;
     RECT  14.387 22.4 18.707 25.248 ;
     RECT  17.651 0.996 19.909 18.976 ;
     RECT  17.651 20.928 20.021 20.96 ;
     RECT  18.707 22.596 20.021 25.248 ;
     RECT  19.909 0.832 21.061 18.976 ;
     RECT  20.021 20.928 22.259 25.248 ;
     RECT  21.061 0.832 23.317 19.168 ;
     RECT  22.259 20.928 23.317 20.96 ;
     RECT  23.317 0.832 23.893 20.96 ;
     RECT  22.259 22.464 24.421 25.248 ;
     RECT  24.421 22.4 24.491 25.248 ;
     RECT  23.893 0.64 25.621 20.96 ;
     RECT  25.621 0.576 26.725 20.96 ;
     RECT  24.491 22.464 26.725 25.248 ;
     RECT  26.725 0.576 27.971 25.248 ;
     RECT  27.971 0.576 30.179 25.056 ;
     RECT  30.179 0.576 31.861 24.544 ;
     RECT  31.861 0.576 54.709 25.184 ;
     RECT  54.709 0.512 58.739 25.184 ;
     RECT  58.739 0.576 60.373 25.184 ;
     RECT  60.373 0.512 63.971 25.184 ;
     RECT  63.971 0.576 65.459 25.184 ;
     RECT  65.459 0.64 69.429 25.184 ;
     RECT  69.429 0.64 70.163 26.016 ;
     RECT  0 27.996 70.56 28.86 ;
     RECT  0 33.396 70.56 34.26 ;
     RECT  0.227 38.796 70.56 39.66 ;
     RECT  70.163 0.768 71.315 26.016 ;
     RECT  70.56 28.572 71.344 28.86 ;
     RECT  70.56 33.972 71.344 34.26 ;
     RECT  70.56 39.372 71.344 39.66 ;
     RECT  71.315 0.768 72.419 25.824 ;
     RECT  72.419 1.152 72.467 2.72 ;
     RECT  72.419 4.16 72.467 7.904 ;
     RECT  72.419 10.304 72.467 25.696 ;
     RECT  72.467 4.288 72.515 4.32 ;
     RECT  72.467 5.76 72.515 5.792 ;
     RECT  72.467 12.224 72.515 12.256 ;
     RECT  72.467 13.76 72.515 23.328 ;
     RECT  72.515 21.824 72.555 23.328 ;
     RECT  72.467 1.536 72.563 2.592 ;
     RECT  72.467 7.872 72.563 7.904 ;
     RECT  72.515 14.464 72.563 20.512 ;
     RECT  72.563 2.368 72.611 2.592 ;
     RECT  72.563 14.464 72.611 17.248 ;
     RECT  72.563 20.48 72.611 20.512 ;
     RECT  72.467 25.664 72.619 25.696 ;
     RECT  72.555 22.272 72.659 23.328 ;
     RECT  72.611 2.56 72.707 2.592 ;
     RECT  72.611 15.36 72.707 15.392 ;
     RECT  72.611 17.216 72.707 17.248 ;
     RECT  72.467 10.624 72.803 10.656 ;
     RECT  72.659 22.272 72.803 22.304 ;
    LAYER M7 ;
     RECT  71.056 0.531 71.344 0.949 ;
     RECT  71.056 0.949 71.52 1.899 ;
     RECT  49.456 0.531 49.744 1.973 ;
     RECT  60.256 0.531 60.544 2.165 ;
     RECT  11.656 0.531 11.944 2.229 ;
     RECT  22.456 0.531 22.744 2.229 ;
     RECT  71.056 1.899 71.344 2.229 ;
     RECT  70.144 2.229 71.344 2.613 ;
     RECT  11.328 2.229 11.944 2.869 ;
     RECT  58.688 1.973 58.72 3.115 ;
     RECT  30.912 1.973 30.944 3.499 ;
     RECT  48.704 1.973 49.744 3.499 ;
     RECT  3.392 2.357 3.424 3.563 ;
     RECT  46.016 3.381 46.048 3.573 ;
     RECT  60.256 2.165 61.664 3.573 ;
     RECT  51.264 2.549 51.296 3.691 ;
     RECT  13.696 1.397 13.728 3.819 ;
     RECT  59.264 3.573 61.664 3.819 ;
     RECT  11.2 2.869 11.944 3.829 ;
     RECT  59.264 3.819 60.544 3.883 ;
     RECT  35.712 2.677 35.744 4.021 ;
     RECT  35.328 4.021 35.744 4.075 ;
     RECT  46.016 3.573 46.176 4.139 ;
     RECT  70.016 2.613 71.344 4.277 ;
     RECT  27.856 0.531 28.144 4.405 ;
     RECT  69.504 4.277 71.344 4.533 ;
     RECT  22.336 2.229 22.744 4.907 ;
     RECT  27.856 4.405 28.256 5.045 ;
     RECT  20.8 4.085 20.832 5.163 ;
     RECT  38.656 0.531 38.944 5.429 ;
     RECT  30.976 3.829 31.008 5.739 ;
     RECT  69.504 4.533 71.648 5.739 ;
     RECT  38.656 5.429 39.072 5.749 ;
     RECT  69.824 5.739 71.648 5.749 ;
     RECT  69.824 5.749 71.776 5.867 ;
     RECT  6.256 0.531 6.544 5.941 ;
     RECT  35.328 4.075 35.36 5.941 ;
     RECT  35.328 5.941 36.256 5.995 ;
     RECT  6.256 5.941 6.816 6.123 ;
     RECT  38.336 5.749 39.072 6.315 ;
     RECT  42.24 6.197 42.272 6.827 ;
     RECT  31.104 6.197 31.136 6.891 ;
     RECT  36.224 5.995 36.256 6.891 ;
     RECT  70.08 5.867 71.776 6.891 ;
     RECT  14.336 6.197 14.368 7.349 ;
     RECT  14.336 7.349 14.816 7.403 ;
     RECT  33.256 0.531 33.544 7.413 ;
     RECT  6.256 6.123 6.688 7.467 ;
     RECT  10.816 3.829 11.944 7.595 ;
     RECT  70.08 6.891 71.456 7.851 ;
     RECT  33.152 7.413 33.544 8.373 ;
     RECT  3.52 6.773 3.552 8.427 ;
     RECT  14.784 7.403 14.816 8.491 ;
     RECT  56.448 7.413 56.48 8.491 ;
     RECT  32.512 8.373 33.544 8.501 ;
     RECT  52.032 7.413 52.064 8.619 ;
     RECT  70.272 7.851 71.456 8.757 ;
     RECT  38.336 6.315 38.944 9.195 ;
     RECT  32.448 8.501 33.544 9.259 ;
     RECT  63.936 7.861 63.968 9.259 ;
     RECT  70.272 8.757 72.352 9.333 ;
     RECT  32.512 9.259 33.544 9.515 ;
     RECT  17.056 0.531 17.344 9.589 ;
     RECT  25.6 8.821 25.632 9.771 ;
     RECT  41.088 7.925 41.12 9.771 ;
     RECT  44.056 0.531 44.344 10.229 ;
     RECT  54.856 0.531 55.144 10.229 ;
     RECT  59.52 3.883 60.544 10.229 ;
     RECT  33.024 9.515 33.544 10.347 ;
     RECT  68.608 9.589 68.64 10.485 ;
     RECT  70.016 9.333 72.352 10.485 ;
     RECT  18.816 7.861 18.848 10.549 ;
     RECT  18.816 10.549 19.04 10.603 ;
     RECT  62.784 9.653 63.264 10.603 ;
     RECT  51.904 9.013 51.936 10.741 ;
     RECT  68.608 10.485 72.352 10.741 ;
     RECT  62.784 10.603 63.008 10.795 ;
     RECT  54.856 10.229 55.776 10.859 ;
     RECT  58.368 10.229 60.544 10.859 ;
     RECT  68.032 10.741 72.352 10.859 ;
     RECT  44.056 10.229 44.448 10.869 ;
     RECT  43.904 10.869 44.448 10.923 ;
     RECT  46.144 4.139 46.176 10.923 ;
     RECT  51.904 10.741 52.448 10.923 ;
     RECT  68.032 10.859 68.064 10.987 ;
     RECT  16 9.589 17.344 11.115 ;
     RECT  8.768 10.741 8.8 11.435 ;
     RECT  69.568 10.859 72.352 11.435 ;
     RECT  22.456 4.907 22.744 11.509 ;
     RECT  19.008 10.603 19.04 11.563 ;
     RECT  49.456 3.499 49.744 11.637 ;
     RECT  43.904 10.923 44.344 11.691 ;
     RECT  70.016 11.435 71.52 11.691 ;
     RECT  65.656 0.531 65.944 12.149 ;
     RECT  47.296 11.637 47.776 12.213 ;
     RECT  70.144 11.691 71.52 12.587 ;
     RECT  62.976 10.795 63.008 12.779 ;
     RECT  65.656 12.149 66.72 12.779 ;
     RECT  22.456 11.509 22.88 13.035 ;
     RECT  25.024 11.061 25.056 13.035 ;
     RECT  47.104 12.213 47.776 13.035 ;
     RECT  49.456 11.637 50.016 13.099 ;
     RECT  70.144 12.587 71.456 13.163 ;
     RECT  0.856 0.531 1.144 13.301 ;
     RECT  70.72 13.163 71.456 13.483 ;
     RECT  35.264 12.213 35.296 13.611 ;
     RECT  6.256 7.467 6.544 13.621 ;
     RECT  27.856 5.045 29.408 13.685 ;
     RECT  70.784 13.483 71.456 13.803 ;
     RECT  54.856 10.859 55.144 14.069 ;
     RECT  44.056 11.691 44.344 14.197 ;
     RECT  54.528 14.069 55.144 14.197 ;
     RECT  65.656 12.779 65.944 14.709 ;
     RECT  6.256 13.621 6.688 14.955 ;
     RECT  11.008 7.595 11.944 15.147 ;
     RECT  26.688 13.685 29.408 15.147 ;
     RECT  17.056 11.115 17.344 15.157 ;
     RECT  18.752 13.365 18.784 15.157 ;
     RECT  38.656 9.195 38.944 15.349 ;
     RECT  71.056 13.803 71.456 15.349 ;
     RECT  17.056 15.157 18.784 15.403 ;
     RECT  42.752 14.197 44.344 15.467 ;
     RECT  70.912 15.349 71.456 15.605 ;
     RECT  47.104 13.035 47.136 15.659 ;
     RECT  70.912 15.605 72.16 15.861 ;
     RECT  27.856 15.147 29.408 15.925 ;
     RECT  51.2 15.349 51.232 15.925 ;
     RECT  21.12 15.285 21.152 16.043 ;
     RECT  27.856 15.925 30.752 16.107 ;
     RECT  54.4 14.197 55.144 16.235 ;
     RECT  51.2 15.925 51.36 16.363 ;
     RECT  37.376 15.349 38.944 16.427 ;
     RECT  54.528 16.235 55.144 16.491 ;
     RECT  18.752 15.403 18.784 16.501 ;
     RECT  27.856 16.107 29.408 16.501 ;
     RECT  26.752 16.501 29.408 16.555 ;
     RECT  70.336 15.861 72.16 16.619 ;
     RECT  70.336 16.619 71.84 16.821 ;
     RECT  65.472 14.709 65.944 16.875 ;
     RECT  70.144 16.821 71.84 17.003 ;
     RECT  13.824 16.117 13.856 17.067 ;
     RECT  51.328 16.363 51.36 17.067 ;
     RECT  30.72 16.107 30.752 17.131 ;
     RECT  18.752 16.501 20 17.643 ;
     RECT  70.144 17.003 71.456 17.707 ;
     RECT  49.456 13.099 49.744 18.165 ;
     RECT  54.856 16.491 55.144 18.165 ;
     RECT  26.752 16.555 29.152 18.283 ;
     RECT  54.856 18.165 55.264 18.805 ;
     RECT  49.456 18.165 50.656 18.923 ;
     RECT  6.256 14.955 6.544 18.933 ;
     RECT  11.072 15.147 11.944 19.061 ;
     RECT  6.08 18.933 6.544 19.189 ;
     RECT  22.456 13.035 22.744 19.253 ;
     RECT  71.056 17.707 71.456 19.317 ;
     RECT  4.032 18.741 4.064 19.435 ;
     RECT  54.856 18.805 56.416 19.435 ;
     RECT  59.328 10.859 60.544 19.435 ;
     RECT  27.856 18.283 29.152 20.469 ;
     RECT  35.136 18.741 35.168 20.587 ;
     RECT  6.08 19.189 6.688 20.779 ;
     RECT  22.456 19.253 23.456 20.843 ;
     RECT  10.944 19.061 11.944 20.907 ;
     RECT  68.352 20.725 68.384 20.971 ;
     RECT  65.656 16.875 65.944 20.981 ;
     RECT  17.056 15.403 17.344 21.045 ;
     RECT  18.752 17.643 18.784 21.045 ;
     RECT  6.08 20.779 6.544 21.109 ;
     RECT  69.888 19.317 72.544 21.163 ;
     RECT  27.856 20.469 29.6 21.739 ;
     RECT  70.656 21.163 72.544 21.867 ;
     RECT  17.056 21.045 18.784 21.877 ;
     RECT  38.656 16.427 38.944 22.069 ;
     RECT  14.272 20.981 14.304 22.251 ;
     RECT  17.056 21.877 20.064 22.389 ;
     RECT  54.856 19.435 55.264 22.443 ;
     RECT  15.936 22.389 20.064 22.453 ;
     RECT  6.016 21.109 6.544 22.507 ;
     RECT  6.08 22.507 6.544 23.019 ;
     RECT  15.936 22.453 20.192 23.019 ;
     RECT  70.656 21.867 72.288 23.019 ;
     RECT  38.656 22.069 39.904 23.083 ;
     RECT  52.096 21.941 52.128 23.083 ;
     RECT  59.52 19.435 60.544 23.083 ;
     RECT  64.96 20.981 65.944 23.083 ;
     RECT  70.72 23.019 72.288 23.285 ;
     RECT  59.648 23.083 60.544 23.595 ;
     RECT  15.936 23.019 18.08 23.659 ;
     RECT  46.4 22.197 46.432 23.659 ;
     RECT  24.448 22.389 24.48 23.851 ;
     RECT  31.488 23.797 31.52 23.861 ;
     RECT  15.936 23.659 17.344 23.979 ;
     RECT  20.032 23.019 20.192 24.043 ;
     RECT  20.16 24.043 20.192 24.107 ;
     RECT  57.088 22.965 57.12 24.427 ;
     RECT  30.144 22.197 30.176 24.555 ;
     RECT  31.488 23.861 31.904 24.555 ;
     RECT  41.664 15.733 41.696 24.555 ;
     RECT  70.72 23.285 72.608 24.939 ;
     RECT  37.056 22.197 37.088 25.003 ;
     RECT  31.872 24.555 31.904 25.195 ;
     RECT  70.912 24.939 72.608 25.707 ;
     RECT  70.912 25.707 71.344 25.835 ;
     RECT  69.44 24.949 69.472 26.027 ;
     RECT  0.064 13.301 1.144 40.107 ;
     RECT  0.856 40.107 1.144 40.239 ;
     RECT  6.256 23.019 6.544 40.239 ;
     RECT  11.656 20.907 11.944 40.239 ;
     RECT  17.056 23.979 17.344 40.239 ;
     RECT  22.456 20.843 22.744 40.239 ;
     RECT  27.856 21.739 28.144 40.239 ;
     RECT  33.256 10.347 33.544 40.239 ;
     RECT  38.656 23.083 38.944 40.239 ;
     RECT  44.056 15.467 44.344 40.239 ;
     RECT  49.456 18.923 49.744 40.239 ;
     RECT  54.856 22.443 55.144 40.239 ;
     RECT  60.256 23.595 60.544 40.239 ;
     RECT  65.656 23.083 65.944 40.239 ;
     RECT  71.056 25.835 71.344 40.239 ;
  END
END hfd_stn_r38
END LIBRARY
